VERSION 5.8 ;
BUSBITCHARS "[]" ;
DIVIDERCHAR "/" ;
UNITS
    DATABASE MICRONS 1000 ;
END UNITS

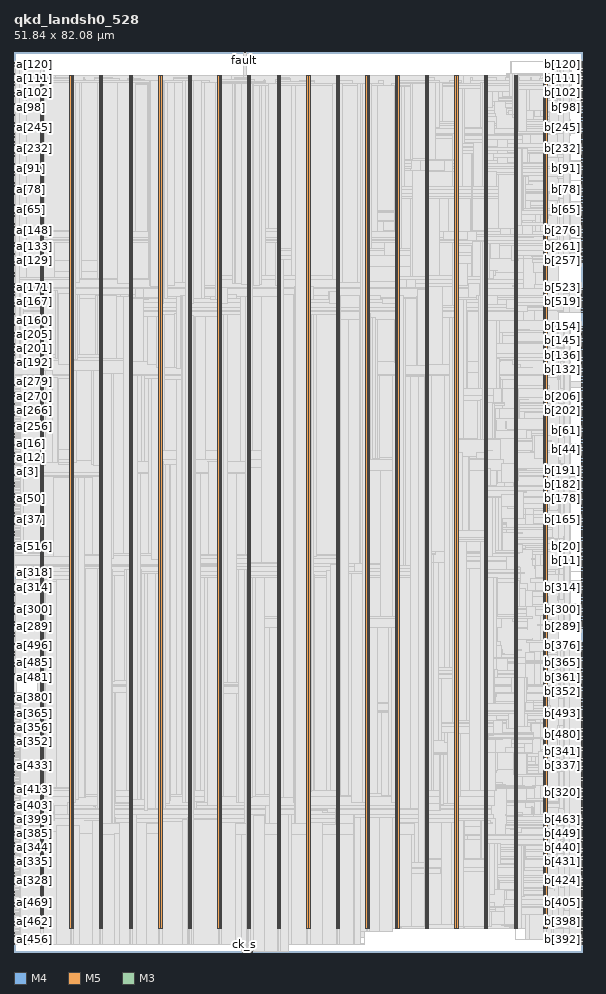
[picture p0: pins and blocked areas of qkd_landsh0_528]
MACRO qkd_landsh0_528
  FOREIGN qkd_landsh0_528 0 0 ;
  CLASS BLOCK ;
  SIZE 51.84 BY 82.08 ;
  PIN a[0]
    DIRECTION INPUT ;
    USE SIGNAL ;
    PORT
      LAYER M4 ;
        RECT  0 43.344 0.084 43.368 ;
    END
  END a[0]
  PIN a[100]
    DIRECTION INPUT ;
    USE SIGNAL ;
    PORT
      LAYER M4 ;
        RECT  0 77.328 0.084 77.352 ;
    END
  END a[100]
  PIN a[101]
    DIRECTION INPUT ;
    USE SIGNAL ;
    PORT
      LAYER M4 ;
        RECT  0 77.472 0.084 77.496 ;
    END
  END a[101]
  PIN a[102]
    DIRECTION INPUT ;
    USE SIGNAL ;
    PORT
      LAYER M4 ;
        RECT  0 77.616 0.084 77.64 ;
    END
  END a[102]
  PIN a[103]
    DIRECTION INPUT ;
    USE SIGNAL ;
    PORT
      LAYER M4 ;
        RECT  0 77.76 0.084 77.784 ;
    END
  END a[103]
  PIN a[104]
    DIRECTION INPUT ;
    USE SIGNAL ;
    PORT
      LAYER M4 ;
        RECT  0 77.904 0.084 77.928 ;
    END
  END a[104]
  PIN a[105]
    DIRECTION INPUT ;
    USE SIGNAL ;
    PORT
      LAYER M4 ;
        RECT  0 78.048 0.084 78.072 ;
    END
  END a[105]
  PIN a[106]
    DIRECTION INPUT ;
    USE SIGNAL ;
    PORT
      LAYER M4 ;
        RECT  0 78.192 0.084 78.216 ;
    END
  END a[106]
  PIN a[107]
    DIRECTION INPUT ;
    USE SIGNAL ;
    PORT
      LAYER M4 ;
        RECT  0 78.336 0.084 78.36 ;
    END
  END a[107]
  PIN a[108]
    DIRECTION INPUT ;
    USE SIGNAL ;
    PORT
      LAYER M4 ;
        RECT  0 78.48 0.084 78.504 ;
    END
  END a[108]
  PIN a[109]
    DIRECTION INPUT ;
    USE SIGNAL ;
    PORT
      LAYER M4 ;
        RECT  0 78.624 0.084 78.648 ;
    END
  END a[109]
  PIN a[10]
    DIRECTION INPUT ;
    USE SIGNAL ;
    PORT
      LAYER M4 ;
        RECT  0 44.784 0.084 44.808 ;
    END
  END a[10]
  PIN a[110]
    DIRECTION INPUT ;
    USE SIGNAL ;
    PORT
      LAYER M4 ;
        RECT  0 78.768 0.084 78.792 ;
    END
  END a[110]
  PIN a[111]
    DIRECTION INPUT ;
    USE SIGNAL ;
    PORT
      LAYER M4 ;
        RECT  0 78.912 0.084 78.936 ;
    END
  END a[111]
  PIN a[112]
    DIRECTION INPUT ;
    USE SIGNAL ;
    PORT
      LAYER M4 ;
        RECT  0 79.056 0.084 79.08 ;
    END
  END a[112]
  PIN a[113]
    DIRECTION INPUT ;
    USE SIGNAL ;
    PORT
      LAYER M4 ;
        RECT  0 79.2 0.084 79.224 ;
    END
  END a[113]
  PIN a[114]
    DIRECTION INPUT ;
    USE SIGNAL ;
    PORT
      LAYER M4 ;
        RECT  0 79.344 0.084 79.368 ;
    END
  END a[114]
  PIN a[115]
    DIRECTION INPUT ;
    USE SIGNAL ;
    PORT
      LAYER M4 ;
        RECT  0 79.488 0.084 79.512 ;
    END
  END a[115]
  PIN a[116]
    DIRECTION INPUT ;
    USE SIGNAL ;
    PORT
      LAYER M4 ;
        RECT  0 79.632 0.084 79.656 ;
    END
  END a[116]
  PIN a[117]
    DIRECTION INPUT ;
    USE SIGNAL ;
    PORT
      LAYER M4 ;
        RECT  0 79.776 0.084 79.8 ;
    END
  END a[117]
  PIN a[118]
    DIRECTION INPUT ;
    USE SIGNAL ;
    PORT
      LAYER M4 ;
        RECT  0 79.92 0.084 79.944 ;
    END
  END a[118]
  PIN a[119]
    DIRECTION INPUT ;
    USE SIGNAL ;
    PORT
      LAYER M4 ;
        RECT  0 80.064 0.084 80.088 ;
    END
  END a[119]
  PIN a[11]
    DIRECTION INPUT ;
    USE SIGNAL ;
    PORT
      LAYER M4 ;
        RECT  0 44.928 0.084 44.952 ;
    END
  END a[11]
  PIN a[120]
    DIRECTION INPUT ;
    USE SIGNAL ;
    PORT
      LAYER M4 ;
        RECT  0 80.208 0.084 80.232 ;
    END
  END a[120]
  PIN a[121]
    DIRECTION INPUT ;
    USE SIGNAL ;
    PORT
      LAYER M4 ;
        RECT  0 80.352 0.084 80.376 ;
    END
  END a[121]
  PIN a[122]
    DIRECTION INPUT ;
    USE SIGNAL ;
    PORT
      LAYER M4 ;
        RECT  0 80.496 0.084 80.52 ;
    END
  END a[122]
  PIN a[123]
    DIRECTION INPUT ;
    USE SIGNAL ;
    PORT
      LAYER M4 ;
        RECT  0 80.64 0.084 80.664 ;
    END
  END a[123]
  PIN a[124]
    DIRECTION INPUT ;
    USE SIGNAL ;
    PORT
      LAYER M4 ;
        RECT  0 80.784 0.084 80.808 ;
    END
  END a[124]
  PIN a[125]
    DIRECTION INPUT ;
    USE SIGNAL ;
    PORT
      LAYER M4 ;
        RECT  0 80.928 0.084 80.952 ;
    END
  END a[125]
  PIN a[126]
    DIRECTION INPUT ;
    USE SIGNAL ;
    PORT
      LAYER M4 ;
        RECT  0 81.072 0.084 81.096 ;
    END
  END a[126]
  PIN a[127]
    DIRECTION INPUT ;
    USE SIGNAL ;
    PORT
      LAYER M4 ;
        RECT  0 81.216 0.084 81.24 ;
    END
  END a[127]
  PIN a[128]
    DIRECTION INPUT ;
    USE SIGNAL ;
    PORT
      LAYER M4 ;
        RECT  0 62.928 0.084 62.952 ;
    END
  END a[128]
  PIN a[129]
    DIRECTION INPUT ;
    USE SIGNAL ;
    PORT
      LAYER M4 ;
        RECT  0 63.072 0.084 63.096 ;
    END
  END a[129]
  PIN a[12]
    DIRECTION INPUT ;
    USE SIGNAL ;
    PORT
      LAYER M4 ;
        RECT  0 45.072 0.084 45.096 ;
    END
  END a[12]
  PIN a[130]
    DIRECTION INPUT ;
    USE SIGNAL ;
    PORT
      LAYER M4 ;
        RECT  0 63.216 0.084 63.24 ;
    END
  END a[130]
  PIN a[131]
    DIRECTION INPUT ;
    USE SIGNAL ;
    PORT
      LAYER M4 ;
        RECT  0 63.36 0.084 63.384 ;
    END
  END a[131]
  PIN a[132]
    DIRECTION INPUT ;
    USE SIGNAL ;
    PORT
      LAYER M4 ;
        RECT  0 63.504 0.084 63.528 ;
    END
  END a[132]
  PIN a[133]
    DIRECTION INPUT ;
    USE SIGNAL ;
    PORT
      LAYER M4 ;
        RECT  0 63.648 0.084 63.672 ;
    END
  END a[133]
  PIN a[134]
    DIRECTION INPUT ;
    USE SIGNAL ;
    PORT
      LAYER M4 ;
        RECT  0 63.792 0.084 63.816 ;
    END
  END a[134]
  PIN a[135]
    DIRECTION INPUT ;
    USE SIGNAL ;
    PORT
      LAYER M4 ;
        RECT  0 63.936 0.084 63.96 ;
    END
  END a[135]
  PIN a[136]
    DIRECTION INPUT ;
    USE SIGNAL ;
    PORT
      LAYER M4 ;
        RECT  0 64.08 0.084 64.104 ;
    END
  END a[136]
  PIN a[137]
    DIRECTION INPUT ;
    USE SIGNAL ;
    PORT
      LAYER M4 ;
        RECT  0 64.224 0.084 64.248 ;
    END
  END a[137]
  PIN a[138]
    DIRECTION INPUT ;
    USE SIGNAL ;
    PORT
      LAYER M4 ;
        RECT  0 64.368 0.084 64.392 ;
    END
  END a[138]
  PIN a[139]
    DIRECTION INPUT ;
    USE SIGNAL ;
    PORT
      LAYER M4 ;
        RECT  0 64.512 0.084 64.536 ;
    END
  END a[139]
  PIN a[13]
    DIRECTION INPUT ;
    USE SIGNAL ;
    PORT
      LAYER M4 ;
        RECT  0 45.216 0.084 45.24 ;
    END
  END a[13]
  PIN a[140]
    DIRECTION INPUT ;
    USE SIGNAL ;
    PORT
      LAYER M4 ;
        RECT  0 64.656 0.084 64.68 ;
    END
  END a[140]
  PIN a[141]
    DIRECTION INPUT ;
    USE SIGNAL ;
    PORT
      LAYER M4 ;
        RECT  0 64.8 0.084 64.824 ;
    END
  END a[141]
  PIN a[142]
    DIRECTION INPUT ;
    USE SIGNAL ;
    PORT
      LAYER M4 ;
        RECT  0 64.944 0.084 64.968 ;
    END
  END a[142]
  PIN a[143]
    DIRECTION INPUT ;
    USE SIGNAL ;
    PORT
      LAYER M4 ;
        RECT  0 65.088 0.084 65.112 ;
    END
  END a[143]
  PIN a[144]
    DIRECTION INPUT ;
    USE SIGNAL ;
    PORT
      LAYER M4 ;
        RECT  0 65.232 0.084 65.256 ;
    END
  END a[144]
  PIN a[145]
    DIRECTION INPUT ;
    USE SIGNAL ;
    PORT
      LAYER M4 ;
        RECT  0 65.376 0.084 65.4 ;
    END
  END a[145]
  PIN a[146]
    DIRECTION INPUT ;
    USE SIGNAL ;
    PORT
      LAYER M4 ;
        RECT  0 65.52 0.084 65.544 ;
    END
  END a[146]
  PIN a[147]
    DIRECTION INPUT ;
    USE SIGNAL ;
    PORT
      LAYER M4 ;
        RECT  0 65.664 0.084 65.688 ;
    END
  END a[147]
  PIN a[148]
    DIRECTION INPUT ;
    USE SIGNAL ;
    PORT
      LAYER M4 ;
        RECT  0 65.808 0.084 65.832 ;
    END
  END a[148]
  PIN a[149]
    DIRECTION INPUT ;
    USE SIGNAL ;
    PORT
      LAYER M4 ;
        RECT  0 65.952 0.084 65.976 ;
    END
  END a[149]
  PIN a[14]
    DIRECTION INPUT ;
    USE SIGNAL ;
    PORT
      LAYER M4 ;
        RECT  0 45.36 0.084 45.384 ;
    END
  END a[14]
  PIN a[150]
    DIRECTION INPUT ;
    USE SIGNAL ;
    PORT
      LAYER M4 ;
        RECT  0 66.096 0.084 66.12 ;
    END
  END a[150]
  PIN a[151]
    DIRECTION INPUT ;
    USE SIGNAL ;
    PORT
      LAYER M4 ;
        RECT  0 66.24 0.084 66.264 ;
    END
  END a[151]
  PIN a[152]
    DIRECTION INPUT ;
    USE SIGNAL ;
    PORT
      LAYER M4 ;
        RECT  0 66.384 0.084 66.408 ;
    END
  END a[152]
  PIN a[153]
    DIRECTION INPUT ;
    USE SIGNAL ;
    PORT
      LAYER M4 ;
        RECT  0 66.528 0.084 66.552 ;
    END
  END a[153]
  PIN a[154]
    DIRECTION INPUT ;
    USE SIGNAL ;
    PORT
      LAYER M4 ;
        RECT  0 66.672 0.084 66.696 ;
    END
  END a[154]
  PIN a[155]
    DIRECTION INPUT ;
    USE SIGNAL ;
    PORT
      LAYER M4 ;
        RECT  0 66.816 0.084 66.84 ;
    END
  END a[155]
  PIN a[156]
    DIRECTION INPUT ;
    USE SIGNAL ;
    PORT
      LAYER M4 ;
        RECT  0 66.96 0.084 66.984 ;
    END
  END a[156]
  PIN a[157]
    DIRECTION INPUT ;
    USE SIGNAL ;
    PORT
      LAYER M4 ;
        RECT  0 67.104 0.084 67.128 ;
    END
  END a[157]
  PIN a[158]
    DIRECTION INPUT ;
    USE SIGNAL ;
    PORT
      LAYER M4 ;
        RECT  0 67.248 0.084 67.272 ;
    END
  END a[158]
  PIN a[159]
    DIRECTION INPUT ;
    USE SIGNAL ;
    PORT
      LAYER M4 ;
        RECT  0 67.392 0.084 67.416 ;
    END
  END a[159]
  PIN a[15]
    DIRECTION INPUT ;
    USE SIGNAL ;
    PORT
      LAYER M4 ;
        RECT  0 45.504 0.084 45.528 ;
    END
  END a[15]
  PIN a[160]
    DIRECTION INPUT ;
    USE SIGNAL ;
    PORT
      LAYER M4 ;
        RECT  0 58.32 0.084 58.344 ;
    END
  END a[160]
  PIN a[161]
    DIRECTION INPUT ;
    USE SIGNAL ;
    PORT
      LAYER M4 ;
        RECT  0 58.464 0.084 58.488 ;
    END
  END a[161]
  PIN a[162]
    DIRECTION INPUT ;
    USE SIGNAL ;
    PORT
      LAYER M4 ;
        RECT  0 58.608 0.084 58.632 ;
    END
  END a[162]
  PIN a[163]
    DIRECTION INPUT ;
    USE SIGNAL ;
    PORT
      LAYER M4 ;
        RECT  0 58.752 0.084 58.776 ;
    END
  END a[163]
  PIN a[164]
    DIRECTION INPUT ;
    USE SIGNAL ;
    PORT
      LAYER M4 ;
        RECT  0 58.896 0.084 58.92 ;
    END
  END a[164]
  PIN a[165]
    DIRECTION INPUT ;
    USE SIGNAL ;
    PORT
      LAYER M4 ;
        RECT  0 59.04 0.084 59.064 ;
    END
  END a[165]
  PIN a[166]
    DIRECTION INPUT ;
    USE SIGNAL ;
    PORT
      LAYER M4 ;
        RECT  0 59.184 0.084 59.208 ;
    END
  END a[166]
  PIN a[167]
    DIRECTION INPUT ;
    USE SIGNAL ;
    PORT
      LAYER M4 ;
        RECT  0 59.328 0.084 59.352 ;
    END
  END a[167]
  PIN a[168]
    DIRECTION INPUT ;
    USE SIGNAL ;
    PORT
      LAYER M4 ;
        RECT  0 59.472 0.084 59.496 ;
    END
  END a[168]
  PIN a[169]
    DIRECTION INPUT ;
    USE SIGNAL ;
    PORT
      LAYER M4 ;
        RECT  0 59.616 0.084 59.64 ;
    END
  END a[169]
  PIN a[16]
    DIRECTION INPUT ;
    USE SIGNAL ;
    PORT
      LAYER M4 ;
        RECT  0 45.648 0.084 45.672 ;
    END
  END a[16]
  PIN a[170]
    DIRECTION INPUT ;
    USE SIGNAL ;
    PORT
      LAYER M4 ;
        RECT  0 59.76 0.084 59.784 ;
    END
  END a[170]
  PIN a[171]
    DIRECTION INPUT ;
    USE SIGNAL ;
    PORT
      LAYER M4 ;
        RECT  0 59.904 0.084 59.928 ;
    END
  END a[171]
  PIN a[172]
    DIRECTION INPUT ;
    USE SIGNAL ;
    PORT
      LAYER M4 ;
        RECT  0 60.048 0.084 60.072 ;
    END
  END a[172]
  PIN a[173]
    DIRECTION INPUT ;
    USE SIGNAL ;
    PORT
      LAYER M4 ;
        RECT  0 60.192 0.084 60.216 ;
    END
  END a[173]
  PIN a[174]
    DIRECTION INPUT ;
    USE SIGNAL ;
    PORT
      LAYER M4 ;
        RECT  0 60.336 0.084 60.36 ;
    END
  END a[174]
  PIN a[175]
    DIRECTION INPUT ;
    USE SIGNAL ;
    PORT
      LAYER M4 ;
        RECT  0 60.48 0.084 60.504 ;
    END
  END a[175]
  PIN a[176]
    DIRECTION INPUT ;
    USE SIGNAL ;
    PORT
      LAYER M4 ;
        RECT  0 60.624 0.084 60.648 ;
    END
  END a[176]
  PIN a[177]
    DIRECTION INPUT ;
    USE SIGNAL ;
    PORT
      LAYER M4 ;
        RECT  0 60.768 0.084 60.792 ;
    END
  END a[177]
  PIN a[178]
    DIRECTION INPUT ;
    USE SIGNAL ;
    PORT
      LAYER M4 ;
        RECT  0 60.912 0.084 60.936 ;
    END
  END a[178]
  PIN a[179]
    DIRECTION INPUT ;
    USE SIGNAL ;
    PORT
      LAYER M4 ;
        RECT  0 61.056 0.084 61.08 ;
    END
  END a[179]
  PIN a[17]
    DIRECTION INPUT ;
    USE SIGNAL ;
    PORT
      LAYER M4 ;
        RECT  0 45.792 0.084 45.816 ;
    END
  END a[17]
  PIN a[180]
    DIRECTION INPUT ;
    USE SIGNAL ;
    PORT
      LAYER M4 ;
        RECT  0 61.2 0.084 61.224 ;
    END
  END a[180]
  PIN a[181]
    DIRECTION INPUT ;
    USE SIGNAL ;
    PORT
      LAYER M4 ;
        RECT  0 61.344 0.084 61.368 ;
    END
  END a[181]
  PIN a[182]
    DIRECTION INPUT ;
    USE SIGNAL ;
    PORT
      LAYER M4 ;
        RECT  0 61.488 0.084 61.512 ;
    END
  END a[182]
  PIN a[183]
    DIRECTION INPUT ;
    USE SIGNAL ;
    PORT
      LAYER M4 ;
        RECT  0 61.632 0.084 61.656 ;
    END
  END a[183]
  PIN a[184]
    DIRECTION INPUT ;
    USE SIGNAL ;
    PORT
      LAYER M4 ;
        RECT  0 61.776 0.084 61.8 ;
    END
  END a[184]
  PIN a[185]
    DIRECTION INPUT ;
    USE SIGNAL ;
    PORT
      LAYER M4 ;
        RECT  0 61.92 0.084 61.944 ;
    END
  END a[185]
  PIN a[186]
    DIRECTION INPUT ;
    USE SIGNAL ;
    PORT
      LAYER M4 ;
        RECT  0 62.064 0.084 62.088 ;
    END
  END a[186]
  PIN a[187]
    DIRECTION INPUT ;
    USE SIGNAL ;
    PORT
      LAYER M4 ;
        RECT  0 62.208 0.084 62.232 ;
    END
  END a[187]
  PIN a[188]
    DIRECTION INPUT ;
    USE SIGNAL ;
    PORT
      LAYER M4 ;
        RECT  0 62.352 0.084 62.376 ;
    END
  END a[188]
  PIN a[189]
    DIRECTION INPUT ;
    USE SIGNAL ;
    PORT
      LAYER M4 ;
        RECT  0 62.496 0.084 62.52 ;
    END
  END a[189]
  PIN a[18]
    DIRECTION INPUT ;
    USE SIGNAL ;
    PORT
      LAYER M4 ;
        RECT  0 45.936 0.084 45.96 ;
    END
  END a[18]
  PIN a[190]
    DIRECTION INPUT ;
    USE SIGNAL ;
    PORT
      LAYER M4 ;
        RECT  0 62.64 0.084 62.664 ;
    END
  END a[190]
  PIN a[191]
    DIRECTION INPUT ;
    USE SIGNAL ;
    PORT
      LAYER M4 ;
        RECT  0 62.784 0.084 62.808 ;
    END
  END a[191]
  PIN a[192]
    DIRECTION INPUT ;
    USE SIGNAL ;
    PORT
      LAYER M4 ;
        RECT  0 53.712 0.084 53.736 ;
    END
  END a[192]
  PIN a[193]
    DIRECTION INPUT ;
    USE SIGNAL ;
    PORT
      LAYER M4 ;
        RECT  0 53.856 0.084 53.88 ;
    END
  END a[193]
  PIN a[194]
    DIRECTION INPUT ;
    USE SIGNAL ;
    PORT
      LAYER M4 ;
        RECT  0 54 0.084 54.024 ;
    END
  END a[194]
  PIN a[195]
    DIRECTION INPUT ;
    USE SIGNAL ;
    PORT
      LAYER M4 ;
        RECT  0 54.144 0.084 54.168 ;
    END
  END a[195]
  PIN a[196]
    DIRECTION INPUT ;
    USE SIGNAL ;
    PORT
      LAYER M4 ;
        RECT  0 54.288 0.084 54.312 ;
    END
  END a[196]
  PIN a[197]
    DIRECTION INPUT ;
    USE SIGNAL ;
    PORT
      LAYER M4 ;
        RECT  0 54.432 0.084 54.456 ;
    END
  END a[197]
  PIN a[198]
    DIRECTION INPUT ;
    USE SIGNAL ;
    PORT
      LAYER M4 ;
        RECT  0 54.576 0.084 54.6 ;
    END
  END a[198]
  PIN a[199]
    DIRECTION INPUT ;
    USE SIGNAL ;
    PORT
      LAYER M4 ;
        RECT  0 54.72 0.084 54.744 ;
    END
  END a[199]
  PIN a[19]
    DIRECTION INPUT ;
    USE SIGNAL ;
    PORT
      LAYER M4 ;
        RECT  0 46.08 0.084 46.104 ;
    END
  END a[19]
  PIN a[1]
    DIRECTION INPUT ;
    USE SIGNAL ;
    PORT
      LAYER M4 ;
        RECT  0 43.488 0.084 43.512 ;
    END
  END a[1]
  PIN a[200]
    DIRECTION INPUT ;
    USE SIGNAL ;
    PORT
      LAYER M4 ;
        RECT  0 54.864 0.084 54.888 ;
    END
  END a[200]
  PIN a[201]
    DIRECTION INPUT ;
    USE SIGNAL ;
    PORT
      LAYER M4 ;
        RECT  0 55.008 0.084 55.032 ;
    END
  END a[201]
  PIN a[202]
    DIRECTION INPUT ;
    USE SIGNAL ;
    PORT
      LAYER M4 ;
        RECT  0 55.152 0.084 55.176 ;
    END
  END a[202]
  PIN a[203]
    DIRECTION INPUT ;
    USE SIGNAL ;
    PORT
      LAYER M4 ;
        RECT  0 55.296 0.084 55.32 ;
    END
  END a[203]
  PIN a[204]
    DIRECTION INPUT ;
    USE SIGNAL ;
    PORT
      LAYER M4 ;
        RECT  0 55.44 0.084 55.464 ;
    END
  END a[204]
  PIN a[205]
    DIRECTION INPUT ;
    USE SIGNAL ;
    PORT
      LAYER M4 ;
        RECT  0 55.584 0.084 55.608 ;
    END
  END a[205]
  PIN a[206]
    DIRECTION INPUT ;
    USE SIGNAL ;
    PORT
      LAYER M4 ;
        RECT  0 55.728 0.084 55.752 ;
    END
  END a[206]
  PIN a[207]
    DIRECTION INPUT ;
    USE SIGNAL ;
    PORT
      LAYER M4 ;
        RECT  0 55.872 0.084 55.896 ;
    END
  END a[207]
  PIN a[208]
    DIRECTION INPUT ;
    USE SIGNAL ;
    PORT
      LAYER M4 ;
        RECT  0 56.016 0.084 56.04 ;
    END
  END a[208]
  PIN a[209]
    DIRECTION INPUT ;
    USE SIGNAL ;
    PORT
      LAYER M4 ;
        RECT  0 56.16 0.084 56.184 ;
    END
  END a[209]
  PIN a[20]
    DIRECTION INPUT ;
    USE SIGNAL ;
    PORT
      LAYER M4 ;
        RECT  0 46.224 0.084 46.248 ;
    END
  END a[20]
  PIN a[210]
    DIRECTION INPUT ;
    USE SIGNAL ;
    PORT
      LAYER M4 ;
        RECT  0 56.304 0.084 56.328 ;
    END
  END a[210]
  PIN a[211]
    DIRECTION INPUT ;
    USE SIGNAL ;
    PORT
      LAYER M4 ;
        RECT  0 56.448 0.084 56.472 ;
    END
  END a[211]
  PIN a[212]
    DIRECTION INPUT ;
    USE SIGNAL ;
    PORT
      LAYER M4 ;
        RECT  0 56.592 0.084 56.616 ;
    END
  END a[212]
  PIN a[213]
    DIRECTION INPUT ;
    USE SIGNAL ;
    PORT
      LAYER M4 ;
        RECT  0 56.736 0.084 56.76 ;
    END
  END a[213]
  PIN a[214]
    DIRECTION INPUT ;
    USE SIGNAL ;
    PORT
      LAYER M4 ;
        RECT  0 56.88 0.084 56.904 ;
    END
  END a[214]
  PIN a[215]
    DIRECTION INPUT ;
    USE SIGNAL ;
    PORT
      LAYER M4 ;
        RECT  0 57.024 0.084 57.048 ;
    END
  END a[215]
  PIN a[216]
    DIRECTION INPUT ;
    USE SIGNAL ;
    PORT
      LAYER M4 ;
        RECT  0 57.168 0.084 57.192 ;
    END
  END a[216]
  PIN a[217]
    DIRECTION INPUT ;
    USE SIGNAL ;
    PORT
      LAYER M4 ;
        RECT  0 57.312 0.084 57.336 ;
    END
  END a[217]
  PIN a[218]
    DIRECTION INPUT ;
    USE SIGNAL ;
    PORT
      LAYER M4 ;
        RECT  0 57.456 0.084 57.48 ;
    END
  END a[218]
  PIN a[219]
    DIRECTION INPUT ;
    USE SIGNAL ;
    PORT
      LAYER M4 ;
        RECT  0 57.6 0.084 57.624 ;
    END
  END a[219]
  PIN a[21]
    DIRECTION INPUT ;
    USE SIGNAL ;
    PORT
      LAYER M4 ;
        RECT  0 46.368 0.084 46.392 ;
    END
  END a[21]
  PIN a[220]
    DIRECTION INPUT ;
    USE SIGNAL ;
    PORT
      LAYER M4 ;
        RECT  0 57.744 0.084 57.768 ;
    END
  END a[220]
  PIN a[221]
    DIRECTION INPUT ;
    USE SIGNAL ;
    PORT
      LAYER M4 ;
        RECT  0 57.888 0.084 57.912 ;
    END
  END a[221]
  PIN a[222]
    DIRECTION INPUT ;
    USE SIGNAL ;
    PORT
      LAYER M4 ;
        RECT  0 58.032 0.084 58.056 ;
    END
  END a[222]
  PIN a[223]
    DIRECTION INPUT ;
    USE SIGNAL ;
    PORT
      LAYER M4 ;
        RECT  0 58.176 0.084 58.2 ;
    END
  END a[223]
  PIN a[224]
    DIRECTION INPUT ;
    USE SIGNAL ;
    PORT
      LAYER M4 ;
        RECT  0 72.144 0.084 72.168 ;
    END
  END a[224]
  PIN a[225]
    DIRECTION INPUT ;
    USE SIGNAL ;
    PORT
      LAYER M4 ;
        RECT  0 72.288 0.084 72.312 ;
    END
  END a[225]
  PIN a[226]
    DIRECTION INPUT ;
    USE SIGNAL ;
    PORT
      LAYER M4 ;
        RECT  0 72.432 0.084 72.456 ;
    END
  END a[226]
  PIN a[227]
    DIRECTION INPUT ;
    USE SIGNAL ;
    PORT
      LAYER M4 ;
        RECT  0 72.576 0.084 72.6 ;
    END
  END a[227]
  PIN a[228]
    DIRECTION INPUT ;
    USE SIGNAL ;
    PORT
      LAYER M4 ;
        RECT  0 72.72 0.084 72.744 ;
    END
  END a[228]
  PIN a[229]
    DIRECTION INPUT ;
    USE SIGNAL ;
    PORT
      LAYER M4 ;
        RECT  0 72.864 0.084 72.888 ;
    END
  END a[229]
  PIN a[22]
    DIRECTION INPUT ;
    USE SIGNAL ;
    PORT
      LAYER M4 ;
        RECT  0 46.512 0.084 46.536 ;
    END
  END a[22]
  PIN a[230]
    DIRECTION INPUT ;
    USE SIGNAL ;
    PORT
      LAYER M4 ;
        RECT  0 73.008 0.084 73.032 ;
    END
  END a[230]
  PIN a[231]
    DIRECTION INPUT ;
    USE SIGNAL ;
    PORT
      LAYER M4 ;
        RECT  0 73.152 0.084 73.176 ;
    END
  END a[231]
  PIN a[232]
    DIRECTION INPUT ;
    USE SIGNAL ;
    PORT
      LAYER M4 ;
        RECT  0 73.296 0.084 73.32 ;
    END
  END a[232]
  PIN a[233]
    DIRECTION INPUT ;
    USE SIGNAL ;
    PORT
      LAYER M4 ;
        RECT  0 73.44 0.084 73.464 ;
    END
  END a[233]
  PIN a[234]
    DIRECTION INPUT ;
    USE SIGNAL ;
    PORT
      LAYER M4 ;
        RECT  0 73.584 0.084 73.608 ;
    END
  END a[234]
  PIN a[235]
    DIRECTION INPUT ;
    USE SIGNAL ;
    PORT
      LAYER M4 ;
        RECT  0 73.728 0.084 73.752 ;
    END
  END a[235]
  PIN a[236]
    DIRECTION INPUT ;
    USE SIGNAL ;
    PORT
      LAYER M4 ;
        RECT  0 73.872 0.084 73.896 ;
    END
  END a[236]
  PIN a[237]
    DIRECTION INPUT ;
    USE SIGNAL ;
    PORT
      LAYER M4 ;
        RECT  0 74.016 0.084 74.04 ;
    END
  END a[237]
  PIN a[238]
    DIRECTION INPUT ;
    USE SIGNAL ;
    PORT
      LAYER M4 ;
        RECT  0 74.16 0.084 74.184 ;
    END
  END a[238]
  PIN a[239]
    DIRECTION INPUT ;
    USE SIGNAL ;
    PORT
      LAYER M4 ;
        RECT  0 74.304 0.084 74.328 ;
    END
  END a[239]
  PIN a[23]
    DIRECTION INPUT ;
    USE SIGNAL ;
    PORT
      LAYER M4 ;
        RECT  0 46.656 0.084 46.68 ;
    END
  END a[23]
  PIN a[240]
    DIRECTION INPUT ;
    USE SIGNAL ;
    PORT
      LAYER M4 ;
        RECT  0 74.448 0.084 74.472 ;
    END
  END a[240]
  PIN a[241]
    DIRECTION INPUT ;
    USE SIGNAL ;
    PORT
      LAYER M4 ;
        RECT  0 74.592 0.084 74.616 ;
    END
  END a[241]
  PIN a[242]
    DIRECTION INPUT ;
    USE SIGNAL ;
    PORT
      LAYER M4 ;
        RECT  0 74.736 0.084 74.76 ;
    END
  END a[242]
  PIN a[243]
    DIRECTION INPUT ;
    USE SIGNAL ;
    PORT
      LAYER M4 ;
        RECT  0 74.88 0.084 74.904 ;
    END
  END a[243]
  PIN a[244]
    DIRECTION INPUT ;
    USE SIGNAL ;
    PORT
      LAYER M4 ;
        RECT  0 75.024 0.084 75.048 ;
    END
  END a[244]
  PIN a[245]
    DIRECTION INPUT ;
    USE SIGNAL ;
    PORT
      LAYER M4 ;
        RECT  0 75.168 0.084 75.192 ;
    END
  END a[245]
  PIN a[246]
    DIRECTION INPUT ;
    USE SIGNAL ;
    PORT
      LAYER M4 ;
        RECT  0 75.312 0.084 75.336 ;
    END
  END a[246]
  PIN a[247]
    DIRECTION INPUT ;
    USE SIGNAL ;
    PORT
      LAYER M4 ;
        RECT  0 75.456 0.084 75.48 ;
    END
  END a[247]
  PIN a[248]
    DIRECTION INPUT ;
    USE SIGNAL ;
    PORT
      LAYER M4 ;
        RECT  0 75.6 0.084 75.624 ;
    END
  END a[248]
  PIN a[249]
    DIRECTION INPUT ;
    USE SIGNAL ;
    PORT
      LAYER M4 ;
        RECT  0 75.744 0.084 75.768 ;
    END
  END a[249]
  PIN a[24]
    DIRECTION INPUT ;
    USE SIGNAL ;
    PORT
      LAYER M4 ;
        RECT  0 46.8 0.084 46.824 ;
    END
  END a[24]
  PIN a[250]
    DIRECTION INPUT ;
    USE SIGNAL ;
    PORT
      LAYER M4 ;
        RECT  0 75.888 0.084 75.912 ;
    END
  END a[250]
  PIN a[251]
    DIRECTION INPUT ;
    USE SIGNAL ;
    PORT
      LAYER M4 ;
        RECT  0 76.032 0.084 76.056 ;
    END
  END a[251]
  PIN a[252]
    DIRECTION INPUT ;
    USE SIGNAL ;
    PORT
      LAYER M4 ;
        RECT  0 76.176 0.084 76.2 ;
    END
  END a[252]
  PIN a[253]
    DIRECTION INPUT ;
    USE SIGNAL ;
    PORT
      LAYER M4 ;
        RECT  0 76.32 0.084 76.344 ;
    END
  END a[253]
  PIN a[254]
    DIRECTION INPUT ;
    USE SIGNAL ;
    PORT
      LAYER M4 ;
        RECT  0 76.464 0.084 76.488 ;
    END
  END a[254]
  PIN a[255]
    DIRECTION INPUT ;
    USE SIGNAL ;
    PORT
      LAYER M4 ;
        RECT  0 76.608 0.084 76.632 ;
    END
  END a[255]
  PIN a[256]
    DIRECTION INPUT ;
    USE SIGNAL ;
    PORT
      LAYER M4 ;
        RECT  0 47.952 0.084 47.976 ;
    END
  END a[256]
  PIN a[257]
    DIRECTION INPUT ;
    USE SIGNAL ;
    PORT
      LAYER M4 ;
        RECT  0 48.096 0.084 48.12 ;
    END
  END a[257]
  PIN a[258]
    DIRECTION INPUT ;
    USE SIGNAL ;
    PORT
      LAYER M4 ;
        RECT  0 48.24 0.084 48.264 ;
    END
  END a[258]
  PIN a[259]
    DIRECTION INPUT ;
    USE SIGNAL ;
    PORT
      LAYER M4 ;
        RECT  0 48.384 0.084 48.408 ;
    END
  END a[259]
  PIN a[25]
    DIRECTION INPUT ;
    USE SIGNAL ;
    PORT
      LAYER M4 ;
        RECT  0 46.944 0.084 46.968 ;
    END
  END a[25]
  PIN a[260]
    DIRECTION INPUT ;
    USE SIGNAL ;
    PORT
      LAYER M4 ;
        RECT  0 48.528 0.084 48.552 ;
    END
  END a[260]
  PIN a[261]
    DIRECTION INPUT ;
    USE SIGNAL ;
    PORT
      LAYER M4 ;
        RECT  0 48.672 0.084 48.696 ;
    END
  END a[261]
  PIN a[262]
    DIRECTION INPUT ;
    USE SIGNAL ;
    PORT
      LAYER M4 ;
        RECT  0 48.816 0.084 48.84 ;
    END
  END a[262]
  PIN a[263]
    DIRECTION INPUT ;
    USE SIGNAL ;
    PORT
      LAYER M4 ;
        RECT  0 48.96 0.084 48.984 ;
    END
  END a[263]
  PIN a[264]
    DIRECTION INPUT ;
    USE SIGNAL ;
    PORT
      LAYER M4 ;
        RECT  0 49.104 0.084 49.128 ;
    END
  END a[264]
  PIN a[265]
    DIRECTION INPUT ;
    USE SIGNAL ;
    PORT
      LAYER M4 ;
        RECT  0 49.248 0.084 49.272 ;
    END
  END a[265]
  PIN a[266]
    DIRECTION INPUT ;
    USE SIGNAL ;
    PORT
      LAYER M4 ;
        RECT  0 49.392 0.084 49.416 ;
    END
  END a[266]
  PIN a[267]
    DIRECTION INPUT ;
    USE SIGNAL ;
    PORT
      LAYER M4 ;
        RECT  0 49.536 0.084 49.56 ;
    END
  END a[267]
  PIN a[268]
    DIRECTION INPUT ;
    USE SIGNAL ;
    PORT
      LAYER M4 ;
        RECT  0 49.68 0.084 49.704 ;
    END
  END a[268]
  PIN a[269]
    DIRECTION INPUT ;
    USE SIGNAL ;
    PORT
      LAYER M4 ;
        RECT  0 49.824 0.084 49.848 ;
    END
  END a[269]
  PIN a[26]
    DIRECTION INPUT ;
    USE SIGNAL ;
    PORT
      LAYER M4 ;
        RECT  0 47.088 0.084 47.112 ;
    END
  END a[26]
  PIN a[270]
    DIRECTION INPUT ;
    USE SIGNAL ;
    PORT
      LAYER M4 ;
        RECT  0 49.968 0.084 49.992 ;
    END
  END a[270]
  PIN a[271]
    DIRECTION INPUT ;
    USE SIGNAL ;
    PORT
      LAYER M4 ;
        RECT  0 50.112 0.084 50.136 ;
    END
  END a[271]
  PIN a[272]
    DIRECTION INPUT ;
    USE SIGNAL ;
    PORT
      LAYER M4 ;
        RECT  0 50.256 0.084 50.28 ;
    END
  END a[272]
  PIN a[273]
    DIRECTION INPUT ;
    USE SIGNAL ;
    PORT
      LAYER M4 ;
        RECT  0 50.4 0.084 50.424 ;
    END
  END a[273]
  PIN a[274]
    DIRECTION INPUT ;
    USE SIGNAL ;
    PORT
      LAYER M4 ;
        RECT  0 50.544 0.084 50.568 ;
    END
  END a[274]
  PIN a[275]
    DIRECTION INPUT ;
    USE SIGNAL ;
    PORT
      LAYER M4 ;
        RECT  0 50.688 0.084 50.712 ;
    END
  END a[275]
  PIN a[276]
    DIRECTION INPUT ;
    USE SIGNAL ;
    PORT
      LAYER M4 ;
        RECT  0 50.832 0.084 50.856 ;
    END
  END a[276]
  PIN a[277]
    DIRECTION INPUT ;
    USE SIGNAL ;
    PORT
      LAYER M4 ;
        RECT  0 50.976 0.084 51 ;
    END
  END a[277]
  PIN a[278]
    DIRECTION INPUT ;
    USE SIGNAL ;
    PORT
      LAYER M4 ;
        RECT  0 51.12 0.084 51.144 ;
    END
  END a[278]
  PIN a[279]
    DIRECTION INPUT ;
    USE SIGNAL ;
    PORT
      LAYER M4 ;
        RECT  0 51.264 0.084 51.288 ;
    END
  END a[279]
  PIN a[27]
    DIRECTION INPUT ;
    USE SIGNAL ;
    PORT
      LAYER M4 ;
        RECT  0 47.232 0.084 47.256 ;
    END
  END a[27]
  PIN a[280]
    DIRECTION INPUT ;
    USE SIGNAL ;
    PORT
      LAYER M4 ;
        RECT  0 51.408 0.084 51.432 ;
    END
  END a[280]
  PIN a[281]
    DIRECTION INPUT ;
    USE SIGNAL ;
    PORT
      LAYER M4 ;
        RECT  0 51.552 0.084 51.576 ;
    END
  END a[281]
  PIN a[282]
    DIRECTION INPUT ;
    USE SIGNAL ;
    PORT
      LAYER M4 ;
        RECT  0 51.696 0.084 51.72 ;
    END
  END a[282]
  PIN a[283]
    DIRECTION INPUT ;
    USE SIGNAL ;
    PORT
      LAYER M4 ;
        RECT  0 51.84 0.084 51.864 ;
    END
  END a[283]
  PIN a[284]
    DIRECTION INPUT ;
    USE SIGNAL ;
    PORT
      LAYER M4 ;
        RECT  0 51.984 0.084 52.008 ;
    END
  END a[284]
  PIN a[285]
    DIRECTION INPUT ;
    USE SIGNAL ;
    PORT
      LAYER M4 ;
        RECT  0 52.128 0.084 52.152 ;
    END
  END a[285]
  PIN a[286]
    DIRECTION INPUT ;
    USE SIGNAL ;
    PORT
      LAYER M4 ;
        RECT  0 52.272 0.084 52.296 ;
    END
  END a[286]
  PIN a[287]
    DIRECTION INPUT ;
    USE SIGNAL ;
    PORT
      LAYER M4 ;
        RECT  0 52.416 0.084 52.44 ;
    END
  END a[287]
  PIN a[288]
    DIRECTION INPUT ;
    USE SIGNAL ;
    PORT
      LAYER M4 ;
        RECT  0 29.52 0.084 29.544 ;
    END
  END a[288]
  PIN a[289]
    DIRECTION INPUT ;
    USE SIGNAL ;
    PORT
      LAYER M4 ;
        RECT  0 29.664 0.084 29.688 ;
    END
  END a[289]
  PIN a[28]
    DIRECTION INPUT ;
    USE SIGNAL ;
    PORT
      LAYER M4 ;
        RECT  0 47.376 0.084 47.4 ;
    END
  END a[28]
  PIN a[290]
    DIRECTION INPUT ;
    USE SIGNAL ;
    PORT
      LAYER M4 ;
        RECT  0 29.808 0.084 29.832 ;
    END
  END a[290]
  PIN a[291]
    DIRECTION INPUT ;
    USE SIGNAL ;
    PORT
      LAYER M4 ;
        RECT  0 29.952 0.084 29.976 ;
    END
  END a[291]
  PIN a[292]
    DIRECTION INPUT ;
    USE SIGNAL ;
    PORT
      LAYER M4 ;
        RECT  0 30.096 0.084 30.12 ;
    END
  END a[292]
  PIN a[293]
    DIRECTION INPUT ;
    USE SIGNAL ;
    PORT
      LAYER M4 ;
        RECT  0 30.24 0.084 30.264 ;
    END
  END a[293]
  PIN a[294]
    DIRECTION INPUT ;
    USE SIGNAL ;
    PORT
      LAYER M4 ;
        RECT  0 30.384 0.084 30.408 ;
    END
  END a[294]
  PIN a[295]
    DIRECTION INPUT ;
    USE SIGNAL ;
    PORT
      LAYER M4 ;
        RECT  0 30.528 0.084 30.552 ;
    END
  END a[295]
  PIN a[296]
    DIRECTION INPUT ;
    USE SIGNAL ;
    PORT
      LAYER M4 ;
        RECT  0 30.672 0.084 30.696 ;
    END
  END a[296]
  PIN a[297]
    DIRECTION INPUT ;
    USE SIGNAL ;
    PORT
      LAYER M4 ;
        RECT  0 30.816 0.084 30.84 ;
    END
  END a[297]
  PIN a[298]
    DIRECTION INPUT ;
    USE SIGNAL ;
    PORT
      LAYER M4 ;
        RECT  0 30.96 0.084 30.984 ;
    END
  END a[298]
  PIN a[299]
    DIRECTION INPUT ;
    USE SIGNAL ;
    PORT
      LAYER M4 ;
        RECT  0 31.104 0.084 31.128 ;
    END
  END a[299]
  PIN a[29]
    DIRECTION INPUT ;
    USE SIGNAL ;
    PORT
      LAYER M4 ;
        RECT  0 47.52 0.084 47.544 ;
    END
  END a[29]
  PIN a[2]
    DIRECTION INPUT ;
    USE SIGNAL ;
    PORT
      LAYER M4 ;
        RECT  0 43.632 0.084 43.656 ;
    END
  END a[2]
  PIN a[300]
    DIRECTION INPUT ;
    USE SIGNAL ;
    PORT
      LAYER M4 ;
        RECT  0 31.248 0.084 31.272 ;
    END
  END a[300]
  PIN a[301]
    DIRECTION INPUT ;
    USE SIGNAL ;
    PORT
      LAYER M4 ;
        RECT  0 31.392 0.084 31.416 ;
    END
  END a[301]
  PIN a[302]
    DIRECTION INPUT ;
    USE SIGNAL ;
    PORT
      LAYER M4 ;
        RECT  0 31.536 0.084 31.56 ;
    END
  END a[302]
  PIN a[303]
    DIRECTION INPUT ;
    USE SIGNAL ;
    PORT
      LAYER M4 ;
        RECT  0 31.68 0.084 31.704 ;
    END
  END a[303]
  PIN a[304]
    DIRECTION INPUT ;
    USE SIGNAL ;
    PORT
      LAYER M4 ;
        RECT  0 31.824 0.084 31.848 ;
    END
  END a[304]
  PIN a[305]
    DIRECTION INPUT ;
    USE SIGNAL ;
    PORT
      LAYER M4 ;
        RECT  0 31.968 0.084 31.992 ;
    END
  END a[305]
  PIN a[306]
    DIRECTION INPUT ;
    USE SIGNAL ;
    PORT
      LAYER M4 ;
        RECT  0 32.112 0.084 32.136 ;
    END
  END a[306]
  PIN a[307]
    DIRECTION INPUT ;
    USE SIGNAL ;
    PORT
      LAYER M4 ;
        RECT  0 32.256 0.084 32.28 ;
    END
  END a[307]
  PIN a[308]
    DIRECTION INPUT ;
    USE SIGNAL ;
    PORT
      LAYER M4 ;
        RECT  0 32.4 0.084 32.424 ;
    END
  END a[308]
  PIN a[309]
    DIRECTION INPUT ;
    USE SIGNAL ;
    PORT
      LAYER M4 ;
        RECT  0 32.544 0.084 32.568 ;
    END
  END a[309]
  PIN a[30]
    DIRECTION INPUT ;
    USE SIGNAL ;
    PORT
      LAYER M4 ;
        RECT  0 47.664 0.084 47.688 ;
    END
  END a[30]
  PIN a[310]
    DIRECTION INPUT ;
    USE SIGNAL ;
    PORT
      LAYER M4 ;
        RECT  0 32.688 0.084 32.712 ;
    END
  END a[310]
  PIN a[311]
    DIRECTION INPUT ;
    USE SIGNAL ;
    PORT
      LAYER M4 ;
        RECT  0 32.832 0.084 32.856 ;
    END
  END a[311]
  PIN a[312]
    DIRECTION INPUT ;
    USE SIGNAL ;
    PORT
      LAYER M4 ;
        RECT  0 32.976 0.084 33 ;
    END
  END a[312]
  PIN a[313]
    DIRECTION INPUT ;
    USE SIGNAL ;
    PORT
      LAYER M4 ;
        RECT  0 33.12 0.084 33.144 ;
    END
  END a[313]
  PIN a[314]
    DIRECTION INPUT ;
    USE SIGNAL ;
    PORT
      LAYER M4 ;
        RECT  0 33.264 0.084 33.288 ;
    END
  END a[314]
  PIN a[315]
    DIRECTION INPUT ;
    USE SIGNAL ;
    PORT
      LAYER M4 ;
        RECT  0 33.408 0.084 33.432 ;
    END
  END a[315]
  PIN a[316]
    DIRECTION INPUT ;
    USE SIGNAL ;
    PORT
      LAYER M4 ;
        RECT  0 33.552 0.084 33.576 ;
    END
  END a[316]
  PIN a[317]
    DIRECTION INPUT ;
    USE SIGNAL ;
    PORT
      LAYER M4 ;
        RECT  0 33.696 0.084 33.72 ;
    END
  END a[317]
  PIN a[318]
    DIRECTION INPUT ;
    USE SIGNAL ;
    PORT
      LAYER M4 ;
        RECT  0 33.84 0.084 33.864 ;
    END
  END a[318]
  PIN a[319]
    DIRECTION INPUT ;
    USE SIGNAL ;
    PORT
      LAYER M4 ;
        RECT  0 33.984 0.084 34.008 ;
    END
  END a[319]
  PIN a[31]
    DIRECTION INPUT ;
    USE SIGNAL ;
    PORT
      LAYER M4 ;
        RECT  0 47.808 0.084 47.832 ;
    END
  END a[31]
  PIN a[320]
    DIRECTION INPUT ;
    USE SIGNAL ;
    PORT
      LAYER M4 ;
        RECT  0 5.328 0.084 5.352 ;
    END
  END a[320]
  PIN a[321]
    DIRECTION INPUT ;
    USE SIGNAL ;
    PORT
      LAYER M4 ;
        RECT  0 5.472 0.084 5.496 ;
    END
  END a[321]
  PIN a[322]
    DIRECTION INPUT ;
    USE SIGNAL ;
    PORT
      LAYER M4 ;
        RECT  0 5.616 0.084 5.64 ;
    END
  END a[322]
  PIN a[323]
    DIRECTION INPUT ;
    USE SIGNAL ;
    PORT
      LAYER M4 ;
        RECT  0 5.76 0.084 5.784 ;
    END
  END a[323]
  PIN a[324]
    DIRECTION INPUT ;
    USE SIGNAL ;
    PORT
      LAYER M4 ;
        RECT  0 5.904 0.084 5.928 ;
    END
  END a[324]
  PIN a[325]
    DIRECTION INPUT ;
    USE SIGNAL ;
    PORT
      LAYER M4 ;
        RECT  0 6.048 0.084 6.072 ;
    END
  END a[325]
  PIN a[326]
    DIRECTION INPUT ;
    USE SIGNAL ;
    PORT
      LAYER M4 ;
        RECT  0 6.192 0.084 6.216 ;
    END
  END a[326]
  PIN a[327]
    DIRECTION INPUT ;
    USE SIGNAL ;
    PORT
      LAYER M4 ;
        RECT  0 6.336 0.084 6.36 ;
    END
  END a[327]
  PIN a[328]
    DIRECTION INPUT ;
    USE SIGNAL ;
    PORT
      LAYER M4 ;
        RECT  0 6.48 0.084 6.504 ;
    END
  END a[328]
  PIN a[329]
    DIRECTION INPUT ;
    USE SIGNAL ;
    PORT
      LAYER M4 ;
        RECT  0 6.624 0.084 6.648 ;
    END
  END a[329]
  PIN a[32]
    DIRECTION INPUT ;
    USE SIGNAL ;
    PORT
      LAYER M4 ;
        RECT  0 38.736 0.084 38.76 ;
    END
  END a[32]
  PIN a[330]
    DIRECTION INPUT ;
    USE SIGNAL ;
    PORT
      LAYER M4 ;
        RECT  0 6.768 0.084 6.792 ;
    END
  END a[330]
  PIN a[331]
    DIRECTION INPUT ;
    USE SIGNAL ;
    PORT
      LAYER M4 ;
        RECT  0 6.912 0.084 6.936 ;
    END
  END a[331]
  PIN a[332]
    DIRECTION INPUT ;
    USE SIGNAL ;
    PORT
      LAYER M4 ;
        RECT  0 7.056 0.084 7.08 ;
    END
  END a[332]
  PIN a[333]
    DIRECTION INPUT ;
    USE SIGNAL ;
    PORT
      LAYER M4 ;
        RECT  0 7.2 0.084 7.224 ;
    END
  END a[333]
  PIN a[334]
    DIRECTION INPUT ;
    USE SIGNAL ;
    PORT
      LAYER M4 ;
        RECT  0 7.344 0.084 7.368 ;
    END
  END a[334]
  PIN a[335]
    DIRECTION INPUT ;
    USE SIGNAL ;
    PORT
      LAYER M4 ;
        RECT  0 7.488 0.084 7.512 ;
    END
  END a[335]
  PIN a[336]
    DIRECTION INPUT ;
    USE SIGNAL ;
    PORT
      LAYER M4 ;
        RECT  0 7.632 0.084 7.656 ;
    END
  END a[336]
  PIN a[337]
    DIRECTION INPUT ;
    USE SIGNAL ;
    PORT
      LAYER M4 ;
        RECT  0 7.776 0.084 7.8 ;
    END
  END a[337]
  PIN a[338]
    DIRECTION INPUT ;
    USE SIGNAL ;
    PORT
      LAYER M4 ;
        RECT  0 7.92 0.084 7.944 ;
    END
  END a[338]
  PIN a[339]
    DIRECTION INPUT ;
    USE SIGNAL ;
    PORT
      LAYER M4 ;
        RECT  0 8.064 0.084 8.088 ;
    END
  END a[339]
  PIN a[33]
    DIRECTION INPUT ;
    USE SIGNAL ;
    PORT
      LAYER M4 ;
        RECT  0 38.88 0.084 38.904 ;
    END
  END a[33]
  PIN a[340]
    DIRECTION INPUT ;
    USE SIGNAL ;
    PORT
      LAYER M4 ;
        RECT  0 8.208 0.084 8.232 ;
    END
  END a[340]
  PIN a[341]
    DIRECTION INPUT ;
    USE SIGNAL ;
    PORT
      LAYER M4 ;
        RECT  0 8.352 0.084 8.376 ;
    END
  END a[341]
  PIN a[342]
    DIRECTION INPUT ;
    USE SIGNAL ;
    PORT
      LAYER M4 ;
        RECT  0 8.496 0.084 8.52 ;
    END
  END a[342]
  PIN a[343]
    DIRECTION INPUT ;
    USE SIGNAL ;
    PORT
      LAYER M4 ;
        RECT  0 8.64 0.084 8.664 ;
    END
  END a[343]
  PIN a[344]
    DIRECTION INPUT ;
    USE SIGNAL ;
    PORT
      LAYER M4 ;
        RECT  0 8.784 0.084 8.808 ;
    END
  END a[344]
  PIN a[345]
    DIRECTION INPUT ;
    USE SIGNAL ;
    PORT
      LAYER M4 ;
        RECT  0 8.928 0.084 8.952 ;
    END
  END a[345]
  PIN a[346]
    DIRECTION INPUT ;
    USE SIGNAL ;
    PORT
      LAYER M4 ;
        RECT  0 9.072 0.084 9.096 ;
    END
  END a[346]
  PIN a[347]
    DIRECTION INPUT ;
    USE SIGNAL ;
    PORT
      LAYER M4 ;
        RECT  0 9.216 0.084 9.24 ;
    END
  END a[347]
  PIN a[348]
    DIRECTION INPUT ;
    USE SIGNAL ;
    PORT
      LAYER M4 ;
        RECT  0 9.36 0.084 9.384 ;
    END
  END a[348]
  PIN a[349]
    DIRECTION INPUT ;
    USE SIGNAL ;
    PORT
      LAYER M4 ;
        RECT  0 9.504 0.084 9.528 ;
    END
  END a[349]
  PIN a[34]
    DIRECTION INPUT ;
    USE SIGNAL ;
    PORT
      LAYER M4 ;
        RECT  0 39.024 0.084 39.048 ;
    END
  END a[34]
  PIN a[350]
    DIRECTION INPUT ;
    USE SIGNAL ;
    PORT
      LAYER M4 ;
        RECT  0 9.648 0.084 9.672 ;
    END
  END a[350]
  PIN a[351]
    DIRECTION INPUT ;
    USE SIGNAL ;
    PORT
      LAYER M4 ;
        RECT  0 9.792 0.084 9.816 ;
    END
  END a[351]
  PIN a[352]
    DIRECTION INPUT ;
    USE SIGNAL ;
    PORT
      LAYER M4 ;
        RECT  0 19.152 0.084 19.176 ;
    END
  END a[352]
  PIN a[353]
    DIRECTION INPUT ;
    USE SIGNAL ;
    PORT
      LAYER M4 ;
        RECT  0 19.296 0.084 19.32 ;
    END
  END a[353]
  PIN a[354]
    DIRECTION INPUT ;
    USE SIGNAL ;
    PORT
      LAYER M4 ;
        RECT  0 19.44 0.084 19.464 ;
    END
  END a[354]
  PIN a[355]
    DIRECTION INPUT ;
    USE SIGNAL ;
    PORT
      LAYER M4 ;
        RECT  0 19.584 0.084 19.608 ;
    END
  END a[355]
  PIN a[356]
    DIRECTION INPUT ;
    USE SIGNAL ;
    PORT
      LAYER M4 ;
        RECT  0 19.728 0.084 19.752 ;
    END
  END a[356]
  PIN a[357]
    DIRECTION INPUT ;
    USE SIGNAL ;
    PORT
      LAYER M4 ;
        RECT  0 19.872 0.084 19.896 ;
    END
  END a[357]
  PIN a[358]
    DIRECTION INPUT ;
    USE SIGNAL ;
    PORT
      LAYER M4 ;
        RECT  0 20.016 0.084 20.04 ;
    END
  END a[358]
  PIN a[359]
    DIRECTION INPUT ;
    USE SIGNAL ;
    PORT
      LAYER M4 ;
        RECT  0 20.16 0.084 20.184 ;
    END
  END a[359]
  PIN a[35]
    DIRECTION INPUT ;
    USE SIGNAL ;
    PORT
      LAYER M4 ;
        RECT  0 39.168 0.084 39.192 ;
    END
  END a[35]
  PIN a[360]
    DIRECTION INPUT ;
    USE SIGNAL ;
    PORT
      LAYER M4 ;
        RECT  0 20.304 0.084 20.328 ;
    END
  END a[360]
  PIN a[361]
    DIRECTION INPUT ;
    USE SIGNAL ;
    PORT
      LAYER M4 ;
        RECT  0 20.448 0.084 20.472 ;
    END
  END a[361]
  PIN a[362]
    DIRECTION INPUT ;
    USE SIGNAL ;
    PORT
      LAYER M4 ;
        RECT  0 20.592 0.084 20.616 ;
    END
  END a[362]
  PIN a[363]
    DIRECTION INPUT ;
    USE SIGNAL ;
    PORT
      LAYER M4 ;
        RECT  0 20.736 0.084 20.76 ;
    END
  END a[363]
  PIN a[364]
    DIRECTION INPUT ;
    USE SIGNAL ;
    PORT
      LAYER M4 ;
        RECT  0 20.88 0.084 20.904 ;
    END
  END a[364]
  PIN a[365]
    DIRECTION INPUT ;
    USE SIGNAL ;
    PORT
      LAYER M4 ;
        RECT  0 21.024 0.084 21.048 ;
    END
  END a[365]
  PIN a[366]
    DIRECTION INPUT ;
    USE SIGNAL ;
    PORT
      LAYER M4 ;
        RECT  0 21.168 0.084 21.192 ;
    END
  END a[366]
  PIN a[367]
    DIRECTION INPUT ;
    USE SIGNAL ;
    PORT
      LAYER M4 ;
        RECT  0 21.312 0.084 21.336 ;
    END
  END a[367]
  PIN a[368]
    DIRECTION INPUT ;
    USE SIGNAL ;
    PORT
      LAYER M4 ;
        RECT  0 21.456 0.084 21.48 ;
    END
  END a[368]
  PIN a[369]
    DIRECTION INPUT ;
    USE SIGNAL ;
    PORT
      LAYER M4 ;
        RECT  0 21.6 0.084 21.624 ;
    END
  END a[369]
  PIN a[36]
    DIRECTION INPUT ;
    USE SIGNAL ;
    PORT
      LAYER M4 ;
        RECT  0 39.312 0.084 39.336 ;
    END
  END a[36]
  PIN a[370]
    DIRECTION INPUT ;
    USE SIGNAL ;
    PORT
      LAYER M4 ;
        RECT  0 21.744 0.084 21.768 ;
    END
  END a[370]
  PIN a[371]
    DIRECTION INPUT ;
    USE SIGNAL ;
    PORT
      LAYER M4 ;
        RECT  0 21.888 0.084 21.912 ;
    END
  END a[371]
  PIN a[372]
    DIRECTION INPUT ;
    USE SIGNAL ;
    PORT
      LAYER M4 ;
        RECT  0 22.032 0.084 22.056 ;
    END
  END a[372]
  PIN a[373]
    DIRECTION INPUT ;
    USE SIGNAL ;
    PORT
      LAYER M4 ;
        RECT  0 22.176 0.084 22.2 ;
    END
  END a[373]
  PIN a[374]
    DIRECTION INPUT ;
    USE SIGNAL ;
    PORT
      LAYER M4 ;
        RECT  0 22.32 0.084 22.344 ;
    END
  END a[374]
  PIN a[375]
    DIRECTION INPUT ;
    USE SIGNAL ;
    PORT
      LAYER M4 ;
        RECT  0 22.464 0.084 22.488 ;
    END
  END a[375]
  PIN a[376]
    DIRECTION INPUT ;
    USE SIGNAL ;
    PORT
      LAYER M4 ;
        RECT  0 22.608 0.084 22.632 ;
    END
  END a[376]
  PIN a[377]
    DIRECTION INPUT ;
    USE SIGNAL ;
    PORT
      LAYER M4 ;
        RECT  0 22.752 0.084 22.776 ;
    END
  END a[377]
  PIN a[378]
    DIRECTION INPUT ;
    USE SIGNAL ;
    PORT
      LAYER M4 ;
        RECT  0 22.896 0.084 22.92 ;
    END
  END a[378]
  PIN a[379]
    DIRECTION INPUT ;
    USE SIGNAL ;
    PORT
      LAYER M4 ;
        RECT  0 23.04 0.084 23.064 ;
    END
  END a[379]
  PIN a[37]
    DIRECTION INPUT ;
    USE SIGNAL ;
    PORT
      LAYER M4 ;
        RECT  0 39.456 0.084 39.48 ;
    END
  END a[37]
  PIN a[380]
    DIRECTION INPUT ;
    USE SIGNAL ;
    PORT
      LAYER M4 ;
        RECT  0 23.184 0.084 23.208 ;
    END
  END a[380]
  PIN a[381]
    DIRECTION INPUT ;
    USE SIGNAL ;
    PORT
      LAYER M4 ;
        RECT  0 23.328 0.084 23.352 ;
    END
  END a[381]
  PIN a[382]
    DIRECTION INPUT ;
    USE SIGNAL ;
    PORT
      LAYER M4 ;
        RECT  0 23.472 0.084 23.496 ;
    END
  END a[382]
  PIN a[383]
    DIRECTION INPUT ;
    USE SIGNAL ;
    PORT
      LAYER M4 ;
        RECT  0 23.616 0.084 23.64 ;
    END
  END a[383]
  PIN a[384]
    DIRECTION INPUT ;
    USE SIGNAL ;
    PORT
      LAYER M4 ;
        RECT  0 9.936 0.084 9.96 ;
    END
  END a[384]
  PIN a[385]
    DIRECTION INPUT ;
    USE SIGNAL ;
    PORT
      LAYER M4 ;
        RECT  0 10.08 0.084 10.104 ;
    END
  END a[385]
  PIN a[386]
    DIRECTION INPUT ;
    USE SIGNAL ;
    PORT
      LAYER M4 ;
        RECT  0 10.224 0.084 10.248 ;
    END
  END a[386]
  PIN a[387]
    DIRECTION INPUT ;
    USE SIGNAL ;
    PORT
      LAYER M4 ;
        RECT  0 10.368 0.084 10.392 ;
    END
  END a[387]
  PIN a[388]
    DIRECTION INPUT ;
    USE SIGNAL ;
    PORT
      LAYER M4 ;
        RECT  0 10.512 0.084 10.536 ;
    END
  END a[388]
  PIN a[389]
    DIRECTION INPUT ;
    USE SIGNAL ;
    PORT
      LAYER M4 ;
        RECT  0 10.656 0.084 10.68 ;
    END
  END a[389]
  PIN a[38]
    DIRECTION INPUT ;
    USE SIGNAL ;
    PORT
      LAYER M4 ;
        RECT  0 39.6 0.084 39.624 ;
    END
  END a[38]
  PIN a[390]
    DIRECTION INPUT ;
    USE SIGNAL ;
    PORT
      LAYER M4 ;
        RECT  0 10.8 0.084 10.824 ;
    END
  END a[390]
  PIN a[391]
    DIRECTION INPUT ;
    USE SIGNAL ;
    PORT
      LAYER M4 ;
        RECT  0 10.944 0.084 10.968 ;
    END
  END a[391]
  PIN a[392]
    DIRECTION INPUT ;
    USE SIGNAL ;
    PORT
      LAYER M4 ;
        RECT  0 11.088 0.084 11.112 ;
    END
  END a[392]
  PIN a[393]
    DIRECTION INPUT ;
    USE SIGNAL ;
    PORT
      LAYER M4 ;
        RECT  0 11.232 0.084 11.256 ;
    END
  END a[393]
  PIN a[394]
    DIRECTION INPUT ;
    USE SIGNAL ;
    PORT
      LAYER M4 ;
        RECT  0 11.376 0.084 11.4 ;
    END
  END a[394]
  PIN a[395]
    DIRECTION INPUT ;
    USE SIGNAL ;
    PORT
      LAYER M4 ;
        RECT  0 11.52 0.084 11.544 ;
    END
  END a[395]
  PIN a[396]
    DIRECTION INPUT ;
    USE SIGNAL ;
    PORT
      LAYER M4 ;
        RECT  0 11.664 0.084 11.688 ;
    END
  END a[396]
  PIN a[397]
    DIRECTION INPUT ;
    USE SIGNAL ;
    PORT
      LAYER M4 ;
        RECT  0 11.808 0.084 11.832 ;
    END
  END a[397]
  PIN a[398]
    DIRECTION INPUT ;
    USE SIGNAL ;
    PORT
      LAYER M4 ;
        RECT  0 11.952 0.084 11.976 ;
    END
  END a[398]
  PIN a[399]
    DIRECTION INPUT ;
    USE SIGNAL ;
    PORT
      LAYER M4 ;
        RECT  0 12.096 0.084 12.12 ;
    END
  END a[399]
  PIN a[39]
    DIRECTION INPUT ;
    USE SIGNAL ;
    PORT
      LAYER M4 ;
        RECT  0 39.744 0.084 39.768 ;
    END
  END a[39]
  PIN a[3]
    DIRECTION INPUT ;
    USE SIGNAL ;
    PORT
      LAYER M4 ;
        RECT  0 43.776 0.084 43.8 ;
    END
  END a[3]
  PIN a[400]
    DIRECTION INPUT ;
    USE SIGNAL ;
    PORT
      LAYER M4 ;
        RECT  0 12.24 0.084 12.264 ;
    END
  END a[400]
  PIN a[401]
    DIRECTION INPUT ;
    USE SIGNAL ;
    PORT
      LAYER M4 ;
        RECT  0 12.384 0.084 12.408 ;
    END
  END a[401]
  PIN a[402]
    DIRECTION INPUT ;
    USE SIGNAL ;
    PORT
      LAYER M4 ;
        RECT  0 12.528 0.084 12.552 ;
    END
  END a[402]
  PIN a[403]
    DIRECTION INPUT ;
    USE SIGNAL ;
    PORT
      LAYER M4 ;
        RECT  0 12.672 0.084 12.696 ;
    END
  END a[403]
  PIN a[404]
    DIRECTION INPUT ;
    USE SIGNAL ;
    PORT
      LAYER M4 ;
        RECT  0 12.816 0.084 12.84 ;
    END
  END a[404]
  PIN a[405]
    DIRECTION INPUT ;
    USE SIGNAL ;
    PORT
      LAYER M4 ;
        RECT  0 12.96 0.084 12.984 ;
    END
  END a[405]
  PIN a[406]
    DIRECTION INPUT ;
    USE SIGNAL ;
    PORT
      LAYER M4 ;
        RECT  0 13.104 0.084 13.128 ;
    END
  END a[406]
  PIN a[407]
    DIRECTION INPUT ;
    USE SIGNAL ;
    PORT
      LAYER M4 ;
        RECT  0 13.248 0.084 13.272 ;
    END
  END a[407]
  PIN a[408]
    DIRECTION INPUT ;
    USE SIGNAL ;
    PORT
      LAYER M4 ;
        RECT  0 13.392 0.084 13.416 ;
    END
  END a[408]
  PIN a[409]
    DIRECTION INPUT ;
    USE SIGNAL ;
    PORT
      LAYER M4 ;
        RECT  0 13.536 0.084 13.56 ;
    END
  END a[409]
  PIN a[40]
    DIRECTION INPUT ;
    USE SIGNAL ;
    PORT
      LAYER M4 ;
        RECT  0 39.888 0.084 39.912 ;
    END
  END a[40]
  PIN a[410]
    DIRECTION INPUT ;
    USE SIGNAL ;
    PORT
      LAYER M4 ;
        RECT  0 13.68 0.084 13.704 ;
    END
  END a[410]
  PIN a[411]
    DIRECTION INPUT ;
    USE SIGNAL ;
    PORT
      LAYER M4 ;
        RECT  0 13.824 0.084 13.848 ;
    END
  END a[411]
  PIN a[412]
    DIRECTION INPUT ;
    USE SIGNAL ;
    PORT
      LAYER M4 ;
        RECT  0 13.968 0.084 13.992 ;
    END
  END a[412]
  PIN a[413]
    DIRECTION INPUT ;
    USE SIGNAL ;
    PORT
      LAYER M4 ;
        RECT  0 14.112 0.084 14.136 ;
    END
  END a[413]
  PIN a[414]
    DIRECTION INPUT ;
    USE SIGNAL ;
    PORT
      LAYER M4 ;
        RECT  0 14.256 0.084 14.28 ;
    END
  END a[414]
  PIN a[415]
    DIRECTION INPUT ;
    USE SIGNAL ;
    PORT
      LAYER M4 ;
        RECT  0 14.4 0.084 14.424 ;
    END
  END a[415]
  PIN a[416]
    DIRECTION INPUT ;
    USE SIGNAL ;
    PORT
      LAYER M4 ;
        RECT  0 14.544 0.084 14.568 ;
    END
  END a[416]
  PIN a[417]
    DIRECTION INPUT ;
    USE SIGNAL ;
    PORT
      LAYER M4 ;
        RECT  0 14.688 0.084 14.712 ;
    END
  END a[417]
  PIN a[418]
    DIRECTION INPUT ;
    USE SIGNAL ;
    PORT
      LAYER M4 ;
        RECT  0 14.832 0.084 14.856 ;
    END
  END a[418]
  PIN a[419]
    DIRECTION INPUT ;
    USE SIGNAL ;
    PORT
      LAYER M4 ;
        RECT  0 14.976 0.084 15 ;
    END
  END a[419]
  PIN a[41]
    DIRECTION INPUT ;
    USE SIGNAL ;
    PORT
      LAYER M4 ;
        RECT  0 40.032 0.084 40.056 ;
    END
  END a[41]
  PIN a[420]
    DIRECTION INPUT ;
    USE SIGNAL ;
    PORT
      LAYER M4 ;
        RECT  0 15.12 0.084 15.144 ;
    END
  END a[420]
  PIN a[421]
    DIRECTION INPUT ;
    USE SIGNAL ;
    PORT
      LAYER M4 ;
        RECT  0 15.264 0.084 15.288 ;
    END
  END a[421]
  PIN a[422]
    DIRECTION INPUT ;
    USE SIGNAL ;
    PORT
      LAYER M4 ;
        RECT  0 15.408 0.084 15.432 ;
    END
  END a[422]
  PIN a[423]
    DIRECTION INPUT ;
    USE SIGNAL ;
    PORT
      LAYER M4 ;
        RECT  0 15.552 0.084 15.576 ;
    END
  END a[423]
  PIN a[424]
    DIRECTION INPUT ;
    USE SIGNAL ;
    PORT
      LAYER M4 ;
        RECT  0 15.696 0.084 15.72 ;
    END
  END a[424]
  PIN a[425]
    DIRECTION INPUT ;
    USE SIGNAL ;
    PORT
      LAYER M4 ;
        RECT  0 15.84 0.084 15.864 ;
    END
  END a[425]
  PIN a[426]
    DIRECTION INPUT ;
    USE SIGNAL ;
    PORT
      LAYER M4 ;
        RECT  0 15.984 0.084 16.008 ;
    END
  END a[426]
  PIN a[427]
    DIRECTION INPUT ;
    USE SIGNAL ;
    PORT
      LAYER M4 ;
        RECT  0 16.128 0.084 16.152 ;
    END
  END a[427]
  PIN a[428]
    DIRECTION INPUT ;
    USE SIGNAL ;
    PORT
      LAYER M4 ;
        RECT  0 16.272 0.084 16.296 ;
    END
  END a[428]
  PIN a[429]
    DIRECTION INPUT ;
    USE SIGNAL ;
    PORT
      LAYER M4 ;
        RECT  0 16.416 0.084 16.44 ;
    END
  END a[429]
  PIN a[42]
    DIRECTION INPUT ;
    USE SIGNAL ;
    PORT
      LAYER M4 ;
        RECT  0 40.176 0.084 40.2 ;
    END
  END a[42]
  PIN a[430]
    DIRECTION INPUT ;
    USE SIGNAL ;
    PORT
      LAYER M4 ;
        RECT  0 16.56 0.084 16.584 ;
    END
  END a[430]
  PIN a[431]
    DIRECTION INPUT ;
    USE SIGNAL ;
    PORT
      LAYER M4 ;
        RECT  0 16.704 0.084 16.728 ;
    END
  END a[431]
  PIN a[432]
    DIRECTION INPUT ;
    USE SIGNAL ;
    PORT
      LAYER M4 ;
        RECT  0 16.848 0.084 16.872 ;
    END
  END a[432]
  PIN a[433]
    DIRECTION INPUT ;
    USE SIGNAL ;
    PORT
      LAYER M4 ;
        RECT  0 16.992 0.084 17.016 ;
    END
  END a[433]
  PIN a[434]
    DIRECTION INPUT ;
    USE SIGNAL ;
    PORT
      LAYER M4 ;
        RECT  0 17.136 0.084 17.16 ;
    END
  END a[434]
  PIN a[435]
    DIRECTION INPUT ;
    USE SIGNAL ;
    PORT
      LAYER M4 ;
        RECT  0 17.28 0.084 17.304 ;
    END
  END a[435]
  PIN a[436]
    DIRECTION INPUT ;
    USE SIGNAL ;
    PORT
      LAYER M4 ;
        RECT  0 17.424 0.084 17.448 ;
    END
  END a[436]
  PIN a[437]
    DIRECTION INPUT ;
    USE SIGNAL ;
    PORT
      LAYER M4 ;
        RECT  0 17.568 0.084 17.592 ;
    END
  END a[437]
  PIN a[438]
    DIRECTION INPUT ;
    USE SIGNAL ;
    PORT
      LAYER M4 ;
        RECT  0 17.712 0.084 17.736 ;
    END
  END a[438]
  PIN a[439]
    DIRECTION INPUT ;
    USE SIGNAL ;
    PORT
      LAYER M4 ;
        RECT  0 17.856 0.084 17.88 ;
    END
  END a[439]
  PIN a[43]
    DIRECTION INPUT ;
    USE SIGNAL ;
    PORT
      LAYER M4 ;
        RECT  0 40.32 0.084 40.344 ;
    END
  END a[43]
  PIN a[440]
    DIRECTION INPUT ;
    USE SIGNAL ;
    PORT
      LAYER M4 ;
        RECT  0 18 0.084 18.024 ;
    END
  END a[440]
  PIN a[441]
    DIRECTION INPUT ;
    USE SIGNAL ;
    PORT
      LAYER M4 ;
        RECT  0 18.144 0.084 18.168 ;
    END
  END a[441]
  PIN a[442]
    DIRECTION INPUT ;
    USE SIGNAL ;
    PORT
      LAYER M4 ;
        RECT  0 18.288 0.084 18.312 ;
    END
  END a[442]
  PIN a[443]
    DIRECTION INPUT ;
    USE SIGNAL ;
    PORT
      LAYER M4 ;
        RECT  0 18.432 0.084 18.456 ;
    END
  END a[443]
  PIN a[444]
    DIRECTION INPUT ;
    USE SIGNAL ;
    PORT
      LAYER M4 ;
        RECT  0 18.576 0.084 18.6 ;
    END
  END a[444]
  PIN a[445]
    DIRECTION INPUT ;
    USE SIGNAL ;
    PORT
      LAYER M4 ;
        RECT  0 18.72 0.084 18.744 ;
    END
  END a[445]
  PIN a[446]
    DIRECTION INPUT ;
    USE SIGNAL ;
    PORT
      LAYER M4 ;
        RECT  0 18.864 0.084 18.888 ;
    END
  END a[446]
  PIN a[447]
    DIRECTION INPUT ;
    USE SIGNAL ;
    PORT
      LAYER M4 ;
        RECT  0 19.008 0.084 19.032 ;
    END
  END a[447]
  PIN a[448]
    DIRECTION INPUT ;
    USE SIGNAL ;
    PORT
      LAYER M4 ;
        RECT  0 0.72 0.084 0.744 ;
    END
  END a[448]
  PIN a[449]
    DIRECTION INPUT ;
    USE SIGNAL ;
    PORT
      LAYER M4 ;
        RECT  0 0.864 0.084 0.888 ;
    END
  END a[449]
  PIN a[44]
    DIRECTION INPUT ;
    USE SIGNAL ;
    PORT
      LAYER M4 ;
        RECT  0 40.464 0.084 40.488 ;
    END
  END a[44]
  PIN a[450]
    DIRECTION INPUT ;
    USE SIGNAL ;
    PORT
      LAYER M4 ;
        RECT  0 1.008 0.084 1.032 ;
    END
  END a[450]
  PIN a[451]
    DIRECTION INPUT ;
    USE SIGNAL ;
    PORT
      LAYER M4 ;
        RECT  0 1.152 0.084 1.176 ;
    END
  END a[451]
  PIN a[452]
    DIRECTION INPUT ;
    USE SIGNAL ;
    PORT
      LAYER M4 ;
        RECT  0 1.296 0.084 1.32 ;
    END
  END a[452]
  PIN a[453]
    DIRECTION INPUT ;
    USE SIGNAL ;
    PORT
      LAYER M4 ;
        RECT  0 1.44 0.084 1.464 ;
    END
  END a[453]
  PIN a[454]
    DIRECTION INPUT ;
    USE SIGNAL ;
    PORT
      LAYER M4 ;
        RECT  0 1.584 0.084 1.608 ;
    END
  END a[454]
  PIN a[455]
    DIRECTION INPUT ;
    USE SIGNAL ;
    PORT
      LAYER M4 ;
        RECT  0 1.728 0.084 1.752 ;
    END
  END a[455]
  PIN a[456]
    DIRECTION INPUT ;
    USE SIGNAL ;
    PORT
      LAYER M4 ;
        RECT  0 1.872 0.084 1.896 ;
    END
  END a[456]
  PIN a[457]
    DIRECTION INPUT ;
    USE SIGNAL ;
    PORT
      LAYER M4 ;
        RECT  0 2.016 0.084 2.04 ;
    END
  END a[457]
  PIN a[458]
    DIRECTION INPUT ;
    USE SIGNAL ;
    PORT
      LAYER M4 ;
        RECT  0 2.16 0.084 2.184 ;
    END
  END a[458]
  PIN a[459]
    DIRECTION INPUT ;
    USE SIGNAL ;
    PORT
      LAYER M4 ;
        RECT  0 2.304 0.084 2.328 ;
    END
  END a[459]
  PIN a[45]
    DIRECTION INPUT ;
    USE SIGNAL ;
    PORT
      LAYER M4 ;
        RECT  0 40.608 0.084 40.632 ;
    END
  END a[45]
  PIN a[460]
    DIRECTION INPUT ;
    USE SIGNAL ;
    PORT
      LAYER M4 ;
        RECT  0 2.448 0.084 2.472 ;
    END
  END a[460]
  PIN a[461]
    DIRECTION INPUT ;
    USE SIGNAL ;
    PORT
      LAYER M4 ;
        RECT  0 2.592 0.084 2.616 ;
    END
  END a[461]
  PIN a[462]
    DIRECTION INPUT ;
    USE SIGNAL ;
    PORT
      LAYER M4 ;
        RECT  0 2.736 0.084 2.76 ;
    END
  END a[462]
  PIN a[463]
    DIRECTION INPUT ;
    USE SIGNAL ;
    PORT
      LAYER M4 ;
        RECT  0 2.88 0.084 2.904 ;
    END
  END a[463]
  PIN a[464]
    DIRECTION INPUT ;
    USE SIGNAL ;
    PORT
      LAYER M4 ;
        RECT  0 3.024 0.084 3.048 ;
    END
  END a[464]
  PIN a[465]
    DIRECTION INPUT ;
    USE SIGNAL ;
    PORT
      LAYER M4 ;
        RECT  0 3.168 0.084 3.192 ;
    END
  END a[465]
  PIN a[466]
    DIRECTION INPUT ;
    USE SIGNAL ;
    PORT
      LAYER M4 ;
        RECT  0 3.312 0.084 3.336 ;
    END
  END a[466]
  PIN a[467]
    DIRECTION INPUT ;
    USE SIGNAL ;
    PORT
      LAYER M4 ;
        RECT  0 3.456 0.084 3.48 ;
    END
  END a[467]
  PIN a[468]
    DIRECTION INPUT ;
    USE SIGNAL ;
    PORT
      LAYER M4 ;
        RECT  0 3.6 0.084 3.624 ;
    END
  END a[468]
  PIN a[469]
    DIRECTION INPUT ;
    USE SIGNAL ;
    PORT
      LAYER M4 ;
        RECT  0 3.744 0.084 3.768 ;
    END
  END a[469]
  PIN a[46]
    DIRECTION INPUT ;
    USE SIGNAL ;
    PORT
      LAYER M4 ;
        RECT  0 40.752 0.084 40.776 ;
    END
  END a[46]
  PIN a[470]
    DIRECTION INPUT ;
    USE SIGNAL ;
    PORT
      LAYER M4 ;
        RECT  0 3.888 0.084 3.912 ;
    END
  END a[470]
  PIN a[471]
    DIRECTION INPUT ;
    USE SIGNAL ;
    PORT
      LAYER M4 ;
        RECT  0 4.032 0.084 4.056 ;
    END
  END a[471]
  PIN a[472]
    DIRECTION INPUT ;
    USE SIGNAL ;
    PORT
      LAYER M4 ;
        RECT  0 4.176 0.084 4.2 ;
    END
  END a[472]
  PIN a[473]
    DIRECTION INPUT ;
    USE SIGNAL ;
    PORT
      LAYER M4 ;
        RECT  0 4.32 0.084 4.344 ;
    END
  END a[473]
  PIN a[474]
    DIRECTION INPUT ;
    USE SIGNAL ;
    PORT
      LAYER M4 ;
        RECT  0 4.464 0.084 4.488 ;
    END
  END a[474]
  PIN a[475]
    DIRECTION INPUT ;
    USE SIGNAL ;
    PORT
      LAYER M4 ;
        RECT  0 4.608 0.084 4.632 ;
    END
  END a[475]
  PIN a[476]
    DIRECTION INPUT ;
    USE SIGNAL ;
    PORT
      LAYER M4 ;
        RECT  0 4.752 0.084 4.776 ;
    END
  END a[476]
  PIN a[477]
    DIRECTION INPUT ;
    USE SIGNAL ;
    PORT
      LAYER M4 ;
        RECT  0 4.896 0.084 4.92 ;
    END
  END a[477]
  PIN a[478]
    DIRECTION INPUT ;
    USE SIGNAL ;
    PORT
      LAYER M4 ;
        RECT  0 5.04 0.084 5.064 ;
    END
  END a[478]
  PIN a[479]
    DIRECTION INPUT ;
    USE SIGNAL ;
    PORT
      LAYER M4 ;
        RECT  0 5.184 0.084 5.208 ;
    END
  END a[479]
  PIN a[47]
    DIRECTION INPUT ;
    USE SIGNAL ;
    PORT
      LAYER M4 ;
        RECT  0 40.896 0.084 40.92 ;
    END
  END a[47]
  PIN a[480]
    DIRECTION INPUT ;
    USE SIGNAL ;
    PORT
      LAYER M4 ;
        RECT  0 24.912 0.084 24.936 ;
    END
  END a[480]
  PIN a[481]
    DIRECTION INPUT ;
    USE SIGNAL ;
    PORT
      LAYER M4 ;
        RECT  0 25.056 0.084 25.08 ;
    END
  END a[481]
  PIN a[482]
    DIRECTION INPUT ;
    USE SIGNAL ;
    PORT
      LAYER M4 ;
        RECT  0 25.2 0.084 25.224 ;
    END
  END a[482]
  PIN a[483]
    DIRECTION INPUT ;
    USE SIGNAL ;
    PORT
      LAYER M4 ;
        RECT  0 25.344 0.084 25.368 ;
    END
  END a[483]
  PIN a[484]
    DIRECTION INPUT ;
    USE SIGNAL ;
    PORT
      LAYER M4 ;
        RECT  0 25.488 0.084 25.512 ;
    END
  END a[484]
  PIN a[485]
    DIRECTION INPUT ;
    USE SIGNAL ;
    PORT
      LAYER M4 ;
        RECT  0 25.632 0.084 25.656 ;
    END
  END a[485]
  PIN a[486]
    DIRECTION INPUT ;
    USE SIGNAL ;
    PORT
      LAYER M4 ;
        RECT  0 25.776 0.084 25.8 ;
    END
  END a[486]
  PIN a[487]
    DIRECTION INPUT ;
    USE SIGNAL ;
    PORT
      LAYER M4 ;
        RECT  0 25.92 0.084 25.944 ;
    END
  END a[487]
  PIN a[488]
    DIRECTION INPUT ;
    USE SIGNAL ;
    PORT
      LAYER M4 ;
        RECT  0 26.064 0.084 26.088 ;
    END
  END a[488]
  PIN a[489]
    DIRECTION INPUT ;
    USE SIGNAL ;
    PORT
      LAYER M4 ;
        RECT  0 26.208 0.084 26.232 ;
    END
  END a[489]
  PIN a[48]
    DIRECTION INPUT ;
    USE SIGNAL ;
    PORT
      LAYER M4 ;
        RECT  0 41.04 0.084 41.064 ;
    END
  END a[48]
  PIN a[490]
    DIRECTION INPUT ;
    USE SIGNAL ;
    PORT
      LAYER M4 ;
        RECT  0 26.352 0.084 26.376 ;
    END
  END a[490]
  PIN a[491]
    DIRECTION INPUT ;
    USE SIGNAL ;
    PORT
      LAYER M4 ;
        RECT  0 26.496 0.084 26.52 ;
    END
  END a[491]
  PIN a[492]
    DIRECTION INPUT ;
    USE SIGNAL ;
    PORT
      LAYER M4 ;
        RECT  0 26.64 0.084 26.664 ;
    END
  END a[492]
  PIN a[493]
    DIRECTION INPUT ;
    USE SIGNAL ;
    PORT
      LAYER M4 ;
        RECT  0 26.784 0.084 26.808 ;
    END
  END a[493]
  PIN a[494]
    DIRECTION INPUT ;
    USE SIGNAL ;
    PORT
      LAYER M4 ;
        RECT  0 26.928 0.084 26.952 ;
    END
  END a[494]
  PIN a[495]
    DIRECTION INPUT ;
    USE SIGNAL ;
    PORT
      LAYER M4 ;
        RECT  0 27.072 0.084 27.096 ;
    END
  END a[495]
  PIN a[496]
    DIRECTION INPUT ;
    USE SIGNAL ;
    PORT
      LAYER M4 ;
        RECT  0 27.216 0.084 27.24 ;
    END
  END a[496]
  PIN a[497]
    DIRECTION INPUT ;
    USE SIGNAL ;
    PORT
      LAYER M4 ;
        RECT  0 27.36 0.084 27.384 ;
    END
  END a[497]
  PIN a[498]
    DIRECTION INPUT ;
    USE SIGNAL ;
    PORT
      LAYER M4 ;
        RECT  0 27.504 0.084 27.528 ;
    END
  END a[498]
  PIN a[499]
    DIRECTION INPUT ;
    USE SIGNAL ;
    PORT
      LAYER M4 ;
        RECT  0 27.648 0.084 27.672 ;
    END
  END a[499]
  PIN a[49]
    DIRECTION INPUT ;
    USE SIGNAL ;
    PORT
      LAYER M4 ;
        RECT  0 41.184 0.084 41.208 ;
    END
  END a[49]
  PIN a[4]
    DIRECTION INPUT ;
    USE SIGNAL ;
    PORT
      LAYER M4 ;
        RECT  0 43.92 0.084 43.944 ;
    END
  END a[4]
  PIN a[500]
    DIRECTION INPUT ;
    USE SIGNAL ;
    PORT
      LAYER M4 ;
        RECT  0 27.792 0.084 27.816 ;
    END
  END a[500]
  PIN a[501]
    DIRECTION INPUT ;
    USE SIGNAL ;
    PORT
      LAYER M4 ;
        RECT  0 27.936 0.084 27.96 ;
    END
  END a[501]
  PIN a[502]
    DIRECTION INPUT ;
    USE SIGNAL ;
    PORT
      LAYER M4 ;
        RECT  0 28.08 0.084 28.104 ;
    END
  END a[502]
  PIN a[503]
    DIRECTION INPUT ;
    USE SIGNAL ;
    PORT
      LAYER M4 ;
        RECT  0 28.224 0.084 28.248 ;
    END
  END a[503]
  PIN a[504]
    DIRECTION INPUT ;
    USE SIGNAL ;
    PORT
      LAYER M4 ;
        RECT  0 28.368 0.084 28.392 ;
    END
  END a[504]
  PIN a[505]
    DIRECTION INPUT ;
    USE SIGNAL ;
    PORT
      LAYER M4 ;
        RECT  0 28.512 0.084 28.536 ;
    END
  END a[505]
  PIN a[506]
    DIRECTION INPUT ;
    USE SIGNAL ;
    PORT
      LAYER M4 ;
        RECT  0 28.656 0.084 28.68 ;
    END
  END a[506]
  PIN a[507]
    DIRECTION INPUT ;
    USE SIGNAL ;
    PORT
      LAYER M4 ;
        RECT  0 28.8 0.084 28.824 ;
    END
  END a[507]
  PIN a[508]
    DIRECTION INPUT ;
    USE SIGNAL ;
    PORT
      LAYER M4 ;
        RECT  0 28.944 0.084 28.968 ;
    END
  END a[508]
  PIN a[509]
    DIRECTION INPUT ;
    USE SIGNAL ;
    PORT
      LAYER M4 ;
        RECT  0 29.088 0.084 29.112 ;
    END
  END a[509]
  PIN a[50]
    DIRECTION INPUT ;
    USE SIGNAL ;
    PORT
      LAYER M4 ;
        RECT  0 41.328 0.084 41.352 ;
    END
  END a[50]
  PIN a[510]
    DIRECTION INPUT ;
    USE SIGNAL ;
    PORT
      LAYER M4 ;
        RECT  0 29.232 0.084 29.256 ;
    END
  END a[510]
  PIN a[511]
    DIRECTION INPUT ;
    USE SIGNAL ;
    PORT
      LAYER M4 ;
        RECT  0 29.376 0.084 29.4 ;
    END
  END a[511]
  PIN a[512]
    DIRECTION INPUT ;
    USE SIGNAL ;
    PORT
      LAYER M4 ;
        RECT  0 36.432 0.084 36.456 ;
    END
  END a[512]
  PIN a[513]
    DIRECTION INPUT ;
    USE SIGNAL ;
    PORT
      LAYER M4 ;
        RECT  0 36.576 0.084 36.6 ;
    END
  END a[513]
  PIN a[514]
    DIRECTION INPUT ;
    USE SIGNAL ;
    PORT
      LAYER M4 ;
        RECT  0 36.72 0.084 36.744 ;
    END
  END a[514]
  PIN a[515]
    DIRECTION INPUT ;
    USE SIGNAL ;
    PORT
      LAYER M4 ;
        RECT  0 36.864 0.084 36.888 ;
    END
  END a[515]
  PIN a[516]
    DIRECTION INPUT ;
    USE SIGNAL ;
    PORT
      LAYER M4 ;
        RECT  0 37.008 0.084 37.032 ;
    END
  END a[516]
  PIN a[517]
    DIRECTION INPUT ;
    USE SIGNAL ;
    PORT
      LAYER M4 ;
        RECT  0 37.152 0.084 37.176 ;
    END
  END a[517]
  PIN a[518]
    DIRECTION INPUT ;
    USE SIGNAL ;
    PORT
      LAYER M4 ;
        RECT  0 37.296 0.084 37.32 ;
    END
  END a[518]
  PIN a[519]
    DIRECTION INPUT ;
    USE SIGNAL ;
    PORT
      LAYER M4 ;
        RECT  0 37.44 0.084 37.464 ;
    END
  END a[519]
  PIN a[51]
    DIRECTION INPUT ;
    USE SIGNAL ;
    PORT
      LAYER M4 ;
        RECT  0 41.472 0.084 41.496 ;
    END
  END a[51]
  PIN a[520]
    DIRECTION INPUT ;
    USE SIGNAL ;
    PORT
      LAYER M4 ;
        RECT  0 37.584 0.084 37.608 ;
    END
  END a[520]
  PIN a[521]
    DIRECTION INPUT ;
    USE SIGNAL ;
    PORT
      LAYER M4 ;
        RECT  0 37.728 0.084 37.752 ;
    END
  END a[521]
  PIN a[522]
    DIRECTION INPUT ;
    USE SIGNAL ;
    PORT
      LAYER M4 ;
        RECT  0 37.872 0.084 37.896 ;
    END
  END a[522]
  PIN a[523]
    DIRECTION INPUT ;
    USE SIGNAL ;
    PORT
      LAYER M4 ;
        RECT  0 38.016 0.084 38.04 ;
    END
  END a[523]
  PIN a[524]
    DIRECTION INPUT ;
    USE SIGNAL ;
    PORT
      LAYER M4 ;
        RECT  0 38.16 0.084 38.184 ;
    END
  END a[524]
  PIN a[525]
    DIRECTION INPUT ;
    USE SIGNAL ;
    PORT
      LAYER M4 ;
        RECT  0 38.304 0.084 38.328 ;
    END
  END a[525]
  PIN a[526]
    DIRECTION INPUT ;
    USE SIGNAL ;
    PORT
      LAYER M4 ;
        RECT  0 38.448 0.084 38.472 ;
    END
  END a[526]
  PIN a[527]
    DIRECTION INPUT ;
    USE SIGNAL ;
    PORT
      LAYER M4 ;
        RECT  0 38.592 0.084 38.616 ;
    END
  END a[527]
  PIN a[52]
    DIRECTION INPUT ;
    USE SIGNAL ;
    PORT
      LAYER M4 ;
        RECT  0 41.616 0.084 41.64 ;
    END
  END a[52]
  PIN a[53]
    DIRECTION INPUT ;
    USE SIGNAL ;
    PORT
      LAYER M4 ;
        RECT  0 41.76 0.084 41.784 ;
    END
  END a[53]
  PIN a[54]
    DIRECTION INPUT ;
    USE SIGNAL ;
    PORT
      LAYER M4 ;
        RECT  0 41.904 0.084 41.928 ;
    END
  END a[54]
  PIN a[55]
    DIRECTION INPUT ;
    USE SIGNAL ;
    PORT
      LAYER M4 ;
        RECT  0 42.048 0.084 42.072 ;
    END
  END a[55]
  PIN a[56]
    DIRECTION INPUT ;
    USE SIGNAL ;
    PORT
      LAYER M4 ;
        RECT  0 42.192 0.084 42.216 ;
    END
  END a[56]
  PIN a[57]
    DIRECTION INPUT ;
    USE SIGNAL ;
    PORT
      LAYER M4 ;
        RECT  0 42.336 0.084 42.36 ;
    END
  END a[57]
  PIN a[58]
    DIRECTION INPUT ;
    USE SIGNAL ;
    PORT
      LAYER M4 ;
        RECT  0 42.48 0.084 42.504 ;
    END
  END a[58]
  PIN a[59]
    DIRECTION INPUT ;
    USE SIGNAL ;
    PORT
      LAYER M4 ;
        RECT  0 42.624 0.084 42.648 ;
    END
  END a[59]
  PIN a[5]
    DIRECTION INPUT ;
    USE SIGNAL ;
    PORT
      LAYER M4 ;
        RECT  0 44.064 0.084 44.088 ;
    END
  END a[5]
  PIN a[60]
    DIRECTION INPUT ;
    USE SIGNAL ;
    PORT
      LAYER M4 ;
        RECT  0 42.768 0.084 42.792 ;
    END
  END a[60]
  PIN a[61]
    DIRECTION INPUT ;
    USE SIGNAL ;
    PORT
      LAYER M4 ;
        RECT  0 42.912 0.084 42.936 ;
    END
  END a[61]
  PIN a[62]
    DIRECTION INPUT ;
    USE SIGNAL ;
    PORT
      LAYER M4 ;
        RECT  0 43.056 0.084 43.08 ;
    END
  END a[62]
  PIN a[63]
    DIRECTION INPUT ;
    USE SIGNAL ;
    PORT
      LAYER M4 ;
        RECT  0 43.2 0.084 43.224 ;
    END
  END a[63]
  PIN a[64]
    DIRECTION INPUT ;
    USE SIGNAL ;
    PORT
      LAYER M4 ;
        RECT  0 67.536 0.084 67.56 ;
    END
  END a[64]
  PIN a[65]
    DIRECTION INPUT ;
    USE SIGNAL ;
    PORT
      LAYER M4 ;
        RECT  0 67.68 0.084 67.704 ;
    END
  END a[65]
  PIN a[66]
    DIRECTION INPUT ;
    USE SIGNAL ;
    PORT
      LAYER M4 ;
        RECT  0 67.824 0.084 67.848 ;
    END
  END a[66]
  PIN a[67]
    DIRECTION INPUT ;
    USE SIGNAL ;
    PORT
      LAYER M4 ;
        RECT  0 67.968 0.084 67.992 ;
    END
  END a[67]
  PIN a[68]
    DIRECTION INPUT ;
    USE SIGNAL ;
    PORT
      LAYER M4 ;
        RECT  0 68.112 0.084 68.136 ;
    END
  END a[68]
  PIN a[69]
    DIRECTION INPUT ;
    USE SIGNAL ;
    PORT
      LAYER M4 ;
        RECT  0 68.256 0.084 68.28 ;
    END
  END a[69]
  PIN a[6]
    DIRECTION INPUT ;
    USE SIGNAL ;
    PORT
      LAYER M4 ;
        RECT  0 44.208 0.084 44.232 ;
    END
  END a[6]
  PIN a[70]
    DIRECTION INPUT ;
    USE SIGNAL ;
    PORT
      LAYER M4 ;
        RECT  0 68.4 0.084 68.424 ;
    END
  END a[70]
  PIN a[71]
    DIRECTION INPUT ;
    USE SIGNAL ;
    PORT
      LAYER M4 ;
        RECT  0 68.544 0.084 68.568 ;
    END
  END a[71]
  PIN a[72]
    DIRECTION INPUT ;
    USE SIGNAL ;
    PORT
      LAYER M4 ;
        RECT  0 68.688 0.084 68.712 ;
    END
  END a[72]
  PIN a[73]
    DIRECTION INPUT ;
    USE SIGNAL ;
    PORT
      LAYER M4 ;
        RECT  0 68.832 0.084 68.856 ;
    END
  END a[73]
  PIN a[74]
    DIRECTION INPUT ;
    USE SIGNAL ;
    PORT
      LAYER M4 ;
        RECT  0 68.976 0.084 69 ;
    END
  END a[74]
  PIN a[75]
    DIRECTION INPUT ;
    USE SIGNAL ;
    PORT
      LAYER M4 ;
        RECT  0 69.12 0.084 69.144 ;
    END
  END a[75]
  PIN a[76]
    DIRECTION INPUT ;
    USE SIGNAL ;
    PORT
      LAYER M4 ;
        RECT  0 69.264 0.084 69.288 ;
    END
  END a[76]
  PIN a[77]
    DIRECTION INPUT ;
    USE SIGNAL ;
    PORT
      LAYER M4 ;
        RECT  0 69.408 0.084 69.432 ;
    END
  END a[77]
  PIN a[78]
    DIRECTION INPUT ;
    USE SIGNAL ;
    PORT
      LAYER M4 ;
        RECT  0 69.552 0.084 69.576 ;
    END
  END a[78]
  PIN a[79]
    DIRECTION INPUT ;
    USE SIGNAL ;
    PORT
      LAYER M4 ;
        RECT  0 69.696 0.084 69.72 ;
    END
  END a[79]
  PIN a[7]
    DIRECTION INPUT ;
    USE SIGNAL ;
    PORT
      LAYER M4 ;
        RECT  0 44.352 0.084 44.376 ;
    END
  END a[7]
  PIN a[80]
    DIRECTION INPUT ;
    USE SIGNAL ;
    PORT
      LAYER M4 ;
        RECT  0 69.84 0.084 69.864 ;
    END
  END a[80]
  PIN a[81]
    DIRECTION INPUT ;
    USE SIGNAL ;
    PORT
      LAYER M4 ;
        RECT  0 69.984 0.084 70.008 ;
    END
  END a[81]
  PIN a[82]
    DIRECTION INPUT ;
    USE SIGNAL ;
    PORT
      LAYER M4 ;
        RECT  0 70.128 0.084 70.152 ;
    END
  END a[82]
  PIN a[83]
    DIRECTION INPUT ;
    USE SIGNAL ;
    PORT
      LAYER M4 ;
        RECT  0 70.272 0.084 70.296 ;
    END
  END a[83]
  PIN a[84]
    DIRECTION INPUT ;
    USE SIGNAL ;
    PORT
      LAYER M4 ;
        RECT  0 70.416 0.084 70.44 ;
    END
  END a[84]
  PIN a[85]
    DIRECTION INPUT ;
    USE SIGNAL ;
    PORT
      LAYER M4 ;
        RECT  0 70.56 0.084 70.584 ;
    END
  END a[85]
  PIN a[86]
    DIRECTION INPUT ;
    USE SIGNAL ;
    PORT
      LAYER M4 ;
        RECT  0 70.704 0.084 70.728 ;
    END
  END a[86]
  PIN a[87]
    DIRECTION INPUT ;
    USE SIGNAL ;
    PORT
      LAYER M4 ;
        RECT  0 70.848 0.084 70.872 ;
    END
  END a[87]
  PIN a[88]
    DIRECTION INPUT ;
    USE SIGNAL ;
    PORT
      LAYER M4 ;
        RECT  0 70.992 0.084 71.016 ;
    END
  END a[88]
  PIN a[89]
    DIRECTION INPUT ;
    USE SIGNAL ;
    PORT
      LAYER M4 ;
        RECT  0 71.136 0.084 71.16 ;
    END
  END a[89]
  PIN a[8]
    DIRECTION INPUT ;
    USE SIGNAL ;
    PORT
      LAYER M4 ;
        RECT  0 44.496 0.084 44.52 ;
    END
  END a[8]
  PIN a[90]
    DIRECTION INPUT ;
    USE SIGNAL ;
    PORT
      LAYER M4 ;
        RECT  0 71.28 0.084 71.304 ;
    END
  END a[90]
  PIN a[91]
    DIRECTION INPUT ;
    USE SIGNAL ;
    PORT
      LAYER M4 ;
        RECT  0 71.424 0.084 71.448 ;
    END
  END a[91]
  PIN a[92]
    DIRECTION INPUT ;
    USE SIGNAL ;
    PORT
      LAYER M4 ;
        RECT  0 71.568 0.084 71.592 ;
    END
  END a[92]
  PIN a[93]
    DIRECTION INPUT ;
    USE SIGNAL ;
    PORT
      LAYER M4 ;
        RECT  0 71.712 0.084 71.736 ;
    END
  END a[93]
  PIN a[94]
    DIRECTION INPUT ;
    USE SIGNAL ;
    PORT
      LAYER M4 ;
        RECT  0 71.856 0.084 71.88 ;
    END
  END a[94]
  PIN a[95]
    DIRECTION INPUT ;
    USE SIGNAL ;
    PORT
      LAYER M4 ;
        RECT  0 72 0.084 72.024 ;
    END
  END a[95]
  PIN a[96]
    DIRECTION INPUT ;
    USE SIGNAL ;
    PORT
      LAYER M4 ;
        RECT  0 76.752 0.084 76.776 ;
    END
  END a[96]
  PIN a[97]
    DIRECTION INPUT ;
    USE SIGNAL ;
    PORT
      LAYER M4 ;
        RECT  0 76.896 0.084 76.92 ;
    END
  END a[97]
  PIN a[98]
    DIRECTION INPUT ;
    USE SIGNAL ;
    PORT
      LAYER M4 ;
        RECT  0 77.04 0.084 77.064 ;
    END
  END a[98]
  PIN a[99]
    DIRECTION INPUT ;
    USE SIGNAL ;
    PORT
      LAYER M4 ;
        RECT  0 77.184 0.084 77.208 ;
    END
  END a[99]
  PIN a[9]
    DIRECTION INPUT ;
    USE SIGNAL ;
    PORT
      LAYER M4 ;
        RECT  0 44.64 0.084 44.664 ;
    END
  END a[9]
  PIN b[0]
    DIRECTION OUTPUT ;
    USE SIGNAL ;
    PORT
      LAYER M4 ;
        RECT  51.756 34.128 51.84 34.152 ;
    END
  END b[0]
  PIN b[100]
    DIRECTION OUTPUT ;
    USE SIGNAL ;
    PORT
      LAYER M4 ;
        RECT  51.756 77.328 51.84 77.352 ;
    END
  END b[100]
  PIN b[101]
    DIRECTION OUTPUT ;
    USE SIGNAL ;
    PORT
      LAYER M4 ;
        RECT  51.756 77.472 51.84 77.496 ;
    END
  END b[101]
  PIN b[102]
    DIRECTION OUTPUT ;
    USE SIGNAL ;
    PORT
      LAYER M4 ;
        RECT  51.756 77.616 51.84 77.64 ;
    END
  END b[102]
  PIN b[103]
    DIRECTION OUTPUT ;
    USE SIGNAL ;
    PORT
      LAYER M4 ;
        RECT  51.756 77.76 51.84 77.784 ;
    END
  END b[103]
  PIN b[104]
    DIRECTION OUTPUT ;
    USE SIGNAL ;
    PORT
      LAYER M4 ;
        RECT  51.756 77.904 51.84 77.928 ;
    END
  END b[104]
  PIN b[105]
    DIRECTION OUTPUT ;
    USE SIGNAL ;
    PORT
      LAYER M4 ;
        RECT  51.756 78.048 51.84 78.072 ;
    END
  END b[105]
  PIN b[106]
    DIRECTION OUTPUT ;
    USE SIGNAL ;
    PORT
      LAYER M4 ;
        RECT  51.756 78.192 51.84 78.216 ;
    END
  END b[106]
  PIN b[107]
    DIRECTION OUTPUT ;
    USE SIGNAL ;
    PORT
      LAYER M4 ;
        RECT  51.756 78.336 51.84 78.36 ;
    END
  END b[107]
  PIN b[108]
    DIRECTION OUTPUT ;
    USE SIGNAL ;
    PORT
      LAYER M4 ;
        RECT  51.756 78.48 51.84 78.504 ;
    END
  END b[108]
  PIN b[109]
    DIRECTION OUTPUT ;
    USE SIGNAL ;
    PORT
      LAYER M4 ;
        RECT  51.756 78.624 51.84 78.648 ;
    END
  END b[109]
  PIN b[10]
    DIRECTION OUTPUT ;
    USE SIGNAL ;
    PORT
      LAYER M4 ;
        RECT  51.756 35.568 51.84 35.592 ;
    END
  END b[10]
  PIN b[110]
    DIRECTION OUTPUT ;
    USE SIGNAL ;
    PORT
      LAYER M4 ;
        RECT  51.756 78.768 51.84 78.792 ;
    END
  END b[110]
  PIN b[111]
    DIRECTION OUTPUT ;
    USE SIGNAL ;
    PORT
      LAYER M4 ;
        RECT  51.756 78.912 51.84 78.936 ;
    END
  END b[111]
  PIN b[112]
    DIRECTION OUTPUT ;
    USE SIGNAL ;
    PORT
      LAYER M4 ;
        RECT  51.756 79.056 51.84 79.08 ;
    END
  END b[112]
  PIN b[113]
    DIRECTION OUTPUT ;
    USE SIGNAL ;
    PORT
      LAYER M4 ;
        RECT  51.756 79.2 51.84 79.224 ;
    END
  END b[113]
  PIN b[114]
    DIRECTION OUTPUT ;
    USE SIGNAL ;
    PORT
      LAYER M4 ;
        RECT  51.756 79.344 51.84 79.368 ;
    END
  END b[114]
  PIN b[115]
    DIRECTION OUTPUT ;
    USE SIGNAL ;
    PORT
      LAYER M4 ;
        RECT  51.756 79.488 51.84 79.512 ;
    END
  END b[115]
  PIN b[116]
    DIRECTION OUTPUT ;
    USE SIGNAL ;
    PORT
      LAYER M4 ;
        RECT  51.756 79.632 51.84 79.656 ;
    END
  END b[116]
  PIN b[117]
    DIRECTION OUTPUT ;
    USE SIGNAL ;
    PORT
      LAYER M4 ;
        RECT  51.756 79.776 51.84 79.8 ;
    END
  END b[117]
  PIN b[118]
    DIRECTION OUTPUT ;
    USE SIGNAL ;
    PORT
      LAYER M4 ;
        RECT  51.756 79.92 51.84 79.944 ;
    END
  END b[118]
  PIN b[119]
    DIRECTION OUTPUT ;
    USE SIGNAL ;
    PORT
      LAYER M4 ;
        RECT  51.756 80.064 51.84 80.088 ;
    END
  END b[119]
  PIN b[11]
    DIRECTION OUTPUT ;
    USE SIGNAL ;
    PORT
      LAYER M4 ;
        RECT  51.756 35.712 51.84 35.736 ;
    END
  END b[11]
  PIN b[120]
    DIRECTION OUTPUT ;
    USE SIGNAL ;
    PORT
      LAYER M4 ;
        RECT  51.756 80.208 51.84 80.232 ;
    END
  END b[120]
  PIN b[121]
    DIRECTION OUTPUT ;
    USE SIGNAL ;
    PORT
      LAYER M4 ;
        RECT  51.756 80.352 51.84 80.376 ;
    END
  END b[121]
  PIN b[122]
    DIRECTION OUTPUT ;
    USE SIGNAL ;
    PORT
      LAYER M4 ;
        RECT  51.756 80.496 51.84 80.52 ;
    END
  END b[122]
  PIN b[123]
    DIRECTION OUTPUT ;
    USE SIGNAL ;
    PORT
      LAYER M4 ;
        RECT  51.756 80.64 51.84 80.664 ;
    END
  END b[123]
  PIN b[124]
    DIRECTION OUTPUT ;
    USE SIGNAL ;
    PORT
      LAYER M4 ;
        RECT  51.756 80.784 51.84 80.808 ;
    END
  END b[124]
  PIN b[125]
    DIRECTION OUTPUT ;
    USE SIGNAL ;
    PORT
      LAYER M4 ;
        RECT  51.756 80.928 51.84 80.952 ;
    END
  END b[125]
  PIN b[126]
    DIRECTION OUTPUT ;
    USE SIGNAL ;
    PORT
      LAYER M4 ;
        RECT  51.756 81.072 51.84 81.096 ;
    END
  END b[126]
  PIN b[127]
    DIRECTION OUTPUT ;
    USE SIGNAL ;
    PORT
      LAYER M4 ;
        RECT  51.756 81.216 51.84 81.24 ;
    END
  END b[127]
  PIN b[128]
    DIRECTION OUTPUT ;
    USE SIGNAL ;
    PORT
      LAYER M4 ;
        RECT  51.756 52.56 51.84 52.584 ;
    END
  END b[128]
  PIN b[129]
    DIRECTION OUTPUT ;
    USE SIGNAL ;
    PORT
      LAYER M4 ;
        RECT  51.756 52.704 51.84 52.728 ;
    END
  END b[129]
  PIN b[12]
    DIRECTION OUTPUT ;
    USE SIGNAL ;
    PORT
      LAYER M4 ;
        RECT  51.756 35.856 51.84 35.88 ;
    END
  END b[12]
  PIN b[130]
    DIRECTION OUTPUT ;
    USE SIGNAL ;
    PORT
      LAYER M4 ;
        RECT  51.756 52.848 51.84 52.872 ;
    END
  END b[130]
  PIN b[131]
    DIRECTION OUTPUT ;
    USE SIGNAL ;
    PORT
      LAYER M4 ;
        RECT  51.756 52.992 51.84 53.016 ;
    END
  END b[131]
  PIN b[132]
    DIRECTION OUTPUT ;
    USE SIGNAL ;
    PORT
      LAYER M4 ;
        RECT  51.756 53.136 51.84 53.16 ;
    END
  END b[132]
  PIN b[133]
    DIRECTION OUTPUT ;
    USE SIGNAL ;
    PORT
      LAYER M4 ;
        RECT  51.756 53.28 51.84 53.304 ;
    END
  END b[133]
  PIN b[134]
    DIRECTION OUTPUT ;
    USE SIGNAL ;
    PORT
      LAYER M4 ;
        RECT  51.756 53.424 51.84 53.448 ;
    END
  END b[134]
  PIN b[135]
    DIRECTION OUTPUT ;
    USE SIGNAL ;
    PORT
      LAYER M4 ;
        RECT  51.756 53.568 51.84 53.592 ;
    END
  END b[135]
  PIN b[136]
    DIRECTION OUTPUT ;
    USE SIGNAL ;
    PORT
      LAYER M4 ;
        RECT  51.756 53.712 51.84 53.736 ;
    END
  END b[136]
  PIN b[137]
    DIRECTION OUTPUT ;
    USE SIGNAL ;
    PORT
      LAYER M4 ;
        RECT  51.756 53.856 51.84 53.88 ;
    END
  END b[137]
  PIN b[138]
    DIRECTION OUTPUT ;
    USE SIGNAL ;
    PORT
      LAYER M4 ;
        RECT  51.756 54 51.84 54.024 ;
    END
  END b[138]
  PIN b[139]
    DIRECTION OUTPUT ;
    USE SIGNAL ;
    PORT
      LAYER M4 ;
        RECT  51.756 54.144 51.84 54.168 ;
    END
  END b[139]
  PIN b[13]
    DIRECTION OUTPUT ;
    USE SIGNAL ;
    PORT
      LAYER M4 ;
        RECT  51.756 36 51.84 36.024 ;
    END
  END b[13]
  PIN b[140]
    DIRECTION OUTPUT ;
    USE SIGNAL ;
    PORT
      LAYER M4 ;
        RECT  51.756 54.288 51.84 54.312 ;
    END
  END b[140]
  PIN b[141]
    DIRECTION OUTPUT ;
    USE SIGNAL ;
    PORT
      LAYER M4 ;
        RECT  51.756 54.432 51.84 54.456 ;
    END
  END b[141]
  PIN b[142]
    DIRECTION OUTPUT ;
    USE SIGNAL ;
    PORT
      LAYER M4 ;
        RECT  51.756 54.576 51.84 54.6 ;
    END
  END b[142]
  PIN b[143]
    DIRECTION OUTPUT ;
    USE SIGNAL ;
    PORT
      LAYER M4 ;
        RECT  51.756 54.72 51.84 54.744 ;
    END
  END b[143]
  PIN b[144]
    DIRECTION OUTPUT ;
    USE SIGNAL ;
    PORT
      LAYER M4 ;
        RECT  51.756 54.864 51.84 54.888 ;
    END
  END b[144]
  PIN b[145]
    DIRECTION OUTPUT ;
    USE SIGNAL ;
    PORT
      LAYER M4 ;
        RECT  51.756 55.008 51.84 55.032 ;
    END
  END b[145]
  PIN b[146]
    DIRECTION OUTPUT ;
    USE SIGNAL ;
    PORT
      LAYER M4 ;
        RECT  51.756 55.152 51.84 55.176 ;
    END
  END b[146]
  PIN b[147]
    DIRECTION OUTPUT ;
    USE SIGNAL ;
    PORT
      LAYER M4 ;
        RECT  51.756 55.296 51.84 55.32 ;
    END
  END b[147]
  PIN b[148]
    DIRECTION OUTPUT ;
    USE SIGNAL ;
    PORT
      LAYER M4 ;
        RECT  51.756 55.44 51.84 55.464 ;
    END
  END b[148]
  PIN b[149]
    DIRECTION OUTPUT ;
    USE SIGNAL ;
    PORT
      LAYER M4 ;
        RECT  51.756 55.584 51.84 55.608 ;
    END
  END b[149]
  PIN b[14]
    DIRECTION OUTPUT ;
    USE SIGNAL ;
    PORT
      LAYER M4 ;
        RECT  51.756 36.144 51.84 36.168 ;
    END
  END b[14]
  PIN b[150]
    DIRECTION OUTPUT ;
    USE SIGNAL ;
    PORT
      LAYER M4 ;
        RECT  51.756 55.728 51.84 55.752 ;
    END
  END b[150]
  PIN b[151]
    DIRECTION OUTPUT ;
    USE SIGNAL ;
    PORT
      LAYER M4 ;
        RECT  51.756 55.872 51.84 55.896 ;
    END
  END b[151]
  PIN b[152]
    DIRECTION OUTPUT ;
    USE SIGNAL ;
    PORT
      LAYER M4 ;
        RECT  51.756 56.016 51.84 56.04 ;
    END
  END b[152]
  PIN b[153]
    DIRECTION OUTPUT ;
    USE SIGNAL ;
    PORT
      LAYER M4 ;
        RECT  51.756 56.16 51.84 56.184 ;
    END
  END b[153]
  PIN b[154]
    DIRECTION OUTPUT ;
    USE SIGNAL ;
    PORT
      LAYER M4 ;
        RECT  51.756 56.304 51.84 56.328 ;
    END
  END b[154]
  PIN b[155]
    DIRECTION OUTPUT ;
    USE SIGNAL ;
    PORT
      LAYER M4 ;
        RECT  51.756 56.448 51.84 56.472 ;
    END
  END b[155]
  PIN b[156]
    DIRECTION OUTPUT ;
    USE SIGNAL ;
    PORT
      LAYER M4 ;
        RECT  51.756 56.592 51.84 56.616 ;
    END
  END b[156]
  PIN b[157]
    DIRECTION OUTPUT ;
    USE SIGNAL ;
    PORT
      LAYER M4 ;
        RECT  51.756 56.736 51.84 56.76 ;
    END
  END b[157]
  PIN b[158]
    DIRECTION OUTPUT ;
    USE SIGNAL ;
    PORT
      LAYER M4 ;
        RECT  51.756 56.88 51.84 56.904 ;
    END
  END b[158]
  PIN b[159]
    DIRECTION OUTPUT ;
    USE SIGNAL ;
    PORT
      LAYER M4 ;
        RECT  51.756 57.024 51.84 57.048 ;
    END
  END b[159]
  PIN b[15]
    DIRECTION OUTPUT ;
    USE SIGNAL ;
    PORT
      LAYER M4 ;
        RECT  51.756 36.288 51.84 36.312 ;
    END
  END b[15]
  PIN b[160]
    DIRECTION OUTPUT ;
    USE SIGNAL ;
    PORT
      LAYER M4 ;
        RECT  51.756 38.736 51.84 38.76 ;
    END
  END b[160]
  PIN b[161]
    DIRECTION OUTPUT ;
    USE SIGNAL ;
    PORT
      LAYER M4 ;
        RECT  51.756 38.88 51.84 38.904 ;
    END
  END b[161]
  PIN b[162]
    DIRECTION OUTPUT ;
    USE SIGNAL ;
    PORT
      LAYER M4 ;
        RECT  51.756 39.024 51.84 39.048 ;
    END
  END b[162]
  PIN b[163]
    DIRECTION OUTPUT ;
    USE SIGNAL ;
    PORT
      LAYER M4 ;
        RECT  51.756 39.168 51.84 39.192 ;
    END
  END b[163]
  PIN b[164]
    DIRECTION OUTPUT ;
    USE SIGNAL ;
    PORT
      LAYER M4 ;
        RECT  51.756 39.312 51.84 39.336 ;
    END
  END b[164]
  PIN b[165]
    DIRECTION OUTPUT ;
    USE SIGNAL ;
    PORT
      LAYER M4 ;
        RECT  51.756 39.456 51.84 39.48 ;
    END
  END b[165]
  PIN b[166]
    DIRECTION OUTPUT ;
    USE SIGNAL ;
    PORT
      LAYER M4 ;
        RECT  51.756 39.6 51.84 39.624 ;
    END
  END b[166]
  PIN b[167]
    DIRECTION OUTPUT ;
    USE SIGNAL ;
    PORT
      LAYER M4 ;
        RECT  51.756 39.744 51.84 39.768 ;
    END
  END b[167]
  PIN b[168]
    DIRECTION OUTPUT ;
    USE SIGNAL ;
    PORT
      LAYER M4 ;
        RECT  51.756 39.888 51.84 39.912 ;
    END
  END b[168]
  PIN b[169]
    DIRECTION OUTPUT ;
    USE SIGNAL ;
    PORT
      LAYER M4 ;
        RECT  51.756 40.032 51.84 40.056 ;
    END
  END b[169]
  PIN b[16]
    DIRECTION OUTPUT ;
    USE SIGNAL ;
    PORT
      LAYER M4 ;
        RECT  51.756 36.432 51.84 36.456 ;
    END
  END b[16]
  PIN b[170]
    DIRECTION OUTPUT ;
    USE SIGNAL ;
    PORT
      LAYER M4 ;
        RECT  51.756 40.176 51.84 40.2 ;
    END
  END b[170]
  PIN b[171]
    DIRECTION OUTPUT ;
    USE SIGNAL ;
    PORT
      LAYER M4 ;
        RECT  51.756 40.32 51.84 40.344 ;
    END
  END b[171]
  PIN b[172]
    DIRECTION OUTPUT ;
    USE SIGNAL ;
    PORT
      LAYER M4 ;
        RECT  51.756 40.464 51.84 40.488 ;
    END
  END b[172]
  PIN b[173]
    DIRECTION OUTPUT ;
    USE SIGNAL ;
    PORT
      LAYER M4 ;
        RECT  51.756 40.608 51.84 40.632 ;
    END
  END b[173]
  PIN b[174]
    DIRECTION OUTPUT ;
    USE SIGNAL ;
    PORT
      LAYER M4 ;
        RECT  51.756 40.752 51.84 40.776 ;
    END
  END b[174]
  PIN b[175]
    DIRECTION OUTPUT ;
    USE SIGNAL ;
    PORT
      LAYER M4 ;
        RECT  51.756 40.896 51.84 40.92 ;
    END
  END b[175]
  PIN b[176]
    DIRECTION OUTPUT ;
    USE SIGNAL ;
    PORT
      LAYER M4 ;
        RECT  51.756 41.04 51.84 41.064 ;
    END
  END b[176]
  PIN b[177]
    DIRECTION OUTPUT ;
    USE SIGNAL ;
    PORT
      LAYER M4 ;
        RECT  51.756 41.184 51.84 41.208 ;
    END
  END b[177]
  PIN b[178]
    DIRECTION OUTPUT ;
    USE SIGNAL ;
    PORT
      LAYER M4 ;
        RECT  51.756 41.328 51.84 41.352 ;
    END
  END b[178]
  PIN b[179]
    DIRECTION OUTPUT ;
    USE SIGNAL ;
    PORT
      LAYER M4 ;
        RECT  51.756 41.472 51.84 41.496 ;
    END
  END b[179]
  PIN b[17]
    DIRECTION OUTPUT ;
    USE SIGNAL ;
    PORT
      LAYER M4 ;
        RECT  51.756 36.576 51.84 36.6 ;
    END
  END b[17]
  PIN b[180]
    DIRECTION OUTPUT ;
    USE SIGNAL ;
    PORT
      LAYER M4 ;
        RECT  51.756 41.616 51.84 41.64 ;
    END
  END b[180]
  PIN b[181]
    DIRECTION OUTPUT ;
    USE SIGNAL ;
    PORT
      LAYER M4 ;
        RECT  51.756 41.76 51.84 41.784 ;
    END
  END b[181]
  PIN b[182]
    DIRECTION OUTPUT ;
    USE SIGNAL ;
    PORT
      LAYER M4 ;
        RECT  51.756 41.904 51.84 41.928 ;
    END
  END b[182]
  PIN b[183]
    DIRECTION OUTPUT ;
    USE SIGNAL ;
    PORT
      LAYER M4 ;
        RECT  51.756 42.048 51.84 42.072 ;
    END
  END b[183]
  PIN b[184]
    DIRECTION OUTPUT ;
    USE SIGNAL ;
    PORT
      LAYER M4 ;
        RECT  51.756 42.192 51.84 42.216 ;
    END
  END b[184]
  PIN b[185]
    DIRECTION OUTPUT ;
    USE SIGNAL ;
    PORT
      LAYER M4 ;
        RECT  51.756 42.336 51.84 42.36 ;
    END
  END b[185]
  PIN b[186]
    DIRECTION OUTPUT ;
    USE SIGNAL ;
    PORT
      LAYER M4 ;
        RECT  51.756 42.48 51.84 42.504 ;
    END
  END b[186]
  PIN b[187]
    DIRECTION OUTPUT ;
    USE SIGNAL ;
    PORT
      LAYER M4 ;
        RECT  51.756 42.624 51.84 42.648 ;
    END
  END b[187]
  PIN b[188]
    DIRECTION OUTPUT ;
    USE SIGNAL ;
    PORT
      LAYER M4 ;
        RECT  51.756 42.768 51.84 42.792 ;
    END
  END b[188]
  PIN b[189]
    DIRECTION OUTPUT ;
    USE SIGNAL ;
    PORT
      LAYER M4 ;
        RECT  51.756 42.912 51.84 42.936 ;
    END
  END b[189]
  PIN b[18]
    DIRECTION OUTPUT ;
    USE SIGNAL ;
    PORT
      LAYER M4 ;
        RECT  51.756 36.72 51.84 36.744 ;
    END
  END b[18]
  PIN b[190]
    DIRECTION OUTPUT ;
    USE SIGNAL ;
    PORT
      LAYER M4 ;
        RECT  51.756 43.056 51.84 43.08 ;
    END
  END b[190]
  PIN b[191]
    DIRECTION OUTPUT ;
    USE SIGNAL ;
    PORT
      LAYER M4 ;
        RECT  51.756 43.2 51.84 43.224 ;
    END
  END b[191]
  PIN b[192]
    DIRECTION OUTPUT ;
    USE SIGNAL ;
    PORT
      LAYER M4 ;
        RECT  51.756 47.952 51.84 47.976 ;
    END
  END b[192]
  PIN b[193]
    DIRECTION OUTPUT ;
    USE SIGNAL ;
    PORT
      LAYER M4 ;
        RECT  51.756 48.096 51.84 48.12 ;
    END
  END b[193]
  PIN b[194]
    DIRECTION OUTPUT ;
    USE SIGNAL ;
    PORT
      LAYER M4 ;
        RECT  51.756 48.24 51.84 48.264 ;
    END
  END b[194]
  PIN b[195]
    DIRECTION OUTPUT ;
    USE SIGNAL ;
    PORT
      LAYER M4 ;
        RECT  51.756 48.384 51.84 48.408 ;
    END
  END b[195]
  PIN b[196]
    DIRECTION OUTPUT ;
    USE SIGNAL ;
    PORT
      LAYER M4 ;
        RECT  51.756 48.528 51.84 48.552 ;
    END
  END b[196]
  PIN b[197]
    DIRECTION OUTPUT ;
    USE SIGNAL ;
    PORT
      LAYER M4 ;
        RECT  51.756 48.672 51.84 48.696 ;
    END
  END b[197]
  PIN b[198]
    DIRECTION OUTPUT ;
    USE SIGNAL ;
    PORT
      LAYER M4 ;
        RECT  51.756 48.816 51.84 48.84 ;
    END
  END b[198]
  PIN b[199]
    DIRECTION OUTPUT ;
    USE SIGNAL ;
    PORT
      LAYER M4 ;
        RECT  51.756 48.96 51.84 48.984 ;
    END
  END b[199]
  PIN b[19]
    DIRECTION OUTPUT ;
    USE SIGNAL ;
    PORT
      LAYER M4 ;
        RECT  51.756 36.864 51.84 36.888 ;
    END
  END b[19]
  PIN b[1]
    DIRECTION OUTPUT ;
    USE SIGNAL ;
    PORT
      LAYER M4 ;
        RECT  51.756 34.272 51.84 34.296 ;
    END
  END b[1]
  PIN b[200]
    DIRECTION OUTPUT ;
    USE SIGNAL ;
    PORT
      LAYER M4 ;
        RECT  51.756 49.104 51.84 49.128 ;
    END
  END b[200]
  PIN b[201]
    DIRECTION OUTPUT ;
    USE SIGNAL ;
    PORT
      LAYER M4 ;
        RECT  51.756 49.248 51.84 49.272 ;
    END
  END b[201]
  PIN b[202]
    DIRECTION OUTPUT ;
    USE SIGNAL ;
    PORT
      LAYER M4 ;
        RECT  51.756 49.392 51.84 49.416 ;
    END
  END b[202]
  PIN b[203]
    DIRECTION OUTPUT ;
    USE SIGNAL ;
    PORT
      LAYER M4 ;
        RECT  51.756 49.536 51.84 49.56 ;
    END
  END b[203]
  PIN b[204]
    DIRECTION OUTPUT ;
    USE SIGNAL ;
    PORT
      LAYER M4 ;
        RECT  51.756 49.68 51.84 49.704 ;
    END
  END b[204]
  PIN b[205]
    DIRECTION OUTPUT ;
    USE SIGNAL ;
    PORT
      LAYER M4 ;
        RECT  51.756 49.824 51.84 49.848 ;
    END
  END b[205]
  PIN b[206]
    DIRECTION OUTPUT ;
    USE SIGNAL ;
    PORT
      LAYER M4 ;
        RECT  51.756 49.968 51.84 49.992 ;
    END
  END b[206]
  PIN b[207]
    DIRECTION OUTPUT ;
    USE SIGNAL ;
    PORT
      LAYER M4 ;
        RECT  51.756 50.112 51.84 50.136 ;
    END
  END b[207]
  PIN b[208]
    DIRECTION OUTPUT ;
    USE SIGNAL ;
    PORT
      LAYER M4 ;
        RECT  51.756 50.256 51.84 50.28 ;
    END
  END b[208]
  PIN b[209]
    DIRECTION OUTPUT ;
    USE SIGNAL ;
    PORT
      LAYER M4 ;
        RECT  51.756 50.4 51.84 50.424 ;
    END
  END b[209]
  PIN b[20]
    DIRECTION OUTPUT ;
    USE SIGNAL ;
    PORT
      LAYER M4 ;
        RECT  51.756 37.008 51.84 37.032 ;
    END
  END b[20]
  PIN b[210]
    DIRECTION OUTPUT ;
    USE SIGNAL ;
    PORT
      LAYER M4 ;
        RECT  51.756 50.544 51.84 50.568 ;
    END
  END b[210]
  PIN b[211]
    DIRECTION OUTPUT ;
    USE SIGNAL ;
    PORT
      LAYER M4 ;
        RECT  51.756 50.688 51.84 50.712 ;
    END
  END b[211]
  PIN b[212]
    DIRECTION OUTPUT ;
    USE SIGNAL ;
    PORT
      LAYER M4 ;
        RECT  51.756 50.832 51.84 50.856 ;
    END
  END b[212]
  PIN b[213]
    DIRECTION OUTPUT ;
    USE SIGNAL ;
    PORT
      LAYER M4 ;
        RECT  51.756 50.976 51.84 51 ;
    END
  END b[213]
  PIN b[214]
    DIRECTION OUTPUT ;
    USE SIGNAL ;
    PORT
      LAYER M4 ;
        RECT  51.756 51.12 51.84 51.144 ;
    END
  END b[214]
  PIN b[215]
    DIRECTION OUTPUT ;
    USE SIGNAL ;
    PORT
      LAYER M4 ;
        RECT  51.756 51.264 51.84 51.288 ;
    END
  END b[215]
  PIN b[216]
    DIRECTION OUTPUT ;
    USE SIGNAL ;
    PORT
      LAYER M4 ;
        RECT  51.756 51.408 51.84 51.432 ;
    END
  END b[216]
  PIN b[217]
    DIRECTION OUTPUT ;
    USE SIGNAL ;
    PORT
      LAYER M4 ;
        RECT  51.756 51.552 51.84 51.576 ;
    END
  END b[217]
  PIN b[218]
    DIRECTION OUTPUT ;
    USE SIGNAL ;
    PORT
      LAYER M4 ;
        RECT  51.756 51.696 51.84 51.72 ;
    END
  END b[218]
  PIN b[219]
    DIRECTION OUTPUT ;
    USE SIGNAL ;
    PORT
      LAYER M4 ;
        RECT  51.756 51.84 51.84 51.864 ;
    END
  END b[219]
  PIN b[21]
    DIRECTION OUTPUT ;
    USE SIGNAL ;
    PORT
      LAYER M4 ;
        RECT  51.756 37.152 51.84 37.176 ;
    END
  END b[21]
  PIN b[220]
    DIRECTION OUTPUT ;
    USE SIGNAL ;
    PORT
      LAYER M4 ;
        RECT  51.756 51.984 51.84 52.008 ;
    END
  END b[220]
  PIN b[221]
    DIRECTION OUTPUT ;
    USE SIGNAL ;
    PORT
      LAYER M4 ;
        RECT  51.756 52.128 51.84 52.152 ;
    END
  END b[221]
  PIN b[222]
    DIRECTION OUTPUT ;
    USE SIGNAL ;
    PORT
      LAYER M4 ;
        RECT  51.756 52.272 51.84 52.296 ;
    END
  END b[222]
  PIN b[223]
    DIRECTION OUTPUT ;
    USE SIGNAL ;
    PORT
      LAYER M4 ;
        RECT  51.756 52.416 51.84 52.44 ;
    END
  END b[223]
  PIN b[224]
    DIRECTION OUTPUT ;
    USE SIGNAL ;
    PORT
      LAYER M4 ;
        RECT  51.756 72.144 51.84 72.168 ;
    END
  END b[224]
  PIN b[225]
    DIRECTION OUTPUT ;
    USE SIGNAL ;
    PORT
      LAYER M4 ;
        RECT  51.756 72.288 51.84 72.312 ;
    END
  END b[225]
  PIN b[226]
    DIRECTION OUTPUT ;
    USE SIGNAL ;
    PORT
      LAYER M4 ;
        RECT  51.756 72.432 51.84 72.456 ;
    END
  END b[226]
  PIN b[227]
    DIRECTION OUTPUT ;
    USE SIGNAL ;
    PORT
      LAYER M4 ;
        RECT  51.756 72.576 51.84 72.6 ;
    END
  END b[227]
  PIN b[228]
    DIRECTION OUTPUT ;
    USE SIGNAL ;
    PORT
      LAYER M4 ;
        RECT  51.756 72.72 51.84 72.744 ;
    END
  END b[228]
  PIN b[229]
    DIRECTION OUTPUT ;
    USE SIGNAL ;
    PORT
      LAYER M4 ;
        RECT  51.756 72.864 51.84 72.888 ;
    END
  END b[229]
  PIN b[22]
    DIRECTION OUTPUT ;
    USE SIGNAL ;
    PORT
      LAYER M4 ;
        RECT  51.756 37.296 51.84 37.32 ;
    END
  END b[22]
  PIN b[230]
    DIRECTION OUTPUT ;
    USE SIGNAL ;
    PORT
      LAYER M4 ;
        RECT  51.756 73.008 51.84 73.032 ;
    END
  END b[230]
  PIN b[231]
    DIRECTION OUTPUT ;
    USE SIGNAL ;
    PORT
      LAYER M4 ;
        RECT  51.756 73.152 51.84 73.176 ;
    END
  END b[231]
  PIN b[232]
    DIRECTION OUTPUT ;
    USE SIGNAL ;
    PORT
      LAYER M4 ;
        RECT  51.756 73.296 51.84 73.32 ;
    END
  END b[232]
  PIN b[233]
    DIRECTION OUTPUT ;
    USE SIGNAL ;
    PORT
      LAYER M4 ;
        RECT  51.756 73.44 51.84 73.464 ;
    END
  END b[233]
  PIN b[234]
    DIRECTION OUTPUT ;
    USE SIGNAL ;
    PORT
      LAYER M4 ;
        RECT  51.756 73.584 51.84 73.608 ;
    END
  END b[234]
  PIN b[235]
    DIRECTION OUTPUT ;
    USE SIGNAL ;
    PORT
      LAYER M4 ;
        RECT  51.756 73.728 51.84 73.752 ;
    END
  END b[235]
  PIN b[236]
    DIRECTION OUTPUT ;
    USE SIGNAL ;
    PORT
      LAYER M4 ;
        RECT  51.756 73.872 51.84 73.896 ;
    END
  END b[236]
  PIN b[237]
    DIRECTION OUTPUT ;
    USE SIGNAL ;
    PORT
      LAYER M4 ;
        RECT  51.756 74.016 51.84 74.04 ;
    END
  END b[237]
  PIN b[238]
    DIRECTION OUTPUT ;
    USE SIGNAL ;
    PORT
      LAYER M4 ;
        RECT  51.756 74.16 51.84 74.184 ;
    END
  END b[238]
  PIN b[239]
    DIRECTION OUTPUT ;
    USE SIGNAL ;
    PORT
      LAYER M4 ;
        RECT  51.756 74.304 51.84 74.328 ;
    END
  END b[239]
  PIN b[23]
    DIRECTION OUTPUT ;
    USE SIGNAL ;
    PORT
      LAYER M4 ;
        RECT  51.756 37.44 51.84 37.464 ;
    END
  END b[23]
  PIN b[240]
    DIRECTION OUTPUT ;
    USE SIGNAL ;
    PORT
      LAYER M4 ;
        RECT  51.756 74.448 51.84 74.472 ;
    END
  END b[240]
  PIN b[241]
    DIRECTION OUTPUT ;
    USE SIGNAL ;
    PORT
      LAYER M4 ;
        RECT  51.756 74.592 51.84 74.616 ;
    END
  END b[241]
  PIN b[242]
    DIRECTION OUTPUT ;
    USE SIGNAL ;
    PORT
      LAYER M4 ;
        RECT  51.756 74.736 51.84 74.76 ;
    END
  END b[242]
  PIN b[243]
    DIRECTION OUTPUT ;
    USE SIGNAL ;
    PORT
      LAYER M4 ;
        RECT  51.756 74.88 51.84 74.904 ;
    END
  END b[243]
  PIN b[244]
    DIRECTION OUTPUT ;
    USE SIGNAL ;
    PORT
      LAYER M4 ;
        RECT  51.756 75.024 51.84 75.048 ;
    END
  END b[244]
  PIN b[245]
    DIRECTION OUTPUT ;
    USE SIGNAL ;
    PORT
      LAYER M4 ;
        RECT  51.756 75.168 51.84 75.192 ;
    END
  END b[245]
  PIN b[246]
    DIRECTION OUTPUT ;
    USE SIGNAL ;
    PORT
      LAYER M4 ;
        RECT  51.756 75.312 51.84 75.336 ;
    END
  END b[246]
  PIN b[247]
    DIRECTION OUTPUT ;
    USE SIGNAL ;
    PORT
      LAYER M4 ;
        RECT  51.756 75.456 51.84 75.48 ;
    END
  END b[247]
  PIN b[248]
    DIRECTION OUTPUT ;
    USE SIGNAL ;
    PORT
      LAYER M4 ;
        RECT  51.756 75.6 51.84 75.624 ;
    END
  END b[248]
  PIN b[249]
    DIRECTION OUTPUT ;
    USE SIGNAL ;
    PORT
      LAYER M4 ;
        RECT  51.756 75.744 51.84 75.768 ;
    END
  END b[249]
  PIN b[24]
    DIRECTION OUTPUT ;
    USE SIGNAL ;
    PORT
      LAYER M4 ;
        RECT  51.756 37.584 51.84 37.608 ;
    END
  END b[24]
  PIN b[250]
    DIRECTION OUTPUT ;
    USE SIGNAL ;
    PORT
      LAYER M4 ;
        RECT  51.756 75.888 51.84 75.912 ;
    END
  END b[250]
  PIN b[251]
    DIRECTION OUTPUT ;
    USE SIGNAL ;
    PORT
      LAYER M4 ;
        RECT  51.756 76.032 51.84 76.056 ;
    END
  END b[251]
  PIN b[252]
    DIRECTION OUTPUT ;
    USE SIGNAL ;
    PORT
      LAYER M4 ;
        RECT  51.756 76.176 51.84 76.2 ;
    END
  END b[252]
  PIN b[253]
    DIRECTION OUTPUT ;
    USE SIGNAL ;
    PORT
      LAYER M4 ;
        RECT  51.756 76.32 51.84 76.344 ;
    END
  END b[253]
  PIN b[254]
    DIRECTION OUTPUT ;
    USE SIGNAL ;
    PORT
      LAYER M4 ;
        RECT  51.756 76.464 51.84 76.488 ;
    END
  END b[254]
  PIN b[255]
    DIRECTION OUTPUT ;
    USE SIGNAL ;
    PORT
      LAYER M4 ;
        RECT  51.756 76.608 51.84 76.632 ;
    END
  END b[255]
  PIN b[256]
    DIRECTION OUTPUT ;
    USE SIGNAL ;
    PORT
      LAYER M4 ;
        RECT  51.756 62.928 51.84 62.952 ;
    END
  END b[256]
  PIN b[257]
    DIRECTION OUTPUT ;
    USE SIGNAL ;
    PORT
      LAYER M4 ;
        RECT  51.756 63.072 51.84 63.096 ;
    END
  END b[257]
  PIN b[258]
    DIRECTION OUTPUT ;
    USE SIGNAL ;
    PORT
      LAYER M4 ;
        RECT  51.756 63.216 51.84 63.24 ;
    END
  END b[258]
  PIN b[259]
    DIRECTION OUTPUT ;
    USE SIGNAL ;
    PORT
      LAYER M4 ;
        RECT  51.756 63.36 51.84 63.384 ;
    END
  END b[259]
  PIN b[25]
    DIRECTION OUTPUT ;
    USE SIGNAL ;
    PORT
      LAYER M4 ;
        RECT  51.756 37.728 51.84 37.752 ;
    END
  END b[25]
  PIN b[260]
    DIRECTION OUTPUT ;
    USE SIGNAL ;
    PORT
      LAYER M4 ;
        RECT  51.756 63.504 51.84 63.528 ;
    END
  END b[260]
  PIN b[261]
    DIRECTION OUTPUT ;
    USE SIGNAL ;
    PORT
      LAYER M4 ;
        RECT  51.756 63.648 51.84 63.672 ;
    END
  END b[261]
  PIN b[262]
    DIRECTION OUTPUT ;
    USE SIGNAL ;
    PORT
      LAYER M4 ;
        RECT  51.756 63.792 51.84 63.816 ;
    END
  END b[262]
  PIN b[263]
    DIRECTION OUTPUT ;
    USE SIGNAL ;
    PORT
      LAYER M4 ;
        RECT  51.756 63.936 51.84 63.96 ;
    END
  END b[263]
  PIN b[264]
    DIRECTION OUTPUT ;
    USE SIGNAL ;
    PORT
      LAYER M4 ;
        RECT  51.756 64.08 51.84 64.104 ;
    END
  END b[264]
  PIN b[265]
    DIRECTION OUTPUT ;
    USE SIGNAL ;
    PORT
      LAYER M4 ;
        RECT  51.756 64.224 51.84 64.248 ;
    END
  END b[265]
  PIN b[266]
    DIRECTION OUTPUT ;
    USE SIGNAL ;
    PORT
      LAYER M4 ;
        RECT  51.756 64.368 51.84 64.392 ;
    END
  END b[266]
  PIN b[267]
    DIRECTION OUTPUT ;
    USE SIGNAL ;
    PORT
      LAYER M4 ;
        RECT  51.756 64.512 51.84 64.536 ;
    END
  END b[267]
  PIN b[268]
    DIRECTION OUTPUT ;
    USE SIGNAL ;
    PORT
      LAYER M4 ;
        RECT  51.756 64.656 51.84 64.68 ;
    END
  END b[268]
  PIN b[269]
    DIRECTION OUTPUT ;
    USE SIGNAL ;
    PORT
      LAYER M4 ;
        RECT  51.756 64.8 51.84 64.824 ;
    END
  END b[269]
  PIN b[26]
    DIRECTION OUTPUT ;
    USE SIGNAL ;
    PORT
      LAYER M4 ;
        RECT  51.756 37.872 51.84 37.896 ;
    END
  END b[26]
  PIN b[270]
    DIRECTION OUTPUT ;
    USE SIGNAL ;
    PORT
      LAYER M4 ;
        RECT  51.756 64.944 51.84 64.968 ;
    END
  END b[270]
  PIN b[271]
    DIRECTION OUTPUT ;
    USE SIGNAL ;
    PORT
      LAYER M4 ;
        RECT  51.756 65.088 51.84 65.112 ;
    END
  END b[271]
  PIN b[272]
    DIRECTION OUTPUT ;
    USE SIGNAL ;
    PORT
      LAYER M4 ;
        RECT  51.756 65.232 51.84 65.256 ;
    END
  END b[272]
  PIN b[273]
    DIRECTION OUTPUT ;
    USE SIGNAL ;
    PORT
      LAYER M4 ;
        RECT  51.756 65.376 51.84 65.4 ;
    END
  END b[273]
  PIN b[274]
    DIRECTION OUTPUT ;
    USE SIGNAL ;
    PORT
      LAYER M4 ;
        RECT  51.756 65.52 51.84 65.544 ;
    END
  END b[274]
  PIN b[275]
    DIRECTION OUTPUT ;
    USE SIGNAL ;
    PORT
      LAYER M4 ;
        RECT  51.756 65.664 51.84 65.688 ;
    END
  END b[275]
  PIN b[276]
    DIRECTION OUTPUT ;
    USE SIGNAL ;
    PORT
      LAYER M4 ;
        RECT  51.756 65.808 51.84 65.832 ;
    END
  END b[276]
  PIN b[277]
    DIRECTION OUTPUT ;
    USE SIGNAL ;
    PORT
      LAYER M4 ;
        RECT  51.756 65.952 51.84 65.976 ;
    END
  END b[277]
  PIN b[278]
    DIRECTION OUTPUT ;
    USE SIGNAL ;
    PORT
      LAYER M4 ;
        RECT  51.756 66.096 51.84 66.12 ;
    END
  END b[278]
  PIN b[279]
    DIRECTION OUTPUT ;
    USE SIGNAL ;
    PORT
      LAYER M4 ;
        RECT  51.756 66.24 51.84 66.264 ;
    END
  END b[279]
  PIN b[27]
    DIRECTION OUTPUT ;
    USE SIGNAL ;
    PORT
      LAYER M4 ;
        RECT  51.756 38.016 51.84 38.04 ;
    END
  END b[27]
  PIN b[280]
    DIRECTION OUTPUT ;
    USE SIGNAL ;
    PORT
      LAYER M4 ;
        RECT  51.756 66.384 51.84 66.408 ;
    END
  END b[280]
  PIN b[281]
    DIRECTION OUTPUT ;
    USE SIGNAL ;
    PORT
      LAYER M4 ;
        RECT  51.756 66.528 51.84 66.552 ;
    END
  END b[281]
  PIN b[282]
    DIRECTION OUTPUT ;
    USE SIGNAL ;
    PORT
      LAYER M4 ;
        RECT  51.756 66.672 51.84 66.696 ;
    END
  END b[282]
  PIN b[283]
    DIRECTION OUTPUT ;
    USE SIGNAL ;
    PORT
      LAYER M4 ;
        RECT  51.756 66.816 51.84 66.84 ;
    END
  END b[283]
  PIN b[284]
    DIRECTION OUTPUT ;
    USE SIGNAL ;
    PORT
      LAYER M4 ;
        RECT  51.756 66.96 51.84 66.984 ;
    END
  END b[284]
  PIN b[285]
    DIRECTION OUTPUT ;
    USE SIGNAL ;
    PORT
      LAYER M4 ;
        RECT  51.756 67.104 51.84 67.128 ;
    END
  END b[285]
  PIN b[286]
    DIRECTION OUTPUT ;
    USE SIGNAL ;
    PORT
      LAYER M4 ;
        RECT  51.756 67.248 51.84 67.272 ;
    END
  END b[286]
  PIN b[287]
    DIRECTION OUTPUT ;
    USE SIGNAL ;
    PORT
      LAYER M4 ;
        RECT  51.756 67.392 51.84 67.416 ;
    END
  END b[287]
  PIN b[288]
    DIRECTION OUTPUT ;
    USE SIGNAL ;
    PORT
      LAYER M4 ;
        RECT  51.756 29.52 51.84 29.544 ;
    END
  END b[288]
  PIN b[289]
    DIRECTION OUTPUT ;
    USE SIGNAL ;
    PORT
      LAYER M4 ;
        RECT  51.756 29.664 51.84 29.688 ;
    END
  END b[289]
  PIN b[28]
    DIRECTION OUTPUT ;
    USE SIGNAL ;
    PORT
      LAYER M4 ;
        RECT  51.756 38.16 51.84 38.184 ;
    END
  END b[28]
  PIN b[290]
    DIRECTION OUTPUT ;
    USE SIGNAL ;
    PORT
      LAYER M4 ;
        RECT  51.756 29.808 51.84 29.832 ;
    END
  END b[290]
  PIN b[291]
    DIRECTION OUTPUT ;
    USE SIGNAL ;
    PORT
      LAYER M4 ;
        RECT  51.756 29.952 51.84 29.976 ;
    END
  END b[291]
  PIN b[292]
    DIRECTION OUTPUT ;
    USE SIGNAL ;
    PORT
      LAYER M4 ;
        RECT  51.756 30.096 51.84 30.12 ;
    END
  END b[292]
  PIN b[293]
    DIRECTION OUTPUT ;
    USE SIGNAL ;
    PORT
      LAYER M4 ;
        RECT  51.756 30.24 51.84 30.264 ;
    END
  END b[293]
  PIN b[294]
    DIRECTION OUTPUT ;
    USE SIGNAL ;
    PORT
      LAYER M4 ;
        RECT  51.756 30.384 51.84 30.408 ;
    END
  END b[294]
  PIN b[295]
    DIRECTION OUTPUT ;
    USE SIGNAL ;
    PORT
      LAYER M4 ;
        RECT  51.756 30.528 51.84 30.552 ;
    END
  END b[295]
  PIN b[296]
    DIRECTION OUTPUT ;
    USE SIGNAL ;
    PORT
      LAYER M4 ;
        RECT  51.756 30.672 51.84 30.696 ;
    END
  END b[296]
  PIN b[297]
    DIRECTION OUTPUT ;
    USE SIGNAL ;
    PORT
      LAYER M4 ;
        RECT  51.756 30.816 51.84 30.84 ;
    END
  END b[297]
  PIN b[298]
    DIRECTION OUTPUT ;
    USE SIGNAL ;
    PORT
      LAYER M4 ;
        RECT  51.756 30.96 51.84 30.984 ;
    END
  END b[298]
  PIN b[299]
    DIRECTION OUTPUT ;
    USE SIGNAL ;
    PORT
      LAYER M4 ;
        RECT  51.756 31.104 51.84 31.128 ;
    END
  END b[299]
  PIN b[29]
    DIRECTION OUTPUT ;
    USE SIGNAL ;
    PORT
      LAYER M4 ;
        RECT  51.756 38.304 51.84 38.328 ;
    END
  END b[29]
  PIN b[2]
    DIRECTION OUTPUT ;
    USE SIGNAL ;
    PORT
      LAYER M4 ;
        RECT  51.756 34.416 51.84 34.44 ;
    END
  END b[2]
  PIN b[300]
    DIRECTION OUTPUT ;
    USE SIGNAL ;
    PORT
      LAYER M4 ;
        RECT  51.756 31.248 51.84 31.272 ;
    END
  END b[300]
  PIN b[301]
    DIRECTION OUTPUT ;
    USE SIGNAL ;
    PORT
      LAYER M4 ;
        RECT  51.756 31.392 51.84 31.416 ;
    END
  END b[301]
  PIN b[302]
    DIRECTION OUTPUT ;
    USE SIGNAL ;
    PORT
      LAYER M4 ;
        RECT  51.756 31.536 51.84 31.56 ;
    END
  END b[302]
  PIN b[303]
    DIRECTION OUTPUT ;
    USE SIGNAL ;
    PORT
      LAYER M4 ;
        RECT  51.756 31.68 51.84 31.704 ;
    END
  END b[303]
  PIN b[304]
    DIRECTION OUTPUT ;
    USE SIGNAL ;
    PORT
      LAYER M4 ;
        RECT  51.756 31.824 51.84 31.848 ;
    END
  END b[304]
  PIN b[305]
    DIRECTION OUTPUT ;
    USE SIGNAL ;
    PORT
      LAYER M4 ;
        RECT  51.756 31.968 51.84 31.992 ;
    END
  END b[305]
  PIN b[306]
    DIRECTION OUTPUT ;
    USE SIGNAL ;
    PORT
      LAYER M4 ;
        RECT  51.756 32.112 51.84 32.136 ;
    END
  END b[306]
  PIN b[307]
    DIRECTION OUTPUT ;
    USE SIGNAL ;
    PORT
      LAYER M4 ;
        RECT  51.756 32.256 51.84 32.28 ;
    END
  END b[307]
  PIN b[308]
    DIRECTION OUTPUT ;
    USE SIGNAL ;
    PORT
      LAYER M4 ;
        RECT  51.756 32.4 51.84 32.424 ;
    END
  END b[308]
  PIN b[309]
    DIRECTION OUTPUT ;
    USE SIGNAL ;
    PORT
      LAYER M4 ;
        RECT  51.756 32.544 51.84 32.568 ;
    END
  END b[309]
  PIN b[30]
    DIRECTION OUTPUT ;
    USE SIGNAL ;
    PORT
      LAYER M4 ;
        RECT  51.756 38.448 51.84 38.472 ;
    END
  END b[30]
  PIN b[310]
    DIRECTION OUTPUT ;
    USE SIGNAL ;
    PORT
      LAYER M4 ;
        RECT  51.756 32.688 51.84 32.712 ;
    END
  END b[310]
  PIN b[311]
    DIRECTION OUTPUT ;
    USE SIGNAL ;
    PORT
      LAYER M4 ;
        RECT  51.756 32.832 51.84 32.856 ;
    END
  END b[311]
  PIN b[312]
    DIRECTION OUTPUT ;
    USE SIGNAL ;
    PORT
      LAYER M4 ;
        RECT  51.756 32.976 51.84 33 ;
    END
  END b[312]
  PIN b[313]
    DIRECTION OUTPUT ;
    USE SIGNAL ;
    PORT
      LAYER M4 ;
        RECT  51.756 33.12 51.84 33.144 ;
    END
  END b[313]
  PIN b[314]
    DIRECTION OUTPUT ;
    USE SIGNAL ;
    PORT
      LAYER M4 ;
        RECT  51.756 33.264 51.84 33.288 ;
    END
  END b[314]
  PIN b[315]
    DIRECTION OUTPUT ;
    USE SIGNAL ;
    PORT
      LAYER M4 ;
        RECT  51.756 33.408 51.84 33.432 ;
    END
  END b[315]
  PIN b[316]
    DIRECTION OUTPUT ;
    USE SIGNAL ;
    PORT
      LAYER M4 ;
        RECT  51.756 33.552 51.84 33.576 ;
    END
  END b[316]
  PIN b[317]
    DIRECTION OUTPUT ;
    USE SIGNAL ;
    PORT
      LAYER M4 ;
        RECT  51.756 33.696 51.84 33.72 ;
    END
  END b[317]
  PIN b[318]
    DIRECTION OUTPUT ;
    USE SIGNAL ;
    PORT
      LAYER M4 ;
        RECT  51.756 33.84 51.84 33.864 ;
    END
  END b[318]
  PIN b[319]
    DIRECTION OUTPUT ;
    USE SIGNAL ;
    PORT
      LAYER M4 ;
        RECT  51.756 33.984 51.84 34.008 ;
    END
  END b[319]
  PIN b[31]
    DIRECTION OUTPUT ;
    USE SIGNAL ;
    PORT
      LAYER M4 ;
        RECT  51.756 38.592 51.84 38.616 ;
    END
  END b[31]
  PIN b[320]
    DIRECTION OUTPUT ;
    USE SIGNAL ;
    PORT
      LAYER M4 ;
        RECT  51.756 14.544 51.84 14.568 ;
    END
  END b[320]
  PIN b[321]
    DIRECTION OUTPUT ;
    USE SIGNAL ;
    PORT
      LAYER M4 ;
        RECT  51.756 14.688 51.84 14.712 ;
    END
  END b[321]
  PIN b[322]
    DIRECTION OUTPUT ;
    USE SIGNAL ;
    PORT
      LAYER M4 ;
        RECT  51.756 14.832 51.84 14.856 ;
    END
  END b[322]
  PIN b[323]
    DIRECTION OUTPUT ;
    USE SIGNAL ;
    PORT
      LAYER M4 ;
        RECT  51.756 14.976 51.84 15 ;
    END
  END b[323]
  PIN b[324]
    DIRECTION OUTPUT ;
    USE SIGNAL ;
    PORT
      LAYER M4 ;
        RECT  51.756 15.12 51.84 15.144 ;
    END
  END b[324]
  PIN b[325]
    DIRECTION OUTPUT ;
    USE SIGNAL ;
    PORT
      LAYER M4 ;
        RECT  51.756 15.264 51.84 15.288 ;
    END
  END b[325]
  PIN b[326]
    DIRECTION OUTPUT ;
    USE SIGNAL ;
    PORT
      LAYER M4 ;
        RECT  51.756 15.408 51.84 15.432 ;
    END
  END b[326]
  PIN b[327]
    DIRECTION OUTPUT ;
    USE SIGNAL ;
    PORT
      LAYER M4 ;
        RECT  51.756 15.552 51.84 15.576 ;
    END
  END b[327]
  PIN b[328]
    DIRECTION OUTPUT ;
    USE SIGNAL ;
    PORT
      LAYER M4 ;
        RECT  51.756 15.696 51.84 15.72 ;
    END
  END b[328]
  PIN b[329]
    DIRECTION OUTPUT ;
    USE SIGNAL ;
    PORT
      LAYER M4 ;
        RECT  51.756 15.84 51.84 15.864 ;
    END
  END b[329]
  PIN b[32]
    DIRECTION OUTPUT ;
    USE SIGNAL ;
    PORT
      LAYER M4 ;
        RECT  51.756 43.344 51.84 43.368 ;
    END
  END b[32]
  PIN b[330]
    DIRECTION OUTPUT ;
    USE SIGNAL ;
    PORT
      LAYER M4 ;
        RECT  51.756 15.984 51.84 16.008 ;
    END
  END b[330]
  PIN b[331]
    DIRECTION OUTPUT ;
    USE SIGNAL ;
    PORT
      LAYER M4 ;
        RECT  51.756 16.128 51.84 16.152 ;
    END
  END b[331]
  PIN b[332]
    DIRECTION OUTPUT ;
    USE SIGNAL ;
    PORT
      LAYER M4 ;
        RECT  51.756 16.272 51.84 16.296 ;
    END
  END b[332]
  PIN b[333]
    DIRECTION OUTPUT ;
    USE SIGNAL ;
    PORT
      LAYER M4 ;
        RECT  51.756 16.416 51.84 16.44 ;
    END
  END b[333]
  PIN b[334]
    DIRECTION OUTPUT ;
    USE SIGNAL ;
    PORT
      LAYER M4 ;
        RECT  51.756 16.56 51.84 16.584 ;
    END
  END b[334]
  PIN b[335]
    DIRECTION OUTPUT ;
    USE SIGNAL ;
    PORT
      LAYER M4 ;
        RECT  51.756 16.704 51.84 16.728 ;
    END
  END b[335]
  PIN b[336]
    DIRECTION OUTPUT ;
    USE SIGNAL ;
    PORT
      LAYER M4 ;
        RECT  51.756 16.848 51.84 16.872 ;
    END
  END b[336]
  PIN b[337]
    DIRECTION OUTPUT ;
    USE SIGNAL ;
    PORT
      LAYER M4 ;
        RECT  51.756 16.992 51.84 17.016 ;
    END
  END b[337]
  PIN b[338]
    DIRECTION OUTPUT ;
    USE SIGNAL ;
    PORT
      LAYER M4 ;
        RECT  51.756 17.136 51.84 17.16 ;
    END
  END b[338]
  PIN b[339]
    DIRECTION OUTPUT ;
    USE SIGNAL ;
    PORT
      LAYER M4 ;
        RECT  51.756 17.28 51.84 17.304 ;
    END
  END b[339]
  PIN b[33]
    DIRECTION OUTPUT ;
    USE SIGNAL ;
    PORT
      LAYER M4 ;
        RECT  51.756 43.488 51.84 43.512 ;
    END
  END b[33]
  PIN b[340]
    DIRECTION OUTPUT ;
    USE SIGNAL ;
    PORT
      LAYER M4 ;
        RECT  51.756 17.424 51.84 17.448 ;
    END
  END b[340]
  PIN b[341]
    DIRECTION OUTPUT ;
    USE SIGNAL ;
    PORT
      LAYER M4 ;
        RECT  51.756 17.568 51.84 17.592 ;
    END
  END b[341]
  PIN b[342]
    DIRECTION OUTPUT ;
    USE SIGNAL ;
    PORT
      LAYER M4 ;
        RECT  51.756 17.712 51.84 17.736 ;
    END
  END b[342]
  PIN b[343]
    DIRECTION OUTPUT ;
    USE SIGNAL ;
    PORT
      LAYER M4 ;
        RECT  51.756 17.856 51.84 17.88 ;
    END
  END b[343]
  PIN b[344]
    DIRECTION OUTPUT ;
    USE SIGNAL ;
    PORT
      LAYER M4 ;
        RECT  51.756 18 51.84 18.024 ;
    END
  END b[344]
  PIN b[345]
    DIRECTION OUTPUT ;
    USE SIGNAL ;
    PORT
      LAYER M4 ;
        RECT  51.756 18.144 51.84 18.168 ;
    END
  END b[345]
  PIN b[346]
    DIRECTION OUTPUT ;
    USE SIGNAL ;
    PORT
      LAYER M4 ;
        RECT  51.756 18.288 51.84 18.312 ;
    END
  END b[346]
  PIN b[347]
    DIRECTION OUTPUT ;
    USE SIGNAL ;
    PORT
      LAYER M4 ;
        RECT  51.756 18.432 51.84 18.456 ;
    END
  END b[347]
  PIN b[348]
    DIRECTION OUTPUT ;
    USE SIGNAL ;
    PORT
      LAYER M4 ;
        RECT  51.756 18.576 51.84 18.6 ;
    END
  END b[348]
  PIN b[349]
    DIRECTION OUTPUT ;
    USE SIGNAL ;
    PORT
      LAYER M4 ;
        RECT  51.756 18.72 51.84 18.744 ;
    END
  END b[349]
  PIN b[34]
    DIRECTION OUTPUT ;
    USE SIGNAL ;
    PORT
      LAYER M4 ;
        RECT  51.756 43.632 51.84 43.656 ;
    END
  END b[34]
  PIN b[350]
    DIRECTION OUTPUT ;
    USE SIGNAL ;
    PORT
      LAYER M4 ;
        RECT  51.756 18.864 51.84 18.888 ;
    END
  END b[350]
  PIN b[351]
    DIRECTION OUTPUT ;
    USE SIGNAL ;
    PORT
      LAYER M4 ;
        RECT  51.756 19.008 51.84 19.032 ;
    END
  END b[351]
  PIN b[352]
    DIRECTION OUTPUT ;
    USE SIGNAL ;
    PORT
      LAYER M4 ;
        RECT  51.756 23.76 51.84 23.784 ;
    END
  END b[352]
  PIN b[353]
    DIRECTION OUTPUT ;
    USE SIGNAL ;
    PORT
      LAYER M4 ;
        RECT  51.756 23.904 51.84 23.928 ;
    END
  END b[353]
  PIN b[354]
    DIRECTION OUTPUT ;
    USE SIGNAL ;
    PORT
      LAYER M4 ;
        RECT  51.756 24.048 51.84 24.072 ;
    END
  END b[354]
  PIN b[355]
    DIRECTION OUTPUT ;
    USE SIGNAL ;
    PORT
      LAYER M4 ;
        RECT  51.756 24.192 51.84 24.216 ;
    END
  END b[355]
  PIN b[356]
    DIRECTION OUTPUT ;
    USE SIGNAL ;
    PORT
      LAYER M4 ;
        RECT  51.756 24.336 51.84 24.36 ;
    END
  END b[356]
  PIN b[357]
    DIRECTION OUTPUT ;
    USE SIGNAL ;
    PORT
      LAYER M4 ;
        RECT  51.756 24.48 51.84 24.504 ;
    END
  END b[357]
  PIN b[358]
    DIRECTION OUTPUT ;
    USE SIGNAL ;
    PORT
      LAYER M4 ;
        RECT  51.756 24.624 51.84 24.648 ;
    END
  END b[358]
  PIN b[359]
    DIRECTION OUTPUT ;
    USE SIGNAL ;
    PORT
      LAYER M4 ;
        RECT  51.756 24.768 51.84 24.792 ;
    END
  END b[359]
  PIN b[35]
    DIRECTION OUTPUT ;
    USE SIGNAL ;
    PORT
      LAYER M4 ;
        RECT  51.756 43.776 51.84 43.8 ;
    END
  END b[35]
  PIN b[360]
    DIRECTION OUTPUT ;
    USE SIGNAL ;
    PORT
      LAYER M4 ;
        RECT  51.756 24.912 51.84 24.936 ;
    END
  END b[360]
  PIN b[361]
    DIRECTION OUTPUT ;
    USE SIGNAL ;
    PORT
      LAYER M4 ;
        RECT  51.756 25.056 51.84 25.08 ;
    END
  END b[361]
  PIN b[362]
    DIRECTION OUTPUT ;
    USE SIGNAL ;
    PORT
      LAYER M4 ;
        RECT  51.756 25.2 51.84 25.224 ;
    END
  END b[362]
  PIN b[363]
    DIRECTION OUTPUT ;
    USE SIGNAL ;
    PORT
      LAYER M4 ;
        RECT  51.756 25.344 51.84 25.368 ;
    END
  END b[363]
  PIN b[364]
    DIRECTION OUTPUT ;
    USE SIGNAL ;
    PORT
      LAYER M4 ;
        RECT  51.756 25.488 51.84 25.512 ;
    END
  END b[364]
  PIN b[365]
    DIRECTION OUTPUT ;
    USE SIGNAL ;
    PORT
      LAYER M4 ;
        RECT  51.756 25.632 51.84 25.656 ;
    END
  END b[365]
  PIN b[366]
    DIRECTION OUTPUT ;
    USE SIGNAL ;
    PORT
      LAYER M4 ;
        RECT  51.756 25.776 51.84 25.8 ;
    END
  END b[366]
  PIN b[367]
    DIRECTION OUTPUT ;
    USE SIGNAL ;
    PORT
      LAYER M4 ;
        RECT  51.756 25.92 51.84 25.944 ;
    END
  END b[367]
  PIN b[368]
    DIRECTION OUTPUT ;
    USE SIGNAL ;
    PORT
      LAYER M4 ;
        RECT  51.756 26.064 51.84 26.088 ;
    END
  END b[368]
  PIN b[369]
    DIRECTION OUTPUT ;
    USE SIGNAL ;
    PORT
      LAYER M4 ;
        RECT  51.756 26.208 51.84 26.232 ;
    END
  END b[369]
  PIN b[36]
    DIRECTION OUTPUT ;
    USE SIGNAL ;
    PORT
      LAYER M4 ;
        RECT  51.756 43.92 51.84 43.944 ;
    END
  END b[36]
  PIN b[370]
    DIRECTION OUTPUT ;
    USE SIGNAL ;
    PORT
      LAYER M4 ;
        RECT  51.756 26.352 51.84 26.376 ;
    END
  END b[370]
  PIN b[371]
    DIRECTION OUTPUT ;
    USE SIGNAL ;
    PORT
      LAYER M4 ;
        RECT  51.756 26.496 51.84 26.52 ;
    END
  END b[371]
  PIN b[372]
    DIRECTION OUTPUT ;
    USE SIGNAL ;
    PORT
      LAYER M4 ;
        RECT  51.756 26.64 51.84 26.664 ;
    END
  END b[372]
  PIN b[373]
    DIRECTION OUTPUT ;
    USE SIGNAL ;
    PORT
      LAYER M4 ;
        RECT  51.756 26.784 51.84 26.808 ;
    END
  END b[373]
  PIN b[374]
    DIRECTION OUTPUT ;
    USE SIGNAL ;
    PORT
      LAYER M4 ;
        RECT  51.756 26.928 51.84 26.952 ;
    END
  END b[374]
  PIN b[375]
    DIRECTION OUTPUT ;
    USE SIGNAL ;
    PORT
      LAYER M4 ;
        RECT  51.756 27.072 51.84 27.096 ;
    END
  END b[375]
  PIN b[376]
    DIRECTION OUTPUT ;
    USE SIGNAL ;
    PORT
      LAYER M4 ;
        RECT  51.756 27.216 51.84 27.24 ;
    END
  END b[376]
  PIN b[377]
    DIRECTION OUTPUT ;
    USE SIGNAL ;
    PORT
      LAYER M4 ;
        RECT  51.756 27.36 51.84 27.384 ;
    END
  END b[377]
  PIN b[378]
    DIRECTION OUTPUT ;
    USE SIGNAL ;
    PORT
      LAYER M4 ;
        RECT  51.756 27.504 51.84 27.528 ;
    END
  END b[378]
  PIN b[379]
    DIRECTION OUTPUT ;
    USE SIGNAL ;
    PORT
      LAYER M4 ;
        RECT  51.756 27.648 51.84 27.672 ;
    END
  END b[379]
  PIN b[37]
    DIRECTION OUTPUT ;
    USE SIGNAL ;
    PORT
      LAYER M4 ;
        RECT  51.756 44.064 51.84 44.088 ;
    END
  END b[37]
  PIN b[380]
    DIRECTION OUTPUT ;
    USE SIGNAL ;
    PORT
      LAYER M4 ;
        RECT  51.756 27.792 51.84 27.816 ;
    END
  END b[380]
  PIN b[381]
    DIRECTION OUTPUT ;
    USE SIGNAL ;
    PORT
      LAYER M4 ;
        RECT  51.756 27.936 51.84 27.96 ;
    END
  END b[381]
  PIN b[382]
    DIRECTION OUTPUT ;
    USE SIGNAL ;
    PORT
      LAYER M4 ;
        RECT  51.756 28.08 51.84 28.104 ;
    END
  END b[382]
  PIN b[383]
    DIRECTION OUTPUT ;
    USE SIGNAL ;
    PORT
      LAYER M4 ;
        RECT  51.756 28.224 51.84 28.248 ;
    END
  END b[383]
  PIN b[384]
    DIRECTION OUTPUT ;
    USE SIGNAL ;
    PORT
      LAYER M4 ;
        RECT  51.756 0.72 51.84 0.744 ;
    END
  END b[384]
  PIN b[385]
    DIRECTION OUTPUT ;
    USE SIGNAL ;
    PORT
      LAYER M4 ;
        RECT  51.756 0.864 51.84 0.888 ;
    END
  END b[385]
  PIN b[386]
    DIRECTION OUTPUT ;
    USE SIGNAL ;
    PORT
      LAYER M4 ;
        RECT  51.756 1.008 51.84 1.032 ;
    END
  END b[386]
  PIN b[387]
    DIRECTION OUTPUT ;
    USE SIGNAL ;
    PORT
      LAYER M4 ;
        RECT  51.756 1.152 51.84 1.176 ;
    END
  END b[387]
  PIN b[388]
    DIRECTION OUTPUT ;
    USE SIGNAL ;
    PORT
      LAYER M4 ;
        RECT  51.756 1.296 51.84 1.32 ;
    END
  END b[388]
  PIN b[389]
    DIRECTION OUTPUT ;
    USE SIGNAL ;
    PORT
      LAYER M4 ;
        RECT  51.756 1.44 51.84 1.464 ;
    END
  END b[389]
  PIN b[38]
    DIRECTION OUTPUT ;
    USE SIGNAL ;
    PORT
      LAYER M4 ;
        RECT  51.756 44.208 51.84 44.232 ;
    END
  END b[38]
  PIN b[390]
    DIRECTION OUTPUT ;
    USE SIGNAL ;
    PORT
      LAYER M4 ;
        RECT  51.756 1.584 51.84 1.608 ;
    END
  END b[390]
  PIN b[391]
    DIRECTION OUTPUT ;
    USE SIGNAL ;
    PORT
      LAYER M4 ;
        RECT  51.756 1.728 51.84 1.752 ;
    END
  END b[391]
  PIN b[392]
    DIRECTION OUTPUT ;
    USE SIGNAL ;
    PORT
      LAYER M4 ;
        RECT  51.756 1.872 51.84 1.896 ;
    END
  END b[392]
  PIN b[393]
    DIRECTION OUTPUT ;
    USE SIGNAL ;
    PORT
      LAYER M4 ;
        RECT  51.756 2.016 51.84 2.04 ;
    END
  END b[393]
  PIN b[394]
    DIRECTION OUTPUT ;
    USE SIGNAL ;
    PORT
      LAYER M4 ;
        RECT  51.756 2.16 51.84 2.184 ;
    END
  END b[394]
  PIN b[395]
    DIRECTION OUTPUT ;
    USE SIGNAL ;
    PORT
      LAYER M4 ;
        RECT  51.756 2.304 51.84 2.328 ;
    END
  END b[395]
  PIN b[396]
    DIRECTION OUTPUT ;
    USE SIGNAL ;
    PORT
      LAYER M4 ;
        RECT  51.756 2.448 51.84 2.472 ;
    END
  END b[396]
  PIN b[397]
    DIRECTION OUTPUT ;
    USE SIGNAL ;
    PORT
      LAYER M4 ;
        RECT  51.756 2.592 51.84 2.616 ;
    END
  END b[397]
  PIN b[398]
    DIRECTION OUTPUT ;
    USE SIGNAL ;
    PORT
      LAYER M4 ;
        RECT  51.756 2.736 51.84 2.76 ;
    END
  END b[398]
  PIN b[399]
    DIRECTION OUTPUT ;
    USE SIGNAL ;
    PORT
      LAYER M4 ;
        RECT  51.756 2.88 51.84 2.904 ;
    END
  END b[399]
  PIN b[39]
    DIRECTION OUTPUT ;
    USE SIGNAL ;
    PORT
      LAYER M4 ;
        RECT  51.756 44.352 51.84 44.376 ;
    END
  END b[39]
  PIN b[3]
    DIRECTION OUTPUT ;
    USE SIGNAL ;
    PORT
      LAYER M4 ;
        RECT  51.756 34.56 51.84 34.584 ;
    END
  END b[3]
  PIN b[400]
    DIRECTION OUTPUT ;
    USE SIGNAL ;
    PORT
      LAYER M4 ;
        RECT  51.756 3.024 51.84 3.048 ;
    END
  END b[400]
  PIN b[401]
    DIRECTION OUTPUT ;
    USE SIGNAL ;
    PORT
      LAYER M4 ;
        RECT  51.756 3.168 51.84 3.192 ;
    END
  END b[401]
  PIN b[402]
    DIRECTION OUTPUT ;
    USE SIGNAL ;
    PORT
      LAYER M4 ;
        RECT  51.756 3.312 51.84 3.336 ;
    END
  END b[402]
  PIN b[403]
    DIRECTION OUTPUT ;
    USE SIGNAL ;
    PORT
      LAYER M4 ;
        RECT  51.756 3.456 51.84 3.48 ;
    END
  END b[403]
  PIN b[404]
    DIRECTION OUTPUT ;
    USE SIGNAL ;
    PORT
      LAYER M4 ;
        RECT  51.756 3.6 51.84 3.624 ;
    END
  END b[404]
  PIN b[405]
    DIRECTION OUTPUT ;
    USE SIGNAL ;
    PORT
      LAYER M4 ;
        RECT  51.756 3.744 51.84 3.768 ;
    END
  END b[405]
  PIN b[406]
    DIRECTION OUTPUT ;
    USE SIGNAL ;
    PORT
      LAYER M4 ;
        RECT  51.756 3.888 51.84 3.912 ;
    END
  END b[406]
  PIN b[407]
    DIRECTION OUTPUT ;
    USE SIGNAL ;
    PORT
      LAYER M4 ;
        RECT  51.756 4.032 51.84 4.056 ;
    END
  END b[407]
  PIN b[408]
    DIRECTION OUTPUT ;
    USE SIGNAL ;
    PORT
      LAYER M4 ;
        RECT  51.756 4.176 51.84 4.2 ;
    END
  END b[408]
  PIN b[409]
    DIRECTION OUTPUT ;
    USE SIGNAL ;
    PORT
      LAYER M4 ;
        RECT  51.756 4.32 51.84 4.344 ;
    END
  END b[409]
  PIN b[40]
    DIRECTION OUTPUT ;
    USE SIGNAL ;
    PORT
      LAYER M4 ;
        RECT  51.756 44.496 51.84 44.52 ;
    END
  END b[40]
  PIN b[410]
    DIRECTION OUTPUT ;
    USE SIGNAL ;
    PORT
      LAYER M4 ;
        RECT  51.756 4.464 51.84 4.488 ;
    END
  END b[410]
  PIN b[411]
    DIRECTION OUTPUT ;
    USE SIGNAL ;
    PORT
      LAYER M4 ;
        RECT  51.756 4.608 51.84 4.632 ;
    END
  END b[411]
  PIN b[412]
    DIRECTION OUTPUT ;
    USE SIGNAL ;
    PORT
      LAYER M4 ;
        RECT  51.756 4.752 51.84 4.776 ;
    END
  END b[412]
  PIN b[413]
    DIRECTION OUTPUT ;
    USE SIGNAL ;
    PORT
      LAYER M4 ;
        RECT  51.756 4.896 51.84 4.92 ;
    END
  END b[413]
  PIN b[414]
    DIRECTION OUTPUT ;
    USE SIGNAL ;
    PORT
      LAYER M4 ;
        RECT  51.756 5.04 51.84 5.064 ;
    END
  END b[414]
  PIN b[415]
    DIRECTION OUTPUT ;
    USE SIGNAL ;
    PORT
      LAYER M4 ;
        RECT  51.756 5.184 51.84 5.208 ;
    END
  END b[415]
  PIN b[416]
    DIRECTION OUTPUT ;
    USE SIGNAL ;
    PORT
      LAYER M4 ;
        RECT  51.756 5.328 51.84 5.352 ;
    END
  END b[416]
  PIN b[417]
    DIRECTION OUTPUT ;
    USE SIGNAL ;
    PORT
      LAYER M4 ;
        RECT  51.756 5.472 51.84 5.496 ;
    END
  END b[417]
  PIN b[418]
    DIRECTION OUTPUT ;
    USE SIGNAL ;
    PORT
      LAYER M4 ;
        RECT  51.756 5.616 51.84 5.64 ;
    END
  END b[418]
  PIN b[419]
    DIRECTION OUTPUT ;
    USE SIGNAL ;
    PORT
      LAYER M4 ;
        RECT  51.756 5.76 51.84 5.784 ;
    END
  END b[419]
  PIN b[41]
    DIRECTION OUTPUT ;
    USE SIGNAL ;
    PORT
      LAYER M4 ;
        RECT  51.756 44.64 51.84 44.664 ;
    END
  END b[41]
  PIN b[420]
    DIRECTION OUTPUT ;
    USE SIGNAL ;
    PORT
      LAYER M4 ;
        RECT  51.756 5.904 51.84 5.928 ;
    END
  END b[420]
  PIN b[421]
    DIRECTION OUTPUT ;
    USE SIGNAL ;
    PORT
      LAYER M4 ;
        RECT  51.756 6.048 51.84 6.072 ;
    END
  END b[421]
  PIN b[422]
    DIRECTION OUTPUT ;
    USE SIGNAL ;
    PORT
      LAYER M4 ;
        RECT  51.756 6.192 51.84 6.216 ;
    END
  END b[422]
  PIN b[423]
    DIRECTION OUTPUT ;
    USE SIGNAL ;
    PORT
      LAYER M4 ;
        RECT  51.756 6.336 51.84 6.36 ;
    END
  END b[423]
  PIN b[424]
    DIRECTION OUTPUT ;
    USE SIGNAL ;
    PORT
      LAYER M4 ;
        RECT  51.756 6.48 51.84 6.504 ;
    END
  END b[424]
  PIN b[425]
    DIRECTION OUTPUT ;
    USE SIGNAL ;
    PORT
      LAYER M4 ;
        RECT  51.756 6.624 51.84 6.648 ;
    END
  END b[425]
  PIN b[426]
    DIRECTION OUTPUT ;
    USE SIGNAL ;
    PORT
      LAYER M4 ;
        RECT  51.756 6.768 51.84 6.792 ;
    END
  END b[426]
  PIN b[427]
    DIRECTION OUTPUT ;
    USE SIGNAL ;
    PORT
      LAYER M4 ;
        RECT  51.756 6.912 51.84 6.936 ;
    END
  END b[427]
  PIN b[428]
    DIRECTION OUTPUT ;
    USE SIGNAL ;
    PORT
      LAYER M4 ;
        RECT  51.756 7.056 51.84 7.08 ;
    END
  END b[428]
  PIN b[429]
    DIRECTION OUTPUT ;
    USE SIGNAL ;
    PORT
      LAYER M4 ;
        RECT  51.756 7.2 51.84 7.224 ;
    END
  END b[429]
  PIN b[42]
    DIRECTION OUTPUT ;
    USE SIGNAL ;
    PORT
      LAYER M4 ;
        RECT  51.756 44.784 51.84 44.808 ;
    END
  END b[42]
  PIN b[430]
    DIRECTION OUTPUT ;
    USE SIGNAL ;
    PORT
      LAYER M4 ;
        RECT  51.756 7.344 51.84 7.368 ;
    END
  END b[430]
  PIN b[431]
    DIRECTION OUTPUT ;
    USE SIGNAL ;
    PORT
      LAYER M4 ;
        RECT  51.756 7.488 51.84 7.512 ;
    END
  END b[431]
  PIN b[432]
    DIRECTION OUTPUT ;
    USE SIGNAL ;
    PORT
      LAYER M4 ;
        RECT  51.756 7.632 51.84 7.656 ;
    END
  END b[432]
  PIN b[433]
    DIRECTION OUTPUT ;
    USE SIGNAL ;
    PORT
      LAYER M4 ;
        RECT  51.756 7.776 51.84 7.8 ;
    END
  END b[433]
  PIN b[434]
    DIRECTION OUTPUT ;
    USE SIGNAL ;
    PORT
      LAYER M4 ;
        RECT  51.756 7.92 51.84 7.944 ;
    END
  END b[434]
  PIN b[435]
    DIRECTION OUTPUT ;
    USE SIGNAL ;
    PORT
      LAYER M4 ;
        RECT  51.756 8.064 51.84 8.088 ;
    END
  END b[435]
  PIN b[436]
    DIRECTION OUTPUT ;
    USE SIGNAL ;
    PORT
      LAYER M4 ;
        RECT  51.756 8.208 51.84 8.232 ;
    END
  END b[436]
  PIN b[437]
    DIRECTION OUTPUT ;
    USE SIGNAL ;
    PORT
      LAYER M4 ;
        RECT  51.756 8.352 51.84 8.376 ;
    END
  END b[437]
  PIN b[438]
    DIRECTION OUTPUT ;
    USE SIGNAL ;
    PORT
      LAYER M4 ;
        RECT  51.756 8.496 51.84 8.52 ;
    END
  END b[438]
  PIN b[439]
    DIRECTION OUTPUT ;
    USE SIGNAL ;
    PORT
      LAYER M4 ;
        RECT  51.756 8.64 51.84 8.664 ;
    END
  END b[439]
  PIN b[43]
    DIRECTION OUTPUT ;
    USE SIGNAL ;
    PORT
      LAYER M4 ;
        RECT  51.756 44.928 51.84 44.952 ;
    END
  END b[43]
  PIN b[440]
    DIRECTION OUTPUT ;
    USE SIGNAL ;
    PORT
      LAYER M4 ;
        RECT  51.756 8.784 51.84 8.808 ;
    END
  END b[440]
  PIN b[441]
    DIRECTION OUTPUT ;
    USE SIGNAL ;
    PORT
      LAYER M4 ;
        RECT  51.756 8.928 51.84 8.952 ;
    END
  END b[441]
  PIN b[442]
    DIRECTION OUTPUT ;
    USE SIGNAL ;
    PORT
      LAYER M4 ;
        RECT  51.756 9.072 51.84 9.096 ;
    END
  END b[442]
  PIN b[443]
    DIRECTION OUTPUT ;
    USE SIGNAL ;
    PORT
      LAYER M4 ;
        RECT  51.756 9.216 51.84 9.24 ;
    END
  END b[443]
  PIN b[444]
    DIRECTION OUTPUT ;
    USE SIGNAL ;
    PORT
      LAYER M4 ;
        RECT  51.756 9.36 51.84 9.384 ;
    END
  END b[444]
  PIN b[445]
    DIRECTION OUTPUT ;
    USE SIGNAL ;
    PORT
      LAYER M4 ;
        RECT  51.756 9.504 51.84 9.528 ;
    END
  END b[445]
  PIN b[446]
    DIRECTION OUTPUT ;
    USE SIGNAL ;
    PORT
      LAYER M4 ;
        RECT  51.756 9.648 51.84 9.672 ;
    END
  END b[446]
  PIN b[447]
    DIRECTION OUTPUT ;
    USE SIGNAL ;
    PORT
      LAYER M4 ;
        RECT  51.756 9.792 51.84 9.816 ;
    END
  END b[447]
  PIN b[448]
    DIRECTION OUTPUT ;
    USE SIGNAL ;
    PORT
      LAYER M4 ;
        RECT  51.756 9.936 51.84 9.96 ;
    END
  END b[448]
  PIN b[449]
    DIRECTION OUTPUT ;
    USE SIGNAL ;
    PORT
      LAYER M4 ;
        RECT  51.756 10.08 51.84 10.104 ;
    END
  END b[449]
  PIN b[44]
    DIRECTION OUTPUT ;
    USE SIGNAL ;
    PORT
      LAYER M4 ;
        RECT  51.756 45.072 51.84 45.096 ;
    END
  END b[44]
  PIN b[450]
    DIRECTION OUTPUT ;
    USE SIGNAL ;
    PORT
      LAYER M4 ;
        RECT  51.756 10.224 51.84 10.248 ;
    END
  END b[450]
  PIN b[451]
    DIRECTION OUTPUT ;
    USE SIGNAL ;
    PORT
      LAYER M4 ;
        RECT  51.756 10.368 51.84 10.392 ;
    END
  END b[451]
  PIN b[452]
    DIRECTION OUTPUT ;
    USE SIGNAL ;
    PORT
      LAYER M4 ;
        RECT  51.756 10.512 51.84 10.536 ;
    END
  END b[452]
  PIN b[453]
    DIRECTION OUTPUT ;
    USE SIGNAL ;
    PORT
      LAYER M4 ;
        RECT  51.756 10.656 51.84 10.68 ;
    END
  END b[453]
  PIN b[454]
    DIRECTION OUTPUT ;
    USE SIGNAL ;
    PORT
      LAYER M4 ;
        RECT  51.756 10.8 51.84 10.824 ;
    END
  END b[454]
  PIN b[455]
    DIRECTION OUTPUT ;
    USE SIGNAL ;
    PORT
      LAYER M4 ;
        RECT  51.756 10.944 51.84 10.968 ;
    END
  END b[455]
  PIN b[456]
    DIRECTION OUTPUT ;
    USE SIGNAL ;
    PORT
      LAYER M4 ;
        RECT  51.756 11.088 51.84 11.112 ;
    END
  END b[456]
  PIN b[457]
    DIRECTION OUTPUT ;
    USE SIGNAL ;
    PORT
      LAYER M4 ;
        RECT  51.756 11.232 51.84 11.256 ;
    END
  END b[457]
  PIN b[458]
    DIRECTION OUTPUT ;
    USE SIGNAL ;
    PORT
      LAYER M4 ;
        RECT  51.756 11.376 51.84 11.4 ;
    END
  END b[458]
  PIN b[459]
    DIRECTION OUTPUT ;
    USE SIGNAL ;
    PORT
      LAYER M4 ;
        RECT  51.756 11.52 51.84 11.544 ;
    END
  END b[459]
  PIN b[45]
    DIRECTION OUTPUT ;
    USE SIGNAL ;
    PORT
      LAYER M4 ;
        RECT  51.756 45.216 51.84 45.24 ;
    END
  END b[45]
  PIN b[460]
    DIRECTION OUTPUT ;
    USE SIGNAL ;
    PORT
      LAYER M4 ;
        RECT  51.756 11.664 51.84 11.688 ;
    END
  END b[460]
  PIN b[461]
    DIRECTION OUTPUT ;
    USE SIGNAL ;
    PORT
      LAYER M4 ;
        RECT  51.756 11.808 51.84 11.832 ;
    END
  END b[461]
  PIN b[462]
    DIRECTION OUTPUT ;
    USE SIGNAL ;
    PORT
      LAYER M4 ;
        RECT  51.756 11.952 51.84 11.976 ;
    END
  END b[462]
  PIN b[463]
    DIRECTION OUTPUT ;
    USE SIGNAL ;
    PORT
      LAYER M4 ;
        RECT  51.756 12.096 51.84 12.12 ;
    END
  END b[463]
  PIN b[464]
    DIRECTION OUTPUT ;
    USE SIGNAL ;
    PORT
      LAYER M4 ;
        RECT  51.756 12.24 51.84 12.264 ;
    END
  END b[464]
  PIN b[465]
    DIRECTION OUTPUT ;
    USE SIGNAL ;
    PORT
      LAYER M4 ;
        RECT  51.756 12.384 51.84 12.408 ;
    END
  END b[465]
  PIN b[466]
    DIRECTION OUTPUT ;
    USE SIGNAL ;
    PORT
      LAYER M4 ;
        RECT  51.756 12.528 51.84 12.552 ;
    END
  END b[466]
  PIN b[467]
    DIRECTION OUTPUT ;
    USE SIGNAL ;
    PORT
      LAYER M4 ;
        RECT  51.756 12.672 51.84 12.696 ;
    END
  END b[467]
  PIN b[468]
    DIRECTION OUTPUT ;
    USE SIGNAL ;
    PORT
      LAYER M4 ;
        RECT  51.756 12.816 51.84 12.84 ;
    END
  END b[468]
  PIN b[469]
    DIRECTION OUTPUT ;
    USE SIGNAL ;
    PORT
      LAYER M4 ;
        RECT  51.756 12.96 51.84 12.984 ;
    END
  END b[469]
  PIN b[46]
    DIRECTION OUTPUT ;
    USE SIGNAL ;
    PORT
      LAYER M4 ;
        RECT  51.756 45.36 51.84 45.384 ;
    END
  END b[46]
  PIN b[470]
    DIRECTION OUTPUT ;
    USE SIGNAL ;
    PORT
      LAYER M4 ;
        RECT  51.756 13.104 51.84 13.128 ;
    END
  END b[470]
  PIN b[471]
    DIRECTION OUTPUT ;
    USE SIGNAL ;
    PORT
      LAYER M4 ;
        RECT  51.756 13.248 51.84 13.272 ;
    END
  END b[471]
  PIN b[472]
    DIRECTION OUTPUT ;
    USE SIGNAL ;
    PORT
      LAYER M4 ;
        RECT  51.756 13.392 51.84 13.416 ;
    END
  END b[472]
  PIN b[473]
    DIRECTION OUTPUT ;
    USE SIGNAL ;
    PORT
      LAYER M4 ;
        RECT  51.756 13.536 51.84 13.56 ;
    END
  END b[473]
  PIN b[474]
    DIRECTION OUTPUT ;
    USE SIGNAL ;
    PORT
      LAYER M4 ;
        RECT  51.756 13.68 51.84 13.704 ;
    END
  END b[474]
  PIN b[475]
    DIRECTION OUTPUT ;
    USE SIGNAL ;
    PORT
      LAYER M4 ;
        RECT  51.756 13.824 51.84 13.848 ;
    END
  END b[475]
  PIN b[476]
    DIRECTION OUTPUT ;
    USE SIGNAL ;
    PORT
      LAYER M4 ;
        RECT  51.756 13.968 51.84 13.992 ;
    END
  END b[476]
  PIN b[477]
    DIRECTION OUTPUT ;
    USE SIGNAL ;
    PORT
      LAYER M4 ;
        RECT  51.756 14.112 51.84 14.136 ;
    END
  END b[477]
  PIN b[478]
    DIRECTION OUTPUT ;
    USE SIGNAL ;
    PORT
      LAYER M4 ;
        RECT  51.756 14.256 51.84 14.28 ;
    END
  END b[478]
  PIN b[479]
    DIRECTION OUTPUT ;
    USE SIGNAL ;
    PORT
      LAYER M4 ;
        RECT  51.756 14.4 51.84 14.424 ;
    END
  END b[479]
  PIN b[47]
    DIRECTION OUTPUT ;
    USE SIGNAL ;
    PORT
      LAYER M4 ;
        RECT  51.756 45.504 51.84 45.528 ;
    END
  END b[47]
  PIN b[480]
    DIRECTION OUTPUT ;
    USE SIGNAL ;
    PORT
      LAYER M4 ;
        RECT  51.756 19.152 51.84 19.176 ;
    END
  END b[480]
  PIN b[481]
    DIRECTION OUTPUT ;
    USE SIGNAL ;
    PORT
      LAYER M4 ;
        RECT  51.756 19.296 51.84 19.32 ;
    END
  END b[481]
  PIN b[482]
    DIRECTION OUTPUT ;
    USE SIGNAL ;
    PORT
      LAYER M4 ;
        RECT  51.756 19.44 51.84 19.464 ;
    END
  END b[482]
  PIN b[483]
    DIRECTION OUTPUT ;
    USE SIGNAL ;
    PORT
      LAYER M4 ;
        RECT  51.756 19.584 51.84 19.608 ;
    END
  END b[483]
  PIN b[484]
    DIRECTION OUTPUT ;
    USE SIGNAL ;
    PORT
      LAYER M4 ;
        RECT  51.756 19.728 51.84 19.752 ;
    END
  END b[484]
  PIN b[485]
    DIRECTION OUTPUT ;
    USE SIGNAL ;
    PORT
      LAYER M4 ;
        RECT  51.756 19.872 51.84 19.896 ;
    END
  END b[485]
  PIN b[486]
    DIRECTION OUTPUT ;
    USE SIGNAL ;
    PORT
      LAYER M4 ;
        RECT  51.756 20.016 51.84 20.04 ;
    END
  END b[486]
  PIN b[487]
    DIRECTION OUTPUT ;
    USE SIGNAL ;
    PORT
      LAYER M4 ;
        RECT  51.756 20.16 51.84 20.184 ;
    END
  END b[487]
  PIN b[488]
    DIRECTION OUTPUT ;
    USE SIGNAL ;
    PORT
      LAYER M4 ;
        RECT  51.756 20.304 51.84 20.328 ;
    END
  END b[488]
  PIN b[489]
    DIRECTION OUTPUT ;
    USE SIGNAL ;
    PORT
      LAYER M4 ;
        RECT  51.756 20.448 51.84 20.472 ;
    END
  END b[489]
  PIN b[48]
    DIRECTION OUTPUT ;
    USE SIGNAL ;
    PORT
      LAYER M4 ;
        RECT  51.756 45.648 51.84 45.672 ;
    END
  END b[48]
  PIN b[490]
    DIRECTION OUTPUT ;
    USE SIGNAL ;
    PORT
      LAYER M4 ;
        RECT  51.756 20.592 51.84 20.616 ;
    END
  END b[490]
  PIN b[491]
    DIRECTION OUTPUT ;
    USE SIGNAL ;
    PORT
      LAYER M4 ;
        RECT  51.756 20.736 51.84 20.76 ;
    END
  END b[491]
  PIN b[492]
    DIRECTION OUTPUT ;
    USE SIGNAL ;
    PORT
      LAYER M4 ;
        RECT  51.756 20.88 51.84 20.904 ;
    END
  END b[492]
  PIN b[493]
    DIRECTION OUTPUT ;
    USE SIGNAL ;
    PORT
      LAYER M4 ;
        RECT  51.756 21.024 51.84 21.048 ;
    END
  END b[493]
  PIN b[494]
    DIRECTION OUTPUT ;
    USE SIGNAL ;
    PORT
      LAYER M4 ;
        RECT  51.756 21.168 51.84 21.192 ;
    END
  END b[494]
  PIN b[495]
    DIRECTION OUTPUT ;
    USE SIGNAL ;
    PORT
      LAYER M4 ;
        RECT  51.756 21.312 51.84 21.336 ;
    END
  END b[495]
  PIN b[496]
    DIRECTION OUTPUT ;
    USE SIGNAL ;
    PORT
      LAYER M4 ;
        RECT  51.756 21.456 51.84 21.48 ;
    END
  END b[496]
  PIN b[497]
    DIRECTION OUTPUT ;
    USE SIGNAL ;
    PORT
      LAYER M4 ;
        RECT  51.756 21.6 51.84 21.624 ;
    END
  END b[497]
  PIN b[498]
    DIRECTION OUTPUT ;
    USE SIGNAL ;
    PORT
      LAYER M4 ;
        RECT  51.756 21.744 51.84 21.768 ;
    END
  END b[498]
  PIN b[499]
    DIRECTION OUTPUT ;
    USE SIGNAL ;
    PORT
      LAYER M4 ;
        RECT  51.756 21.888 51.84 21.912 ;
    END
  END b[499]
  PIN b[49]
    DIRECTION OUTPUT ;
    USE SIGNAL ;
    PORT
      LAYER M4 ;
        RECT  51.756 45.792 51.84 45.816 ;
    END
  END b[49]
  PIN b[4]
    DIRECTION OUTPUT ;
    USE SIGNAL ;
    PORT
      LAYER M4 ;
        RECT  51.756 34.704 51.84 34.728 ;
    END
  END b[4]
  PIN b[500]
    DIRECTION OUTPUT ;
    USE SIGNAL ;
    PORT
      LAYER M4 ;
        RECT  51.756 22.032 51.84 22.056 ;
    END
  END b[500]
  PIN b[501]
    DIRECTION OUTPUT ;
    USE SIGNAL ;
    PORT
      LAYER M4 ;
        RECT  51.756 22.176 51.84 22.2 ;
    END
  END b[501]
  PIN b[502]
    DIRECTION OUTPUT ;
    USE SIGNAL ;
    PORT
      LAYER M4 ;
        RECT  51.756 22.32 51.84 22.344 ;
    END
  END b[502]
  PIN b[503]
    DIRECTION OUTPUT ;
    USE SIGNAL ;
    PORT
      LAYER M4 ;
        RECT  51.756 22.464 51.84 22.488 ;
    END
  END b[503]
  PIN b[504]
    DIRECTION OUTPUT ;
    USE SIGNAL ;
    PORT
      LAYER M4 ;
        RECT  51.756 22.608 51.84 22.632 ;
    END
  END b[504]
  PIN b[505]
    DIRECTION OUTPUT ;
    USE SIGNAL ;
    PORT
      LAYER M4 ;
        RECT  51.756 22.752 51.84 22.776 ;
    END
  END b[505]
  PIN b[506]
    DIRECTION OUTPUT ;
    USE SIGNAL ;
    PORT
      LAYER M4 ;
        RECT  51.756 22.896 51.84 22.92 ;
    END
  END b[506]
  PIN b[507]
    DIRECTION OUTPUT ;
    USE SIGNAL ;
    PORT
      LAYER M4 ;
        RECT  51.756 23.04 51.84 23.064 ;
    END
  END b[507]
  PIN b[508]
    DIRECTION OUTPUT ;
    USE SIGNAL ;
    PORT
      LAYER M4 ;
        RECT  51.756 23.184 51.84 23.208 ;
    END
  END b[508]
  PIN b[509]
    DIRECTION OUTPUT ;
    USE SIGNAL ;
    PORT
      LAYER M4 ;
        RECT  51.756 23.328 51.84 23.352 ;
    END
  END b[509]
  PIN b[50]
    DIRECTION OUTPUT ;
    USE SIGNAL ;
    PORT
      LAYER M4 ;
        RECT  51.756 45.936 51.84 45.96 ;
    END
  END b[50]
  PIN b[510]
    DIRECTION OUTPUT ;
    USE SIGNAL ;
    PORT
      LAYER M4 ;
        RECT  51.756 23.472 51.84 23.496 ;
    END
  END b[510]
  PIN b[511]
    DIRECTION OUTPUT ;
    USE SIGNAL ;
    PORT
      LAYER M4 ;
        RECT  51.756 23.616 51.84 23.64 ;
    END
  END b[511]
  PIN b[512]
    DIRECTION OUTPUT ;
    USE SIGNAL ;
    PORT
      LAYER M4 ;
        RECT  51.756 58.32 51.84 58.344 ;
    END
  END b[512]
  PIN b[513]
    DIRECTION OUTPUT ;
    USE SIGNAL ;
    PORT
      LAYER M4 ;
        RECT  51.756 58.464 51.84 58.488 ;
    END
  END b[513]
  PIN b[514]
    DIRECTION OUTPUT ;
    USE SIGNAL ;
    PORT
      LAYER M4 ;
        RECT  51.756 58.608 51.84 58.632 ;
    END
  END b[514]
  PIN b[515]
    DIRECTION OUTPUT ;
    USE SIGNAL ;
    PORT
      LAYER M4 ;
        RECT  51.756 58.752 51.84 58.776 ;
    END
  END b[515]
  PIN b[516]
    DIRECTION OUTPUT ;
    USE SIGNAL ;
    PORT
      LAYER M4 ;
        RECT  51.756 58.896 51.84 58.92 ;
    END
  END b[516]
  PIN b[517]
    DIRECTION OUTPUT ;
    USE SIGNAL ;
    PORT
      LAYER M4 ;
        RECT  51.756 59.04 51.84 59.064 ;
    END
  END b[517]
  PIN b[518]
    DIRECTION OUTPUT ;
    USE SIGNAL ;
    PORT
      LAYER M4 ;
        RECT  51.756 59.184 51.84 59.208 ;
    END
  END b[518]
  PIN b[519]
    DIRECTION OUTPUT ;
    USE SIGNAL ;
    PORT
      LAYER M4 ;
        RECT  51.756 59.328 51.84 59.352 ;
    END
  END b[519]
  PIN b[51]
    DIRECTION OUTPUT ;
    USE SIGNAL ;
    PORT
      LAYER M4 ;
        RECT  51.756 46.08 51.84 46.104 ;
    END
  END b[51]
  PIN b[520]
    DIRECTION OUTPUT ;
    USE SIGNAL ;
    PORT
      LAYER M4 ;
        RECT  51.756 59.472 51.84 59.496 ;
    END
  END b[520]
  PIN b[521]
    DIRECTION OUTPUT ;
    USE SIGNAL ;
    PORT
      LAYER M4 ;
        RECT  51.756 59.616 51.84 59.64 ;
    END
  END b[521]
  PIN b[522]
    DIRECTION OUTPUT ;
    USE SIGNAL ;
    PORT
      LAYER M4 ;
        RECT  51.756 59.76 51.84 59.784 ;
    END
  END b[522]
  PIN b[523]
    DIRECTION OUTPUT ;
    USE SIGNAL ;
    PORT
      LAYER M4 ;
        RECT  51.756 59.904 51.84 59.928 ;
    END
  END b[523]
  PIN b[524]
    DIRECTION OUTPUT ;
    USE SIGNAL ;
    PORT
      LAYER M4 ;
        RECT  51.756 60.048 51.84 60.072 ;
    END
  END b[524]
  PIN b[525]
    DIRECTION OUTPUT ;
    USE SIGNAL ;
    PORT
      LAYER M4 ;
        RECT  51.756 60.192 51.84 60.216 ;
    END
  END b[525]
  PIN b[526]
    DIRECTION OUTPUT ;
    USE SIGNAL ;
    PORT
      LAYER M4 ;
        RECT  51.756 60.336 51.84 60.36 ;
    END
  END b[526]
  PIN b[527]
    DIRECTION OUTPUT ;
    USE SIGNAL ;
    PORT
      LAYER M4 ;
        RECT  51.756 60.48 51.84 60.504 ;
    END
  END b[527]
  PIN b[52]
    DIRECTION OUTPUT ;
    USE SIGNAL ;
    PORT
      LAYER M4 ;
        RECT  51.756 46.224 51.84 46.248 ;
    END
  END b[52]
  PIN b[53]
    DIRECTION OUTPUT ;
    USE SIGNAL ;
    PORT
      LAYER M4 ;
        RECT  51.756 46.368 51.84 46.392 ;
    END
  END b[53]
  PIN b[54]
    DIRECTION OUTPUT ;
    USE SIGNAL ;
    PORT
      LAYER M4 ;
        RECT  51.756 46.512 51.84 46.536 ;
    END
  END b[54]
  PIN b[55]
    DIRECTION OUTPUT ;
    USE SIGNAL ;
    PORT
      LAYER M4 ;
        RECT  51.756 46.656 51.84 46.68 ;
    END
  END b[55]
  PIN b[56]
    DIRECTION OUTPUT ;
    USE SIGNAL ;
    PORT
      LAYER M4 ;
        RECT  51.756 46.8 51.84 46.824 ;
    END
  END b[56]
  PIN b[57]
    DIRECTION OUTPUT ;
    USE SIGNAL ;
    PORT
      LAYER M4 ;
        RECT  51.756 46.944 51.84 46.968 ;
    END
  END b[57]
  PIN b[58]
    DIRECTION OUTPUT ;
    USE SIGNAL ;
    PORT
      LAYER M4 ;
        RECT  51.756 47.088 51.84 47.112 ;
    END
  END b[58]
  PIN b[59]
    DIRECTION OUTPUT ;
    USE SIGNAL ;
    PORT
      LAYER M4 ;
        RECT  51.756 47.232 51.84 47.256 ;
    END
  END b[59]
  PIN b[5]
    DIRECTION OUTPUT ;
    USE SIGNAL ;
    PORT
      LAYER M4 ;
        RECT  51.756 34.848 51.84 34.872 ;
    END
  END b[5]
  PIN b[60]
    DIRECTION OUTPUT ;
    USE SIGNAL ;
    PORT
      LAYER M4 ;
        RECT  51.756 47.376 51.84 47.4 ;
    END
  END b[60]
  PIN b[61]
    DIRECTION OUTPUT ;
    USE SIGNAL ;
    PORT
      LAYER M4 ;
        RECT  51.756 47.52 51.84 47.544 ;
    END
  END b[61]
  PIN b[62]
    DIRECTION OUTPUT ;
    USE SIGNAL ;
    PORT
      LAYER M4 ;
        RECT  51.756 47.664 51.84 47.688 ;
    END
  END b[62]
  PIN b[63]
    DIRECTION OUTPUT ;
    USE SIGNAL ;
    PORT
      LAYER M4 ;
        RECT  51.756 47.808 51.84 47.832 ;
    END
  END b[63]
  PIN b[64]
    DIRECTION OUTPUT ;
    USE SIGNAL ;
    PORT
      LAYER M4 ;
        RECT  51.756 67.536 51.84 67.56 ;
    END
  END b[64]
  PIN b[65]
    DIRECTION OUTPUT ;
    USE SIGNAL ;
    PORT
      LAYER M4 ;
        RECT  51.756 67.68 51.84 67.704 ;
    END
  END b[65]
  PIN b[66]
    DIRECTION OUTPUT ;
    USE SIGNAL ;
    PORT
      LAYER M4 ;
        RECT  51.756 67.824 51.84 67.848 ;
    END
  END b[66]
  PIN b[67]
    DIRECTION OUTPUT ;
    USE SIGNAL ;
    PORT
      LAYER M4 ;
        RECT  51.756 67.968 51.84 67.992 ;
    END
  END b[67]
  PIN b[68]
    DIRECTION OUTPUT ;
    USE SIGNAL ;
    PORT
      LAYER M4 ;
        RECT  51.756 68.112 51.84 68.136 ;
    END
  END b[68]
  PIN b[69]
    DIRECTION OUTPUT ;
    USE SIGNAL ;
    PORT
      LAYER M4 ;
        RECT  51.756 68.256 51.84 68.28 ;
    END
  END b[69]
  PIN b[6]
    DIRECTION OUTPUT ;
    USE SIGNAL ;
    PORT
      LAYER M4 ;
        RECT  51.756 34.992 51.84 35.016 ;
    END
  END b[6]
  PIN b[70]
    DIRECTION OUTPUT ;
    USE SIGNAL ;
    PORT
      LAYER M4 ;
        RECT  51.756 68.4 51.84 68.424 ;
    END
  END b[70]
  PIN b[71]
    DIRECTION OUTPUT ;
    USE SIGNAL ;
    PORT
      LAYER M4 ;
        RECT  51.756 68.544 51.84 68.568 ;
    END
  END b[71]
  PIN b[72]
    DIRECTION OUTPUT ;
    USE SIGNAL ;
    PORT
      LAYER M4 ;
        RECT  51.756 68.688 51.84 68.712 ;
    END
  END b[72]
  PIN b[73]
    DIRECTION OUTPUT ;
    USE SIGNAL ;
    PORT
      LAYER M4 ;
        RECT  51.756 68.832 51.84 68.856 ;
    END
  END b[73]
  PIN b[74]
    DIRECTION OUTPUT ;
    USE SIGNAL ;
    PORT
      LAYER M4 ;
        RECT  51.756 68.976 51.84 69 ;
    END
  END b[74]
  PIN b[75]
    DIRECTION OUTPUT ;
    USE SIGNAL ;
    PORT
      LAYER M4 ;
        RECT  51.756 69.12 51.84 69.144 ;
    END
  END b[75]
  PIN b[76]
    DIRECTION OUTPUT ;
    USE SIGNAL ;
    PORT
      LAYER M4 ;
        RECT  51.756 69.264 51.84 69.288 ;
    END
  END b[76]
  PIN b[77]
    DIRECTION OUTPUT ;
    USE SIGNAL ;
    PORT
      LAYER M4 ;
        RECT  51.756 69.408 51.84 69.432 ;
    END
  END b[77]
  PIN b[78]
    DIRECTION OUTPUT ;
    USE SIGNAL ;
    PORT
      LAYER M4 ;
        RECT  51.756 69.552 51.84 69.576 ;
    END
  END b[78]
  PIN b[79]
    DIRECTION OUTPUT ;
    USE SIGNAL ;
    PORT
      LAYER M4 ;
        RECT  51.756 69.696 51.84 69.72 ;
    END
  END b[79]
  PIN b[7]
    DIRECTION OUTPUT ;
    USE SIGNAL ;
    PORT
      LAYER M4 ;
        RECT  51.756 35.136 51.84 35.16 ;
    END
  END b[7]
  PIN b[80]
    DIRECTION OUTPUT ;
    USE SIGNAL ;
    PORT
      LAYER M4 ;
        RECT  51.756 69.84 51.84 69.864 ;
    END
  END b[80]
  PIN b[81]
    DIRECTION OUTPUT ;
    USE SIGNAL ;
    PORT
      LAYER M4 ;
        RECT  51.756 69.984 51.84 70.008 ;
    END
  END b[81]
  PIN b[82]
    DIRECTION OUTPUT ;
    USE SIGNAL ;
    PORT
      LAYER M4 ;
        RECT  51.756 70.128 51.84 70.152 ;
    END
  END b[82]
  PIN b[83]
    DIRECTION OUTPUT ;
    USE SIGNAL ;
    PORT
      LAYER M4 ;
        RECT  51.756 70.272 51.84 70.296 ;
    END
  END b[83]
  PIN b[84]
    DIRECTION OUTPUT ;
    USE SIGNAL ;
    PORT
      LAYER M4 ;
        RECT  51.756 70.416 51.84 70.44 ;
    END
  END b[84]
  PIN b[85]
    DIRECTION OUTPUT ;
    USE SIGNAL ;
    PORT
      LAYER M4 ;
        RECT  51.756 70.56 51.84 70.584 ;
    END
  END b[85]
  PIN b[86]
    DIRECTION OUTPUT ;
    USE SIGNAL ;
    PORT
      LAYER M4 ;
        RECT  51.756 70.704 51.84 70.728 ;
    END
  END b[86]
  PIN b[87]
    DIRECTION OUTPUT ;
    USE SIGNAL ;
    PORT
      LAYER M4 ;
        RECT  51.756 70.848 51.84 70.872 ;
    END
  END b[87]
  PIN b[88]
    DIRECTION OUTPUT ;
    USE SIGNAL ;
    PORT
      LAYER M4 ;
        RECT  51.756 70.992 51.84 71.016 ;
    END
  END b[88]
  PIN b[89]
    DIRECTION OUTPUT ;
    USE SIGNAL ;
    PORT
      LAYER M4 ;
        RECT  51.756 71.136 51.84 71.16 ;
    END
  END b[89]
  PIN b[8]
    DIRECTION OUTPUT ;
    USE SIGNAL ;
    PORT
      LAYER M4 ;
        RECT  51.756 35.28 51.84 35.304 ;
    END
  END b[8]
  PIN b[90]
    DIRECTION OUTPUT ;
    USE SIGNAL ;
    PORT
      LAYER M4 ;
        RECT  51.756 71.28 51.84 71.304 ;
    END
  END b[90]
  PIN b[91]
    DIRECTION OUTPUT ;
    USE SIGNAL ;
    PORT
      LAYER M4 ;
        RECT  51.756 71.424 51.84 71.448 ;
    END
  END b[91]
  PIN b[92]
    DIRECTION OUTPUT ;
    USE SIGNAL ;
    PORT
      LAYER M4 ;
        RECT  51.756 71.568 51.84 71.592 ;
    END
  END b[92]
  PIN b[93]
    DIRECTION OUTPUT ;
    USE SIGNAL ;
    PORT
      LAYER M4 ;
        RECT  51.756 71.712 51.84 71.736 ;
    END
  END b[93]
  PIN b[94]
    DIRECTION OUTPUT ;
    USE SIGNAL ;
    PORT
      LAYER M4 ;
        RECT  51.756 71.856 51.84 71.88 ;
    END
  END b[94]
  PIN b[95]
    DIRECTION OUTPUT ;
    USE SIGNAL ;
    PORT
      LAYER M4 ;
        RECT  51.756 72 51.84 72.024 ;
    END
  END b[95]
  PIN b[96]
    DIRECTION OUTPUT ;
    USE SIGNAL ;
    PORT
      LAYER M4 ;
        RECT  51.756 76.752 51.84 76.776 ;
    END
  END b[96]
  PIN b[97]
    DIRECTION OUTPUT ;
    USE SIGNAL ;
    PORT
      LAYER M4 ;
        RECT  51.756 76.896 51.84 76.92 ;
    END
  END b[97]
  PIN b[98]
    DIRECTION OUTPUT ;
    USE SIGNAL ;
    PORT
      LAYER M4 ;
        RECT  51.756 77.04 51.84 77.064 ;
    END
  END b[98]
  PIN b[99]
    DIRECTION OUTPUT ;
    USE SIGNAL ;
    PORT
      LAYER M4 ;
        RECT  51.756 77.184 51.84 77.208 ;
    END
  END b[99]
  PIN b[9]
    DIRECTION OUTPUT ;
    USE SIGNAL ;
    PORT
      LAYER M4 ;
        RECT  51.756 35.424 51.84 35.448 ;
    END
  END b[9]
  PIN ck
    DIRECTION INPUT ;
    USE SIGNAL ;
    PORT
      LAYER M5 ;
        RECT  20.88 0 20.904 0.084 ;
    END
  END ck
  PIN ck_s
    DIRECTION INPUT ;
    USE SIGNAL ;
    PORT
      LAYER M5 ;
        RECT  21.024 0 21.048 0.084 ;
    END
  END ck_s
  PIN en
    DIRECTION INPUT ;
    USE SIGNAL ;
    PORT
      LAYER M5 ;
        RECT  21.168 0 21.192 0.084 ;
    END
  END en
  PIN fault
    DIRECTION OUTPUT ;
    USE SIGNAL ;
    PORT
      LAYER M3 ;
        RECT  20.952 82.043 20.97 82.08 ;
    END
  END fault
  PIN k0
    DIRECTION INPUT ;
    USE SIGNAL ;
    PORT
      LAYER M5 ;
        RECT  21.312 0 21.336 0.084 ;
    END
  END k0
  PIN k1
    DIRECTION INPUT ;
    USE SIGNAL ;
    PORT
      LAYER M5 ;
        RECT  21.456 0 21.48 0.084 ;
    END
  END k1
  PIN k2
    DIRECTION INPUT ;
    USE SIGNAL ;
    PORT
      LAYER M5 ;
        RECT  21.6 0 21.624 0.084 ;
    END
  END k2
  PIN rs
    DIRECTION INPUT ;
    USE SIGNAL ;
    PORT
      LAYER M5 ;
        RECT  21.744 0 21.768 0.084 ;
    END
  END rs
  PIN tie_hi
    DIRECTION OUTPUT ;
    USE SIGNAL ;
    PORT
      LAYER M3 ;
        RECT  21.06 82.043 21.078 82.08 ;
    END
  END tie_hi
  PIN tie_lo
    DIRECTION OUTPUT ;
    USE SIGNAL ;
    PORT
      LAYER M3 ;
        RECT  21.168 82.043 21.186 82.08 ;
    END
  END tie_lo
  PIN VDD
    DIRECTION INOUT ;
    USE POWER ;
    PORT
      LAYER M5 ;
        RECT  48.492 2.151 48.612 79.929 ;
        RECT  45.792 2.151 45.912 79.929 ;
        RECT  43.092 2.151 43.212 79.929 ;
        RECT  40.392 2.151 40.512 79.929 ;
        RECT  37.692 2.151 37.812 79.929 ;
        RECT  34.992 2.151 35.112 79.929 ;
        RECT  32.292 2.151 32.412 79.929 ;
        RECT  29.592 2.151 29.712 79.929 ;
        RECT  26.892 2.151 27.012 79.929 ;
        RECT  24.192 2.151 24.312 79.929 ;
        RECT  21.492 2.151 21.612 79.929 ;
        RECT  18.792 2.151 18.912 79.929 ;
        RECT  16.092 2.151 16.212 79.929 ;
        RECT  13.392 2.151 13.512 79.929 ;
        RECT  10.692 2.151 10.812 79.929 ;
        RECT  7.992 2.151 8.112 79.929 ;
        RECT  5.292 2.151 5.412 79.929 ;
        RECT  2.592 2.151 2.712 79.929 ;
    END
  END VDD
  PIN VSS
    DIRECTION INOUT ;
    USE GROUND ;
    PORT
      LAYER M5 ;
        RECT  48.3 2.137 48.42 79.943 ;
        RECT  45.6 2.137 45.72 79.943 ;
        RECT  42.9 2.137 43.02 79.943 ;
        RECT  40.2 2.137 40.32 79.943 ;
        RECT  37.5 2.137 37.62 79.943 ;
        RECT  34.8 2.137 34.92 79.943 ;
        RECT  32.1 2.137 32.22 79.943 ;
        RECT  29.4 2.137 29.52 79.943 ;
        RECT  26.7 2.137 26.82 79.943 ;
        RECT  24 2.137 24.12 79.943 ;
        RECT  21.3 2.137 21.42 79.943 ;
        RECT  18.6 2.137 18.72 79.943 ;
        RECT  15.9 2.137 16.02 79.943 ;
        RECT  13.2 2.137 13.32 79.943 ;
        RECT  10.5 2.137 10.62 79.943 ;
        RECT  7.8 2.137 7.92 79.943 ;
        RECT  5.1 2.137 5.22 79.943 ;
        RECT  2.4 2.137 2.52 79.943 ;
    END
  END VSS
  # OT_OBS_CLOSED layer=M5 d_um=1.536 added=410
  OBS
    LAYER LVTN ;
     RECT  18.954 12.285 19.494 12.42 ;
     RECT  19.656 12.285 19.98 12.42 ;
     RECT  18.036 13.5 18.36 13.635 ;
     RECT  23.004 21.465 23.328 21.6 ;
     RECT  23.166 27.54 23.706 27.675 ;
     RECT  9.288 30.645 9.612 30.78 ;
     RECT  13.068 50.22 13.392 50.355 ;
     RECT  11.88 51.705 12.204 51.84 ;
     RECT  16.308 61.965 16.632 62.1 ;
     RECT  13.716 73.44 14.04 73.575 ;
     RECT  11.124 74.385 11.448 74.52 ;
     RECT  11.772 74.385 12.096 74.52 ;
     RECT  12.366 75.465 13.014 75.6 ;
     RECT  18.036 75.6 18.684 75.735 ;
     RECT  14.04 77.22 14.364 77.355 ;
     RECT  14.742 77.22 15.066 77.355 ;
     RECT  11.07 77.625 11.718 77.76 ;
     RECT  16.524 78.165 17.172 78.3 ;
     RECT  18.09 78.3 18.414 78.435 ;
     RECT  18.036 78.705 18.36 78.84 ;
    LAYER LVTP ;
     RECT  18.954 12.15 19.494 12.285 ;
     RECT  19.656 12.15 19.98 12.285 ;
     RECT  18.036 13.635 18.36 13.77 ;
     RECT  23.004 21.33 23.328 21.465 ;
     RECT  23.166 27.675 23.706 27.81 ;
     RECT  9.288 30.51 9.612 30.645 ;
     RECT  13.068 50.355 13.392 50.49 ;
     RECT  11.88 51.57 12.204 51.705 ;
     RECT  16.308 61.83 16.632 61.965 ;
     RECT  13.716 73.575 14.04 73.71 ;
     RECT  11.124 74.25 11.448 74.385 ;
     RECT  11.772 74.25 12.096 74.385 ;
     RECT  12.366 75.33 13.014 75.465 ;
     RECT  18.036 75.735 18.684 75.87 ;
     RECT  14.04 77.355 14.364 77.49 ;
     RECT  14.742 77.355 15.066 77.49 ;
     RECT  11.07 77.49 11.718 77.625 ;
     RECT  16.524 78.03 17.172 78.165 ;
     RECT  18.09 78.435 18.414 78.57 ;
     RECT  18.036 78.57 18.36 78.705 ;
    LAYER RVTN ;
     RECT  2.16 2.16 49.68 2.295 ;
     RECT  2.16 2.565 49.68 2.835 ;
     RECT  2.16 3.105 49.68 3.375 ;
     RECT  2.16 3.645 49.68 3.915 ;
     RECT  2.16 4.185 49.68 4.455 ;
     RECT  2.16 4.725 49.68 4.995 ;
     RECT  2.16 5.265 49.68 5.535 ;
     RECT  2.16 5.805 49.68 6.075 ;
     RECT  2.16 6.345 49.68 6.615 ;
     RECT  2.16 6.885 49.68 7.155 ;
     RECT  2.16 7.425 49.68 7.695 ;
     RECT  2.16 7.965 49.68 8.235 ;
     RECT  2.16 8.505 49.68 8.775 ;
     RECT  2.16 9.045 49.68 9.315 ;
     RECT  2.16 9.585 49.68 9.855 ;
     RECT  2.16 10.125 49.68 10.395 ;
     RECT  2.16 10.665 49.68 10.935 ;
     RECT  2.16 11.205 49.68 11.475 ;
     RECT  2.16 11.745 49.68 12.015 ;
     RECT  2.16 12.285 18.954 12.42 ;
     RECT  19.494 12.285 19.656 12.42 ;
     RECT  19.98 12.285 49.68 12.42 ;
     RECT  2.16 12.42 49.68 12.555 ;
     RECT  2.16 12.825 49.68 13.095 ;
     RECT  2.16 13.365 49.68 13.5 ;
     RECT  2.16 13.5 18.036 13.635 ;
     RECT  18.36 13.5 49.68 13.635 ;
     RECT  2.16 13.905 49.68 14.175 ;
     RECT  2.16 14.445 49.68 14.715 ;
     RECT  2.16 14.985 49.68 15.255 ;
     RECT  2.16 15.525 49.68 15.795 ;
     RECT  2.16 16.065 49.68 16.335 ;
     RECT  2.16 16.605 49.68 16.875 ;
     RECT  2.16 17.145 49.68 17.415 ;
     RECT  2.16 17.685 49.68 17.955 ;
     RECT  2.16 18.225 49.68 18.495 ;
     RECT  2.16 18.765 49.68 19.035 ;
     RECT  2.16 19.305 49.68 19.575 ;
     RECT  2.16 19.845 49.68 20.115 ;
     RECT  2.16 20.385 49.68 20.655 ;
     RECT  2.16 20.925 49.68 21.195 ;
     RECT  2.16 21.465 23.004 21.6 ;
     RECT  23.328 21.465 49.68 21.6 ;
     RECT  2.16 21.6 49.68 21.735 ;
     RECT  2.16 22.005 49.68 22.275 ;
     RECT  2.16 22.545 49.68 22.815 ;
     RECT  2.16 23.085 49.68 23.355 ;
     RECT  2.16 23.625 49.68 23.895 ;
     RECT  2.16 24.165 49.68 24.435 ;
     RECT  2.16 24.705 49.68 24.975 ;
     RECT  2.16 25.245 49.68 25.515 ;
     RECT  2.16 25.785 49.68 26.055 ;
     RECT  2.16 26.325 49.68 26.595 ;
     RECT  2.16 26.865 49.68 27.135 ;
     RECT  2.16 27.405 49.68 27.54 ;
     RECT  2.16 27.54 23.166 27.675 ;
     RECT  23.706 27.54 49.68 27.675 ;
     RECT  2.16 27.945 49.68 28.215 ;
     RECT  2.16 28.485 49.68 28.755 ;
     RECT  2.16 29.025 49.68 29.295 ;
     RECT  2.16 29.565 49.68 29.835 ;
     RECT  2.16 30.105 49.68 30.375 ;
     RECT  2.16 30.645 9.288 30.78 ;
     RECT  9.612 30.645 49.68 30.78 ;
     RECT  2.16 30.78 49.68 30.915 ;
     RECT  2.16 31.185 49.68 31.455 ;
     RECT  2.16 31.725 49.68 31.995 ;
     RECT  2.16 32.265 49.68 32.535 ;
     RECT  2.16 32.805 49.68 33.075 ;
     RECT  2.16 33.345 49.68 33.615 ;
     RECT  2.16 33.885 49.68 34.155 ;
     RECT  2.16 34.425 49.68 34.695 ;
     RECT  2.16 34.965 49.68 35.235 ;
     RECT  2.16 35.505 49.68 35.775 ;
     RECT  2.16 36.045 49.68 36.315 ;
     RECT  2.16 36.585 49.68 36.855 ;
     RECT  2.16 37.125 49.68 37.395 ;
     RECT  2.16 37.665 49.68 37.935 ;
     RECT  2.16 38.205 49.68 38.475 ;
     RECT  2.16 38.745 49.68 39.015 ;
     RECT  2.16 39.285 49.68 39.555 ;
     RECT  2.16 39.825 49.68 40.095 ;
     RECT  2.16 40.365 49.68 40.635 ;
     RECT  2.16 40.905 49.68 41.175 ;
     RECT  2.16 41.445 49.68 41.715 ;
     RECT  2.16 41.985 49.68 42.255 ;
     RECT  2.16 42.525 49.68 42.795 ;
     RECT  2.16 43.065 49.68 43.335 ;
     RECT  2.16 43.605 49.68 43.875 ;
     RECT  2.16 44.145 49.68 44.415 ;
     RECT  2.16 44.685 49.68 44.955 ;
     RECT  2.16 45.225 49.68 45.495 ;
     RECT  2.16 45.765 49.68 46.035 ;
     RECT  2.16 46.305 49.68 46.575 ;
     RECT  2.16 46.845 49.68 47.115 ;
     RECT  2.16 47.385 49.68 47.655 ;
     RECT  2.16 47.925 49.68 48.195 ;
     RECT  2.16 48.465 49.68 48.735 ;
     RECT  2.16 49.005 49.68 49.275 ;
     RECT  2.16 49.545 49.68 49.815 ;
     RECT  2.16 50.085 49.68 50.22 ;
     RECT  2.16 50.22 13.068 50.355 ;
     RECT  13.392 50.22 49.68 50.355 ;
     RECT  2.16 50.625 49.68 50.895 ;
     RECT  2.16 51.165 49.68 51.435 ;
     RECT  2.16 51.705 11.88 51.84 ;
     RECT  12.204 51.705 49.68 51.84 ;
     RECT  2.16 51.84 49.68 51.975 ;
     RECT  2.16 52.245 49.68 52.515 ;
     RECT  2.16 52.785 49.68 53.055 ;
     RECT  2.16 53.325 49.68 53.595 ;
     RECT  2.16 53.865 49.68 54.135 ;
     RECT  2.16 54.405 49.68 54.675 ;
     RECT  2.16 54.945 49.68 55.215 ;
     RECT  2.16 55.485 49.68 55.755 ;
     RECT  2.16 56.025 49.68 56.295 ;
     RECT  2.16 56.565 49.68 56.835 ;
     RECT  2.16 57.105 49.68 57.375 ;
     RECT  2.16 57.645 49.68 57.915 ;
     RECT  2.16 58.185 49.68 58.455 ;
     RECT  2.16 58.725 49.68 58.995 ;
     RECT  2.16 59.265 49.68 59.535 ;
     RECT  2.16 59.805 49.68 60.075 ;
     RECT  2.16 60.345 49.68 60.615 ;
     RECT  2.16 60.885 49.68 61.155 ;
     RECT  2.16 61.425 49.68 61.695 ;
     RECT  2.16 61.965 16.308 62.1 ;
     RECT  16.632 61.965 49.68 62.1 ;
     RECT  2.16 62.1 49.68 62.235 ;
     RECT  2.16 62.505 49.68 62.775 ;
     RECT  2.16 63.045 49.68 63.315 ;
     RECT  2.16 63.585 49.68 63.855 ;
     RECT  2.16 64.125 49.68 64.395 ;
     RECT  2.16 64.665 49.68 64.935 ;
     RECT  2.16 65.205 49.68 65.475 ;
     RECT  2.16 65.745 49.68 66.015 ;
     RECT  2.16 66.285 49.68 66.555 ;
     RECT  2.16 66.825 49.68 67.095 ;
     RECT  2.16 67.365 49.68 67.635 ;
     RECT  2.16 67.905 49.68 68.175 ;
     RECT  2.16 68.445 49.68 68.715 ;
     RECT  2.16 68.985 49.68 69.255 ;
     RECT  2.16 69.525 49.68 69.795 ;
     RECT  2.16 70.065 49.68 70.335 ;
     RECT  2.16 70.605 49.68 70.875 ;
     RECT  2.16 71.145 49.68 71.415 ;
     RECT  2.16 71.685 49.68 71.955 ;
     RECT  2.16 72.225 49.68 72.495 ;
     RECT  2.16 72.765 49.68 73.035 ;
     RECT  2.16 73.305 49.68 73.44 ;
     RECT  2.16 73.44 13.716 73.575 ;
     RECT  14.04 73.44 49.68 73.575 ;
     RECT  2.16 73.845 49.68 74.115 ;
     RECT  2.16 74.385 11.124 74.52 ;
     RECT  11.448 74.385 11.772 74.52 ;
     RECT  12.096 74.385 49.68 74.52 ;
     RECT  2.16 74.52 49.68 74.655 ;
     RECT  2.16 74.925 49.68 75.195 ;
     RECT  2.16 75.465 12.366 75.6 ;
     RECT  13.014 75.465 49.68 75.6 ;
     RECT  2.16 75.6 18.036 75.735 ;
     RECT  18.684 75.6 49.68 75.735 ;
     RECT  2.16 76.005 49.68 76.275 ;
     RECT  2.16 76.545 49.68 76.815 ;
     RECT  2.16 77.085 49.68 77.22 ;
     RECT  2.16 77.22 14.04 77.355 ;
     RECT  14.364 77.22 14.742 77.355 ;
     RECT  15.066 77.22 49.68 77.355 ;
     RECT  2.16 77.625 11.07 77.76 ;
     RECT  11.718 77.625 49.68 77.76 ;
     RECT  2.16 77.76 49.68 77.895 ;
     RECT  2.16 78.165 16.524 78.3 ;
     RECT  17.172 78.165 49.68 78.3 ;
     RECT  2.16 78.3 18.09 78.435 ;
     RECT  18.414 78.3 49.68 78.435 ;
     RECT  2.16 78.705 18.036 78.84 ;
     RECT  18.36 78.705 49.68 78.84 ;
     RECT  2.16 78.84 49.68 78.975 ;
     RECT  2.16 79.245 49.68 79.515 ;
     RECT  2.16 79.785 49.68 79.92 ;
    LAYER RVTP ;
     RECT  2.16 2.295 49.68 2.565 ;
     RECT  2.16 2.835 49.68 3.105 ;
     RECT  2.16 3.375 49.68 3.645 ;
     RECT  2.16 3.915 49.68 4.185 ;
     RECT  2.16 4.455 49.68 4.725 ;
     RECT  2.16 4.995 49.68 5.265 ;
     RECT  2.16 5.535 49.68 5.805 ;
     RECT  2.16 6.075 49.68 6.345 ;
     RECT  2.16 6.615 49.68 6.885 ;
     RECT  2.16 7.155 49.68 7.425 ;
     RECT  2.16 7.695 49.68 7.965 ;
     RECT  2.16 8.235 49.68 8.505 ;
     RECT  2.16 8.775 49.68 9.045 ;
     RECT  2.16 9.315 49.68 9.585 ;
     RECT  2.16 9.855 49.68 10.125 ;
     RECT  2.16 10.395 49.68 10.665 ;
     RECT  2.16 10.935 49.68 11.205 ;
     RECT  2.16 11.475 49.68 11.745 ;
     RECT  2.16 12.015 49.68 12.15 ;
     RECT  2.16 12.15 18.954 12.285 ;
     RECT  19.494 12.15 19.656 12.285 ;
     RECT  19.98 12.15 49.68 12.285 ;
     RECT  2.16 12.555 49.68 12.825 ;
     RECT  2.16 13.095 49.68 13.365 ;
     RECT  2.16 13.635 18.036 13.77 ;
     RECT  18.36 13.635 49.68 13.77 ;
     RECT  2.16 13.77 49.68 13.905 ;
     RECT  2.16 14.175 49.68 14.445 ;
     RECT  2.16 14.715 49.68 14.985 ;
     RECT  2.16 15.255 49.68 15.525 ;
     RECT  2.16 15.795 49.68 16.065 ;
     RECT  2.16 16.335 49.68 16.605 ;
     RECT  2.16 16.875 49.68 17.145 ;
     RECT  2.16 17.415 49.68 17.685 ;
     RECT  2.16 17.955 49.68 18.225 ;
     RECT  2.16 18.495 49.68 18.765 ;
     RECT  2.16 19.035 49.68 19.305 ;
     RECT  2.16 19.575 49.68 19.845 ;
     RECT  2.16 20.115 49.68 20.385 ;
     RECT  2.16 20.655 49.68 20.925 ;
     RECT  2.16 21.195 49.68 21.33 ;
     RECT  2.16 21.33 23.004 21.465 ;
     RECT  23.328 21.33 49.68 21.465 ;
     RECT  2.16 21.735 49.68 22.005 ;
     RECT  2.16 22.275 49.68 22.545 ;
     RECT  2.16 22.815 49.68 23.085 ;
     RECT  2.16 23.355 49.68 23.625 ;
     RECT  2.16 23.895 49.68 24.165 ;
     RECT  2.16 24.435 49.68 24.705 ;
     RECT  2.16 24.975 49.68 25.245 ;
     RECT  2.16 25.515 49.68 25.785 ;
     RECT  2.16 26.055 49.68 26.325 ;
     RECT  2.16 26.595 49.68 26.865 ;
     RECT  2.16 27.135 49.68 27.405 ;
     RECT  2.16 27.675 23.166 27.81 ;
     RECT  23.706 27.675 49.68 27.81 ;
     RECT  2.16 27.81 49.68 27.945 ;
     RECT  2.16 28.215 49.68 28.485 ;
     RECT  2.16 28.755 49.68 29.025 ;
     RECT  2.16 29.295 49.68 29.565 ;
     RECT  2.16 29.835 49.68 30.105 ;
     RECT  2.16 30.375 49.68 30.51 ;
     RECT  2.16 30.51 9.288 30.645 ;
     RECT  9.612 30.51 49.68 30.645 ;
     RECT  2.16 30.915 49.68 31.185 ;
     RECT  2.16 31.455 49.68 31.725 ;
     RECT  2.16 31.995 49.68 32.265 ;
     RECT  2.16 32.535 49.68 32.805 ;
     RECT  2.16 33.075 49.68 33.345 ;
     RECT  2.16 33.615 49.68 33.885 ;
     RECT  2.16 34.155 49.68 34.425 ;
     RECT  2.16 34.695 49.68 34.965 ;
     RECT  2.16 35.235 49.68 35.505 ;
     RECT  2.16 35.775 49.68 36.045 ;
     RECT  2.16 36.315 49.68 36.585 ;
     RECT  2.16 36.855 49.68 37.125 ;
     RECT  2.16 37.395 49.68 37.665 ;
     RECT  2.16 37.935 49.68 38.205 ;
     RECT  2.16 38.475 49.68 38.745 ;
     RECT  2.16 39.015 49.68 39.285 ;
     RECT  2.16 39.555 49.68 39.825 ;
     RECT  2.16 40.095 49.68 40.365 ;
     RECT  2.16 40.635 49.68 40.905 ;
     RECT  2.16 41.175 49.68 41.445 ;
     RECT  2.16 41.715 49.68 41.985 ;
     RECT  2.16 42.255 49.68 42.525 ;
     RECT  2.16 42.795 49.68 43.065 ;
     RECT  2.16 43.335 49.68 43.605 ;
     RECT  2.16 43.875 49.68 44.145 ;
     RECT  2.16 44.415 49.68 44.685 ;
     RECT  2.16 44.955 49.68 45.225 ;
     RECT  2.16 45.495 49.68 45.765 ;
     RECT  2.16 46.035 49.68 46.305 ;
     RECT  2.16 46.575 49.68 46.845 ;
     RECT  2.16 47.115 49.68 47.385 ;
     RECT  2.16 47.655 49.68 47.925 ;
     RECT  2.16 48.195 49.68 48.465 ;
     RECT  2.16 48.735 49.68 49.005 ;
     RECT  2.16 49.275 49.68 49.545 ;
     RECT  2.16 49.815 49.68 50.085 ;
     RECT  2.16 50.355 13.068 50.49 ;
     RECT  13.392 50.355 49.68 50.49 ;
     RECT  2.16 50.49 49.68 50.625 ;
     RECT  2.16 50.895 49.68 51.165 ;
     RECT  2.16 51.435 49.68 51.57 ;
     RECT  2.16 51.57 11.88 51.705 ;
     RECT  12.204 51.57 49.68 51.705 ;
     RECT  2.16 51.975 49.68 52.245 ;
     RECT  2.16 52.515 49.68 52.785 ;
     RECT  2.16 53.055 49.68 53.325 ;
     RECT  2.16 53.595 49.68 53.865 ;
     RECT  2.16 54.135 49.68 54.405 ;
     RECT  2.16 54.675 49.68 54.945 ;
     RECT  2.16 55.215 49.68 55.485 ;
     RECT  2.16 55.755 49.68 56.025 ;
     RECT  2.16 56.295 49.68 56.565 ;
     RECT  2.16 56.835 49.68 57.105 ;
     RECT  2.16 57.375 49.68 57.645 ;
     RECT  2.16 57.915 49.68 58.185 ;
     RECT  2.16 58.455 49.68 58.725 ;
     RECT  2.16 58.995 49.68 59.265 ;
     RECT  2.16 59.535 49.68 59.805 ;
     RECT  2.16 60.075 49.68 60.345 ;
     RECT  2.16 60.615 49.68 60.885 ;
     RECT  2.16 61.155 49.68 61.425 ;
     RECT  2.16 61.695 49.68 61.83 ;
     RECT  2.16 61.83 16.308 61.965 ;
     RECT  16.632 61.83 49.68 61.965 ;
     RECT  2.16 62.235 49.68 62.505 ;
     RECT  2.16 62.775 49.68 63.045 ;
     RECT  2.16 63.315 49.68 63.585 ;
     RECT  2.16 63.855 49.68 64.125 ;
     RECT  2.16 64.395 49.68 64.665 ;
     RECT  2.16 64.935 49.68 65.205 ;
     RECT  2.16 65.475 49.68 65.745 ;
     RECT  2.16 66.015 49.68 66.285 ;
     RECT  2.16 66.555 49.68 66.825 ;
     RECT  2.16 67.095 49.68 67.365 ;
     RECT  2.16 67.635 49.68 67.905 ;
     RECT  2.16 68.175 49.68 68.445 ;
     RECT  2.16 68.715 49.68 68.985 ;
     RECT  2.16 69.255 49.68 69.525 ;
     RECT  2.16 69.795 49.68 70.065 ;
     RECT  2.16 70.335 49.68 70.605 ;
     RECT  2.16 70.875 49.68 71.145 ;
     RECT  2.16 71.415 49.68 71.685 ;
     RECT  2.16 71.955 49.68 72.225 ;
     RECT  2.16 72.495 49.68 72.765 ;
     RECT  2.16 73.035 49.68 73.305 ;
     RECT  2.16 73.575 13.716 73.71 ;
     RECT  14.04 73.575 49.68 73.71 ;
     RECT  2.16 73.71 49.68 73.845 ;
     RECT  2.16 74.115 49.68 74.25 ;
     RECT  2.16 74.25 11.124 74.385 ;
     RECT  11.448 74.25 11.772 74.385 ;
     RECT  12.096 74.25 49.68 74.385 ;
     RECT  2.16 74.655 49.68 74.925 ;
     RECT  2.16 75.195 49.68 75.33 ;
     RECT  2.16 75.33 12.366 75.465 ;
     RECT  13.014 75.33 49.68 75.465 ;
     RECT  2.16 75.735 18.036 75.87 ;
     RECT  18.684 75.735 49.68 75.87 ;
     RECT  2.16 75.87 49.68 76.005 ;
     RECT  2.16 76.275 49.68 76.545 ;
     RECT  2.16 76.815 49.68 77.085 ;
     RECT  2.16 77.355 14.04 77.49 ;
     RECT  14.364 77.355 14.742 77.49 ;
     RECT  15.066 77.355 49.68 77.49 ;
     RECT  2.16 77.49 11.07 77.625 ;
     RECT  11.718 77.49 49.68 77.625 ;
     RECT  2.16 77.895 49.68 78.03 ;
     RECT  2.16 78.03 16.524 78.165 ;
     RECT  17.172 78.03 49.68 78.165 ;
     RECT  2.16 78.435 18.09 78.57 ;
     RECT  18.414 78.435 49.68 78.57 ;
     RECT  2.16 78.57 18.036 78.705 ;
     RECT  18.36 78.57 49.68 78.705 ;
     RECT  2.16 78.975 49.68 79.245 ;
     RECT  2.16 79.515 49.68 79.785 ;
    LAYER M1 ;
     RECT  2.16 2.151 49.68 79.929 ;
    LAYER M2 ;
     RECT  0.031 6.012 0.067 6.03 ;
     RECT  0.031 9.171 0.067 9.189 ;
     RECT  0.031 10.251 0.067 10.269 ;
     RECT  0.031 12.996 0.067 13.014 ;
     RECT  0.031 22.554 0.103 22.572 ;
     RECT  0.067 23.526 0.103 23.544 ;
     RECT  0.067 26.91 0.103 26.928 ;
     RECT  0.067 70.38 0.103 70.398 ;
     RECT  0.031 25.101 0.131 25.119 ;
     RECT  0.103 76.86 0.139 76.878 ;
     RECT  0.139 37.332 0.175 37.35 ;
     RECT  0.031 58.734 0.175 58.752 ;
     RECT  0.103 60.588 0.175 60.606 ;
     RECT  0.031 4.662 0.211 5.184 ;
     RECT  0.067 6.012 0.211 6.444 ;
     RECT  0.067 9.09 0.211 9.189 ;
     RECT  0.067 10.206 0.211 10.269 ;
     RECT  0.103 34.74 0.211 34.758 ;
     RECT  0.103 49.176 0.211 49.194 ;
     RECT  0.103 57.348 0.211 57.438 ;
     RECT  0.103 29.376 0.239 30.096 ;
     RECT  0.103 70.002 0.239 70.398 ;
     RECT  0.103 22.554 0.247 23.544 ;
     RECT  0.031 41.49 0.247 41.508 ;
     RECT  0.067 61.902 0.247 61.92 ;
     RECT  0.139 76.86 0.247 77.076 ;
     RECT  0.103 79.326 0.247 79.344 ;
     RECT  0.211 9.09 0.283 10.269 ;
     RECT  0.247 40.95 0.283 41.508 ;
     RECT  0.139 42.57 0.283 42.588 ;
     RECT  0.175 58.5 0.283 58.752 ;
     RECT  0.139 66.366 0.283 66.384 ;
     RECT  0.211 20.628 0.311 20.646 ;
     RECT  0.211 24.948 0.311 25.074 ;
     RECT  0.103 80.91 0.311 80.928 ;
     RECT  0.283 9.09 0.319 10.422 ;
     RECT  0.247 11.376 0.319 11.394 ;
     RECT  0.283 58.5 0.319 59.364 ;
     RECT  0.247 76.788 0.347 77.076 ;
     RECT  0.067 3.726 0.355 3.744 ;
     RECT  0.211 4.662 0.355 6.444 ;
     RECT  0.247 53.136 0.355 53.154 ;
     RECT  0.247 54.801 0.355 55.008 ;
     RECT  0.067 12.996 0.383 13.086 ;
     RECT  0.319 9.09 0.391 11.394 ;
     RECT  0.247 61.902 0.391 62.604 ;
     RECT  0.383 13.068 0.419 13.086 ;
     RECT  0.103 26.91 0.419 27.504 ;
     RECT  0.211 56.88 0.427 57.438 ;
     RECT  0.319 58.5 0.427 59.562 ;
     RECT  0.391 61.902 0.427 62.874 ;
     RECT  0.247 71.964 0.427 71.982 ;
     RECT  0.247 78.48 0.427 79.344 ;
     RECT  0.391 9.09 0.463 11.664 ;
     RECT  0.283 40.95 0.463 42.588 ;
     RECT  0.427 44.226 0.463 44.244 ;
     RECT  0.067 45.504 0.463 45.522 ;
     RECT  0.355 53.136 0.463 53.514 ;
     RECT  0.427 56.538 0.463 59.562 ;
     RECT  0.175 60.588 0.463 60.678 ;
     RECT  0.239 70.074 0.463 70.398 ;
     RECT  0.427 71.964 0.463 72.054 ;
     RECT  0.067 73.116 0.463 73.134 ;
     RECT  0.427 74.088 0.463 74.106 ;
     RECT  0.175 37.332 0.499 37.926 ;
     RECT  0.247 50.868 0.499 50.886 ;
     RECT  0.463 53.136 0.499 53.928 ;
     RECT  0.355 54.801 0.499 55.44 ;
     RECT  0.463 56.538 0.499 60.678 ;
     RECT  0.463 64.296 0.499 64.314 ;
     RECT  0.283 65.682 0.499 66.384 ;
     RECT  0.463 67.302 0.499 67.32 ;
     RECT  0.463 70.074 0.499 70.524 ;
     RECT  0.463 71.766 0.499 72.054 ;
     RECT  0.355 3.726 0.527 6.444 ;
     RECT  0.499 56.538 0.527 60.984 ;
     RECT  0.499 26.406 0.535 26.424 ;
     RECT  0.419 27.486 0.535 27.504 ;
     RECT  0.499 37.332 0.535 37.998 ;
     RECT  0.499 39.06 0.535 39.078 ;
     RECT  0.463 40.95 0.535 42.822 ;
     RECT  0.499 46.314 0.535 46.332 ;
     RECT  0.067 52.326 0.535 52.344 ;
     RECT  0.499 53.136 0.535 55.44 ;
     RECT  0.499 65.682 0.535 67.32 ;
     RECT  0.499 68.148 0.535 68.166 ;
     RECT  0.103 68.958 0.535 68.976 ;
     RECT  0.499 70.074 0.535 72.324 ;
     RECT  0.463 73.116 0.535 74.754 ;
     RECT  0.211 75.978 0.535 75.996 ;
     RECT  0.427 78.408 0.535 79.344 ;
     RECT  0.527 5.886 0.563 6.444 ;
     RECT  0.463 44.226 0.571 45.522 ;
     RECT  0.463 9.09 0.643 12.114 ;
     RECT  0.527 56.61 0.671 60.984 ;
     RECT  0.211 34.47 0.823 34.758 ;
     RECT  0.571 43.812 0.823 45.522 ;
     RECT  0.535 14.49 0.859 14.508 ;
     RECT  0.535 15.3 0.859 15.318 ;
     RECT  0.535 37.332 0.895 38.16 ;
     RECT  0.643 9.054 1.147 12.114 ;
     RECT  0.311 25.056 1.147 25.074 ;
     RECT  0.535 40.95 1.147 42.894 ;
     RECT  0.823 43.812 1.147 45.558 ;
     RECT  1.147 24.948 1.175 25.074 ;
     RECT  0.535 21.006 1.399 21.024 ;
     RECT  0.103 33.426 1.399 33.444 ;
     RECT  0.535 16.686 1.435 16.704 ;
     RECT  0.211 49.176 1.435 49.572 ;
     RECT  1.147 8.82 1.471 12.114 ;
     RECT  0.563 6.426 1.507 6.444 ;
     RECT  0.535 52.326 1.543 55.44 ;
     RECT  1.435 49.176 1.579 49.77 ;
     RECT  0.671 56.61 1.579 57.744 ;
     RECT  0.671 58.5 1.579 60.984 ;
     RECT  0.247 22.086 1.975 23.544 ;
     RECT  0.535 46.314 1.975 46.602 ;
     RECT  1.399 47.43 1.975 47.448 ;
     RECT  0.103 2.106 2.16 2.124 ;
     RECT  0.527 3.726 2.16 5.022 ;
     RECT  1.507 6.12 2.16 6.444 ;
     RECT  2.011 7.2 2.16 7.218 ;
     RECT  1.471 8.82 2.16 12.51 ;
     RECT  0.499 13.41 2.16 13.734 ;
     RECT  0.859 14.49 2.16 15.318 ;
     RECT  1.435 16.686 2.16 17.1 ;
     RECT  0.535 18.54 2.16 18.558 ;
     RECT  1.399 20.862 2.16 21.024 ;
     RECT  1.975 21.942 2.16 23.544 ;
     RECT  1.175 24.948 2.16 24.966 ;
     RECT  0.535 25.992 2.16 26.424 ;
     RECT  0.535 27.486 2.16 27.666 ;
     RECT  0.239 30.006 2.16 30.024 ;
     RECT  0.067 31.23 2.16 31.248 ;
     RECT  1.975 32.04 2.16 32.058 ;
     RECT  1.399 33.012 2.16 33.444 ;
     RECT  0.823 34.47 2.16 35.298 ;
     RECT  1.471 36.09 2.16 36.108 ;
     RECT  0.895 36.9 2.16 38.16 ;
     RECT  0.535 39.06 2.16 39.618 ;
     RECT  1.147 40.95 2.16 45.558 ;
     RECT  1.975 46.314 2.16 47.448 ;
     RECT  1.579 48.978 2.16 49.77 ;
     RECT  0.499 50.868 2.16 51.228 ;
     RECT  1.543 52.02 2.16 55.44 ;
     RECT  1.579 56.61 2.16 60.984 ;
     RECT  0.427 61.902 2.16 63.414 ;
     RECT  0.499 64.296 2.16 64.692 ;
     RECT  0.535 65.52 2.16 68.976 ;
     RECT  0.535 70.074 2.16 74.754 ;
     RECT  0.535 75.978 2.16 76.068 ;
     RECT  0.347 76.86 2.16 77.076 ;
     RECT  0.535 78.408 2.16 79.614 ;
     RECT  2.16 2.106 19.823 79.929 ;
     RECT  20.983 82.026 21.083 82.044 ;
     RECT  19.823 2.151 41.035 79.929 ;
     RECT  41.035 2.106 48.011 79.929 ;
     RECT  48.011 2.151 49.68 79.929 ;
     RECT  49.68 2.196 50.171 28.314 ;
     RECT  49.68 58.356 50.171 60.57 ;
     RECT  49.68 62.856 50.171 79.776 ;
     RECT  50.171 5.166 50.207 28.314 ;
     RECT  50.171 62.856 50.207 73.404 ;
     RECT  50.171 74.394 50.207 79.776 ;
     RECT  50.207 5.166 50.243 28.278 ;
     RECT  50.207 74.466 50.243 76.104 ;
     RECT  50.243 25.146 50.675 28.278 ;
     RECT  50.171 58.464 50.675 60.57 ;
     RECT  50.171 2.196 50.711 4.284 ;
     RECT  50.243 5.166 50.711 24.156 ;
     RECT  50.675 25.146 50.711 25.164 ;
     RECT  50.675 25.992 50.711 28.278 ;
     RECT  49.68 29.502 50.711 57.132 ;
     RECT  50.675 58.464 50.711 59.49 ;
     RECT  50.675 60.246 50.711 60.57 ;
     RECT  50.207 62.946 50.711 73.404 ;
     RECT  50.243 74.466 50.711 75.654 ;
     RECT  50.207 76.896 50.711 79.776 ;
     RECT  50.711 5.31 50.747 9.954 ;
     RECT  50.711 10.944 50.747 10.962 ;
     RECT  50.711 11.826 50.747 12.384 ;
     RECT  50.711 13.176 50.747 13.194 ;
     RECT  50.711 14.346 50.747 14.364 ;
     RECT  50.711 15.876 50.747 18.324 ;
     RECT  50.711 20.736 50.747 21.294 ;
     RECT  50.711 25.992 50.747 27.432 ;
     RECT  50.711 29.502 50.747 33.912 ;
     RECT  50.711 37.944 50.747 37.962 ;
     RECT  50.711 39.564 50.747 39.816 ;
     RECT  50.711 40.716 50.747 40.734 ;
     RECT  50.711 41.994 50.747 44.172 ;
     RECT  50.711 44.928 50.747 44.946 ;
     RECT  50.711 45.774 50.747 46.944 ;
     RECT  50.711 48.006 50.747 48.024 ;
     RECT  50.711 51.174 50.747 54.774 ;
     RECT  50.711 58.464 50.747 58.482 ;
     RECT  50.711 59.238 50.747 59.256 ;
     RECT  50.711 63.594 50.747 64.35 ;
     RECT  50.711 68.184 50.747 69.21 ;
     RECT  50.711 70.344 50.747 70.704 ;
     RECT  50.711 72.126 50.747 73.062 ;
     RECT  50.711 74.628 50.747 75.654 ;
     RECT  50.711 77.022 50.747 79.776 ;
     RECT  50.747 12.096 50.783 12.114 ;
     RECT  50.747 27.414 50.783 27.432 ;
     RECT  50.747 29.736 50.783 30.024 ;
     RECT  50.747 30.996 50.783 31.752 ;
     RECT  50.711 36.864 50.783 36.882 ;
     RECT  50.747 39.798 50.783 39.816 ;
     RECT  50.747 45.774 50.783 46.674 ;
     RECT  50.747 72.936 50.783 72.954 ;
     RECT  50.747 77.292 50.783 78.696 ;
     RECT  50.783 29.736 50.819 29.754 ;
     RECT  50.747 79.686 50.819 79.704 ;
     RECT  50.783 77.526 50.855 78.192 ;
     RECT  50.711 2.646 51.719 4.284 ;
     RECT  50.747 8.316 51.719 9.954 ;
     RECT  50.747 16.074 51.719 16.362 ;
     RECT  50.711 56.844 51.719 57.06 ;
     RECT  50.711 60.516 51.719 60.57 ;
     RECT  50.747 63.594 51.719 63.774 ;
     RECT  50.855 77.526 51.719 78.084 ;
     RECT  51.691 80.568 51.727 80.586 ;
     RECT  51.719 2.646 51.755 2.934 ;
     RECT  51.719 3.69 51.755 4.284 ;
     RECT  50.747 5.31 51.755 7.524 ;
     RECT  51.719 8.316 51.755 9.882 ;
     RECT  51.719 16.074 51.755 16.092 ;
     RECT  50.711 19.08 51.755 19.098 ;
     RECT  50.711 23.13 51.755 23.616 ;
     RECT  50.747 25.992 51.755 26.424 ;
     RECT  50.711 28.26 51.755 28.278 ;
     RECT  50.783 31.734 51.755 31.752 ;
     RECT  50.747 33.894 51.755 33.912 ;
     RECT  50.711 34.704 51.755 34.722 ;
     RECT  50.747 41.994 51.755 43.326 ;
     RECT  50.783 45.774 51.755 46.332 ;
     RECT  50.711 50.364 51.755 50.382 ;
     RECT  50.747 51.48 51.755 52.074 ;
     RECT  50.747 52.956 51.755 53.514 ;
     RECT  50.747 54.486 51.755 54.774 ;
     RECT  51.719 56.844 51.755 56.862 ;
     RECT  51.719 60.516 51.755 60.534 ;
     RECT  51.719 63.594 51.755 63.612 ;
     RECT  50.711 65.106 51.755 65.124 ;
     RECT  50.711 66.294 51.755 67.32 ;
     RECT  50.747 68.184 51.755 68.4 ;
     RECT  50.747 70.344 51.755 70.362 ;
     RECT  50.747 72.126 51.755 72.144 ;
     RECT  50.747 74.628 51.755 75.492 ;
     RECT  51.719 77.526 51.791 77.616 ;
     RECT  51.727 80.568 51.791 81.09 ;
     RECT  51.791 77.526 51.827 77.544 ;
     RECT  51.791 81.072 51.827 81.09 ;
    LAYER M3 ;
     RECT  21.132 0.523 21.15 1.051 ;
     RECT  20.808 1.051 21.15 1.147 ;
     RECT  31.932 0.715 31.95 1.291 ;
     RECT  49.212 0.859 49.23 1.291 ;
     RECT  50.148 0.715 50.166 1.435 ;
     RECT  3.132 1.003 3.15 1.579 ;
     RECT  2.304 1.147 2.322 1.723 ;
     RECT  3.132 1.579 3.87 1.723 ;
     RECT  47.232 1.579 47.25 1.723 ;
     RECT  50.148 1.435 50.202 1.867 ;
     RECT  20.808 1.147 21.186 2.011 ;
     RECT  50.112 1.867 50.202 2.011 ;
     RECT  0.108 0.859 0.126 2.129 ;
     RECT  20.808 2.011 21.258 2.143 ;
     RECT  31.608 1.291 31.95 2.143 ;
     RECT  34.488 1.867 34.506 2.143 ;
     RECT  45.756 1.147 45.774 2.143 ;
     RECT  47.988 2.101 48.006 2.143 ;
     RECT  49.104 1.291 49.23 2.143 ;
     RECT  20.808 2.143 21.405 2.191 ;
     RECT  34.488 2.143 34.905 2.227 ;
     RECT  45.615 2.143 45.774 2.227 ;
     RECT  28.26 2.191 28.278 2.299 ;
     RECT  29.415 2.143 29.505 2.299 ;
     RECT  45.144 2.227 45.774 2.299 ;
     RECT  51.732 1.003 51.75 2.299 ;
     RECT  19.8 2.101 19.818 2.335 ;
     RECT  37.515 2.143 37.605 2.347 ;
     RECT  40.215 2.143 40.305 2.347 ;
     RECT  41.04 2.101 41.058 2.347 ;
     RECT  42.915 2.143 43.005 2.347 ;
     RECT  9.288 2.191 9.306 2.371 ;
     RECT  46.62 1.723 47.25 2.371 ;
     RECT  47.988 2.143 49.23 2.371 ;
     RECT  5.115 2.143 5.205 2.413 ;
     RECT  7.815 2.143 7.905 2.413 ;
     RECT  10.515 2.143 10.605 2.413 ;
     RECT  13.215 2.143 13.305 2.413 ;
     RECT  15.915 2.143 16.005 2.413 ;
     RECT  18.615 2.143 18.705 2.413 ;
     RECT  24.015 2.143 24.105 2.413 ;
     RECT  26.715 2.143 26.805 2.413 ;
     RECT  28.26 2.299 29.505 2.413 ;
     RECT  31.608 2.143 32.205 2.413 ;
     RECT  36.864 2.347 37.605 2.413 ;
     RECT  44.712 2.299 45.774 2.413 ;
     RECT  31.608 2.413 32.397 2.461 ;
     RECT  42.915 2.347 43.542 2.461 ;
     RECT  44.712 2.413 45.897 2.461 ;
     RECT  46.62 2.371 49.23 2.461 ;
     RECT  19.62 2.335 19.818 2.488 ;
     RECT  0.144 2.155 0.162 2.491 ;
     RECT  40.215 2.347 41.058 2.491 ;
     RECT  24.015 2.413 24.297 2.497 ;
     RECT  39.924 2.491 41.058 2.497 ;
     RECT  42.696 2.461 43.542 2.497 ;
     RECT  39.924 2.497 41.166 2.533 ;
     RECT  42.516 2.497 43.542 2.533 ;
     RECT  31.248 2.461 32.397 2.569 ;
     RECT  24.015 2.497 24.354 2.605 ;
     RECT  34.488 2.227 35.334 2.605 ;
     RECT  44.424 2.461 49.23 2.605 ;
     RECT  0.144 2.491 0.234 2.621 ;
     RECT  7.815 2.413 8.097 2.641 ;
     RECT  9.288 2.371 9.486 2.641 ;
     RECT  14.436 2.605 14.454 2.641 ;
     RECT  18.615 2.413 18.897 2.641 ;
     RECT  19.62 2.488 20.07 2.641 ;
     RECT  30.708 2.569 32.397 2.641 ;
     RECT  39.924 2.533 43.542 2.683 ;
     RECT  44.424 2.605 49.266 2.683 ;
     RECT  7.596 2.641 8.097 2.731 ;
     RECT  13.215 2.413 13.497 2.731 ;
     RECT  26.715 2.413 26.997 2.731 ;
     RECT  39.924 2.683 49.266 2.731 ;
     RECT  39.24 2.731 49.266 2.759 ;
     RECT  6.912 2.731 8.097 2.767 ;
     RECT  28.26 2.413 29.697 2.767 ;
     RECT  30.708 2.641 32.85 2.767 ;
     RECT  36.864 2.413 37.797 2.767 ;
     RECT  20.808 2.191 21.798 2.779 ;
     RECT  9.144 2.641 9.486 2.803 ;
     RECT  12.528 2.731 13.497 2.803 ;
     RECT  22.896 2.539 22.914 2.803 ;
     RECT  23.832 2.605 24.354 2.803 ;
     RECT  26.28 2.731 26.997 2.803 ;
     RECT  28.08 2.767 29.697 2.803 ;
     RECT  30.708 2.767 33.21 2.803 ;
     RECT  39.24 2.759 49.23 2.803 ;
     RECT  39.06 2.803 49.23 2.831 ;
     RECT  5.115 2.413 5.397 2.839 ;
     RECT  15.915 2.413 16.197 2.839 ;
     RECT  18.288 2.641 20.07 2.839 ;
     RECT  26.1 2.803 29.697 2.839 ;
     RECT  30.708 2.803 33.426 2.839 ;
     RECT  34.236 2.605 35.334 2.839 ;
     RECT  9.144 2.803 9.63 2.858 ;
     RECT  18.108 2.839 20.07 2.869 ;
     RECT  50.112 2.011 50.706 2.869 ;
     RECT  6.768 2.767 8.154 2.875 ;
     RECT  9.144 2.858 9.666 2.875 ;
     RECT  11.592 2.461 11.61 2.875 ;
     RECT  12.42 2.803 13.497 2.875 ;
     RECT  14.364 2.641 14.454 2.875 ;
     RECT  20.808 2.779 21.834 2.875 ;
     RECT  25.092 2.347 25.11 2.875 ;
     RECT  26.1 2.839 33.426 2.875 ;
     RECT  34.164 2.839 35.334 2.875 ;
     RECT  36.648 2.767 37.797 2.875 ;
     RECT  39.06 2.831 43.938 2.875 ;
     RECT  50.112 2.869 50.742 2.909 ;
     RECT  5.115 2.839 5.778 2.911 ;
     RECT  6.768 2.875 9.666 2.911 ;
     RECT  18.072 2.869 20.07 2.911 ;
     RECT  20.808 2.875 21.942 2.911 ;
     RECT  25.092 2.875 33.426 2.911 ;
     RECT  34.164 2.875 37.797 2.911 ;
     RECT  38.7 2.875 43.938 2.911 ;
     RECT  6.588 2.911 9.666 2.971 ;
     RECT  15.804 2.839 16.197 2.971 ;
     RECT  4.752 2.911 5.778 3.001 ;
     RECT  6.516 2.971 9.666 3.001 ;
     RECT  15.66 2.971 16.197 3.001 ;
     RECT  17.1 2.347 17.118 3.001 ;
     RECT  18.072 2.911 21.942 3.001 ;
     RECT  22.896 2.803 24.354 3.001 ;
     RECT  25.092 2.911 43.938 3.001 ;
     RECT  44.748 2.831 49.23 3.029 ;
     RECT  22.896 3.001 43.938 3.067 ;
     RECT  2.304 1.723 3.87 3.145 ;
     RECT  4.752 3.001 9.738 3.145 ;
     RECT  11.592 2.875 14.67 3.181 ;
     RECT  15.66 3.001 21.942 3.181 ;
     RECT  44.856 3.029 49.194 3.209 ;
     RECT  44.856 3.209 49.158 3.299 ;
     RECT  11.592 3.181 14.778 3.304 ;
     RECT  15.66 3.181 22.05 3.304 ;
     RECT  11.592 3.304 22.05 3.307 ;
     RECT  22.824 3.067 43.938 3.307 ;
     RECT  10.515 2.413 10.797 3.343 ;
     RECT  2.304 3.145 9.738 3.355 ;
     RECT  10.476 3.343 10.797 3.355 ;
     RECT  2.304 3.355 10.797 3.451 ;
     RECT  11.592 3.307 43.938 3.451 ;
     RECT  51.696 2.299 51.75 3.677 ;
     RECT  0.144 2.621 0.162 3.721 ;
     RECT  0.072 3.721 0.162 3.739 ;
     RECT  2.304 3.451 43.938 3.875 ;
     RECT  2.415 3.875 43.938 4.081 ;
     RECT  44.856 3.299 49.122 4.081 ;
     RECT  2.415 4.081 49.122 4.109 ;
     RECT  44.64 4.109 48.597 4.289 ;
     RECT  49.32 4.225 49.338 4.379 ;
     RECT  0.072 3.739 0.234 4.423 ;
     RECT  0.072 4.423 0.378 4.459 ;
     RECT  2.415 4.109 43.794 4.493 ;
     RECT  18.468 4.493 43.794 4.523 ;
     RECT  50.112 2.909 50.706 4.559 ;
     RECT  2.415 4.493 17.658 4.603 ;
     RECT  0.072 4.459 0.486 4.657 ;
     RECT  18.468 4.523 43.326 4.721 ;
     RECT  44.712 4.289 48.597 4.793 ;
     RECT  0.036 4.657 0.486 4.795 ;
     RECT  50.148 4.559 50.706 4.928 ;
     RECT  18.54 4.721 43.326 4.991 ;
     RECT  51.732 3.677 51.75 5.035 ;
     RECT  51.696 5.035 51.75 5.179 ;
     RECT  0.036 4.795 0.522 5.189 ;
     RECT  41.688 4.991 43.326 5.275 ;
     RECT  2.34 4.603 17.658 5.323 ;
     RECT  2.304 5.323 17.658 5.369 ;
     RECT  2.34 5.369 17.658 5.461 ;
     RECT  18.54 4.991 40.878 5.461 ;
     RECT  50.184 4.928 50.706 5.567 ;
     RECT  44.712 4.793 44.874 5.575 ;
     RECT  45.615 4.793 48.597 5.575 ;
     RECT  50.688 5.567 50.706 5.611 ;
     RECT  49.32 5.575 49.338 5.729 ;
     RECT  0.072 5.189 0.522 5.755 ;
     RECT  1.476 2.299 1.494 5.755 ;
     RECT  44.712 5.575 48.597 5.773 ;
     RECT  50.688 5.611 50.742 5.789 ;
     RECT  51.66 5.179 51.75 5.837 ;
     RECT  41.688 5.275 43.794 5.851 ;
     RECT  44.712 5.773 49.122 5.851 ;
     RECT  2.34 5.461 40.878 5.881 ;
     RECT  41.688 5.851 49.122 5.881 ;
     RECT  0.072 5.755 1.494 6.007 ;
     RECT  49.86 5.899 49.878 6.107 ;
     RECT  0.036 6.007 1.494 6.115 ;
     RECT  2.34 5.881 49.122 6.305 ;
     RECT  2.34 6.305 48.942 6.539 ;
     RECT  2.34 6.539 38.862 6.763 ;
     RECT  49.752 6.691 49.77 6.797 ;
     RECT  2.304 6.763 38.862 6.809 ;
     RECT  39.6 6.539 48.942 6.809 ;
     RECT  2.304 6.809 28.134 6.881 ;
     RECT  0.036 6.115 1.53 6.907 ;
     RECT  2.304 6.881 28.098 6.907 ;
     RECT  39.636 6.809 48.942 6.989 ;
     RECT  50.688 5.789 50.706 7.195 ;
     RECT  50.184 7.195 50.706 7.373 ;
     RECT  0.036 6.907 28.098 7.627 ;
     RECT  28.98 6.809 38.862 7.627 ;
     RECT  0.036 7.627 38.862 7.735 ;
     RECT  39.636 6.989 48.597 7.735 ;
     RECT  50.688 7.373 50.706 7.771 ;
     RECT  50.688 7.771 50.742 7.949 ;
     RECT  50.688 7.949 50.706 8.203 ;
     RECT  50.148 8.203 50.706 8.24 ;
     RECT  0.036 7.735 48.597 8.437 ;
     RECT  0.036 8.437 48.978 8.545 ;
     RECT  0.036 8.545 49.626 8.669 ;
     RECT  50.688 8.24 50.706 9.067 ;
     RECT  0.036 8.669 49.302 9.194 ;
     RECT  0.108 9.194 49.302 9.383 ;
     RECT  0.108 9.383 48.87 9.779 ;
     RECT  51.732 5.837 51.75 9.787 ;
     RECT  51.696 9.787 51.75 9.887 ;
     RECT  51.696 9.887 51.714 9.959 ;
     RECT  50.148 9.067 50.706 10.075 ;
     RECT  0.108 9.779 40.59 10.201 ;
     RECT  41.328 9.779 48.87 10.229 ;
     RECT  49.824 10.075 50.706 10.229 ;
     RECT  0.072 10.201 40.59 10.246 ;
     RECT  0.036 10.246 40.59 10.597 ;
     RECT  41.328 10.229 48.597 10.597 ;
     RECT  0.036 10.597 48.597 10.697 ;
     RECT  50.148 10.229 50.706 10.933 ;
     RECT  50.148 10.933 50.742 10.973 ;
     RECT  50.148 10.973 50.706 11.039 ;
     RECT  44.856 10.697 48.597 11.281 ;
     RECT  49.32 10.975 49.338 11.281 ;
     RECT  44.856 11.281 49.338 11.515 ;
     RECT  44.856 11.515 49.626 11.669 ;
     RECT  44.892 11.669 49.626 11.777 ;
     RECT  50.688 11.039 50.706 11.803 ;
     RECT  50.148 11.803 50.706 11.821 ;
     RECT  50.148 11.821 50.742 11.939 ;
     RECT  44.892 11.777 48.834 11.975 ;
     RECT  50.184 11.939 50.742 11.981 ;
     RECT  50.688 11.981 50.742 12.091 ;
     RECT  0.036 10.697 43.902 12.209 ;
     RECT  44.892 11.975 48.597 12.317 ;
     RECT  44.892 12.317 46.386 12.451 ;
     RECT  44.82 12.451 46.386 12.509 ;
     RECT  0.036 12.209 43.758 12.551 ;
     RECT  47.34 12.317 48.597 12.557 ;
     RECT  50.688 12.091 50.778 12.701 ;
     RECT  44.892 12.509 46.386 12.749 ;
     RECT  50.688 12.701 50.742 12.811 ;
     RECT  50.184 12.811 50.742 12.955 ;
     RECT  0.036 12.551 43.578 13.019 ;
     RECT  50.148 12.955 50.742 13.019 ;
     RECT  0.072 13.019 43.578 13.091 ;
     RECT  0.18 13.091 43.578 13.102 ;
     RECT  47.34 12.557 47.466 13.135 ;
     RECT  48.315 12.557 48.597 13.135 ;
     RECT  49.788 13.099 49.806 13.135 ;
     RECT  50.688 13.019 50.742 13.277 ;
     RECT  0.216 13.102 43.578 13.369 ;
     RECT  48.315 13.135 49.806 13.559 ;
     RECT  44.892 12.749 45.897 13.675 ;
     RECT  46.656 13.135 47.466 13.675 ;
     RECT  44.892 13.675 47.466 13.711 ;
     RECT  48.315 13.559 48.597 13.711 ;
     RECT  49.572 13.559 49.806 13.739 ;
     RECT  44.892 13.711 48.597 13.829 ;
     RECT  49.644 13.739 49.806 13.853 ;
     RECT  46.764 13.829 48.597 14.009 ;
     RECT  49.68 13.853 49.806 14.107 ;
     RECT  50.688 13.277 50.706 14.107 ;
     RECT  0.216 13.369 43.866 14.141 ;
     RECT  49.68 14.107 50.706 14.341 ;
     RECT  49.68 14.341 50.742 14.429 ;
     RECT  48.315 14.009 48.597 14.521 ;
     RECT  48.315 14.521 48.762 14.647 ;
     RECT  0.252 14.141 43.866 14.731 ;
     RECT  49.68 14.429 50.706 14.747 ;
     RECT  48.315 14.647 48.87 14.791 ;
     RECT  48.276 14.791 48.87 14.819 ;
     RECT  0.252 14.731 44.01 14.881 ;
     RECT  44.892 13.829 45.897 14.881 ;
     RECT  46.764 14.009 47.502 14.881 ;
     RECT  0.252 14.881 47.502 14.989 ;
     RECT  0.252 14.989 47.538 15.019 ;
     RECT  0.144 15.019 47.538 15.053 ;
     RECT  49.752 14.747 50.706 15.053 ;
     RECT  0.144 15.053 46.53 15.179 ;
     RECT  47.304 15.053 47.538 15.187 ;
     RECT  48.276 14.819 48.597 15.187 ;
     RECT  0.144 15.179 46.458 15.215 ;
     RECT  47.304 15.187 48.597 15.215 ;
     RECT  0.144 15.215 44.838 15.251 ;
     RECT  0.144 15.251 44.514 15.449 ;
     RECT  49.752 15.053 49.806 15.557 ;
     RECT  49.788 15.557 49.806 15.827 ;
     RECT  50.688 15.053 50.706 15.871 ;
     RECT  45.615 15.215 46.386 15.961 ;
     RECT  47.52 15.215 48.597 15.961 ;
     RECT  50.688 15.871 50.742 16.013 ;
     RECT  51.732 15.547 51.75 16.097 ;
     RECT  0.144 15.449 43.938 16.109 ;
     RECT  45.615 15.961 48.597 16.231 ;
     RECT  0.144 16.109 39.294 16.301 ;
     RECT  40.068 16.109 43.938 16.339 ;
     RECT  51.696 16.123 51.714 16.367 ;
     RECT  45.576 16.231 48.597 16.375 ;
     RECT  0.144 16.301 27.522 16.403 ;
     RECT  49.608 16.405 49.626 16.445 ;
     RECT  0.144 16.403 27.234 16.529 ;
     RECT  45.576 16.375 48.69 16.529 ;
     RECT  40.068 16.339 44.01 16.555 ;
     RECT  50.688 16.013 50.706 16.699 ;
     RECT  45.576 16.529 48.597 16.843 ;
     RECT  45.288 16.843 48.597 17.041 ;
     RECT  50.148 16.699 50.706 17.041 ;
     RECT  28.296 16.301 39.294 17.077 ;
     RECT  40.068 16.555 44.118 17.077 ;
     RECT  28.296 17.077 44.118 17.113 ;
     RECT  44.928 17.041 48.597 17.117 ;
     RECT  28.08 17.113 44.118 17.221 ;
     RECT  44.928 17.117 47.538 17.339 ;
     RECT  48.315 17.117 48.597 17.383 ;
     RECT  50.148 17.041 50.742 17.383 ;
     RECT  0.144 16.529 27.162 17.419 ;
     RECT  27.936 17.221 44.118 17.419 ;
     RECT  49.752 17.383 50.742 17.447 ;
     RECT  0.144 17.419 44.118 17.491 ;
     RECT  44.928 17.339 46.422 17.491 ;
     RECT  48.315 17.383 48.798 17.491 ;
     RECT  49.752 17.447 49.806 17.491 ;
     RECT  48.315 17.491 49.806 17.753 ;
     RECT  47.16 17.339 47.538 17.879 ;
     RECT  48.315 17.753 48.597 17.887 ;
     RECT  0.144 17.491 46.422 17.981 ;
     RECT  0.54 17.981 46.422 18.121 ;
     RECT  47.16 17.879 47.322 18.121 ;
     RECT  0.54 18.121 47.322 18.221 ;
     RECT  48.132 17.887 48.597 18.455 ;
     RECT  50.688 17.447 50.742 18.461 ;
     RECT  48.315 18.455 48.597 18.571 ;
     RECT  49.428 17.753 49.806 18.571 ;
     RECT  44.784 18.221 46.53 18.689 ;
     RECT  48.315 18.571 49.806 18.859 ;
     RECT  50.688 18.461 50.706 18.859 ;
     RECT  48.315 18.859 50.706 18.959 ;
     RECT  45.396 18.689 46.53 19.003 ;
     RECT  47.304 18.221 47.322 19.003 ;
     RECT  51.732 19.003 51.75 19.103 ;
     RECT  48.315 18.959 49.626 19.337 ;
     RECT  45.396 19.003 47.322 19.345 ;
     RECT  0.54 18.221 43.902 19.381 ;
     RECT  48.315 19.337 48.597 19.381 ;
     RECT  0.54 19.381 44.586 19.435 ;
     RECT  45.396 19.345 47.358 19.471 ;
     RECT  48.096 19.381 48.597 19.471 ;
     RECT  49.572 19.337 49.626 19.499 ;
     RECT  0.144 19.435 44.586 19.507 ;
     RECT  45.396 19.471 48.597 19.507 ;
     RECT  0.144 19.507 48.597 19.571 ;
     RECT  0.144 19.571 47.358 19.853 ;
     RECT  49.608 19.499 49.626 19.867 ;
     RECT  0.144 19.853 19.026 19.913 ;
     RECT  19.8 19.853 47.358 19.913 ;
     RECT  49.608 19.867 49.662 20.011 ;
     RECT  50.688 18.959 50.706 20.011 ;
     RECT  44.568 19.913 47.358 20.039 ;
     RECT  17.712 19.913 19.026 20.587 ;
     RECT  19.8 19.913 43.758 20.587 ;
     RECT  48.315 19.571 48.597 20.587 ;
     RECT  49.608 20.011 50.706 20.687 ;
     RECT  50.112 20.687 50.706 20.725 ;
     RECT  48.315 20.587 48.69 20.759 ;
     RECT  0.144 19.913 16.974 20.827 ;
     RECT  17.712 20.587 43.758 20.827 ;
     RECT  44.568 20.039 47.178 20.857 ;
     RECT  0.144 20.827 43.758 20.885 ;
     RECT  44.568 20.857 47.466 20.965 ;
     RECT  1.98 20.885 43.758 21.091 ;
     RECT  44.568 20.965 47.574 21.091 ;
     RECT  1.98 21.091 47.574 21.235 ;
     RECT  48.315 20.759 48.597 21.235 ;
     RECT  50.112 20.725 50.742 21.341 ;
     RECT  1.98 21.235 48.597 21.541 ;
     RECT  1.98 21.541 49.05 21.739 ;
     RECT  50.112 21.341 50.706 21.739 ;
     RECT  1.98 21.739 50.706 21.929 ;
     RECT  1.98 21.929 49.266 21.965 ;
     RECT  2.304 21.965 49.266 22.001 ;
     RECT  47.412 22.001 49.266 22.199 ;
     RECT  47.412 22.199 48.906 22.469 ;
     RECT  0.144 20.885 0.846 22.549 ;
     RECT  2.304 22.001 46.674 22.649 ;
     RECT  2.415 22.649 46.674 22.685 ;
     RECT  0.036 22.549 0.846 22.775 ;
     RECT  4.752 22.685 46.674 22.811 ;
     RECT  46.62 22.811 46.674 22.981 ;
     RECT  47.412 22.469 48.87 22.981 ;
     RECT  50.148 21.929 50.706 23.161 ;
     RECT  0.036 22.775 0.306 23.189 ;
     RECT  46.62 22.981 48.87 23.557 ;
     RECT  2.415 22.685 3.978 23.593 ;
     RECT  4.752 22.811 45.897 23.593 ;
     RECT  51.732 23.035 51.75 23.621 ;
     RECT  46.62 23.557 48.978 23.701 ;
     RECT  49.716 23.161 50.706 23.701 ;
     RECT  2.415 23.593 45.897 24.241 ;
     RECT  46.62 23.701 50.706 24.241 ;
     RECT  2.415 24.241 50.706 24.269 ;
     RECT  2.415 24.269 48.597 24.359 ;
     RECT  46.62 24.359 48.597 24.431 ;
     RECT  0.036 23.189 0.27 24.94 ;
     RECT  0.036 24.94 0.306 25.051 ;
     RECT  1.152 24.943 1.17 25.051 ;
     RECT  0.036 25.051 1.17 25.079 ;
     RECT  0.036 25.079 0.558 25.124 ;
     RECT  48.315 24.431 48.597 25.141 ;
     RECT  49.788 24.269 50.706 25.169 ;
     RECT  0.072 25.124 0.558 25.229 ;
     RECT  2.415 24.359 45.897 25.285 ;
     RECT  48.315 25.141 48.942 25.285 ;
     RECT  49.788 25.169 50.67 25.285 ;
     RECT  48.315 25.285 50.67 25.349 ;
     RECT  2.304 25.285 45.897 25.373 ;
     RECT  2.415 25.373 45.897 25.709 ;
     RECT  49.32 25.349 50.67 25.745 ;
     RECT  49.608 25.745 50.67 25.979 ;
     RECT  0.072 25.229 0.27 25.987 ;
     RECT  48.315 25.349 48.597 26.257 ;
     RECT  45.036 25.709 45.897 26.329 ;
     RECT  46.62 24.431 47.466 26.329 ;
     RECT  45.036 26.329 47.466 26.347 ;
     RECT  48.315 26.257 48.87 26.347 ;
     RECT  45.036 26.347 48.87 26.357 ;
     RECT  51.732 25.915 51.75 26.429 ;
     RECT  45.036 26.357 48.762 26.519 ;
     RECT  0.072 25.987 0.558 26.525 ;
     RECT  46.62 26.519 48.762 26.555 ;
     RECT  2.415 25.709 44.046 26.789 ;
     RECT  3.744 26.789 44.046 26.797 ;
     RECT  45.036 26.519 45.897 26.797 ;
     RECT  0.072 26.525 0.522 26.813 ;
     RECT  3.744 26.797 45.897 26.825 ;
     RECT  0.072 26.813 0.486 26.933 ;
     RECT  2.415 26.789 2.862 26.957 ;
     RECT  49.608 25.979 49.878 27.067 ;
     RECT  50.688 26.059 50.706 27.067 ;
     RECT  11.628 26.825 45.897 27.131 ;
     RECT  48.315 26.555 48.762 27.139 ;
     RECT  49.608 27.067 50.706 27.139 ;
     RECT  12.78 27.131 44.874 27.149 ;
     RECT  3.744 26.825 8.802 27.167 ;
     RECT  11.628 27.131 11.934 27.239 ;
     RECT  12.78 27.149 44.73 27.239 ;
     RECT  6.192 27.167 8.802 27.329 ;
     RECT  46.62 26.555 47.466 27.329 ;
     RECT  48.315 27.139 50.742 27.329 ;
     RECT  47.016 27.329 47.466 27.409 ;
     RECT  48.315 27.329 48.597 27.409 ;
     RECT  49.572 27.329 50.742 27.409 ;
     RECT  45.615 27.131 45.897 27.481 ;
     RECT  0.108 26.933 0.486 27.533 ;
     RECT  6.948 27.329 8.802 27.571 ;
     RECT  9.828 26.825 10.854 27.571 ;
     RECT  11.628 27.239 11.898 27.571 ;
     RECT  12.78 27.239 44.586 27.599 ;
     RECT  45.615 27.481 46.242 27.599 ;
     RECT  49.572 27.409 50.778 27.599 ;
     RECT  50.148 27.599 50.778 27.677 ;
     RECT  2.415 26.957 2.697 27.739 ;
     RECT  2.415 27.739 2.79 27.779 ;
     RECT  50.148 27.677 50.706 27.869 ;
     RECT  12.78 27.599 44.442 27.917 ;
     RECT  3.744 27.167 5.397 27.949 ;
     RECT  3.564 27.949 5.397 28.075 ;
     RECT  6.192 27.329 6.21 28.075 ;
     RECT  0.54 27.643 0.558 28.109 ;
     RECT  50.148 27.869 50.202 28.139 ;
     RECT  47.016 27.409 48.597 28.255 ;
     RECT  51.732 28.219 51.75 28.283 ;
     RECT  12.78 27.917 44.334 28.319 ;
     RECT  50.184 28.139 50.202 28.319 ;
     RECT  3.564 28.075 6.21 28.408 ;
     RECT  6.948 27.571 11.898 28.408 ;
     RECT  46.728 28.255 48.597 28.409 ;
     RECT  46.8 28.409 47.286 28.493 ;
     RECT  47.268 28.493 47.286 28.589 ;
     RECT  2.415 27.779 2.697 28.651 ;
     RECT  3.564 28.408 11.898 28.747 ;
     RECT  12.78 28.319 44.118 28.747 ;
     RECT  3.564 28.747 44.118 28.795 ;
     RECT  2.304 28.651 2.697 29.129 ;
     RECT  0.144 28.267 0.162 29.323 ;
     RECT  0.144 29.323 0.234 29.371 ;
     RECT  46.836 29.371 46.854 29.467 ;
     RECT  46.692 29.467 46.854 29.489 ;
     RECT  45.615 27.599 45.897 29.497 ;
     RECT  46.692 29.489 46.818 29.497 ;
     RECT  3.42 28.795 44.118 29.549 ;
     RECT  14.904 29.549 44.118 29.563 ;
     RECT  3.42 29.549 14.13 29.597 ;
     RECT  45.612 29.497 45.897 29.605 ;
     RECT  46.656 29.497 46.818 29.605 ;
     RECT  50.724 29.497 50.742 29.731 ;
     RECT  48.315 28.409 48.597 29.767 ;
     RECT  2.415 29.129 2.697 29.803 ;
     RECT  3.42 29.597 14.058 29.803 ;
     RECT  50.724 29.731 50.814 29.837 ;
     RECT  47.736 29.767 48.597 29.867 ;
     RECT  0.108 29.371 0.234 29.947 ;
     RECT  0.108 29.947 0.342 30.001 ;
     RECT  0.108 30.001 0.558 30.125 ;
     RECT  48.315 29.867 48.597 30.145 ;
     RECT  45.612 29.605 46.818 30.181 ;
     RECT  49.788 29.515 49.806 30.209 ;
     RECT  48.315 30.145 49.014 30.299 ;
     RECT  50.724 29.837 50.778 30.379 ;
     RECT  14.904 29.563 44.442 30.451 ;
     RECT  45.468 30.181 46.818 30.451 ;
     RECT  14.904 30.451 47.286 30.569 ;
     RECT  50.688 30.379 50.778 30.667 ;
     RECT  48.315 30.299 48.597 30.721 ;
     RECT  2.415 29.803 14.058 30.847 ;
     RECT  50.148 30.667 50.778 30.848 ;
     RECT  2.415 30.847 14.166 30.859 ;
     RECT  14.904 30.569 46.782 30.859 ;
     RECT  0.144 30.125 0.558 31.133 ;
     RECT  50.184 30.848 50.778 31.133 ;
     RECT  0.144 31.133 0.234 31.225 ;
     RECT  2.415 30.859 46.782 31.243 ;
     RECT  47.52 30.721 48.597 31.261 ;
     RECT  2.304 31.243 46.782 31.289 ;
     RECT  2.415 31.289 46.782 31.483 ;
     RECT  47.52 31.261 48.69 31.483 ;
     RECT  2.415 31.483 48.69 31.495 ;
     RECT  50.184 31.133 50.706 31.565 ;
     RECT  2.415 31.495 48.726 31.709 ;
     RECT  51.732 31.675 51.75 31.757 ;
     RECT  0.072 31.225 0.234 31.805 ;
     RECT  2.415 31.709 44.874 32.035 ;
     RECT  0.072 31.805 0.198 32.429 ;
     RECT  49.608 32.071 49.698 32.429 ;
     RECT  50.688 31.565 50.706 32.431 ;
     RECT  45.615 31.709 48.726 32.459 ;
     RECT  50.688 32.431 50.742 32.683 ;
     RECT  1.98 32.035 44.874 32.765 ;
     RECT  45.615 32.459 48.597 32.873 ;
     RECT  50.148 32.683 50.742 32.873 ;
     RECT  34.704 32.765 44.874 32.971 ;
     RECT  45.615 32.873 46.854 32.971 ;
     RECT  1.98 32.765 33.93 32.999 ;
     RECT  34.704 32.971 46.854 32.999 ;
     RECT  1.98 32.999 33.786 33.007 ;
     RECT  1.404 33.007 33.786 33.035 ;
     RECT  50.688 32.873 50.742 33.437 ;
     RECT  49.788 33.259 49.806 33.449 ;
     RECT  34.776 32.999 46.854 33.575 ;
     RECT  0.072 32.429 0.162 33.581 ;
     RECT  47.592 32.873 48.597 33.691 ;
     RECT  50.688 33.437 50.706 33.691 ;
     RECT  50.148 33.691 50.706 33.809 ;
     RECT  1.404 33.035 33.57 33.961 ;
     RECT  50.184 33.809 50.706 34.013 ;
     RECT  34.776 33.575 46.17 34.079 ;
     RECT  47.088 33.691 48.597 34.079 ;
     RECT  34.776 34.079 36.234 34.115 ;
     RECT  1.404 33.961 33.858 34.357 ;
     RECT  34.776 34.115 36.198 34.357 ;
     RECT  0.072 33.581 0.09 34.465 ;
     RECT  37.008 34.079 46.17 34.493 ;
     RECT  41.256 34.493 46.17 34.501 ;
     RECT  41.256 34.501 46.53 34.619 ;
     RECT  1.404 34.357 36.198 34.727 ;
     RECT  51.732 33.835 51.75 34.727 ;
     RECT  47.592 34.079 48.597 34.735 ;
     RECT  49.392 34.411 49.41 34.735 ;
     RECT  47.592 34.735 49.41 34.843 ;
     RECT  47.592 34.843 49.878 34.861 ;
     RECT  37.008 34.493 40.497 34.889 ;
     RECT  47.556 34.861 49.878 34.889 ;
     RECT  41.256 34.619 46.17 34.925 ;
     RECT  31.788 34.727 36.198 35.005 ;
     RECT  37.008 34.889 38.538 35.005 ;
     RECT  47.556 34.889 48.69 35.005 ;
     RECT  45.615 34.925 46.17 35.069 ;
     RECT  49.752 34.889 49.878 35.131 ;
     RECT  50.688 34.013 50.706 35.131 ;
     RECT  45.615 35.069 46.098 35.159 ;
     RECT  1.404 34.727 31.05 35.165 ;
     RECT  47.484 35.005 48.69 35.227 ;
     RECT  47.268 35.227 48.69 35.231 ;
     RECT  49.752 35.131 50.706 35.267 ;
     RECT  0.072 34.465 0.234 35.275 ;
     RECT  1.404 35.165 14.202 35.275 ;
     RECT  31.788 35.005 38.538 35.339 ;
     RECT  0.072 35.275 14.202 35.357 ;
     RECT  14.94 35.165 31.05 35.429 ;
     RECT  31.788 35.339 38.322 35.465 ;
     RECT  30.42 35.429 31.05 35.545 ;
     RECT  31.788 35.465 38.286 35.545 ;
     RECT  39.348 34.889 40.497 35.581 ;
     RECT  41.256 34.925 44.874 35.581 ;
     RECT  39.348 35.581 44.874 35.735 ;
     RECT  47.268 35.231 47.538 35.779 ;
     RECT  47.196 35.779 47.538 35.879 ;
     RECT  14.94 35.429 29.697 35.899 ;
     RECT  39.348 35.735 40.497 35.941 ;
     RECT  41.256 35.735 44.874 36.049 ;
     RECT  45.615 35.159 45.897 36.049 ;
     RECT  0.072 35.357 13.986 36.121 ;
     RECT  14.796 35.899 29.697 36.121 ;
     RECT  30.42 35.545 38.286 36.211 ;
     RECT  47.304 35.879 47.538 36.211 ;
     RECT  48.315 35.231 48.69 36.211 ;
     RECT  50.148 35.267 50.706 36.239 ;
     RECT  0.072 36.121 29.697 36.355 ;
     RECT  30.42 36.211 38.466 36.355 ;
     RECT  41.256 36.049 45.897 36.355 ;
     RECT  41.256 36.355 46.062 36.427 ;
     RECT  39.276 35.941 40.497 36.475 ;
     RECT  41.256 36.427 46.35 36.475 ;
     RECT  47.304 36.211 48.69 36.517 ;
     RECT  0.072 36.355 38.466 36.589 ;
     RECT  39.276 36.475 46.35 36.589 ;
     RECT  0.072 36.589 46.35 36.689 ;
     RECT  47.304 36.517 49.158 36.715 ;
     RECT  44.892 36.689 46.35 36.751 ;
     RECT  47.304 36.715 49.806 36.751 ;
     RECT  50.688 36.239 50.706 36.853 ;
     RECT  50.688 36.853 50.778 36.893 ;
     RECT  44.892 36.751 49.806 37.291 ;
     RECT  50.688 36.893 50.706 37.291 ;
     RECT  0.072 36.689 44.082 37.589 ;
     RECT  44.892 37.291 50.706 37.613 ;
     RECT  44.892 37.613 49.23 37.757 ;
     RECT  0.072 37.589 43.866 37.769 ;
     RECT  50.148 37.613 50.706 37.901 ;
     RECT  50.22 37.901 50.706 37.939 ;
     RECT  50.22 37.939 50.742 38.045 ;
     RECT  0.072 37.769 43.578 38.515 ;
     RECT  44.892 37.757 49.086 38.515 ;
     RECT  50.22 38.045 50.706 38.641 ;
     RECT  0.072 38.515 49.086 38.705 ;
     RECT  50.184 38.641 50.706 38.765 ;
     RECT  0.072 38.705 44.874 38.975 ;
     RECT  45.615 38.705 49.086 39.011 ;
     RECT  0.072 38.975 3.438 39.047 ;
     RECT  4.248 38.975 44.874 39.047 ;
     RECT  47.412 39.011 49.086 39.055 ;
     RECT  47.412 39.055 49.302 39.091 ;
     RECT  4.68 39.047 44.874 39.209 ;
     RECT  50.652 38.765 50.706 39.559 ;
     RECT  47.412 39.091 49.626 39.595 ;
     RECT  50.652 39.559 50.742 39.659 ;
     RECT  4.68 39.209 44.334 39.793 ;
     RECT  50.688 39.659 50.742 39.793 ;
     RECT  0.072 39.047 3.042 39.865 ;
     RECT  47.412 39.595 49.77 39.883 ;
     RECT  4.608 39.793 44.334 39.893 ;
     RECT  47.376 39.883 49.77 39.893 ;
     RECT  0.072 39.865 3.51 39.901 ;
     RECT  4.608 39.893 28.674 39.901 ;
     RECT  50.688 39.793 50.778 39.917 ;
     RECT  29.415 39.893 44.334 40.063 ;
     RECT  29.415 40.063 44.478 40.109 ;
     RECT  47.376 39.893 49.626 40.289 ;
     RECT  49.608 40.289 49.626 40.349 ;
     RECT  45.615 39.011 46.638 40.405 ;
     RECT  47.376 40.289 48.87 40.405 ;
     RECT  45.252 40.405 48.87 40.441 ;
     RECT  50.688 39.917 50.706 40.639 ;
     RECT  0.072 39.901 28.674 40.711 ;
     RECT  29.415 40.109 44.226 40.711 ;
     RECT  50.652 40.639 50.706 40.711 ;
     RECT  50.652 40.711 50.742 40.739 ;
     RECT  50.688 40.739 50.742 40.925 ;
     RECT  0.072 40.711 44.226 40.939 ;
     RECT  45 40.441 48.87 40.939 ;
     RECT  49.788 40.747 49.806 41.323 ;
     RECT  0.072 40.939 48.87 41.485 ;
     RECT  49.788 41.323 49.842 41.485 ;
     RECT  0.036 41.485 49.842 41.549 ;
     RECT  50.688 40.925 50.706 41.719 ;
     RECT  0.036 41.549 49.266 42.053 ;
     RECT  50.148 41.719 50.706 42.151 ;
     RECT  50.148 42.151 50.742 42.331 ;
     RECT  0.036 42.053 48.942 42.449 ;
     RECT  45.54 42.449 48.942 42.521 ;
     RECT  49.68 42.331 50.742 42.521 ;
     RECT  50.688 42.521 50.742 42.653 ;
     RECT  49.68 42.521 49.734 43.105 ;
     RECT  49.32 43.105 49.734 43.169 ;
     RECT  51.732 41.467 51.75 43.331 ;
     RECT  0.036 42.449 44.73 43.411 ;
     RECT  45.54 42.521 48.597 43.411 ;
     RECT  49.32 43.169 49.338 43.439 ;
     RECT  0.036 43.411 48.597 43.501 ;
     RECT  50.688 42.653 50.706 43.609 ;
     RECT  50.184 43.609 50.706 43.681 ;
     RECT  0.036 43.501 49.014 43.709 ;
     RECT  45.615 43.709 49.014 44.105 ;
     RECT  50.184 43.681 50.742 44.203 ;
     RECT  50.148 44.203 50.742 44.339 ;
     RECT  49.788 44.491 49.806 44.789 ;
     RECT  0.036 43.709 44.658 44.879 ;
     RECT  50.688 44.339 50.742 44.957 ;
     RECT  50.688 44.957 50.706 45.301 ;
     RECT  50.184 45.301 50.706 45.389 ;
     RECT  45.615 44.105 48.597 45.571 ;
     RECT  45.615 45.571 49.014 45.725 ;
     RECT  49.788 45.787 49.806 46.139 ;
     RECT  51.732 45.499 51.75 46.337 ;
     RECT  50.688 45.389 50.706 46.507 ;
     RECT  45.615 45.725 48.654 46.579 ;
     RECT  50.184 46.507 50.706 46.651 ;
     RECT  45.615 46.579 49.014 46.679 ;
     RECT  0.036 44.879 44.37 46.769 ;
     RECT  50.184 46.651 50.778 46.829 ;
     RECT  45.615 46.679 48.654 46.891 ;
     RECT  50.184 46.829 50.742 46.939 ;
     RECT  50.148 46.939 50.742 46.949 ;
     RECT  50.148 46.949 50.706 47.039 ;
     RECT  0.036 46.769 44.118 47.309 ;
     RECT  45.108 46.891 48.654 47.309 ;
     RECT  49.5 47.083 49.662 47.515 ;
     RECT  45.108 47.309 48.597 47.563 ;
     RECT  3.636 47.309 44.046 47.579 ;
     RECT  44.964 47.563 48.597 47.615 ;
     RECT  49.356 47.515 49.662 47.687 ;
     RECT  49.572 47.687 49.662 47.837 ;
     RECT  50.688 47.039 50.706 48.001 ;
     RECT  50.688 48.001 50.742 48.091 ;
     RECT  0.036 47.309 2.862 48.127 ;
     RECT  3.636 47.579 44.01 48.127 ;
     RECT  44.82 47.731 44.874 48.271 ;
     RECT  44.784 48.271 44.874 48.389 ;
     RECT  50.652 48.091 50.742 48.413 ;
     RECT  0.036 48.127 44.01 48.461 ;
     RECT  45.615 47.615 48.597 48.667 ;
     RECT  49.572 47.837 49.626 48.667 ;
     RECT  50.652 48.413 50.706 48.667 ;
     RECT  44.496 48.715 44.514 49.195 ;
     RECT  0.036 48.461 43.542 49.315 ;
     RECT  44.352 49.195 44.514 49.315 ;
     RECT  45.615 48.667 50.706 49.565 ;
     RECT  45.615 49.565 49.806 49.577 ;
     RECT  45.615 49.577 48.942 49.819 ;
     RECT  0.036 49.315 44.514 49.855 ;
     RECT  0.036 49.855 44.694 49.981 ;
     RECT  49.788 49.577 49.806 49.997 ;
     RECT  45.612 49.819 48.942 50.009 ;
     RECT  0.036 49.981 44.766 50.045 ;
     RECT  36.504 50.045 44.766 50.153 ;
     RECT  45.612 50.009 48.69 50.153 ;
     RECT  51.732 50.107 51.75 50.387 ;
     RECT  50.688 49.565 50.706 50.395 ;
     RECT  45.615 50.153 48.69 50.549 ;
     RECT  50.112 50.395 50.706 50.585 ;
     RECT  50.148 50.585 50.706 50.683 ;
     RECT  0.036 50.045 35.766 50.791 ;
     RECT  36.504 50.153 43.758 50.791 ;
     RECT  50.148 50.683 50.742 50.999 ;
     RECT  50.652 50.999 50.742 51.197 ;
     RECT  44.496 50.153 44.514 51.355 ;
     RECT  45.615 50.549 48.597 51.355 ;
     RECT  50.652 51.197 50.706 51.359 ;
     RECT  0.036 50.791 43.758 51.367 ;
     RECT  44.496 51.355 48.597 51.367 ;
     RECT  0.036 51.367 48.87 51.629 ;
     RECT  49.824 51.403 49.878 52.007 ;
     RECT  51.732 51.259 51.75 52.079 ;
     RECT  49.824 52.007 49.842 52.249 ;
     RECT  49.608 52.249 49.842 52.285 ;
     RECT  50.688 51.359 50.706 52.411 ;
     RECT  49.572 52.285 49.842 52.445 ;
     RECT  0.036 51.629 48.69 52.555 ;
     RECT  50.688 52.411 50.742 52.589 ;
     RECT  0.036 52.555 48.798 52.709 ;
     RECT  49.824 52.445 49.842 52.987 ;
     RECT  50.688 52.589 50.706 52.987 ;
     RECT  49.824 52.987 50.706 53.024 ;
     RECT  50.688 53.024 50.706 53.527 ;
     RECT  0.036 52.709 48.597 53.941 ;
     RECT  49.824 53.024 49.842 53.969 ;
     RECT  50.688 53.527 50.742 53.995 ;
     RECT  50.184 53.995 50.742 54.131 ;
     RECT  0.036 53.941 48.69 54.175 ;
     RECT  50.688 54.131 50.742 54.317 ;
     RECT  0.036 54.175 49.158 54.599 ;
     RECT  51.732 52.843 51.75 54.779 ;
     RECT  50.688 54.317 50.706 54.859 ;
     RECT  50.148 54.859 50.706 55.021 ;
     RECT  0.036 54.599 48.597 55.453 ;
     RECT  49.572 55.021 50.706 55.453 ;
     RECT  0.036 55.453 50.706 55.553 ;
     RECT  0.036 55.553 48.798 55.679 ;
     RECT  49.644 55.553 50.706 56.371 ;
     RECT  0.036 55.679 48.69 56.489 ;
     RECT  51.732 56.299 51.75 56.866 ;
     RECT  51.696 56.866 51.75 56.867 ;
     RECT  49.608 56.371 50.706 56.903 ;
     RECT  51.696 56.867 51.714 57.065 ;
     RECT  50.688 56.903 50.706 57.137 ;
     RECT  49.572 57.019 49.59 57.299 ;
     RECT  0.036 56.489 48.597 57.569 ;
     RECT  49.644 58.261 49.662 58.315 ;
     RECT  0.036 57.569 46.458 58.387 ;
     RECT  49.644 58.315 50.166 58.459 ;
     RECT  0.036 58.387 46.674 58.495 ;
     RECT  47.484 57.569 48.597 58.495 ;
     RECT  0.036 58.495 48.597 58.757 ;
     RECT  49.572 58.459 50.742 58.781 ;
     RECT  0.072 58.757 48.597 59.225 ;
     RECT  50.688 58.781 50.742 59.357 ;
     RECT  50.688 59.357 50.706 59.504 ;
     RECT  49.572 58.781 49.626 59.611 ;
     RECT  10.44 59.225 48.597 59.729 ;
     RECT  49.572 59.611 50.67 59.729 ;
     RECT  42.156 59.729 48.597 59.885 ;
     RECT  0.072 59.225 9.702 59.971 ;
     RECT  10.44 59.729 11.07 59.971 ;
     RECT  50.148 59.729 50.67 60.08 ;
     RECT  50.688 60.241 50.706 60.365 ;
     RECT  51.732 60.187 51.75 60.475 ;
     RECT  0.072 59.971 11.07 60.511 ;
     RECT  11.808 59.729 41.418 60.511 ;
     RECT  42.48 59.885 48.597 60.539 ;
     RECT  51.696 60.475 51.75 60.539 ;
     RECT  0.072 60.511 41.418 60.575 ;
     RECT  51.696 60.539 51.714 60.575 ;
     RECT  47.448 60.539 48.597 60.881 ;
     RECT  36.576 60.575 41.418 60.961 ;
     RECT  42.48 60.539 46.458 60.961 ;
     RECT  0.072 60.575 35.838 61.357 ;
     RECT  36.576 60.961 46.458 61.357 ;
     RECT  0.072 61.357 46.458 61.925 ;
     RECT  47.556 60.881 48.597 62.005 ;
     RECT  47.412 62.005 48.597 62.851 ;
     RECT  50.184 62.851 50.202 62.923 ;
     RECT  50.184 62.923 50.706 63.049 ;
     RECT  47.304 62.851 48.597 63.121 ;
     RECT  47.304 63.121 48.87 63.239 ;
     RECT  47.304 63.239 48.597 63.391 ;
     RECT  0.108 61.925 46.458 63.481 ;
     RECT  47.232 63.391 48.597 63.481 ;
     RECT  51.732 63.355 51.75 63.617 ;
     RECT  51.696 63.643 51.714 63.779 ;
     RECT  50.148 63.049 50.706 63.823 ;
     RECT  0.108 63.481 48.597 63.965 ;
     RECT  50.148 63.823 50.742 64.201 ;
     RECT  49.608 64.201 50.742 64.397 ;
     RECT  1.44 63.965 48.597 64.471 ;
     RECT  50.148 64.397 50.742 64.499 ;
     RECT  50.688 64.499 50.742 64.541 ;
     RECT  1.44 64.471 49.122 64.625 ;
     RECT  2.052 64.625 49.122 64.895 ;
     RECT  2.052 64.895 41.382 64.967 ;
     RECT  2.052 64.967 39.15 65.117 ;
     RECT  51.732 65.083 51.75 65.129 ;
     RECT  42.192 64.895 49.122 65.261 ;
     RECT  42.192 65.261 48.597 65.399 ;
     RECT  45.108 65.399 48.597 65.435 ;
     RECT  2.376 65.117 39.15 65.669 ;
     RECT  47.304 65.435 48.597 65.669 ;
     RECT  40.215 64.967 41.382 65.707 ;
     RECT  42.192 65.399 44.37 65.707 ;
     RECT  2.415 65.669 39.15 65.713 ;
     RECT  40.215 65.707 44.37 65.713 ;
     RECT  50.688 64.541 50.706 65.803 ;
     RECT  0.108 63.965 0.558 65.837 ;
     RECT  49.608 65.509 49.626 65.981 ;
     RECT  48.315 65.669 48.597 66.361 ;
     RECT  50.652 65.803 50.706 66.361 ;
     RECT  0.144 65.837 0.558 66.413 ;
     RECT  2.415 65.713 44.37 66.427 ;
     RECT  2.415 66.427 44.478 66.631 ;
     RECT  45.324 65.435 46.386 66.631 ;
     RECT  0.18 66.413 0.558 66.701 ;
     RECT  2.415 66.631 46.386 66.721 ;
     RECT  47.304 65.669 47.574 66.721 ;
     RECT  50.184 66.361 50.706 66.721 ;
     RECT  2.415 66.721 47.574 66.749 ;
     RECT  2.415 66.749 44.37 66.757 ;
     RECT  49.608 66.721 50.706 66.857 ;
     RECT  48.315 66.361 48.654 66.865 ;
     RECT  0.216 66.701 0.558 66.989 ;
     RECT  49.608 66.857 49.626 66.989 ;
     RECT  48.315 66.865 48.762 67.135 ;
     RECT  50.688 66.857 50.706 67.171 ;
     RECT  45.144 66.749 47.574 67.297 ;
     RECT  48.315 67.135 49.014 67.297 ;
     RECT  2.34 66.757 44.37 67.441 ;
     RECT  2.304 67.441 44.37 67.565 ;
     RECT  50.688 67.171 50.742 67.565 ;
     RECT  25.128 67.565 44.37 67.603 ;
     RECT  45.144 67.297 49.014 67.603 ;
     RECT  25.128 67.603 49.014 67.819 ;
     RECT  25.128 67.819 49.194 67.909 ;
     RECT  25.128 67.909 49.626 68.099 ;
     RECT  0.288 66.989 0.558 68.107 ;
     RECT  45.108 68.099 49.626 68.107 ;
     RECT  50.688 67.565 50.706 68.107 ;
     RECT  2.304 67.565 24.354 68.299 ;
     RECT  25.128 68.099 44.37 68.299 ;
     RECT  45.108 68.107 50.706 68.405 ;
     RECT  51.732 66.091 51.75 68.429 ;
     RECT  2.304 68.299 44.37 68.747 ;
     RECT  13.104 68.747 44.37 68.945 ;
     RECT  0.144 68.107 0.558 68.953 ;
     RECT  0.108 68.953 0.558 69.005 ;
     RECT  49.788 68.405 50.706 69.061 ;
     RECT  45.108 68.405 48.762 69.187 ;
     RECT  49.788 69.061 50.742 69.187 ;
     RECT  14.472 68.945 44.37 69.215 ;
     RECT  45.108 69.187 50.742 69.287 ;
     RECT  45.108 69.287 48.87 69.359 ;
     RECT  49.788 69.287 50.742 69.359 ;
     RECT  2.304 68.747 12.366 69.547 ;
     RECT  13.104 68.945 13.59 69.547 ;
     RECT  23.256 69.215 44.37 69.547 ;
     RECT  45.108 69.359 48.597 69.547 ;
     RECT  2.304 69.547 13.59 69.691 ;
     RECT  14.472 69.215 22.23 69.691 ;
     RECT  50.148 69.359 50.742 69.725 ;
     RECT  2.304 69.691 22.23 70.061 ;
     RECT  0.108 69.005 0.522 70.069 ;
     RECT  23.256 69.547 48.597 70.267 ;
     RECT  2.304 70.061 17.442 70.301 ;
     RECT  51.732 70.267 51.75 70.367 ;
     RECT  0.108 70.069 0.558 70.375 ;
     RECT  18.216 70.061 22.23 70.375 ;
     RECT  23.076 70.267 48.597 70.375 ;
     RECT  18.216 70.375 48.597 70.403 ;
     RECT  50.148 69.725 50.706 70.501 ;
     RECT  49.608 70.501 50.706 70.681 ;
     RECT  49.608 70.681 50.742 70.699 ;
     RECT  36.972 70.403 48.597 70.799 ;
     RECT  49.572 70.699 50.742 70.877 ;
     RECT  49.572 70.877 50.706 70.907 ;
     RECT  2.415 70.301 17.442 71.041 ;
     RECT  18.216 70.403 36.162 71.041 ;
     RECT  37.044 70.799 48.597 71.069 ;
     RECT  37.044 71.069 39.222 71.249 ;
     RECT  2.415 71.041 36.162 71.455 ;
     RECT  39.96 71.069 48.597 71.455 ;
     RECT  2.304 71.455 36.162 71.491 ;
     RECT  50.112 70.907 50.706 71.519 ;
     RECT  2.304 71.491 36.234 71.609 ;
     RECT  39.96 71.455 48.942 71.609 ;
     RECT  27.756 71.609 36.234 71.879 ;
     RECT  39.96 71.609 48.618 71.915 ;
     RECT  45 71.915 48.618 71.987 ;
     RECT  51.732 71.995 51.75 72.149 ;
     RECT  37.08 71.249 39.222 72.157 ;
     RECT  39.96 71.915 44.082 72.157 ;
     RECT  28.548 71.879 36.234 72.229 ;
     RECT  37.08 72.157 44.082 72.229 ;
     RECT  50.148 71.519 50.706 72.427 ;
     RECT  2.304 71.609 26.997 72.499 ;
     RECT  27.756 71.879 27.774 72.499 ;
     RECT  49.572 72.427 50.706 72.499 ;
     RECT  2.304 72.499 27.774 72.653 ;
     RECT  49.572 72.499 50.742 72.749 ;
     RECT  23.004 72.653 27.774 72.763 ;
     RECT  28.548 72.229 44.082 72.763 ;
     RECT  45 71.987 48.597 72.841 ;
     RECT  50.112 72.749 50.742 72.931 ;
     RECT  45 72.841 49.23 72.959 ;
     RECT  2.304 72.653 22.23 72.995 ;
     RECT  23.004 72.763 44.082 73.075 ;
     RECT  45 72.959 48.798 73.075 ;
     RECT  0.072 70.375 0.558 73.139 ;
     RECT  50.112 72.931 50.778 73.325 ;
     RECT  23.004 73.075 48.798 73.337 ;
     RECT  50.112 73.325 50.706 73.469 ;
     RECT  23.004 73.337 44.082 73.499 ;
     RECT  50.112 73.469 50.202 73.651 ;
     RECT  45 73.337 48.798 73.769 ;
     RECT  0.144 73.139 0.558 73.901 ;
     RECT  2.304 72.995 10.797 73.921 ;
     RECT  11.628 72.995 22.23 73.921 ;
     RECT  2.304 73.921 22.23 74.011 ;
     RECT  23.004 73.499 32.85 74.011 ;
     RECT  2.304 74.011 32.85 74.045 ;
     RECT  33.696 73.499 44.082 74.083 ;
     RECT  45 73.769 46.386 74.083 ;
     RECT  0.252 73.901 0.558 74.155 ;
     RECT  49.608 73.651 50.202 74.417 ;
     RECT  2.34 74.045 32.85 74.461 ;
     RECT  33.696 74.083 46.386 74.461 ;
     RECT  0.252 74.155 0.594 74.477 ;
     RECT  2.34 74.461 46.386 74.551 ;
     RECT  47.124 73.769 48.597 74.551 ;
     RECT  2.34 74.551 48.597 74.615 ;
     RECT  2.34 74.615 36.27 74.621 ;
     RECT  49.464 74.551 49.482 74.621 ;
     RECT  0.252 74.477 0.558 74.683 ;
     RECT  0.144 74.683 0.558 74.909 ;
     RECT  0.144 74.909 0.486 75.053 ;
     RECT  37.008 74.615 48.597 75.119 ;
     RECT  50.688 74.443 50.706 75.163 ;
     RECT  45.615 75.119 48.597 75.271 ;
     RECT  2.34 74.621 36.09 75.355 ;
     RECT  37.008 75.119 44.046 75.355 ;
     RECT  45.615 75.271 49.086 75.425 ;
     RECT  51.732 74.623 51.75 75.497 ;
     RECT  2.34 75.355 44.046 75.533 ;
     RECT  50.148 75.163 50.706 75.628 ;
     RECT  45.615 75.425 48.942 75.767 ;
     RECT  0.216 75.053 0.486 75.883 ;
     RECT  50.148 75.628 50.742 75.917 ;
     RECT  45.615 75.767 48.798 75.929 ;
     RECT  0.144 75.883 0.486 76.013 ;
     RECT  0.216 76.013 0.486 76.045 ;
     RECT  45.615 75.929 46.494 76.081 ;
     RECT  2.34 75.533 25.938 76.171 ;
     RECT  26.715 75.533 44.046 76.199 ;
     RECT  47.34 75.929 48.798 76.199 ;
     RECT  26.715 76.199 43.938 76.235 ;
     RECT  45.504 76.081 46.494 76.351 ;
     RECT  45.36 76.351 46.494 76.363 ;
     RECT  2.304 76.171 25.938 76.441 ;
     RECT  26.715 76.235 36.054 76.441 ;
     RECT  2.304 76.441 36.054 76.459 ;
     RECT  50.148 75.917 50.238 76.459 ;
     RECT  1.98 76.459 36.054 76.469 ;
     RECT  36.792 76.235 43.938 76.469 ;
     RECT  44.928 76.363 46.494 76.585 ;
     RECT  48.315 76.199 48.798 76.585 ;
     RECT  1.98 76.469 24.642 76.589 ;
     RECT  25.488 76.469 36.054 76.739 ;
     RECT  36.792 76.469 43.866 76.739 ;
     RECT  2.415 76.589 24.642 76.781 ;
     RECT  0.216 76.045 0.558 76.855 ;
     RECT  2.415 76.781 24.606 76.883 ;
     RECT  44.892 76.585 46.494 76.891 ;
     RECT  47.34 76.199 47.502 76.891 ;
     RECT  49.86 76.459 50.238 76.891 ;
     RECT  44.892 76.891 47.502 76.981 ;
     RECT  48.315 76.585 49.014 76.981 ;
     RECT  49.86 76.891 50.706 76.981 ;
     RECT  48.315 76.981 50.706 77.017 ;
     RECT  44.82 76.981 47.502 77.035 ;
     RECT  48.315 77.017 50.742 77.035 ;
     RECT  2.415 76.883 11.07 77.045 ;
     RECT  44.82 77.035 50.742 77.045 ;
     RECT  36.792 76.739 43.83 77.161 ;
     RECT  49.572 77.045 50.742 77.287 ;
     RECT  2.415 77.045 6.318 77.351 ;
     RECT  44.82 77.045 48.597 77.395 ;
     RECT  25.488 76.739 35.766 77.431 ;
     RECT  49.572 77.287 50.778 77.501 ;
     RECT  11.844 76.883 24.606 77.521 ;
     RECT  25.452 77.431 35.766 77.521 ;
     RECT  36.504 77.161 43.83 77.521 ;
     RECT  50.688 77.501 50.778 77.557 ;
     RECT  11.844 77.521 43.83 77.563 ;
     RECT  44.784 77.395 48.597 77.563 ;
     RECT  51.804 77.521 51.822 77.563 ;
     RECT  51.66 77.563 51.822 77.621 ;
     RECT  7.272 77.045 11.07 77.629 ;
     RECT  11.844 77.563 48.597 77.629 ;
     RECT  0.108 76.855 0.558 77.645 ;
     RECT  0.108 77.645 0.306 77.789 ;
     RECT  49.572 77.501 49.734 77.827 ;
     RECT  7.272 77.629 48.597 77.863 ;
     RECT  49.356 77.827 49.734 77.863 ;
     RECT  7.272 77.863 49.734 77.947 ;
     RECT  6.804 77.947 49.734 77.999 ;
     RECT  50.688 77.557 50.814 78.169 ;
     RECT  2.415 77.351 5.994 78.241 ;
     RECT  6.804 77.999 49.626 78.241 ;
     RECT  0.144 77.789 0.306 78.403 ;
     RECT  0.144 78.403 0.45 78.475 ;
     RECT  1.368 78.427 1.386 78.475 ;
     RECT  50.688 78.169 50.85 78.475 ;
     RECT  0.144 78.475 1.386 78.653 ;
     RECT  50.652 78.475 50.85 78.673 ;
     RECT  0.144 78.653 1.314 78.797 ;
     RECT  2.415 78.241 49.626 79.007 ;
     RECT  34.452 79.007 49.626 79.051 ;
     RECT  50.616 78.673 50.85 79.051 ;
     RECT  2.415 79.007 33.678 79.169 ;
     RECT  34.452 79.051 50.85 79.169 ;
     RECT  0.144 78.797 1.17 79.195 ;
     RECT  29.016 79.169 31.374 79.205 ;
     RECT  34.524 79.169 40.806 79.205 ;
     RECT  2.415 79.169 27.414 79.229 ;
     RECT  29.415 79.205 31.374 79.229 ;
     RECT  32.115 79.169 33.678 79.229 ;
     RECT  2.415 79.229 22.914 79.277 ;
     RECT  34.815 79.205 40.806 79.277 ;
     RECT  0.108 79.195 1.17 79.349 ;
     RECT  18.615 79.277 22.914 79.349 ;
     RECT  23.832 79.229 27.414 79.349 ;
     RECT  2.415 79.277 17.874 79.439 ;
     RECT  22.752 79.349 22.914 79.439 ;
     RECT  29.415 79.229 30.87 79.439 ;
     RECT  33.228 79.229 33.678 79.439 ;
     RECT  34.815 79.277 38.79 79.439 ;
     RECT  39.708 79.277 40.806 79.439 ;
     RECT  41.616 79.169 50.85 79.439 ;
     RECT  2.415 79.439 12.366 79.475 ;
     RECT  13.212 79.439 16.197 79.475 ;
     RECT  17.1 79.439 17.118 79.475 ;
     RECT  22.752 79.439 22.878 79.475 ;
     RECT  25.992 79.349 27.414 79.475 ;
     RECT  34.815 79.439 35.586 79.475 ;
     RECT  39.708 79.439 40.497 79.475 ;
     RECT  42.915 79.439 46.314 79.475 ;
     RECT  47.088 79.439 50.85 79.475 ;
     RECT  26.715 79.475 27.414 79.511 ;
     RECT  30.852 79.439 30.87 79.511 ;
     RECT  33.66 79.439 33.678 79.511 ;
     RECT  42.915 79.475 46.098 79.511 ;
     RECT  47.952 79.475 50.85 79.517 ;
     RECT  6.3 79.475 6.498 79.547 ;
     RECT  10.332 79.475 11.934 79.547 ;
     RECT  22.86 79.475 22.878 79.547 ;
     RECT  23.832 79.349 25.254 79.547 ;
     RECT  18.615 79.349 21.978 79.583 ;
     RECT  7.308 79.475 9.594 79.619 ;
     RECT  10.332 79.547 11.538 79.619 ;
     RECT  24.015 79.547 25.254 79.619 ;
     RECT  47.952 79.517 50.814 79.619 ;
     RECT  0.18 79.349 1.17 79.661 ;
     RECT  48.24 79.619 50.814 79.661 ;
     RECT  2.415 79.475 5.397 79.667 ;
     RECT  13.212 79.475 13.497 79.667 ;
     RECT  14.508 79.475 16.197 79.667 ;
     RECT  18.615 79.583 18.897 79.667 ;
     RECT  20.124 79.583 21.597 79.667 ;
     RECT  26.715 79.511 26.997 79.667 ;
     RECT  29.415 79.439 29.697 79.667 ;
     RECT  32.115 79.229 32.397 79.667 ;
     RECT  34.815 79.475 35.097 79.667 ;
     RECT  40.215 79.475 40.497 79.667 ;
     RECT  2.415 79.667 5.205 79.709 ;
     RECT  6.3 79.547 6.426 79.709 ;
     RECT  7.308 79.619 8.946 79.709 ;
     RECT  10.515 79.619 10.926 79.709 ;
     RECT  13.212 79.667 13.374 79.709 ;
     RECT  14.508 79.667 16.005 79.709 ;
     RECT  20.124 79.667 21.405 79.709 ;
     RECT  24.015 79.619 25.11 79.709 ;
     RECT  37.515 79.439 38.358 79.709 ;
     RECT  41.652 79.439 41.814 79.709 ;
     RECT  42.915 79.511 44.01 79.709 ;
     RECT  44.784 79.511 46.098 79.709 ;
     RECT  47.088 79.475 47.214 79.709 ;
     RECT  48.24 79.661 49.554 79.709 ;
     RECT  3.6 79.709 5.205 79.745 ;
     RECT  6.3 79.709 6.318 79.745 ;
     RECT  7.815 79.709 8.838 79.745 ;
     RECT  13.212 79.709 13.305 79.745 ;
     RECT  14.508 79.709 14.85 79.745 ;
     RECT  20.124 79.709 20.142 79.745 ;
     RECT  24.015 79.709 24.174 79.745 ;
     RECT  24.984 79.709 25.002 79.745 ;
     RECT  37.515 79.709 38.214 79.745 ;
     RECT  44.892 79.709 45.705 79.745 ;
     RECT  48.315 79.709 49.554 79.745 ;
     RECT  3.672 79.745 3.798 79.781 ;
     RECT  41.796 79.709 41.814 79.781 ;
     RECT  3.78 79.781 3.798 79.889 ;
     RECT  44.928 79.745 45.705 79.889 ;
     RECT  2.415 79.709 2.826 79.937 ;
     RECT  5.115 79.745 5.205 79.937 ;
     RECT  7.815 79.745 7.905 79.937 ;
     RECT  10.515 79.709 10.605 79.937 ;
     RECT  13.215 79.745 13.305 79.937 ;
     RECT  15.915 79.709 16.005 79.937 ;
     RECT  18.615 79.667 18.705 79.937 ;
     RECT  20.952 79.709 21.405 79.937 ;
     RECT  24.015 79.745 24.105 79.937 ;
     RECT  26.715 79.667 26.805 79.937 ;
     RECT  29.415 79.667 29.505 79.937 ;
     RECT  32.115 79.667 32.205 79.937 ;
     RECT  34.815 79.667 34.905 79.937 ;
     RECT  37.515 79.745 37.605 79.937 ;
     RECT  40.215 79.667 40.305 79.937 ;
     RECT  42.915 79.709 43.005 79.937 ;
     RECT  44.964 79.889 45.705 79.937 ;
     RECT  48.315 79.745 48.405 79.937 ;
     RECT  2.736 79.937 2.826 80.093 ;
     RECT  44.964 79.937 45.342 80.093 ;
     RECT  50.724 79.661 50.814 80.237 ;
     RECT  50.796 80.237 50.814 80.381 ;
     RECT  0.216 79.661 1.17 80.525 ;
     RECT  2.808 80.093 2.826 80.669 ;
     RECT  51.696 77.621 51.822 80.669 ;
     RECT  0.216 80.525 0.342 80.813 ;
     RECT  49.248 79.745 49.554 80.813 ;
     RECT  0.216 80.813 0.306 80.905 ;
     RECT  0.108 80.905 0.306 80.933 ;
     RECT  0.108 80.933 0.27 80.957 ;
     RECT  49.248 80.813 49.266 80.957 ;
     RECT  51.732 80.669 51.822 81.095 ;
     RECT  0.108 80.957 0.126 81.101 ;
     RECT  51.732 81.095 51.75 81.104 ;
     RECT  1.152 80.525 1.17 81.245 ;
     RECT  45.324 80.093 45.342 81.245 ;
     RECT  20.952 79.937 21.186 82.043 ;
     RECT  20.97 82.043 21.06 82.061 ;
     RECT  21.078 82.043 21.168 82.061 ;
    LAYER M4 ;
     RECT  0.084 24.912 0.133 24.936 ;
     RECT  0.06 24.936 0.133 25.056 ;
     RECT  0.084 25.056 0.133 25.08 ;
     RECT  0.06 25.08 0.133 25.2 ;
     RECT  0.084 25.2 0.133 25.224 ;
     RECT  0.06 25.224 0.133 25.344 ;
     RECT  0.084 25.344 0.133 25.368 ;
     RECT  0.06 25.368 0.133 25.488 ;
     RECT  0.084 25.488 0.133 25.512 ;
     RECT  0.06 25.512 0.133 25.632 ;
     RECT  0.084 25.632 0.133 25.656 ;
     RECT  0.06 25.656 0.133 25.776 ;
     RECT  0.084 25.776 0.133 25.8 ;
     RECT  0.06 25.8 0.133 25.92 ;
     RECT  0.084 25.92 0.133 25.944 ;
     RECT  0.06 25.944 0.133 26.064 ;
     RECT  0.084 26.064 0.133 26.088 ;
     RECT  0.06 26.088 0.133 26.208 ;
     RECT  0.084 26.208 0.133 26.232 ;
     RECT  0.06 26.232 0.133 26.352 ;
     RECT  0.084 26.352 0.133 26.376 ;
     RECT  0.06 26.376 0.133 26.496 ;
     RECT  0.084 26.496 0.133 26.52 ;
     RECT  0.06 26.52 0.133 26.64 ;
     RECT  0.084 26.64 0.133 26.664 ;
     RECT  0.06 26.664 0.133 26.784 ;
     RECT  0.084 26.784 0.133 26.808 ;
     RECT  0.06 26.808 0.133 26.928 ;
     RECT  0.084 26.928 0.133 26.952 ;
     RECT  0.06 26.952 0.133 27.072 ;
     RECT  0.084 27.072 0.133 27.096 ;
     RECT  0.06 27.096 0.133 27.216 ;
     RECT  0.084 27.216 0.133 27.24 ;
     RECT  0.06 27.24 0.133 27.36 ;
     RECT  0.084 27.36 0.133 27.384 ;
     RECT  0.06 27.384 0.133 27.504 ;
     RECT  0.084 27.504 0.133 27.528 ;
     RECT  0.06 27.528 0.133 27.648 ;
     RECT  0.084 27.648 0.133 27.672 ;
     RECT  0.06 27.672 0.133 27.792 ;
     RECT  0.084 27.792 0.133 27.816 ;
     RECT  0.06 27.816 0.133 27.936 ;
     RECT  0.084 27.936 0.133 27.96 ;
     RECT  0.06 27.96 0.133 28.08 ;
     RECT  0.084 28.08 0.133 28.104 ;
     RECT  0.06 28.104 0.133 28.224 ;
     RECT  0.084 28.224 0.133 28.248 ;
     RECT  0.06 28.248 0.133 28.368 ;
     RECT  0.084 28.368 0.133 28.392 ;
     RECT  0.06 28.392 0.133 28.512 ;
     RECT  0.084 28.512 0.133 28.536 ;
     RECT  0.06 28.536 0.133 28.656 ;
     RECT  0.084 28.656 0.133 28.68 ;
     RECT  0.06 28.68 0.133 28.8 ;
     RECT  0.084 28.8 0.133 28.824 ;
     RECT  0.06 28.824 0.133 28.944 ;
     RECT  0.084 28.944 0.133 28.968 ;
     RECT  0.06 28.968 0.133 29.088 ;
     RECT  0.084 29.088 0.133 29.112 ;
     RECT  0.06 29.112 0.133 29.232 ;
     RECT  0.084 29.232 0.133 29.256 ;
     RECT  0.06 29.256 0.133 29.376 ;
     RECT  0.084 29.376 0.133 29.4 ;
     RECT  0.06 29.4 0.133 29.52 ;
     RECT  0.084 29.52 0.133 29.544 ;
     RECT  0.06 29.544 0.133 29.664 ;
     RECT  0.084 29.664 0.133 29.688 ;
     RECT  0.06 29.688 0.133 29.808 ;
     RECT  0.084 29.808 0.133 29.832 ;
     RECT  0.06 29.832 0.133 29.952 ;
     RECT  0.084 29.952 0.133 29.976 ;
     RECT  0.06 29.976 0.133 30.096 ;
     RECT  0.084 30.096 0.133 30.12 ;
     RECT  0.06 30.12 0.133 30.24 ;
     RECT  0.084 30.24 0.133 30.264 ;
     RECT  0.06 30.264 0.133 30.384 ;
     RECT  0.084 30.384 0.133 30.408 ;
     RECT  0.06 30.408 0.133 30.528 ;
     RECT  0.084 30.528 0.133 30.552 ;
     RECT  0.06 30.552 0.133 30.672 ;
     RECT  0.084 30.672 0.133 30.696 ;
     RECT  0.06 30.696 0.133 30.816 ;
     RECT  0.084 30.816 0.133 30.84 ;
     RECT  0.06 30.84 0.133 30.96 ;
     RECT  0.084 30.96 0.133 30.984 ;
     RECT  0.06 30.984 0.133 31.104 ;
     RECT  0.084 31.104 0.133 31.128 ;
     RECT  0.06 31.128 0.133 31.248 ;
     RECT  0.084 31.248 0.133 31.272 ;
     RECT  0.06 31.272 0.133 31.392 ;
     RECT  0.084 31.392 0.133 31.416 ;
     RECT  0.06 31.416 0.133 31.536 ;
     RECT  0.084 31.536 0.133 31.56 ;
     RECT  0.06 31.56 0.133 31.68 ;
     RECT  0.084 31.68 0.133 31.704 ;
     RECT  0.06 31.704 0.133 31.824 ;
     RECT  0.084 31.824 0.133 31.848 ;
     RECT  0.06 31.848 0.133 31.968 ;
     RECT  0.084 31.968 0.133 31.992 ;
     RECT  0.06 31.992 0.133 32.112 ;
     RECT  0.084 32.112 0.133 32.136 ;
     RECT  0.06 32.136 0.133 32.256 ;
     RECT  0.084 32.256 0.133 32.28 ;
     RECT  0.06 32.28 0.133 32.4 ;
     RECT  0.084 32.4 0.133 32.424 ;
     RECT  0.06 32.424 0.133 32.544 ;
     RECT  0.084 32.544 0.133 32.568 ;
     RECT  0.06 32.568 0.133 32.688 ;
     RECT  0.084 32.688 0.133 32.712 ;
     RECT  0.06 32.712 0.133 32.832 ;
     RECT  0.084 32.832 0.133 32.856 ;
     RECT  0.06 32.856 0.133 32.976 ;
     RECT  0.084 32.976 0.133 33 ;
     RECT  0.06 33 0.133 33.12 ;
     RECT  0.084 33.12 0.133 33.144 ;
     RECT  0.06 33.144 0.133 33.264 ;
     RECT  0.084 33.264 0.133 33.288 ;
     RECT  0.06 33.288 0.133 33.408 ;
     RECT  0.084 33.408 0.133 33.432 ;
     RECT  0.06 33.432 0.133 33.552 ;
     RECT  0.084 33.552 0.133 33.576 ;
     RECT  0.06 33.576 0.133 33.696 ;
     RECT  0.084 33.696 0.133 33.72 ;
     RECT  0.06 33.72 0.133 33.84 ;
     RECT  0.084 33.84 0.133 33.864 ;
     RECT  0.06 33.864 0.133 33.984 ;
     RECT  0.084 33.984 0.133 34.008 ;
     RECT  0.084 53.712 0.173 53.736 ;
     RECT  0.06 53.736 0.173 53.856 ;
     RECT  0.084 53.856 0.173 53.88 ;
     RECT  0.06 53.88 0.173 54 ;
     RECT  0.084 54 0.173 54.024 ;
     RECT  0.06 54.024 0.173 54.144 ;
     RECT  0.084 54.144 0.173 54.168 ;
     RECT  0.06 54.168 0.173 54.288 ;
     RECT  0.084 54.288 0.173 54.312 ;
     RECT  0.06 54.312 0.173 54.432 ;
     RECT  0.084 54.432 0.173 54.456 ;
     RECT  0.06 54.456 0.173 54.576 ;
     RECT  0.084 54.576 0.173 54.6 ;
     RECT  0.06 54.6 0.173 54.72 ;
     RECT  0.084 54.72 0.173 54.744 ;
     RECT  0.06 54.744 0.173 54.864 ;
     RECT  0.084 54.864 0.173 54.888 ;
     RECT  0.06 54.888 0.173 55.008 ;
     RECT  0.084 55.008 0.173 55.032 ;
     RECT  0.06 55.032 0.173 55.152 ;
     RECT  0.084 55.152 0.173 55.176 ;
     RECT  0.06 55.176 0.173 55.296 ;
     RECT  0.084 55.296 0.173 55.32 ;
     RECT  0.06 55.32 0.173 55.44 ;
     RECT  0.084 55.44 0.173 55.464 ;
     RECT  0.06 55.464 0.173 55.584 ;
     RECT  0.084 55.584 0.173 55.608 ;
     RECT  0.06 55.608 0.173 55.728 ;
     RECT  0.084 55.728 0.173 55.752 ;
     RECT  0.06 55.752 0.173 55.872 ;
     RECT  0.084 55.872 0.173 55.896 ;
     RECT  0.06 55.896 0.173 56.016 ;
     RECT  0.084 56.016 0.173 56.04 ;
     RECT  0.06 56.04 0.173 56.16 ;
     RECT  0.084 56.16 0.173 56.184 ;
     RECT  0.06 56.184 0.173 56.304 ;
     RECT  0.084 56.304 0.173 56.328 ;
     RECT  0.06 56.328 0.173 56.448 ;
     RECT  0.084 56.448 0.173 56.472 ;
     RECT  0.06 56.472 0.173 56.592 ;
     RECT  0.084 56.592 0.173 56.616 ;
     RECT  0.06 56.616 0.173 56.736 ;
     RECT  0.084 56.736 0.173 56.76 ;
     RECT  0.06 56.76 0.173 56.88 ;
     RECT  0.084 56.88 0.173 56.904 ;
     RECT  0.06 56.904 0.173 57.024 ;
     RECT  0.084 57.024 0.173 57.048 ;
     RECT  0.06 57.048 0.173 57.168 ;
     RECT  0.084 57.168 0.173 57.192 ;
     RECT  0.06 57.192 0.173 57.312 ;
     RECT  0.084 57.312 0.173 57.336 ;
     RECT  0.06 57.336 0.173 57.456 ;
     RECT  0.084 57.456 0.173 57.48 ;
     RECT  0.06 57.48 0.173 57.6 ;
     RECT  0.084 57.6 0.173 57.624 ;
     RECT  0.06 57.624 0.173 57.744 ;
     RECT  0.084 57.744 0.173 57.768 ;
     RECT  0.06 57.768 0.173 57.888 ;
     RECT  0.084 57.888 0.173 57.912 ;
     RECT  0.06 57.912 0.173 58.032 ;
     RECT  0.084 58.032 0.173 58.056 ;
     RECT  0.06 58.056 0.173 58.176 ;
     RECT  0.084 58.176 0.173 58.2 ;
     RECT  0.06 58.2 0.173 58.32 ;
     RECT  0.084 58.32 0.173 58.344 ;
     RECT  0.06 58.344 0.173 58.464 ;
     RECT  0.084 58.464 0.173 58.488 ;
     RECT  0.06 58.488 0.173 58.608 ;
     RECT  0.084 58.608 0.173 58.632 ;
     RECT  0.06 58.632 0.173 58.752 ;
     RECT  0.084 58.752 0.173 58.776 ;
     RECT  0.06 58.776 0.173 58.896 ;
     RECT  0.084 58.896 0.173 58.92 ;
     RECT  0.06 58.92 0.173 59.04 ;
     RECT  0.084 59.04 0.173 59.064 ;
     RECT  0.06 59.064 0.173 59.184 ;
     RECT  0.084 59.184 0.173 59.208 ;
     RECT  0.06 59.208 0.173 59.328 ;
     RECT  0.084 59.328 0.173 59.352 ;
     RECT  0.06 59.352 0.173 59.472 ;
     RECT  0.084 59.472 0.173 59.496 ;
     RECT  0.06 59.496 0.173 59.616 ;
     RECT  0.084 59.616 0.173 59.64 ;
     RECT  0.06 59.64 0.173 59.76 ;
     RECT  0.084 59.76 0.173 59.784 ;
     RECT  0.06 59.784 0.173 59.904 ;
     RECT  0.084 59.904 0.173 59.928 ;
     RECT  0.06 59.928 0.173 60.048 ;
     RECT  0.084 60.048 0.173 60.072 ;
     RECT  0.06 60.072 0.173 60.192 ;
     RECT  0.084 60.192 0.173 60.216 ;
     RECT  0.06 60.216 0.173 60.336 ;
     RECT  0.084 60.336 0.173 60.36 ;
     RECT  0.06 60.36 0.173 60.48 ;
     RECT  0.084 60.48 0.173 60.504 ;
     RECT  0.06 60.504 0.173 60.624 ;
     RECT  0.084 60.624 0.173 60.648 ;
     RECT  0.06 60.648 0.173 60.768 ;
     RECT  0.084 60.768 0.173 60.792 ;
     RECT  0.06 60.792 0.173 60.912 ;
     RECT  0.084 60.912 0.173 60.936 ;
     RECT  0.06 60.936 0.173 61.056 ;
     RECT  0.084 61.056 0.173 61.08 ;
     RECT  0.06 61.08 0.173 61.2 ;
     RECT  0.084 61.2 0.173 61.224 ;
     RECT  0.06 61.224 0.173 61.344 ;
     RECT  0.084 61.344 0.173 61.368 ;
     RECT  0.06 61.368 0.173 61.488 ;
     RECT  0.084 61.488 0.173 61.512 ;
     RECT  0.06 61.512 0.173 61.632 ;
     RECT  0.084 61.632 0.173 61.656 ;
     RECT  0.06 61.656 0.173 61.776 ;
     RECT  0.084 61.776 0.173 61.8 ;
     RECT  0.06 61.8 0.173 61.92 ;
     RECT  0.084 61.92 0.173 61.944 ;
     RECT  0.06 61.944 0.173 62.064 ;
     RECT  0.084 62.064 0.173 62.088 ;
     RECT  0.06 62.088 0.173 62.208 ;
     RECT  0.084 62.208 0.173 62.232 ;
     RECT  0.06 62.232 0.173 62.352 ;
     RECT  0.084 62.352 0.173 62.376 ;
     RECT  0.06 62.376 0.173 62.496 ;
     RECT  0.084 62.496 0.173 62.52 ;
     RECT  0.06 62.52 0.173 62.64 ;
     RECT  0.084 62.64 0.173 62.664 ;
     RECT  0.06 62.664 0.173 62.784 ;
     RECT  0.084 62.784 0.173 62.808 ;
     RECT  0.06 62.808 0.173 62.928 ;
     RECT  0.084 62.928 0.173 62.952 ;
     RECT  0.06 62.952 0.173 63.072 ;
     RECT  0.084 63.072 0.173 63.096 ;
     RECT  0.06 63.096 0.173 63.216 ;
     RECT  0.084 63.216 0.173 63.24 ;
     RECT  0.06 63.24 0.173 63.36 ;
     RECT  0.084 63.36 0.173 63.384 ;
     RECT  0.06 63.384 0.173 63.504 ;
     RECT  0.084 63.504 0.173 63.528 ;
     RECT  0.06 63.528 0.173 63.648 ;
     RECT  0.084 63.648 0.173 63.672 ;
     RECT  0.06 63.672 0.173 63.792 ;
     RECT  0.084 63.792 0.173 63.816 ;
     RECT  0.06 63.816 0.173 63.936 ;
     RECT  0.084 63.936 0.173 63.96 ;
     RECT  0.06 63.96 0.173 64.08 ;
     RECT  0.084 64.08 0.173 64.104 ;
     RECT  0.06 64.104 0.173 64.224 ;
     RECT  0.084 64.224 0.173 64.248 ;
     RECT  0.06 64.248 0.173 64.368 ;
     RECT  0.084 64.368 0.173 64.392 ;
     RECT  0.06 64.392 0.173 64.512 ;
     RECT  0.084 64.512 0.173 64.536 ;
     RECT  0.06 64.536 0.173 64.656 ;
     RECT  0.084 64.656 0.173 64.68 ;
     RECT  0.06 64.68 0.173 64.8 ;
     RECT  0.084 64.8 0.173 64.824 ;
     RECT  0.06 64.824 0.173 64.944 ;
     RECT  0.084 64.944 0.173 64.968 ;
     RECT  0.06 64.968 0.173 65.088 ;
     RECT  0.084 65.088 0.173 65.112 ;
     RECT  0.06 65.112 0.173 65.232 ;
     RECT  0.084 65.232 0.173 65.256 ;
     RECT  0.06 65.256 0.173 65.376 ;
     RECT  0.084 65.376 0.173 65.4 ;
     RECT  0.06 65.4 0.173 65.52 ;
     RECT  0.084 65.52 0.173 65.544 ;
     RECT  0.06 65.544 0.173 65.664 ;
     RECT  0.084 65.664 0.173 65.688 ;
     RECT  0.06 65.688 0.173 65.808 ;
     RECT  0.084 65.808 0.173 65.832 ;
     RECT  0.06 65.832 0.173 65.952 ;
     RECT  0.084 65.952 0.173 65.976 ;
     RECT  0.06 65.976 0.173 66.096 ;
     RECT  0.084 66.096 0.173 66.12 ;
     RECT  0.06 66.12 0.173 66.24 ;
     RECT  0.084 66.24 0.173 66.264 ;
     RECT  0.06 66.264 0.173 66.384 ;
     RECT  0.084 66.384 0.173 66.408 ;
     RECT  0.06 66.408 0.173 66.528 ;
     RECT  0.084 66.528 0.173 66.552 ;
     RECT  0.06 66.552 0.173 66.672 ;
     RECT  0.084 66.672 0.173 66.696 ;
     RECT  0.06 66.696 0.173 66.816 ;
     RECT  0.084 66.816 0.173 66.84 ;
     RECT  0.06 66.84 0.173 66.96 ;
     RECT  0.084 66.96 0.173 66.984 ;
     RECT  0.06 66.984 0.173 67.104 ;
     RECT  0.084 67.104 0.173 67.128 ;
     RECT  0.06 67.128 0.173 67.248 ;
     RECT  0.084 67.248 0.173 67.272 ;
     RECT  0.06 67.272 0.173 67.392 ;
     RECT  0.084 67.392 0.173 67.416 ;
     RECT  0.06 67.416 0.173 67.536 ;
     RECT  0.084 67.536 0.173 67.56 ;
     RECT  0.06 67.56 0.173 67.68 ;
     RECT  0.084 67.68 0.173 67.704 ;
     RECT  0.06 67.704 0.173 67.824 ;
     RECT  0.084 67.824 0.173 67.848 ;
     RECT  0.06 67.848 0.173 67.968 ;
     RECT  0.084 67.968 0.173 67.992 ;
     RECT  0.06 67.992 0.173 68.112 ;
     RECT  0.084 68.112 0.173 68.136 ;
     RECT  0.06 68.136 0.173 68.256 ;
     RECT  0.084 68.256 0.173 68.28 ;
     RECT  0.06 68.28 0.173 68.4 ;
     RECT  0.084 68.4 0.173 68.424 ;
     RECT  0.06 68.424 0.173 68.544 ;
     RECT  0.084 68.544 0.173 68.568 ;
     RECT  0.06 68.568 0.173 68.688 ;
     RECT  0.084 68.688 0.173 68.712 ;
     RECT  0.06 68.712 0.173 68.832 ;
     RECT  0.084 68.832 0.173 68.856 ;
     RECT  0.06 68.856 0.173 68.976 ;
     RECT  0.084 68.976 0.173 69 ;
     RECT  0.06 69 0.173 69.12 ;
     RECT  0.084 69.12 0.173 69.144 ;
     RECT  0.06 69.144 0.173 69.264 ;
     RECT  0.084 69.264 0.173 69.288 ;
     RECT  0.06 69.288 0.173 69.408 ;
     RECT  0.084 69.408 0.173 69.432 ;
     RECT  0.06 69.432 0.173 69.552 ;
     RECT  0.084 69.552 0.173 69.576 ;
     RECT  0.06 69.576 0.173 69.696 ;
     RECT  0.084 69.696 0.173 69.72 ;
     RECT  0.06 69.72 0.173 69.84 ;
     RECT  0.084 69.84 0.173 69.864 ;
     RECT  0.06 69.864 0.173 69.984 ;
     RECT  0.084 69.984 0.173 70.008 ;
     RECT  0.06 70.008 0.173 70.128 ;
     RECT  0.084 70.128 0.173 70.152 ;
     RECT  0.06 70.152 0.173 70.272 ;
     RECT  0.084 70.272 0.173 70.296 ;
     RECT  0.06 70.296 0.173 70.416 ;
     RECT  0.084 70.416 0.173 70.44 ;
     RECT  0.06 70.44 0.173 70.56 ;
     RECT  0.084 70.56 0.173 70.584 ;
     RECT  0.06 70.584 0.173 70.704 ;
     RECT  0.084 70.704 0.173 70.728 ;
     RECT  0.06 70.728 0.173 70.848 ;
     RECT  0.084 70.848 0.173 70.872 ;
     RECT  0.06 70.872 0.173 70.992 ;
     RECT  0.084 70.992 0.173 71.016 ;
     RECT  0.06 71.016 0.173 71.136 ;
     RECT  0.084 71.136 0.173 71.16 ;
     RECT  0.06 71.16 0.173 71.28 ;
     RECT  0.084 71.28 0.173 71.304 ;
     RECT  0.06 71.304 0.173 71.424 ;
     RECT  0.084 71.424 0.173 71.448 ;
     RECT  0.06 71.448 0.173 71.568 ;
     RECT  0.084 71.568 0.173 71.592 ;
     RECT  0.06 71.592 0.173 71.712 ;
     RECT  0.084 71.712 0.173 71.736 ;
     RECT  0.06 71.736 0.173 71.856 ;
     RECT  0.084 71.856 0.173 71.88 ;
     RECT  0.06 71.88 0.173 72 ;
     RECT  0.084 72 0.173 72.024 ;
     RECT  0.06 72.024 0.173 72.144 ;
     RECT  0.084 72.144 0.173 72.168 ;
     RECT  0.06 72.168 0.173 72.288 ;
     RECT  0.084 72.288 0.173 72.312 ;
     RECT  0.06 72.312 0.173 72.432 ;
     RECT  0.084 72.432 0.173 72.456 ;
     RECT  0.06 72.456 0.173 72.576 ;
     RECT  0.084 72.576 0.173 72.6 ;
     RECT  0.06 72.6 0.173 72.72 ;
     RECT  0.084 72.72 0.173 72.744 ;
     RECT  0.06 72.744 0.173 72.864 ;
     RECT  0.084 72.864 0.173 72.888 ;
     RECT  0.06 72.888 0.173 73.008 ;
     RECT  0.084 73.008 0.173 73.032 ;
     RECT  0.06 73.032 0.173 73.152 ;
     RECT  0.084 73.152 0.173 73.176 ;
     RECT  0.06 73.176 0.173 73.296 ;
     RECT  0.084 73.296 0.173 73.32 ;
     RECT  0.06 73.32 0.173 73.44 ;
     RECT  0.084 73.44 0.173 73.464 ;
     RECT  0.06 73.464 0.173 73.584 ;
     RECT  0.084 73.584 0.173 73.608 ;
     RECT  0.06 73.608 0.173 73.728 ;
     RECT  0.084 73.728 0.173 73.752 ;
     RECT  0.06 73.752 0.173 73.872 ;
     RECT  0.084 73.872 0.173 73.896 ;
     RECT  0.06 73.896 0.173 74.016 ;
     RECT  0.084 74.016 0.173 74.04 ;
     RECT  0.06 74.04 0.173 74.16 ;
     RECT  0.084 74.16 0.173 74.184 ;
     RECT  0.06 74.184 0.173 74.304 ;
     RECT  0.084 74.304 0.173 74.328 ;
     RECT  0.06 74.328 0.173 74.448 ;
     RECT  0.084 74.448 0.173 74.472 ;
     RECT  0.06 74.472 0.173 74.592 ;
     RECT  0.084 74.592 0.173 74.616 ;
     RECT  0.06 74.616 0.173 74.736 ;
     RECT  0.084 74.736 0.173 74.76 ;
     RECT  0.06 74.76 0.173 74.88 ;
     RECT  0.084 74.88 0.173 74.904 ;
     RECT  0.06 74.904 0.173 75.024 ;
     RECT  0.084 75.024 0.173 75.048 ;
     RECT  0.06 75.048 0.173 75.168 ;
     RECT  0.084 75.168 0.173 75.192 ;
     RECT  0.06 75.192 0.173 75.312 ;
     RECT  0.084 75.312 0.173 75.336 ;
     RECT  0.06 75.336 0.173 75.456 ;
     RECT  0.084 75.456 0.173 75.48 ;
     RECT  0.06 75.48 0.173 75.6 ;
     RECT  0.084 75.6 0.173 75.624 ;
     RECT  0.06 75.624 0.173 75.744 ;
     RECT  0.084 75.744 0.173 75.768 ;
     RECT  0.06 75.768 0.173 75.888 ;
     RECT  0.084 75.888 0.173 75.912 ;
     RECT  0.06 75.912 0.173 76.032 ;
     RECT  0.084 76.032 0.173 76.056 ;
     RECT  0.06 76.056 0.173 76.176 ;
     RECT  0.084 76.176 0.173 76.2 ;
     RECT  0.06 76.2 0.173 76.32 ;
     RECT  0.084 76.32 0.173 76.344 ;
     RECT  0.06 76.344 0.173 76.464 ;
     RECT  0.084 76.464 0.173 76.488 ;
     RECT  0.06 76.488 0.173 76.608 ;
     RECT  0.084 76.608 0.173 76.632 ;
     RECT  0.06 76.632 0.173 76.752 ;
     RECT  0.084 76.752 0.173 76.776 ;
     RECT  0.06 76.776 0.173 76.896 ;
     RECT  0.084 76.896 0.173 76.92 ;
     RECT  0.06 76.92 0.173 77.04 ;
     RECT  0.084 77.04 0.173 77.064 ;
     RECT  0.06 77.064 0.173 77.184 ;
     RECT  0.084 77.184 0.173 77.208 ;
     RECT  0.06 77.208 0.173 77.328 ;
     RECT  0.084 77.328 0.173 77.352 ;
     RECT  0.06 77.352 0.173 77.472 ;
     RECT  0.084 77.472 0.173 77.496 ;
     RECT  0.06 77.496 0.173 77.616 ;
     RECT  0.084 77.616 0.173 77.64 ;
     RECT  0.06 77.64 0.173 77.76 ;
     RECT  0.084 77.76 0.173 77.784 ;
     RECT  0.06 77.784 0.173 77.904 ;
     RECT  0.084 77.904 0.173 77.928 ;
     RECT  0.06 77.928 0.173 78.048 ;
     RECT  0.084 78.048 0.173 78.072 ;
     RECT  0.06 78.072 0.173 78.192 ;
     RECT  0.084 78.192 0.173 78.216 ;
     RECT  0.06 78.216 0.173 78.336 ;
     RECT  0.084 78.336 0.173 78.36 ;
     RECT  0.06 78.36 0.173 78.48 ;
     RECT  0.084 78.48 0.173 78.504 ;
     RECT  0.06 78.504 0.173 78.624 ;
     RECT  0.084 78.624 0.173 78.648 ;
     RECT  0.06 78.648 0.173 78.768 ;
     RECT  0.084 78.768 0.173 78.792 ;
     RECT  0.06 78.792 0.173 78.912 ;
     RECT  0.084 78.912 0.173 78.936 ;
     RECT  0.06 78.936 0.173 79.056 ;
     RECT  0.084 79.056 0.173 79.08 ;
     RECT  0.06 79.08 0.173 79.2 ;
     RECT  0.084 79.2 0.173 79.224 ;
     RECT  0.06 79.224 0.173 79.344 ;
     RECT  0.084 79.344 0.173 79.368 ;
     RECT  0.06 79.368 0.173 79.488 ;
     RECT  0.084 79.488 0.173 79.512 ;
     RECT  0.06 79.512 0.173 79.632 ;
     RECT  0.084 79.632 0.173 79.656 ;
     RECT  0.06 79.656 0.173 79.776 ;
     RECT  0.084 79.776 0.173 79.8 ;
     RECT  0.06 79.8 0.173 79.92 ;
     RECT  0.084 79.92 0.173 79.944 ;
     RECT  0.06 79.944 0.173 80.064 ;
     RECT  0.084 80.064 0.173 80.088 ;
     RECT  0.06 80.088 0.173 80.208 ;
     RECT  0.084 80.208 0.173 80.232 ;
     RECT  0.06 80.232 0.173 80.352 ;
     RECT  0.084 80.352 0.173 80.376 ;
     RECT  0.06 80.376 0.173 80.496 ;
     RECT  0.084 80.496 0.173 80.52 ;
     RECT  0.06 80.52 0.173 80.64 ;
     RECT  0.084 80.64 0.173 80.664 ;
     RECT  0.06 80.664 0.173 80.784 ;
     RECT  0.084 80.784 0.173 80.808 ;
     RECT  0.06 80.808 0.173 80.928 ;
     RECT  0.084 80.928 0.173 80.952 ;
     RECT  0.06 80.952 0.173 81.072 ;
     RECT  0.084 81.072 0.173 81.096 ;
     RECT  0.06 81.096 0.173 81.216 ;
     RECT  0.084 81.216 0.173 81.24 ;
     RECT  0.084 0.72 0.533 0.744 ;
     RECT  0.06 0.744 0.533 0.864 ;
     RECT  0.084 0.864 0.533 0.888 ;
     RECT  0.06 0.888 0.533 1.008 ;
     RECT  0.084 1.008 0.533 1.032 ;
     RECT  0.06 1.032 0.533 1.152 ;
     RECT  0.084 1.152 0.533 1.176 ;
     RECT  0.06 1.176 0.533 1.296 ;
     RECT  0.084 1.296 0.533 1.32 ;
     RECT  0.06 1.32 0.533 1.44 ;
     RECT  0.084 1.44 0.533 1.464 ;
     RECT  0.06 1.464 0.533 1.584 ;
     RECT  0.084 1.584 0.533 1.608 ;
     RECT  0.06 1.608 0.533 1.728 ;
     RECT  0.084 1.728 0.533 1.752 ;
     RECT  0.06 1.752 0.533 1.872 ;
     RECT  0.084 1.872 0.533 1.896 ;
     RECT  0.06 1.896 0.533 2.016 ;
     RECT  0.084 2.016 0.533 2.04 ;
     RECT  0.06 2.04 0.533 2.16 ;
     RECT  0.084 2.16 0.533 2.184 ;
     RECT  0.06 2.184 0.533 2.304 ;
     RECT  0.084 2.304 0.533 2.328 ;
     RECT  0.06 2.328 0.533 2.448 ;
     RECT  0.084 2.448 0.533 2.472 ;
     RECT  0.06 2.472 0.533 2.592 ;
     RECT  0.084 2.592 0.533 2.616 ;
     RECT  0.06 2.616 0.533 2.736 ;
     RECT  0.084 2.736 0.533 2.76 ;
     RECT  0.06 2.76 0.533 2.88 ;
     RECT  0.084 2.88 0.533 2.904 ;
     RECT  0.06 2.904 0.533 3.024 ;
     RECT  0.084 3.024 0.533 3.048 ;
     RECT  0.06 3.048 0.533 3.168 ;
     RECT  0.084 3.168 0.533 3.192 ;
     RECT  0.06 3.192 0.533 3.312 ;
     RECT  0.084 3.312 0.533 3.336 ;
     RECT  0.06 3.336 0.533 3.456 ;
     RECT  0.084 3.456 0.533 3.48 ;
     RECT  0.06 3.48 0.533 3.6 ;
     RECT  0.084 3.6 0.533 3.624 ;
     RECT  0.06 3.624 0.533 3.744 ;
     RECT  0.084 3.744 0.533 3.768 ;
     RECT  0.06 3.768 0.533 3.888 ;
     RECT  0.084 3.888 0.533 3.912 ;
     RECT  0.06 3.912 0.533 4.032 ;
     RECT  0.084 4.032 0.533 4.056 ;
     RECT  0.06 4.056 0.533 4.176 ;
     RECT  0.084 4.176 0.533 4.2 ;
     RECT  0.06 4.2 0.533 4.32 ;
     RECT  0.084 4.32 0.533 4.344 ;
     RECT  0.06 4.344 0.533 4.464 ;
     RECT  0.084 4.464 0.533 4.488 ;
     RECT  0.06 4.488 0.533 4.608 ;
     RECT  0.084 4.608 0.533 4.632 ;
     RECT  0.06 4.632 0.533 4.752 ;
     RECT  0.084 4.752 0.533 4.776 ;
     RECT  0.06 4.776 0.533 4.896 ;
     RECT  0.084 4.896 0.533 4.92 ;
     RECT  0.06 4.92 0.533 5.04 ;
     RECT  0.084 5.04 0.533 5.064 ;
     RECT  0.06 5.064 0.533 5.184 ;
     RECT  0.084 5.184 0.533 5.208 ;
     RECT  0.06 5.208 0.533 5.328 ;
     RECT  0.084 5.328 0.533 5.352 ;
     RECT  0.06 5.352 0.533 5.472 ;
     RECT  0.084 5.472 0.533 5.496 ;
     RECT  0.06 5.496 0.533 5.616 ;
     RECT  0.084 5.616 0.533 5.64 ;
     RECT  0.06 5.64 0.533 5.76 ;
     RECT  0.084 5.76 0.533 5.784 ;
     RECT  0.06 5.784 0.533 5.904 ;
     RECT  0.084 5.904 0.533 5.928 ;
     RECT  0.06 5.928 0.533 6.048 ;
     RECT  0.084 6.048 0.533 6.072 ;
     RECT  0.06 6.072 0.533 6.192 ;
     RECT  0.084 6.192 0.533 6.216 ;
     RECT  0.06 6.216 0.533 6.336 ;
     RECT  0.084 6.336 0.533 6.36 ;
     RECT  0.06 6.36 0.533 6.48 ;
     RECT  0.084 6.48 0.533 6.504 ;
     RECT  0.06 6.504 0.533 6.624 ;
     RECT  0.084 6.624 0.533 6.648 ;
     RECT  0.06 6.648 0.533 6.768 ;
     RECT  0.084 6.768 0.533 6.792 ;
     RECT  0.06 6.792 0.533 6.912 ;
     RECT  0.084 6.912 0.533 6.936 ;
     RECT  0.06 6.936 0.533 7.056 ;
     RECT  0.084 7.056 0.533 7.08 ;
     RECT  0.06 7.08 0.533 7.2 ;
     RECT  0.084 7.2 0.533 7.224 ;
     RECT  0.06 7.224 0.533 7.344 ;
     RECT  0.084 7.344 0.533 7.368 ;
     RECT  0.06 7.368 0.533 7.488 ;
     RECT  0.084 7.488 0.533 7.512 ;
     RECT  0.06 7.512 0.533 7.632 ;
     RECT  0.084 7.632 0.533 7.656 ;
     RECT  0.06 7.656 0.533 7.776 ;
     RECT  0.084 7.776 0.533 7.8 ;
     RECT  0.06 7.8 0.533 7.92 ;
     RECT  0.084 7.92 0.533 7.944 ;
     RECT  0.06 7.944 0.533 8.064 ;
     RECT  0.084 8.064 0.533 8.088 ;
     RECT  0.06 8.088 0.533 8.208 ;
     RECT  0.084 8.208 0.533 8.232 ;
     RECT  0.06 8.232 0.533 8.352 ;
     RECT  0.084 8.352 0.533 8.376 ;
     RECT  0.06 8.376 0.533 8.496 ;
     RECT  0.084 8.496 0.533 8.52 ;
     RECT  0.06 8.52 0.533 8.64 ;
     RECT  0.084 8.64 0.533 8.664 ;
     RECT  0.06 8.664 0.533 8.784 ;
     RECT  0.084 8.784 0.533 8.808 ;
     RECT  0.06 8.808 0.533 8.928 ;
     RECT  0.084 8.928 0.533 8.952 ;
     RECT  0.06 8.952 0.533 9.072 ;
     RECT  0.084 9.072 0.533 9.096 ;
     RECT  0.06 9.096 0.533 9.216 ;
     RECT  0.084 9.216 0.533 9.24 ;
     RECT  0.06 9.24 0.533 9.36 ;
     RECT  0.084 9.36 0.533 9.384 ;
     RECT  0.06 9.384 0.533 9.504 ;
     RECT  0.084 9.504 0.533 9.528 ;
     RECT  0.06 9.528 0.533 9.648 ;
     RECT  0.084 9.648 0.533 9.672 ;
     RECT  0.06 9.672 0.533 9.792 ;
     RECT  0.084 9.792 0.533 9.816 ;
     RECT  0.06 9.816 0.533 9.936 ;
     RECT  0.084 9.936 0.533 9.96 ;
     RECT  0.06 9.96 0.533 10.08 ;
     RECT  0.084 10.08 0.533 10.104 ;
     RECT  0.06 10.104 0.533 10.224 ;
     RECT  0.084 10.224 0.533 10.248 ;
     RECT  0.06 10.248 0.533 10.368 ;
     RECT  0.084 10.368 0.533 10.392 ;
     RECT  0.06 10.392 0.533 10.512 ;
     RECT  0.084 10.512 0.533 10.536 ;
     RECT  0.06 10.536 0.533 10.656 ;
     RECT  0.084 10.656 0.533 10.68 ;
     RECT  0.06 10.68 0.533 10.8 ;
     RECT  0.084 10.8 0.533 10.824 ;
     RECT  0.06 10.824 0.533 10.944 ;
     RECT  0.084 10.944 0.533 10.968 ;
     RECT  0.06 10.968 0.533 11.088 ;
     RECT  0.084 11.088 0.533 11.112 ;
     RECT  0.06 11.112 0.533 11.232 ;
     RECT  0.084 11.232 0.533 11.256 ;
     RECT  0.06 11.256 0.533 11.376 ;
     RECT  0.084 11.376 0.533 11.4 ;
     RECT  0.06 11.4 0.533 11.52 ;
     RECT  0.084 11.52 0.533 11.544 ;
     RECT  0.06 11.544 0.533 11.664 ;
     RECT  0.084 11.664 0.533 11.688 ;
     RECT  0.06 11.688 0.533 11.808 ;
     RECT  0.084 11.808 0.533 11.832 ;
     RECT  0.06 11.832 0.533 11.952 ;
     RECT  0.084 11.952 0.533 11.976 ;
     RECT  0.06 11.976 0.533 12.096 ;
     RECT  0.084 12.096 0.533 12.12 ;
     RECT  0.06 12.12 0.533 12.24 ;
     RECT  0.084 12.24 0.533 12.264 ;
     RECT  0.06 12.264 0.533 12.384 ;
     RECT  0.084 12.384 0.533 12.408 ;
     RECT  0.06 12.408 0.533 12.528 ;
     RECT  0.084 12.528 0.533 12.552 ;
     RECT  0.06 12.552 0.533 12.672 ;
     RECT  0.084 12.672 0.533 12.696 ;
     RECT  0.06 12.696 0.533 12.816 ;
     RECT  0.084 12.816 0.533 12.84 ;
     RECT  0.06 12.84 0.533 12.96 ;
     RECT  0.084 12.96 0.533 12.984 ;
     RECT  0.06 12.984 0.533 13.104 ;
     RECT  0.084 13.104 0.533 13.128 ;
     RECT  0.06 13.128 0.533 13.248 ;
     RECT  0.084 13.248 0.533 13.272 ;
     RECT  0.06 13.272 0.533 13.392 ;
     RECT  0.084 13.392 0.533 13.416 ;
     RECT  0.06 13.416 0.533 13.536 ;
     RECT  0.084 13.536 0.533 13.56 ;
     RECT  0.06 13.56 0.533 13.68 ;
     RECT  0.084 13.68 0.533 13.704 ;
     RECT  0.06 13.704 0.533 13.824 ;
     RECT  0.084 13.824 0.533 13.848 ;
     RECT  0.06 13.848 0.533 13.968 ;
     RECT  0.084 13.968 0.533 13.992 ;
     RECT  0.06 13.992 0.533 14.112 ;
     RECT  0.084 14.112 0.533 14.136 ;
     RECT  0.06 14.136 0.533 14.256 ;
     RECT  0.084 14.256 0.533 14.28 ;
     RECT  0.06 14.28 0.533 14.4 ;
     RECT  0.084 14.4 0.533 14.424 ;
     RECT  0.06 14.424 0.533 14.544 ;
     RECT  0.084 14.544 0.533 14.568 ;
     RECT  0.06 14.568 0.533 14.688 ;
     RECT  0.084 14.688 0.533 14.712 ;
     RECT  0.06 14.712 0.533 14.832 ;
     RECT  0.084 14.832 0.533 14.856 ;
     RECT  0.06 14.856 0.533 14.976 ;
     RECT  0.084 14.976 0.533 15 ;
     RECT  0.06 15 0.533 15.12 ;
     RECT  0.084 15.12 0.533 15.144 ;
     RECT  0.06 15.144 0.533 15.264 ;
     RECT  0.084 15.264 0.533 15.288 ;
     RECT  0.06 15.288 0.533 15.408 ;
     RECT  0.084 15.408 0.533 15.432 ;
     RECT  0.06 15.432 0.533 15.552 ;
     RECT  0.084 15.552 0.533 15.576 ;
     RECT  0.06 15.576 0.533 15.696 ;
     RECT  0.084 15.696 0.533 15.72 ;
     RECT  0.06 15.72 0.533 15.84 ;
     RECT  0.084 15.84 0.533 15.864 ;
     RECT  0.06 15.864 0.533 15.984 ;
     RECT  0.084 15.984 0.533 16.008 ;
     RECT  0.06 16.008 0.533 16.128 ;
     RECT  0.084 16.128 0.533 16.152 ;
     RECT  0.06 16.152 0.533 16.272 ;
     RECT  0.084 16.272 0.533 16.296 ;
     RECT  0.06 16.296 0.533 16.416 ;
     RECT  0.084 16.416 0.533 16.44 ;
     RECT  0.06 16.44 0.533 16.56 ;
     RECT  0.084 16.56 0.533 16.584 ;
     RECT  0.06 16.584 0.533 16.704 ;
     RECT  0.084 16.704 0.533 16.728 ;
     RECT  0.06 16.728 0.533 16.848 ;
     RECT  0.084 16.848 0.533 16.872 ;
     RECT  0.06 16.872 0.533 16.992 ;
     RECT  0.084 16.992 0.533 17.016 ;
     RECT  0.06 17.016 0.533 17.136 ;
     RECT  0.084 17.136 0.533 17.16 ;
     RECT  0.06 17.16 0.533 17.28 ;
     RECT  0.084 17.28 0.533 17.304 ;
     RECT  0.06 17.304 0.533 17.424 ;
     RECT  0.084 17.424 0.533 17.448 ;
     RECT  0.06 17.448 0.533 17.568 ;
     RECT  0.084 17.568 0.533 17.592 ;
     RECT  0.06 17.592 0.533 17.712 ;
     RECT  0.084 17.712 0.533 17.736 ;
     RECT  0.06 17.736 0.533 17.856 ;
     RECT  0.084 17.856 0.533 17.88 ;
     RECT  0.06 17.88 0.533 18 ;
     RECT  0.084 18 0.533 18.024 ;
     RECT  0.06 18.024 0.533 18.144 ;
     RECT  0.084 18.144 0.533 18.168 ;
     RECT  0.06 18.168 0.533 18.288 ;
     RECT  0.084 18.288 0.533 18.312 ;
     RECT  0.06 18.312 0.533 18.432 ;
     RECT  0.084 18.432 0.533 18.456 ;
     RECT  0.06 18.456 0.533 18.576 ;
     RECT  0.084 18.576 0.533 18.6 ;
     RECT  0.06 18.6 0.533 18.72 ;
     RECT  0.084 18.72 0.533 18.744 ;
     RECT  0.06 18.744 0.533 18.864 ;
     RECT  0.084 18.864 0.533 18.888 ;
     RECT  0.06 18.888 0.533 19.008 ;
     RECT  0.084 19.008 0.533 19.032 ;
     RECT  0.06 19.032 0.533 19.152 ;
     RECT  0.084 19.152 0.533 19.176 ;
     RECT  0.06 19.176 0.533 19.296 ;
     RECT  0.084 19.296 0.533 19.32 ;
     RECT  0.06 19.32 0.533 19.44 ;
     RECT  0.084 19.44 0.533 19.464 ;
     RECT  0.06 19.464 0.533 19.584 ;
     RECT  0.084 19.584 0.533 19.608 ;
     RECT  0.06 19.608 0.533 19.728 ;
     RECT  0.084 19.728 0.533 19.752 ;
     RECT  0.06 19.752 0.533 19.872 ;
     RECT  0.084 19.872 0.533 19.896 ;
     RECT  0.06 19.896 0.533 20.016 ;
     RECT  0.084 20.016 0.533 20.04 ;
     RECT  0.06 20.04 0.533 20.16 ;
     RECT  0.084 20.16 0.533 20.184 ;
     RECT  0.06 20.184 0.533 20.304 ;
     RECT  0.084 20.304 0.533 20.328 ;
     RECT  0.06 20.328 0.533 20.448 ;
     RECT  0.084 20.448 0.533 20.472 ;
     RECT  0.06 20.472 0.533 20.592 ;
     RECT  0.084 20.592 0.533 20.616 ;
     RECT  0.06 20.616 0.533 20.736 ;
     RECT  0.084 20.736 0.533 20.76 ;
     RECT  0.06 20.76 0.533 20.88 ;
     RECT  0.084 20.88 0.533 20.904 ;
     RECT  0.06 20.904 0.533 21.024 ;
     RECT  0.084 21.024 0.533 21.048 ;
     RECT  0.06 21.048 0.533 21.168 ;
     RECT  0.084 21.168 0.533 21.192 ;
     RECT  0.06 21.192 0.533 21.312 ;
     RECT  0.084 21.312 0.533 21.336 ;
     RECT  0.06 21.336 0.533 21.456 ;
     RECT  0.084 21.456 0.533 21.48 ;
     RECT  0.06 21.48 0.533 21.6 ;
     RECT  0.084 21.6 0.533 21.624 ;
     RECT  0.06 21.624 0.533 21.744 ;
     RECT  0.084 21.744 0.533 21.768 ;
     RECT  0.06 21.768 0.533 21.888 ;
     RECT  0.084 21.888 0.533 21.912 ;
     RECT  0.06 21.912 0.533 22.032 ;
     RECT  0.084 22.032 0.533 22.056 ;
     RECT  0.06 22.056 0.533 22.176 ;
     RECT  0.084 22.176 0.533 22.2 ;
     RECT  0.06 22.2 0.533 22.32 ;
     RECT  0.084 22.32 0.533 22.344 ;
     RECT  0.06 22.344 0.533 22.464 ;
     RECT  0.084 22.464 0.533 22.488 ;
     RECT  0.06 22.488 0.533 22.608 ;
     RECT  0.084 22.608 0.533 22.632 ;
     RECT  0.06 22.632 0.533 22.752 ;
     RECT  0.084 22.752 0.533 22.776 ;
     RECT  0.06 22.776 0.533 22.896 ;
     RECT  0.084 22.896 0.533 22.92 ;
     RECT  0.06 22.92 0.533 23.04 ;
     RECT  0.084 23.04 0.533 23.064 ;
     RECT  0.06 23.064 0.533 23.184 ;
     RECT  0.084 23.184 0.533 23.208 ;
     RECT  0.06 23.208 0.533 23.328 ;
     RECT  0.084 23.328 0.533 23.352 ;
     RECT  0.06 23.352 0.533 23.472 ;
     RECT  0.084 23.472 0.533 23.496 ;
     RECT  0.06 23.496 0.533 23.616 ;
     RECT  0.084 23.616 0.533 23.64 ;
     RECT  0.173 53.856 0.533 81.24 ;
     RECT  0.533 0.72 0.569 11.688 ;
     RECT  0.533 12.672 0.569 23.64 ;
     RECT  0.084 36.432 0.569 36.456 ;
     RECT  0.06 36.456 0.569 36.576 ;
     RECT  0.084 36.576 0.569 36.6 ;
     RECT  0.06 36.6 0.569 36.72 ;
     RECT  0.084 36.72 0.569 36.744 ;
     RECT  0.06 36.744 0.569 36.864 ;
     RECT  0.084 36.864 0.569 36.888 ;
     RECT  0.06 36.888 0.569 37.008 ;
     RECT  0.084 37.008 0.569 37.032 ;
     RECT  0.06 37.032 0.569 37.152 ;
     RECT  0.084 37.152 0.569 37.176 ;
     RECT  0.06 37.176 0.569 37.296 ;
     RECT  0.084 37.296 0.569 37.32 ;
     RECT  0.06 37.32 0.569 37.44 ;
     RECT  0.084 37.44 0.569 37.464 ;
     RECT  0.06 37.464 0.569 37.584 ;
     RECT  0.084 37.584 0.569 37.608 ;
     RECT  0.06 37.608 0.569 37.728 ;
     RECT  0.084 37.728 0.569 37.752 ;
     RECT  0.06 37.752 0.569 37.872 ;
     RECT  0.084 37.872 0.569 37.896 ;
     RECT  0.06 37.896 0.569 38.016 ;
     RECT  0.084 38.016 0.569 38.04 ;
     RECT  0.06 38.04 0.569 38.16 ;
     RECT  0.084 38.16 0.569 38.184 ;
     RECT  0.06 38.184 0.569 38.304 ;
     RECT  0.084 38.304 0.569 38.328 ;
     RECT  0.06 38.328 0.569 38.448 ;
     RECT  0.084 38.448 0.569 38.472 ;
     RECT  0.06 38.472 0.569 38.592 ;
     RECT  0.084 38.592 0.569 38.616 ;
     RECT  0.06 38.616 0.569 38.736 ;
     RECT  0.084 38.736 0.569 38.76 ;
     RECT  0.06 38.76 0.569 38.88 ;
     RECT  0.084 38.88 0.569 38.904 ;
     RECT  0.06 38.904 0.569 39.024 ;
     RECT  0.084 39.024 0.569 39.048 ;
     RECT  0.06 39.048 0.569 39.168 ;
     RECT  0.084 39.168 0.569 39.192 ;
     RECT  0.06 39.192 0.569 39.312 ;
     RECT  0.084 39.312 0.569 39.336 ;
     RECT  0.06 39.336 0.569 39.456 ;
     RECT  0.084 39.456 0.569 39.48 ;
     RECT  0.06 39.48 0.569 39.6 ;
     RECT  0.084 39.6 0.569 39.624 ;
     RECT  0.06 39.624 0.569 39.744 ;
     RECT  0.084 39.744 0.569 39.768 ;
     RECT  0.06 39.768 0.569 39.888 ;
     RECT  0.084 39.888 0.569 39.912 ;
     RECT  0.06 39.912 0.569 40.032 ;
     RECT  0.084 40.032 0.569 40.056 ;
     RECT  0.06 40.056 0.569 40.176 ;
     RECT  0.084 40.176 0.569 40.2 ;
     RECT  0.06 40.2 0.569 40.32 ;
     RECT  0.084 40.32 0.569 40.344 ;
     RECT  0.06 40.344 0.569 40.464 ;
     RECT  0.084 40.464 0.569 40.488 ;
     RECT  0.06 40.488 0.569 40.608 ;
     RECT  0.084 40.608 0.569 40.632 ;
     RECT  0.06 40.632 0.569 40.752 ;
     RECT  0.084 40.752 0.569 40.776 ;
     RECT  0.06 40.776 0.569 40.896 ;
     RECT  0.084 40.896 0.569 40.92 ;
     RECT  0.06 40.92 0.569 41.04 ;
     RECT  0.084 41.04 0.569 41.064 ;
     RECT  0.06 41.064 0.569 41.184 ;
     RECT  0.084 41.184 0.569 41.208 ;
     RECT  0.06 41.208 0.569 41.328 ;
     RECT  0.084 41.328 0.569 41.352 ;
     RECT  0.06 41.352 0.569 41.472 ;
     RECT  0.084 41.472 0.569 41.496 ;
     RECT  0.06 41.496 0.569 41.616 ;
     RECT  0.084 41.616 0.569 41.64 ;
     RECT  0.06 41.64 0.569 41.76 ;
     RECT  0.084 41.76 0.569 41.784 ;
     RECT  0.06 41.784 0.569 41.904 ;
     RECT  0.084 41.904 0.569 41.928 ;
     RECT  0.06 41.928 0.569 42.048 ;
     RECT  0.084 42.048 0.569 42.072 ;
     RECT  0.06 42.072 0.569 42.192 ;
     RECT  0.084 42.192 0.569 42.216 ;
     RECT  0.06 42.216 0.569 42.336 ;
     RECT  0.084 42.336 0.569 42.36 ;
     RECT  0.06 42.36 0.569 42.48 ;
     RECT  0.084 42.48 0.569 42.504 ;
     RECT  0.06 42.504 0.569 42.624 ;
     RECT  0.084 42.624 0.569 42.648 ;
     RECT  0.06 42.648 0.569 42.768 ;
     RECT  0.084 42.768 0.569 42.792 ;
     RECT  0.06 42.792 0.569 42.912 ;
     RECT  0.084 42.912 0.569 42.936 ;
     RECT  0.06 42.936 0.569 43.056 ;
     RECT  0.084 43.056 0.569 43.08 ;
     RECT  0.06 43.08 0.569 43.2 ;
     RECT  0.084 43.2 0.569 43.224 ;
     RECT  0.06 43.224 0.569 43.344 ;
     RECT  0.084 43.344 0.569 43.368 ;
     RECT  0.06 43.368 0.569 43.488 ;
     RECT  0.084 43.488 0.569 43.512 ;
     RECT  0.06 43.512 0.569 43.632 ;
     RECT  0.084 43.632 0.569 43.656 ;
     RECT  0.06 43.656 0.569 43.776 ;
     RECT  0.084 43.776 0.569 43.8 ;
     RECT  0.06 43.8 0.569 43.92 ;
     RECT  0.084 43.92 0.569 43.944 ;
     RECT  0.06 43.944 0.569 44.064 ;
     RECT  0.084 44.064 0.569 44.088 ;
     RECT  0.06 44.088 0.569 44.208 ;
     RECT  0.084 44.208 0.569 44.232 ;
     RECT  0.06 44.232 0.569 44.352 ;
     RECT  0.084 44.352 0.569 44.376 ;
     RECT  0.06 44.376 0.569 44.496 ;
     RECT  0.084 44.496 0.569 44.52 ;
     RECT  0.06 44.52 0.569 44.64 ;
     RECT  0.084 44.64 0.569 44.664 ;
     RECT  0.06 44.664 0.569 44.784 ;
     RECT  0.084 44.784 0.569 44.808 ;
     RECT  0.06 44.808 0.569 44.928 ;
     RECT  0.084 44.928 0.569 44.952 ;
     RECT  0.06 44.952 0.569 45.072 ;
     RECT  0.084 45.072 0.569 45.096 ;
     RECT  0.06 45.096 0.569 45.216 ;
     RECT  0.084 45.216 0.569 45.24 ;
     RECT  0.06 45.24 0.569 45.36 ;
     RECT  0.084 45.36 0.569 45.384 ;
     RECT  0.06 45.384 0.569 45.504 ;
     RECT  0.084 45.504 0.569 45.528 ;
     RECT  0.06 45.528 0.569 45.648 ;
     RECT  0.084 45.648 0.569 45.672 ;
     RECT  0.06 45.672 0.569 45.792 ;
     RECT  0.084 45.792 0.569 45.816 ;
     RECT  0.06 45.816 0.569 45.936 ;
     RECT  0.084 45.936 0.569 45.96 ;
     RECT  0.06 45.96 0.569 46.08 ;
     RECT  0.084 46.08 0.569 46.104 ;
     RECT  0.06 46.104 0.569 46.224 ;
     RECT  0.084 46.224 0.569 46.248 ;
     RECT  0.06 46.248 0.569 46.368 ;
     RECT  0.084 46.368 0.569 46.392 ;
     RECT  0.06 46.392 0.569 46.512 ;
     RECT  0.084 46.512 0.569 46.536 ;
     RECT  0.06 46.536 0.569 46.656 ;
     RECT  0.084 46.656 0.569 46.68 ;
     RECT  0.06 46.68 0.569 46.8 ;
     RECT  0.084 46.8 0.569 46.824 ;
     RECT  0.06 46.824 0.569 46.944 ;
     RECT  0.084 46.944 0.569 46.968 ;
     RECT  0.06 46.968 0.569 47.088 ;
     RECT  0.084 47.088 0.569 47.112 ;
     RECT  0.06 47.112 0.569 47.232 ;
     RECT  0.084 47.232 0.569 47.256 ;
     RECT  0.06 47.256 0.569 47.376 ;
     RECT  0.084 47.376 0.569 47.4 ;
     RECT  0.06 47.4 0.569 47.52 ;
     RECT  0.084 47.52 0.569 47.544 ;
     RECT  0.06 47.544 0.569 47.664 ;
     RECT  0.084 47.664 0.569 47.688 ;
     RECT  0.06 47.688 0.569 47.808 ;
     RECT  0.084 47.808 0.569 47.832 ;
     RECT  0.06 47.832 0.569 47.952 ;
     RECT  0.084 47.952 0.569 47.976 ;
     RECT  0.06 47.976 0.569 48.096 ;
     RECT  0.084 48.096 0.569 48.12 ;
     RECT  0.06 48.12 0.569 48.24 ;
     RECT  0.084 48.24 0.569 48.264 ;
     RECT  0.06 48.264 0.569 48.384 ;
     RECT  0.084 48.384 0.569 48.408 ;
     RECT  0.06 48.408 0.569 48.528 ;
     RECT  0.084 48.528 0.569 48.552 ;
     RECT  0.06 48.552 0.569 48.672 ;
     RECT  0.084 48.672 0.569 48.696 ;
     RECT  0.06 48.696 0.569 48.816 ;
     RECT  0.084 48.816 0.569 48.84 ;
     RECT  0.06 48.84 0.569 48.96 ;
     RECT  0.084 48.96 0.569 48.984 ;
     RECT  0.06 48.984 0.569 49.104 ;
     RECT  0.084 49.104 0.569 49.128 ;
     RECT  0.06 49.128 0.569 49.248 ;
     RECT  0.084 49.248 0.569 49.272 ;
     RECT  0.06 49.272 0.569 49.392 ;
     RECT  0.084 49.392 0.569 49.416 ;
     RECT  0.06 49.416 0.569 49.536 ;
     RECT  0.084 49.536 0.569 49.56 ;
     RECT  0.06 49.56 0.569 49.68 ;
     RECT  0.084 49.68 0.569 49.704 ;
     RECT  0.06 49.704 0.569 49.824 ;
     RECT  0.084 49.824 0.569 49.848 ;
     RECT  0.06 49.848 0.569 49.968 ;
     RECT  0.084 49.968 0.569 49.992 ;
     RECT  0.06 49.992 0.569 50.112 ;
     RECT  0.084 50.112 0.569 50.136 ;
     RECT  0.06 50.136 0.569 50.256 ;
     RECT  0.084 50.256 0.569 50.28 ;
     RECT  0.06 50.28 0.569 50.4 ;
     RECT  0.084 50.4 0.569 50.424 ;
     RECT  0.06 50.424 0.569 50.544 ;
     RECT  0.084 50.544 0.569 50.568 ;
     RECT  0.06 50.568 0.569 50.688 ;
     RECT  0.084 50.688 0.569 50.712 ;
     RECT  0.06 50.712 0.569 50.832 ;
     RECT  0.084 50.832 0.569 50.856 ;
     RECT  0.06 50.856 0.569 50.976 ;
     RECT  0.084 50.976 0.569 51 ;
     RECT  0.06 51 0.569 51.12 ;
     RECT  0.084 51.12 0.569 51.144 ;
     RECT  0.06 51.144 0.569 51.264 ;
     RECT  0.084 51.264 0.569 51.288 ;
     RECT  0.06 51.288 0.569 51.408 ;
     RECT  0.084 51.408 0.569 51.432 ;
     RECT  0.06 51.432 0.569 51.552 ;
     RECT  0.084 51.552 0.569 51.576 ;
     RECT  0.06 51.576 0.569 51.696 ;
     RECT  0.084 51.696 0.569 51.72 ;
     RECT  0.06 51.72 0.569 51.84 ;
     RECT  0.084 51.84 0.569 51.864 ;
     RECT  0.06 51.864 0.569 51.984 ;
     RECT  0.084 51.984 0.569 52.008 ;
     RECT  0.06 52.008 0.569 52.128 ;
     RECT  0.084 52.128 0.569 52.152 ;
     RECT  0.06 52.152 0.569 52.272 ;
     RECT  0.084 52.272 0.569 52.296 ;
     RECT  0.06 52.296 0.569 52.416 ;
     RECT  0.084 52.416 0.569 52.44 ;
     RECT  0.533 53.856 0.569 60.504 ;
     RECT  0.569 36.432 0.857 44.376 ;
     RECT  0.569 54 0.857 60.504 ;
     RECT  0.857 54 0.893 60.36 ;
     RECT  0.533 61.488 1.181 81.24 ;
     RECT  0.569 0.72 2.408 11.544 ;
     RECT  0.569 13.248 2.408 23.64 ;
     RECT  0.133 24.72 2.408 34.008 ;
     RECT  0.857 36.432 2.408 43.8 ;
     RECT  0.569 45.984 2.408 52.44 ;
     RECT  0.893 54 2.408 57.96 ;
     RECT  0.893 59.328 2.408 60.36 ;
     RECT  1.181 61.488 2.408 80.664 ;
     RECT  2.408 0.72 2.704 80.664 ;
     RECT  2.704 65.76 2.729 80.664 ;
     RECT  2.704 14.736 2.762 33.864 ;
     RECT  2.729 65.808 2.765 80.664 ;
     RECT  2.765 80.64 2.837 80.664 ;
     RECT  2.762 14.736 2.867 33.816 ;
     RECT  2.704 44.4 2.915 53.016 ;
     RECT  2.704 11.952 3.449 13.704 ;
     RECT  2.915 44.64 3.521 53.016 ;
     RECT  2.704 36.048 3.629 43.32 ;
     RECT  3.449 11.952 3.635 13.512 ;
     RECT  2.704 61.488 3.676 64.728 ;
     RECT  3.635 11.952 3.737 13.32 ;
     RECT  2.704 54.48 3.829 60.36 ;
     RECT  2.704 0.72 3.877 10.968 ;
     RECT  2.867 15.024 3.913 33.816 ;
     RECT  3.829 54.096 3.953 60.36 ;
     RECT  3.521 44.64 3.971 52.44 ;
     RECT  3.971 44.64 4.021 52.344 ;
     RECT  3.953 54.096 4.021 60.072 ;
     RECT  4.021 44.448 4.097 52.344 ;
     RECT  3.737 12.528 4.885 13.32 ;
     RECT  4.885 12.528 5.029 13.656 ;
     RECT  3.676 61.488 5.065 62.088 ;
     RECT  3.676 63.072 5.065 64.728 ;
     RECT  4.097 44.448 5.101 44.664 ;
     RECT  4.097 45.84 5.101 52.344 ;
     RECT  3.877 0.72 5.108 11.496 ;
     RECT  5.029 12.528 5.108 13.944 ;
     RECT  3.913 15.024 5.108 33.96 ;
     RECT  4.201 34.944 5.108 34.968 ;
     RECT  3.629 36.048 5.108 43.272 ;
     RECT  5.101 44.448 5.108 52.344 ;
     RECT  4.021 53.568 5.108 60.072 ;
     RECT  5.065 61.488 5.108 64.728 ;
     RECT  2.765 65.808 5.108 79.272 ;
     RECT  5.108 0.72 5.212 79.932 ;
     RECT  5.212 0.72 5.404 79.662 ;
     RECT  5.404 44.448 5.465 53.016 ;
     RECT  5.404 13.68 5.645 43.272 ;
     RECT  5.404 54 5.651 79.272 ;
     RECT  5.465 44.64 5.699 53.016 ;
     RECT  5.651 54 5.747 59.928 ;
     RECT  5.645 13.92 5.897 43.272 ;
     RECT  5.404 0.72 5.933 11.496 ;
     RECT  5.747 54.48 6.005 59.928 ;
     RECT  5.651 61.056 6.005 79.272 ;
     RECT  6.005 61.392 6.149 79.272 ;
     RECT  5.897 14.064 6.473 43.272 ;
     RECT  6.473 14.064 6.515 34.968 ;
     RECT  5.699 44.784 7.045 53.016 ;
     RECT  7.045 44.784 7.081 53.064 ;
     RECT  5.933 0.72 7.153 10.824 ;
     RECT  6.469 11.952 7.153 11.976 ;
     RECT  6.473 36.288 7.189 43.272 ;
     RECT  7.081 44.448 7.261 53.064 ;
     RECT  6.005 54.48 7.441 59.592 ;
     RECT  7.225 13.296 7.477 13.32 ;
     RECT  7.477 13.104 7.58 13.32 ;
     RECT  6.515 14.4 7.58 34.968 ;
     RECT  7.441 54.48 7.585 59.832 ;
     RECT  6.149 61.392 7.657 62.04 ;
     RECT  6.149 63.024 7.657 79.272 ;
     RECT  7.153 0.72 7.808 11.976 ;
     RECT  7.58 13.104 7.808 34.968 ;
     RECT  7.189 36.288 7.808 43.368 ;
     RECT  7.261 44.4 7.808 53.064 ;
     RECT  7.585 54.48 7.808 59.88 ;
     RECT  7.657 61.392 7.808 79.272 ;
     RECT  7.808 0.72 7.912 79.932 ;
     RECT  7.912 0.72 8.104 79.662 ;
     RECT  8.104 11.76 8.921 52.728 ;
     RECT  8.921 11.76 8.963 34.872 ;
     RECT  8.921 35.856 9.101 52.728 ;
     RECT  8.963 11.76 9.173 23.64 ;
     RECT  8.104 0.72 9.205 10.728 ;
     RECT  8.963 24.672 9.209 34.344 ;
     RECT  9.173 11.76 9.245 12.312 ;
     RECT  9.173 13.584 9.281 23.64 ;
     RECT  8.104 54.096 9.389 59.88 ;
     RECT  8.104 61.392 9.457 79.272 ;
     RECT  9.205 0.72 9.637 10.776 ;
     RECT  9.245 11.76 9.637 11.784 ;
     RECT  9.101 36.384 9.961 52.728 ;
     RECT  9.389 54.096 9.961 59.784 ;
     RECT  9.209 24.72 10.105 34.344 ;
     RECT  9.281 14.736 10.285 23.64 ;
     RECT  10.105 24.72 10.285 34.92 ;
     RECT  9.637 0.72 10.508 11.784 ;
     RECT  9.281 13.584 10.508 13.608 ;
     RECT  10.285 14.736 10.508 34.92 ;
     RECT  9.961 36.384 10.508 59.784 ;
     RECT  9.457 60.96 10.508 79.272 ;
     RECT  10.508 0.72 10.612 79.932 ;
     RECT  10.612 0.72 10.804 79.662 ;
     RECT  10.804 65.712 11.117 79.272 ;
     RECT  10.804 0.72 11.212 12.552 ;
     RECT  10.804 13.872 11.297 52.584 ;
     RECT  11.297 13.872 11.549 43.656 ;
     RECT  11.297 44.688 11.585 52.584 ;
     RECT  11.549 13.872 11.657 34.92 ;
     RECT  10.804 53.856 11.765 59.64 ;
     RECT  11.765 53.856 11.801 58.248 ;
     RECT  11.657 13.872 11.869 34.488 ;
     RECT  11.585 44.688 11.945 52.536 ;
     RECT  11.765 59.52 11.945 59.64 ;
     RECT  11.212 0.72 12.125 11.784 ;
     RECT  11.117 65.712 12.157 79.08 ;
     RECT  11.801 53.856 12.193 57.96 ;
     RECT  11.869 12.912 12.197 34.488 ;
     RECT  11.945 59.52 12.233 59.592 ;
     RECT  11.549 36.384 12.301 43.656 ;
     RECT  11.945 44.688 12.301 52.296 ;
     RECT  10.804 61.392 12.301 64.728 ;
     RECT  12.157 65.712 12.301 79.272 ;
     RECT  12.301 61.392 12.337 79.272 ;
     RECT  12.337 60.816 12.445 79.464 ;
     RECT  12.301 36.384 12.517 52.296 ;
     RECT  12.197 13.104 12.949 34.488 ;
     RECT  12.193 53.568 13.021 57.96 ;
     RECT  12.125 0.72 13.208 10.776 ;
     RECT  12.125 11.76 13.208 11.784 ;
     RECT  12.949 13.104 13.208 34.536 ;
     RECT  12.517 35.808 13.208 52.296 ;
     RECT  13.021 53.328 13.208 57.96 ;
     RECT  12.233 59.568 13.208 59.592 ;
     RECT  12.445 60.672 13.208 79.464 ;
     RECT  13.208 0.72 13.312 79.932 ;
     RECT  13.312 0.72 13.504 79.662 ;
     RECT  13.504 13.104 13.601 44.712 ;
     RECT  13.504 59.184 13.673 79.464 ;
     RECT  13.504 45.744 13.715 58.152 ;
     RECT  13.673 59.568 13.737 79.464 ;
     RECT  13.601 13.104 13.853 44.472 ;
     RECT  13.737 59.568 13.961 79.272 ;
     RECT  13.853 13.584 14.213 44.472 ;
     RECT  14.213 13.824 14.285 44.472 ;
     RECT  13.715 53.328 14.605 58.152 ;
     RECT  13.961 60.816 14.609 79.272 ;
     RECT  14.605 53.328 14.821 58.248 ;
     RECT  13.961 59.568 14.821 59.784 ;
     RECT  14.285 14.352 14.857 44.472 ;
     RECT  13.715 45.744 14.857 52.248 ;
     RECT  14.821 53.328 14.857 59.784 ;
     RECT  14.857 53.232 15.181 59.784 ;
     RECT  14.857 14.352 15.253 52.248 ;
     RECT  15.181 53.232 15.253 59.88 ;
     RECT  14.609 61.056 15.325 79.272 ;
     RECT  13.504 0.72 15.361 11.928 ;
     RECT  15.253 14.352 15.361 59.88 ;
     RECT  15.361 13.632 15.685 59.88 ;
     RECT  15.325 61.056 15.685 79.464 ;
     RECT  15.361 0.72 15.793 12.072 ;
     RECT  15.793 0.72 15.908 12.264 ;
     RECT  15.685 13.632 15.908 79.464 ;
     RECT  15.908 0.72 16.012 79.932 ;
     RECT  16.012 0.72 16.204 79.662 ;
     RECT  16.204 0.72 16.337 58.056 ;
     RECT  16.204 59.184 16.355 79.464 ;
     RECT  16.337 13.104 16.396 58.056 ;
     RECT  16.396 13.104 16.445 57.96 ;
     RECT  16.445 14.736 16.589 57.96 ;
     RECT  16.445 13.104 16.633 13.752 ;
     RECT  16.589 14.736 16.979 43.656 ;
     RECT  16.355 59.568 17.129 79.464 ;
     RECT  17.129 59.568 17.381 79.272 ;
     RECT  16.633 13.68 17.413 13.752 ;
     RECT  16.979 14.736 17.413 34.2 ;
     RECT  16.589 44.928 17.453 57.96 ;
     RECT  17.413 13.68 17.653 34.2 ;
     RECT  16.979 36.288 17.773 43.656 ;
     RECT  17.665 44.688 17.773 44.76 ;
     RECT  17.381 59.568 17.953 59.784 ;
     RECT  17.953 59.52 18.385 59.784 ;
     RECT  17.381 60.816 18.385 79.272 ;
     RECT  16.337 0.72 18.608 12.072 ;
     RECT  17.653 13.344 18.608 34.2 ;
     RECT  16.979 35.28 18.608 35.304 ;
     RECT  17.773 36.288 18.608 44.76 ;
     RECT  17.453 45.744 18.608 57.96 ;
     RECT  18.385 59.52 18.608 79.272 ;
     RECT  18.608 0.72 18.712 79.932 ;
     RECT  18.712 0.72 18.904 79.662 ;
     RECT  18.904 14.208 19.081 58.152 ;
     RECT  18.904 59.136 19.427 60.6 ;
     RECT  19.081 24.624 19.433 58.152 ;
     RECT  19.427 59.568 19.505 60.6 ;
     RECT  18.904 61.68 19.969 79.224 ;
     RECT  19.969 60.96 20.113 79.224 ;
     RECT  18.904 0.72 20.225 11.784 ;
     RECT  20.113 60.96 20.243 79.272 ;
     RECT  19.505 59.568 20.261 59.928 ;
     RECT  19.433 24.624 20.297 43.656 ;
     RECT  19.081 14.208 20.329 23.592 ;
     RECT  20.329 13.68 20.485 23.592 ;
     RECT  20.297 24.624 20.485 34.872 ;
     RECT  19.433 44.688 20.684 58.152 ;
     RECT  20.261 59.568 20.684 59.784 ;
     RECT  20.243 60.96 20.725 79.224 ;
     RECT  20.225 0.72 20.773 10.68 ;
     RECT  20.485 13.68 20.977 34.872 ;
     RECT  20.225 11.76 21.049 11.784 ;
     RECT  20.977 13.296 21.049 34.872 ;
     RECT  20.297 36.288 21.085 43.656 ;
     RECT  20.684 44.688 21.085 59.784 ;
     RECT  20.773 0.048 21.193 10.68 ;
     RECT  21.049 11.76 21.193 34.872 ;
     RECT  21.193 0.048 21.308 34.872 ;
     RECT  21.085 36.288 21.308 59.784 ;
     RECT  20.725 60.912 21.308 79.224 ;
     RECT  21.308 0.048 21.412 79.932 ;
     RECT  21.412 0.048 21.604 79.662 ;
     RECT  21.604 45.744 21.737 79.224 ;
     RECT  21.604 14.064 21.779 34.2 ;
     RECT  21.604 0.048 21.881 12.552 ;
     RECT  21.737 60.816 21.881 79.224 ;
     RECT  21.779 14.208 21.989 34.2 ;
     RECT  21.881 60.816 22.421 79.032 ;
     RECT  22.421 60.864 22.565 79.032 ;
     RECT  21.604 35.568 22.597 44.232 ;
     RECT  21.737 45.744 22.597 59.784 ;
     RECT  21.881 0.048 22.817 12.408 ;
     RECT  21.989 14.4 22.889 34.2 ;
     RECT  22.817 11.76 22.921 12.408 ;
     RECT  22.565 61.68 22.969 79.032 ;
     RECT  22.969 65.952 23.245 79.032 ;
     RECT  22.921 11.76 23.309 13.32 ;
     RECT  22.889 14.4 23.309 29.592 ;
     RECT  22.969 61.68 23.857 64.728 ;
     RECT  22.817 0.048 24.008 10.68 ;
     RECT  23.309 11.76 24.008 29.592 ;
     RECT  22.889 30.576 24.008 34.2 ;
     RECT  22.597 35.568 24.008 59.784 ;
     RECT  23.857 60.816 24.008 64.728 ;
     RECT  23.245 65.952 24.008 79.224 ;
     RECT  24.008 0.048 24.112 79.932 ;
     RECT  24.112 0.048 24.304 79.662 ;
     RECT  24.304 14.064 24.563 63.192 ;
     RECT  24.304 0.048 25.043 12.552 ;
     RECT  24.563 61.68 25.333 63.192 ;
     RECT  24.304 64.176 25.333 79.032 ;
     RECT  25.043 0.72 25.337 12.552 ;
     RECT  24.563 14.064 25.477 59.976 ;
     RECT  25.337 11.76 25.549 12.552 ;
     RECT  25.477 13.68 25.549 59.976 ;
     RECT  25.549 11.76 25.621 60.408 ;
     RECT  25.621 11.76 25.693 60.696 ;
     RECT  25.333 61.68 25.693 79.032 ;
     RECT  25.337 0.72 26.708 10.728 ;
     RECT  25.693 11.76 26.708 79.032 ;
     RECT  26.708 0.72 26.812 79.932 ;
     RECT  26.812 0.72 27.004 79.662 ;
     RECT  27.004 59.472 27.029 79.032 ;
     RECT  27.004 12.768 27.065 12.888 ;
     RECT  27.004 14.64 27.155 58.152 ;
     RECT  27.029 59.472 27.317 60.696 ;
     RECT  27.155 14.736 27.353 58.152 ;
     RECT  27.353 14.736 27.408 34.392 ;
     RECT  27.353 36.096 27.605 58.152 ;
     RECT  27.065 12.864 28.105 12.888 ;
     RECT  27.004 0.72 28.109 11.784 ;
     RECT  27.408 14.736 28.493 34.2 ;
     RECT  28.105 12.768 28.609 12.888 ;
     RECT  27.317 59.472 28.645 59.88 ;
     RECT  28.645 59.472 28.753 60.264 ;
     RECT  28.493 14.736 28.844 34.824 ;
     RECT  27.029 61.68 29.077 79.032 ;
     RECT  28.109 11.664 29.293 11.784 ;
     RECT  28.609 12.768 29.293 13.128 ;
     RECT  28.109 0.72 29.408 10.68 ;
     RECT  29.293 11.664 29.408 13.128 ;
     RECT  28.844 14.736 29.408 35.304 ;
     RECT  27.605 36.288 29.408 58.152 ;
     RECT  28.753 59.184 29.408 60.264 ;
     RECT  29.077 61.344 29.408 79.224 ;
     RECT  29.408 0.72 29.512 79.932 ;
     RECT  29.512 0.72 29.704 79.662 ;
     RECT  29.704 14.304 29.765 59.88 ;
     RECT  29.704 61.056 29.981 79.224 ;
     RECT  29.765 14.304 30.521 57.72 ;
     RECT  30.521 14.304 30.757 34.488 ;
     RECT  30.757 14.208 30.805 34.488 ;
     RECT  29.704 0.72 30.985 10.68 ;
     RECT  29.704 11.76 30.985 12.552 ;
     RECT  30.985 0.72 31.061 12.552 ;
     RECT  29.981 61.056 31.345 79.032 ;
     RECT  30.521 35.472 31.477 57.72 ;
     RECT  29.765 58.8 31.477 59.88 ;
     RECT  31.477 35.472 31.589 59.88 ;
     RECT  31.345 61.056 31.589 79.224 ;
     RECT  31.061 0.72 31.637 12.264 ;
     RECT  30.805 13.632 31.813 34.488 ;
     RECT  31.589 35.472 31.813 79.224 ;
     RECT  31.637 0.72 31.961 0.744 ;
     RECT  31.637 1.872 32.108 12.264 ;
     RECT  31.813 13.632 32.108 79.224 ;
     RECT  32.108 1.872 32.212 79.932 ;
     RECT  32.212 1.872 32.404 79.662 ;
     RECT  32.404 13.632 32.465 29.592 ;
     RECT  32.404 30.576 32.465 43.896 ;
     RECT  32.404 44.928 32.537 58.248 ;
     RECT  32.404 64.128 32.573 79.224 ;
     RECT  32.573 64.128 32.645 78.984 ;
     RECT  32.537 44.928 32.681 57.912 ;
     RECT  32.681 44.976 33.005 57.912 ;
     RECT  32.465 14.448 33.113 29.592 ;
     RECT  33.005 44.976 33.113 57.72 ;
     RECT  32.645 65.664 33.113 78.984 ;
     RECT  33.113 44.976 33.329 52.536 ;
     RECT  32.404 1.872 33.365 12.312 ;
     RECT  32.404 59.472 33.409 59.88 ;
     RECT  32.465 30.576 33.469 34.2 ;
     RECT  32.465 35.424 33.469 43.896 ;
     RECT  33.113 14.448 33.541 21.816 ;
     RECT  33.409 59.472 33.577 59.592 ;
     RECT  33.113 65.664 33.689 66.6 ;
     RECT  32.645 64.128 33.793 64.68 ;
     RECT  33.541 14.256 34.117 21.816 ;
     RECT  33.113 22.8 34.117 29.592 ;
     RECT  34.117 14.256 34.405 29.592 ;
     RECT  33.365 1.872 34.517 12.264 ;
     RECT  33.469 30.576 34.556 43.896 ;
     RECT  33.329 45.12 34.556 52.536 ;
     RECT  33.113 53.856 34.693 57.72 ;
     RECT  33.689 65.76 34.693 66.6 ;
     RECT  33.113 67.584 34.693 78.984 ;
     RECT  34.517 2.148 34.808 12.264 ;
     RECT  34.405 13.632 34.808 29.592 ;
     RECT  34.556 30.576 34.808 52.536 ;
     RECT  34.693 53.808 34.808 57.72 ;
     RECT  33.577 59.184 34.808 59.592 ;
     RECT  32.404 61.152 34.808 62.52 ;
     RECT  33.793 63.552 34.808 64.68 ;
     RECT  34.693 65.76 34.808 78.984 ;
     RECT  34.808 2.148 34.912 79.932 ;
     RECT  34.912 2.352 35.104 79.662 ;
     RECT  35.104 13.056 35.165 59.832 ;
     RECT  35.104 64.176 35.315 78.936 ;
     RECT  35.165 35.28 35.525 59.832 ;
     RECT  35.315 69.792 35.603 78.936 ;
     RECT  35.525 35.28 35.705 59.592 ;
     RECT  35.165 13.056 36.133 34.2 ;
     RECT  35.705 35.28 36.133 52.488 ;
     RECT  35.104 61.584 36.169 62.52 ;
     RECT  35.315 64.176 36.169 68.712 ;
     RECT  35.603 72.288 36.181 78.936 ;
     RECT  35.104 2.352 36.245 10.68 ;
     RECT  36.169 61.584 36.349 68.712 ;
     RECT  35.603 69.792 36.349 71.256 ;
     RECT  36.181 72.288 36.353 79.224 ;
     RECT  36.245 8.208 36.565 10.68 ;
     RECT  35.104 11.76 36.565 11.784 ;
     RECT  35.705 53.472 36.673 59.592 ;
     RECT  36.673 53.472 36.817 59.784 ;
     RECT  36.565 8.208 36.853 11.784 ;
     RECT  36.133 13.056 36.853 52.488 ;
     RECT  36.245 2.352 37.465 7.176 ;
     RECT  36.853 8.208 37.465 52.488 ;
     RECT  37.465 2.352 37.508 52.488 ;
     RECT  36.817 53.472 37.508 60.408 ;
     RECT  36.349 61.584 37.508 71.256 ;
     RECT  36.353 72.384 37.508 79.224 ;
     RECT  37.508 2.148 37.612 79.932 ;
     RECT  37.612 2.418 37.804 79.662 ;
     RECT  37.804 14.736 38.081 52.536 ;
     RECT  38.081 14.736 38.243 35.544 ;
     RECT  38.243 14.736 38.261 18.216 ;
     RECT  37.804 72.288 38.405 79.272 ;
     RECT  38.243 19.248 38.729 35.544 ;
     RECT  37.804 61.68 38.765 68.712 ;
     RECT  38.405 75.216 38.801 79.272 ;
     RECT  37.804 12.912 38.821 13.512 ;
     RECT  38.261 14.736 38.821 18.024 ;
     RECT  38.821 12.912 38.867 18.024 ;
     RECT  37.804 2.544 38.977 7.176 ;
     RECT  37.804 8.544 38.977 11.784 ;
     RECT  38.729 19.248 38.981 24.936 ;
     RECT  38.801 75.744 39.053 79.272 ;
     RECT  37.804 53.616 39.089 60.696 ;
     RECT  38.867 13.44 39.197 18.024 ;
     RECT  38.729 25.968 39.265 35.544 ;
     RECT  38.081 36.528 39.265 52.536 ;
     RECT  38.981 19.248 39.301 19.992 ;
     RECT  39.197 13.584 39.553 18.024 ;
     RECT  39.301 19.104 39.553 19.992 ;
     RECT  38.765 65.712 39.589 68.712 ;
     RECT  39.265 25.968 39.733 52.536 ;
     RECT  39.089 53.616 39.733 57.864 ;
     RECT  38.977 2.544 39.913 11.784 ;
     RECT  39.089 58.944 39.973 60.696 ;
     RECT  38.765 61.68 39.973 64.68 ;
     RECT  38.981 20.976 39.985 24.936 ;
     RECT  39.733 25.968 39.985 57.864 ;
     RECT  37.804 69.792 39.985 71.16 ;
     RECT  38.405 72.288 40.028 74.184 ;
     RECT  39.985 69.792 40.201 71.208 ;
     RECT  40.028 72.288 40.201 74.616 ;
     RECT  39.913 2.496 40.208 11.784 ;
     RECT  39.553 13.584 40.208 19.992 ;
     RECT  39.985 20.976 40.208 57.864 ;
     RECT  39.973 58.944 40.208 64.68 ;
     RECT  39.589 65.712 40.208 68.76 ;
     RECT  40.201 69.792 40.208 74.616 ;
     RECT  39.053 75.744 40.208 78.936 ;
     RECT  40.208 2.148 40.312 79.932 ;
     RECT  40.312 2.352 40.504 79.662 ;
     RECT  40.504 21.12 40.565 45.576 ;
     RECT  40.504 14.208 40.691 19.944 ;
     RECT  40.565 38.4 40.925 45.576 ;
     RECT  40.504 69.792 40.925 78.744 ;
     RECT  40.504 46.848 40.997 59.544 ;
     RECT  40.504 2.352 41.033 11.976 ;
     RECT  40.925 73.776 41.069 78.744 ;
     RECT  41.033 8.496 41.075 11.976 ;
     RECT  40.997 51.408 41.249 59.544 ;
     RECT  40.565 21.12 41.285 37.416 ;
     RECT  41.249 51.408 41.321 58.392 ;
     RECT  40.504 60.816 41.357 62.76 ;
     RECT  40.925 38.4 41.429 45.192 ;
     RECT  41.429 38.448 41.501 45.192 ;
     RECT  40.691 14.736 41.569 19.944 ;
     RECT  41.285 21.12 41.569 35.016 ;
     RECT  40.504 65.712 41.645 68.76 ;
     RECT  41.645 65.808 41.708 68.76 ;
     RECT  40.925 69.792 41.708 72.792 ;
     RECT  41.357 61.632 41.749 62.76 ;
     RECT  40.504 63.792 41.749 64.44 ;
     RECT  41.749 61.632 41.785 64.44 ;
     RECT  41.708 65.808 41.795 72.792 ;
     RECT  41.795 69.792 41.893 72.792 ;
     RECT  41.069 73.776 41.893 73.8 ;
     RECT  41.249 59.472 42.145 59.544 ;
     RECT  41.501 44.976 42.188 45.192 ;
     RECT  40.997 46.848 42.229 50.28 ;
     RECT  41.321 51.408 42.325 52.824 ;
     RECT  41.321 53.856 42.325 58.392 ;
     RECT  42.325 51.408 42.397 58.392 ;
     RECT  42.145 59.472 42.397 59.88 ;
     RECT  41.569 14.736 42.505 35.016 ;
     RECT  41.285 36.528 42.505 37.416 ;
     RECT  42.229 46.752 42.541 50.28 ;
     RECT  41.069 75.168 42.541 78.744 ;
     RECT  42.397 51.408 42.565 59.88 ;
     RECT  41.785 61.632 42.565 64.776 ;
     RECT  41.075 8.496 42.572 10.296 ;
     RECT  41.075 11.472 42.572 11.976 ;
     RECT  42.572 8.496 42.613 11.976 ;
     RECT  42.541 46.752 42.709 50.424 ;
     RECT  42.565 51.408 42.709 64.776 ;
     RECT  41.893 69.792 42.757 73.8 ;
     RECT  42.541 75.168 42.757 79.272 ;
     RECT  42.188 44.976 42.865 45.576 ;
     RECT  41.033 2.352 42.908 7.368 ;
     RECT  42.613 8.496 42.908 12.024 ;
     RECT  42.373 13.008 42.908 13.032 ;
     RECT  42.505 14.736 42.908 37.416 ;
     RECT  41.501 38.448 42.908 43.896 ;
     RECT  42.865 44.976 42.908 45.72 ;
     RECT  42.709 46.752 42.908 64.776 ;
     RECT  41.795 65.808 42.908 68.712 ;
     RECT  42.757 69.792 42.908 79.272 ;
     RECT  42.908 2.148 43.012 79.932 ;
     RECT  43.012 2.352 43.204 79.662 ;
     RECT  43.204 19.584 43.301 19.8 ;
     RECT  43.204 2.352 43.337 9.912 ;
     RECT  43.204 61.392 43.373 64.632 ;
     RECT  43.373 63.216 43.445 64.632 ;
     RECT  43.204 42.528 43.475 44.088 ;
     RECT  43.204 11.76 43.481 12.024 ;
     RECT  43.337 2.352 43.553 3.672 ;
     RECT  43.481 11.76 43.625 11.784 ;
     RECT  43.204 36.048 43.625 41.448 ;
     RECT  43.204 45.696 43.625 45.72 ;
     RECT  43.204 46.848 43.625 50.136 ;
     RECT  43.204 77.04 43.661 78.504 ;
     RECT  43.373 61.392 43.697 62.136 ;
     RECT  43.204 72.144 43.708 72.792 ;
     RECT  43.204 22.704 43.733 34.2 ;
     RECT  43.301 19.776 43.769 19.8 ;
     RECT  43.337 5.28 43.805 9.912 ;
     RECT  43.733 22.704 43.805 25.752 ;
     RECT  43.204 74.592 43.805 75.768 ;
     RECT  43.625 46.848 43.841 50.04 ;
     RECT  43.805 74.592 43.841 75.144 ;
     RECT  43.805 22.704 43.877 23.688 ;
     RECT  43.841 75.072 43.948 75.144 ;
     RECT  43.204 14.736 43.949 18.216 ;
     RECT  43.697 61.68 43.949 62.136 ;
     RECT  43.625 36.384 43.955 41.448 ;
     RECT  43.841 46.848 43.955 49.608 ;
     RECT  43.733 26.832 44.003 34.2 ;
     RECT  43.949 14.736 44.021 15.288 ;
     RECT  43.204 21.12 44.021 21.528 ;
     RECT  43.877 23.328 44.021 23.688 ;
     RECT  44.003 26.832 44.021 28.248 ;
     RECT  43.475 42.528 44.021 43.896 ;
     RECT  43.204 51.408 44.021 57.624 ;
     RECT  43.204 69.792 44.021 71.16 ;
     RECT  43.805 5.712 44.051 9.912 ;
     RECT  43.805 25.008 44.051 25.752 ;
     RECT  44.003 29.232 44.051 29.592 ;
     RECT  44.003 30.576 44.093 34.2 ;
     RECT  43.204 59.04 44.093 59.88 ;
     RECT  43.949 16.56 44.129 18.216 ;
     RECT  44.093 30.576 44.129 33.672 ;
     RECT  44.021 42.768 44.129 43.896 ;
     RECT  43.949 62.112 44.129 62.136 ;
     RECT  44.051 5.712 44.165 6.648 ;
     RECT  43.955 36.576 44.165 41.448 ;
     RECT  43.204 65.952 44.197 68.712 ;
     RECT  44.021 69.792 44.197 70.92 ;
     RECT  43.661 77.568 44.201 78.504 ;
     RECT  43.955 48.672 44.237 49.608 ;
     RECT  44.021 51.408 44.237 54.168 ;
     RECT  44.021 55.536 44.237 57.624 ;
     RECT  43.445 63.264 44.237 64.632 ;
     RECT  44.165 5.712 44.273 6.408 ;
     RECT  44.051 7.968 44.345 9.912 ;
     RECT  44.237 53.856 44.345 54.072 ;
     RECT  44.345 7.968 44.381 9.576 ;
     RECT  44.237 51.408 44.387 52.44 ;
     RECT  44.165 36.624 44.449 41.448 ;
     RECT  44.021 26.832 44.453 27.912 ;
     RECT  44.051 29.568 44.453 29.592 ;
     RECT  44.129 42.816 44.485 43.896 ;
     RECT  44.381 9.504 44.489 9.576 ;
     RECT  44.449 36.624 44.489 41.688 ;
     RECT  44.387 51.408 44.521 52.248 ;
     RECT  44.201 77.952 44.525 78.504 ;
     RECT  44.237 55.536 44.531 56.472 ;
     RECT  44.489 36.624 44.561 39.528 ;
     RECT  43.553 2.496 44.701 3.672 ;
     RECT  44.809 12.48 44.881 12.504 ;
     RECT  44.021 21.12 44.917 21.192 ;
     RECT  44.093 59.04 44.917 59.544 ;
     RECT  44.917 76.368 45.097 76.392 ;
     RECT  44.917 20.4 45.133 21.192 ;
     RECT  44.525 78.048 45.205 78.504 ;
     RECT  44.953 80.064 45.205 80.088 ;
     RECT  44.021 23.664 45.385 23.688 ;
     RECT  44.051 25.008 45.385 25.032 ;
     RECT  44.237 63.264 45.385 64.44 ;
     RECT  44.345 53.904 45.421 54.072 ;
     RECT  45.097 76.368 45.493 76.776 ;
     RECT  45.205 78.048 45.493 80.088 ;
     RECT  44.129 16.656 45.565 18.216 ;
     RECT  45.385 23.664 45.601 25.032 ;
     RECT  44.701 2.496 45.608 4.152 ;
     RECT  44.273 5.712 45.608 6.312 ;
     RECT  44.381 7.968 45.608 8.04 ;
     RECT  44.489 9.504 45.608 9.528 ;
     RECT  45.277 11.136 45.608 11.16 ;
     RECT  44.881 12.48 45.608 13.32 ;
     RECT  44.021 15.024 45.608 15.048 ;
     RECT  45.565 16.272 45.608 18.216 ;
     RECT  45.133 20.4 45.608 21.72 ;
     RECT  45.601 23.616 45.608 25.032 ;
     RECT  44.453 26.832 45.608 27.144 ;
     RECT  45.601 29.568 45.608 29.592 ;
     RECT  44.129 30.768 45.608 33.672 ;
     RECT  45.565 34.896 45.608 34.92 ;
     RECT  44.561 36.624 45.608 38.232 ;
     RECT  44.561 39.504 45.608 39.528 ;
     RECT  44.489 40.608 45.608 41.688 ;
     RECT  44.485 42.816 45.608 44.52 ;
     RECT  43.955 46.848 45.608 47.592 ;
     RECT  44.237 48.672 45.608 49.56 ;
     RECT  44.521 51.36 45.608 52.248 ;
     RECT  45.421 53.568 45.608 54.072 ;
     RECT  44.531 55.536 45.608 56.232 ;
     RECT  44.237 57.6 45.608 57.624 ;
     RECT  44.917 58.704 45.608 59.544 ;
     RECT  45.493 60.72 45.608 60.744 ;
     RECT  45.385 63.072 45.608 64.44 ;
     RECT  44.197 65.952 45.608 70.92 ;
     RECT  43.708 72.48 45.608 72.792 ;
     RECT  43.948 75.12 45.608 75.144 ;
     RECT  45.493 76.368 45.608 80.088 ;
     RECT  45.608 2.148 45.904 80.088 ;
     RECT  45.904 43.008 45.965 44.04 ;
     RECT  45.904 63.072 46.001 63.24 ;
     RECT  45.904 74.832 46.001 80.088 ;
     RECT  45.904 34.896 46.019 34.92 ;
     RECT  45.904 48.672 46.019 51.384 ;
     RECT  46.019 48.672 46.073 50.424 ;
     RECT  45.904 31.488 46.145 33.864 ;
     RECT  45.904 53.28 46.217 53.592 ;
     RECT  45.904 66.24 46.253 73.272 ;
     RECT  45.904 10.944 46.259 11.4 ;
     RECT  45.904 2.148 46.289 9.72 ;
     RECT  45.904 36.432 46.361 37.128 ;
     RECT  46.361 36.816 46.397 37.128 ;
     RECT  45.904 38.208 46.397 38.232 ;
     RECT  46.253 67.68 46.397 73.272 ;
     RECT  46.397 67.68 46.433 70.68 ;
     RECT  45.904 39.504 46.469 41.976 ;
     RECT  46.289 5.088 46.499 9.72 ;
     RECT  46.469 39.504 46.499 40.872 ;
     RECT  46.499 5.088 46.505 6.024 ;
     RECT  46.073 48.672 46.541 49.272 ;
     RECT  46.499 7.392 46.547 9.72 ;
     RECT  46.505 5.088 46.549 5.208 ;
     RECT  45.904 20.592 46.577 25.032 ;
     RECT  45.745 1.152 46.609 1.176 ;
     RECT  46.289 2.148 46.609 3.432 ;
     RECT  46.145 31.488 46.613 33.192 ;
     RECT  46.397 36.816 46.613 37.08 ;
     RECT  46.547 8.496 46.649 9.72 ;
     RECT  45.904 26.352 46.649 26.856 ;
     RECT  46.499 39.504 46.649 39.912 ;
     RECT  45.904 29.472 46.685 29.592 ;
     RECT  46.433 67.776 46.691 70.68 ;
     RECT  46.469 41.952 46.721 41.976 ;
     RECT  46.649 8.496 46.739 8.712 ;
     RECT  46.577 22.752 46.739 25.032 ;
     RECT  46.685 29.472 46.739 29.496 ;
     RECT  46.001 74.832 46.739 78.648 ;
     RECT  45.904 16.176 46.757 18.072 ;
     RECT  45.965 43.872 46.757 44.04 ;
     RECT  45.904 46.8 46.757 47.688 ;
     RECT  46.757 16.272 46.829 18.072 ;
     RECT  46.577 20.592 46.829 21.72 ;
     RECT  45.904 28.464 46.829 28.488 ;
     RECT  45.904 58.368 46.835 58.92 ;
     RECT  46.739 23.952 46.865 25.032 ;
     RECT  45.904 55.536 46.865 55.56 ;
     RECT  46.397 72 46.865 73.272 ;
     RECT  46.073 50.4 46.901 50.424 ;
     RECT  46.691 69.984 46.937 70.68 ;
     RECT  46.739 76.752 46.969 78.648 ;
     RECT  46.609 1.152 47.045 3.432 ;
     RECT  45.904 56.688 47.045 56.76 ;
     RECT  46.865 72 47.045 72.792 ;
     RECT  46.691 67.776 47.117 68.52 ;
     RECT  46.829 20.592 47.125 20.904 ;
     RECT  46.739 8.496 47.153 8.52 ;
     RECT  46.757 46.8 47.153 47.544 ;
     RECT  45.904 12.528 47.18 12.552 ;
     RECT  47.125 20.16 47.212 20.904 ;
     RECT  46.613 31.488 47.261 33 ;
     RECT  47.18 12.528 47.267 13.272 ;
     RECT  47.077 45.6 47.293 45.624 ;
     RECT  47.153 46.8 47.293 47.112 ;
     RECT  46.217 53.28 47.297 53.304 ;
     RECT  46.937 69.984 47.297 70.008 ;
     RECT  47.045 72 47.297 72.024 ;
     RECT  45.904 65.136 47.333 65.16 ;
     RECT  47.293 45.6 47.437 47.112 ;
     RECT  47.257 35.232 47.581 35.256 ;
     RECT  46.829 16.272 47.804 16.536 ;
     RECT  46.829 17.856 47.804 18.072 ;
     RECT  47.804 16.272 47.845 18.072 ;
     RECT  47.045 1.152 48.308 3.384 ;
     RECT  46.549 5.184 48.308 5.208 ;
     RECT  46.547 7.392 48.308 7.416 ;
     RECT  46.649 9.696 48.308 9.72 ;
     RECT  46.259 11.376 48.308 11.4 ;
     RECT  47.267 12.528 48.308 12.552 ;
     RECT  47.845 16.272 48.308 18.264 ;
     RECT  47.212 20.88 48.308 20.904 ;
     RECT  46.739 22.752 48.308 22.776 ;
     RECT  46.649 26.352 48.308 26.376 ;
     RECT  47.261 31.488 48.308 31.704 ;
     RECT  47.261 32.976 48.308 33 ;
     RECT  47.581 34.176 48.308 35.256 ;
     RECT  46.613 36.864 48.308 37.08 ;
     RECT  46.649 39.888 48.308 39.912 ;
     RECT  46.757 43.872 48.308 43.896 ;
     RECT  47.437 45.024 48.308 47.112 ;
     RECT  46.541 49.248 48.308 49.272 ;
     RECT  47.045 56.688 48.308 56.712 ;
     RECT  46.835 58.896 48.308 58.92 ;
     RECT  46.001 63.216 48.308 63.24 ;
     RECT  46.253 66.24 48.308 66.504 ;
     RECT  47.117 68.496 48.308 68.52 ;
     RECT  46.739 74.832 48.308 74.856 ;
     RECT  46.969 76.752 48.308 78.696 ;
     RECT  46.001 80.064 48.308 80.088 ;
     RECT  48.308 1.152 48.604 80.088 ;
     RECT  48.604 1.152 48.989 3.336 ;
     RECT  48.989 1.152 49.201 3.144 ;
     RECT  49.201 0.864 49.205 3.144 ;
     RECT  48.604 79.2 49.237 80.088 ;
     RECT  45.313 81.216 49.237 81.24 ;
     RECT  48.604 8.928 49.597 8.952 ;
     RECT  48.604 18.288 49.597 19.464 ;
     RECT  48.604 27.504 49.597 27.528 ;
     RECT  48.604 37.728 49.597 37.752 ;
     RECT  48.604 52.416 49.597 52.44 ;
     RECT  48.604 57.024 49.597 57.048 ;
     RECT  48.604 64.944 49.597 65.256 ;
     RECT  48.604 66.24 49.597 66.264 ;
     RECT  48.604 67.824 49.597 68.568 ;
     RECT  48.604 70.704 49.597 70.728 ;
     RECT  48.604 72.432 49.597 72.456 ;
     RECT  48.604 74.592 49.597 74.616 ;
     RECT  48.604 76.608 49.597 77.64 ;
     RECT  49.237 79.2 49.597 81.24 ;
     RECT  48.604 13.68 49.633 13.704 ;
     RECT  48.604 55.152 49.633 55.176 ;
     RECT  49.597 56.448 49.633 57.048 ;
     RECT  49.633 13.68 49.669 13.848 ;
     RECT  49.597 32.256 49.669 32.424 ;
     RECT  49.597 24.048 49.705 24.072 ;
     RECT  49.669 42.336 49.705 42.36 ;
     RECT  49.597 76.608 49.705 77.784 ;
     RECT  49.597 78.768 49.705 81.24 ;
     RECT  49.669 13.68 49.741 14.568 ;
     RECT  49.597 18.288 49.741 20.616 ;
     RECT  48.604 34.416 49.741 34.44 ;
     RECT  49.597 39.168 49.741 39.192 ;
     RECT  49.597 40.32 49.741 40.344 ;
     RECT  49.741 13.68 49.777 15.288 ;
     RECT  49.597 16.416 49.777 16.44 ;
     RECT  49.705 23.328 49.777 24.072 ;
     RECT  49.597 25.344 49.777 25.368 ;
     RECT  49.669 32.112 49.777 32.424 ;
     RECT  49.597 37.44 49.777 37.752 ;
     RECT  49.741 39.168 49.777 40.344 ;
     RECT  48.604 47.088 49.777 49.416 ;
     RECT  49.597 64.368 49.777 68.568 ;
     RECT  49.777 23.328 49.813 25.368 ;
     RECT  49.597 26.496 49.813 27.528 ;
     RECT  49.777 39.168 49.813 40.776 ;
     RECT  49.597 52.272 49.813 52.44 ;
     RECT  49.741 6.768 49.849 6.792 ;
     RECT  49.705 76.608 49.849 81.24 ;
     RECT  49.741 17.568 50.101 20.616 ;
     RECT  48.604 21.744 50.101 21.768 ;
     RECT  49.777 47.088 50.101 49.992 ;
     RECT  49.813 51.408 50.101 53.88 ;
     RECT  49.597 70.56 50.101 70.728 ;
     RECT  49.597 72.432 50.101 72.744 ;
     RECT  49.597 73.728 50.101 74.616 ;
     RECT  49.205 0.864 50.137 2.184 ;
     RECT  50.101 4.464 50.137 4.488 ;
     RECT  49.597 8.64 50.137 8.952 ;
     RECT  49.813 10.08 50.137 10.104 ;
     RECT  49.597 11.52 50.137 11.544 ;
     RECT  49.777 13.104 50.137 16.44 ;
     RECT  50.101 17.568 50.137 21.768 ;
     RECT  49.813 23.328 50.137 27.528 ;
     RECT  49.777 29.52 50.137 30.12 ;
     RECT  49.777 32.112 50.137 33.288 ;
     RECT  49.741 34.416 50.137 35.016 ;
     RECT  49.777 36.72 50.137 37.752 ;
     RECT  49.813 39.168 50.137 41.352 ;
     RECT  49.705 42.336 50.137 42.936 ;
     RECT  49.777 44.496 50.137 44.52 ;
     RECT  50.101 47.088 50.137 53.88 ;
     RECT  49.633 55.152 50.137 57.048 ;
     RECT  48.604 58.464 50.137 59.64 ;
     RECT  49.777 64.368 50.137 68.712 ;
     RECT  50.101 70.56 50.137 71.448 ;
     RECT  50.101 72.432 50.137 74.616 ;
     RECT  49.849 76.464 50.137 81.24 ;
     RECT  50.137 4.032 50.173 4.92 ;
     RECT  49.849 5.904 50.173 6.792 ;
     RECT  50.137 8.208 50.173 11.832 ;
     RECT  50.137 12.96 50.173 27.96 ;
     RECT  50.137 29.52 50.173 30.84 ;
     RECT  50.137 32.112 50.173 37.896 ;
     RECT  50.137 39.168 50.173 42.936 ;
     RECT  50.137 44.208 50.173 44.52 ;
     RECT  49.777 45.792 50.173 45.816 ;
     RECT  50.137 46.944 50.173 53.88 ;
     RECT  50.137 54.864 50.173 57.048 ;
     RECT  50.137 0.72 50.641 2.184 ;
     RECT  50.641 0.72 50.677 2.616 ;
     RECT  50.173 3.744 50.677 28.104 ;
     RECT  50.173 29.52 50.677 42.936 ;
     RECT  50.173 44.064 50.677 57.048 ;
     RECT  50.137 58.32 50.677 60.072 ;
     RECT  50.137 63.072 50.677 81.24 ;
     RECT  50.677 58.32 51.685 60.36 ;
     RECT  50.677 0.72 51.721 28.104 ;
     RECT  51.721 0.72 51.756 0.744 ;
     RECT  51.721 0.744 51.804 0.864 ;
     RECT  51.721 0.864 51.756 0.888 ;
     RECT  51.721 0.888 51.804 1.008 ;
     RECT  51.721 1.008 51.756 1.032 ;
     RECT  51.721 1.032 51.804 1.152 ;
     RECT  51.721 1.152 51.756 1.176 ;
     RECT  51.721 1.176 51.804 1.296 ;
     RECT  51.721 1.296 51.756 1.32 ;
     RECT  51.721 1.32 51.804 1.44 ;
     RECT  51.721 1.44 51.756 1.464 ;
     RECT  51.721 1.464 51.804 1.584 ;
     RECT  51.721 1.584 51.756 1.608 ;
     RECT  51.721 1.608 51.804 1.728 ;
     RECT  51.721 1.728 51.756 1.752 ;
     RECT  51.721 1.752 51.804 1.872 ;
     RECT  51.721 1.872 51.756 1.896 ;
     RECT  51.721 1.896 51.804 2.016 ;
     RECT  51.721 2.016 51.756 2.04 ;
     RECT  51.721 2.04 51.804 2.16 ;
     RECT  51.721 2.16 51.756 2.184 ;
     RECT  51.721 2.184 51.804 2.304 ;
     RECT  51.721 2.304 51.756 2.328 ;
     RECT  51.721 2.328 51.804 2.448 ;
     RECT  51.721 2.448 51.756 2.472 ;
     RECT  51.721 2.472 51.804 2.592 ;
     RECT  51.721 2.592 51.756 2.616 ;
     RECT  51.721 2.616 51.804 2.736 ;
     RECT  51.721 2.736 51.756 2.76 ;
     RECT  51.721 2.76 51.804 2.88 ;
     RECT  51.721 2.88 51.756 2.904 ;
     RECT  51.721 2.904 51.804 3.024 ;
     RECT  51.721 3.024 51.756 3.048 ;
     RECT  51.721 3.048 51.804 3.168 ;
     RECT  51.721 3.168 51.756 3.192 ;
     RECT  51.721 3.192 51.804 3.312 ;
     RECT  51.721 3.312 51.756 3.336 ;
     RECT  51.721 3.336 51.804 3.456 ;
     RECT  51.721 3.456 51.756 3.48 ;
     RECT  51.721 3.48 51.804 3.6 ;
     RECT  51.721 3.6 51.756 3.624 ;
     RECT  51.721 3.624 51.804 3.744 ;
     RECT  51.721 3.744 51.756 3.768 ;
     RECT  51.721 3.768 51.804 3.888 ;
     RECT  51.721 3.888 51.756 3.912 ;
     RECT  51.721 3.912 51.804 4.032 ;
     RECT  51.721 4.032 51.756 4.056 ;
     RECT  51.721 4.056 51.804 4.176 ;
     RECT  51.721 4.176 51.756 4.2 ;
     RECT  51.721 4.2 51.804 4.32 ;
     RECT  51.721 4.32 51.756 4.344 ;
     RECT  51.721 4.344 51.804 4.464 ;
     RECT  51.721 4.464 51.756 4.488 ;
     RECT  51.721 4.488 51.804 4.608 ;
     RECT  51.721 4.608 51.756 4.632 ;
     RECT  51.721 4.632 51.804 4.752 ;
     RECT  51.721 4.752 51.756 4.776 ;
     RECT  51.721 4.776 51.804 4.896 ;
     RECT  51.721 4.896 51.756 4.92 ;
     RECT  51.721 4.92 51.804 5.04 ;
     RECT  51.721 5.04 51.756 5.064 ;
     RECT  51.721 5.064 51.804 5.184 ;
     RECT  51.721 5.184 51.756 5.208 ;
     RECT  51.721 5.208 51.804 5.328 ;
     RECT  51.721 5.328 51.756 5.352 ;
     RECT  51.721 5.352 51.804 5.472 ;
     RECT  51.721 5.472 51.756 5.496 ;
     RECT  51.721 5.496 51.804 5.616 ;
     RECT  51.721 5.616 51.756 5.64 ;
     RECT  51.721 5.64 51.804 5.76 ;
     RECT  51.721 5.76 51.756 5.784 ;
     RECT  51.721 5.784 51.804 5.904 ;
     RECT  51.721 5.904 51.756 5.928 ;
     RECT  51.721 5.928 51.804 6.048 ;
     RECT  51.721 6.048 51.756 6.072 ;
     RECT  51.721 6.072 51.804 6.192 ;
     RECT  51.721 6.192 51.756 6.216 ;
     RECT  51.721 6.216 51.804 6.336 ;
     RECT  51.721 6.336 51.756 6.36 ;
     RECT  51.721 6.36 51.804 6.48 ;
     RECT  51.721 6.48 51.756 6.504 ;
     RECT  51.721 6.504 51.804 6.624 ;
     RECT  51.721 6.624 51.756 6.648 ;
     RECT  51.721 6.648 51.804 6.768 ;
     RECT  51.721 6.768 51.756 6.792 ;
     RECT  51.721 6.792 51.804 6.912 ;
     RECT  51.721 6.912 51.756 6.936 ;
     RECT  51.721 6.936 51.804 7.056 ;
     RECT  51.721 7.056 51.756 7.08 ;
     RECT  51.721 7.08 51.804 7.2 ;
     RECT  51.721 7.2 51.756 7.224 ;
     RECT  51.721 7.224 51.804 7.344 ;
     RECT  51.721 7.344 51.756 7.368 ;
     RECT  51.721 7.368 51.804 7.488 ;
     RECT  51.721 7.488 51.756 7.512 ;
     RECT  51.721 7.512 51.804 7.632 ;
     RECT  51.721 7.632 51.756 7.656 ;
     RECT  51.721 7.656 51.804 7.776 ;
     RECT  51.721 7.776 51.756 7.8 ;
     RECT  51.721 7.8 51.804 7.92 ;
     RECT  51.721 7.92 51.756 7.944 ;
     RECT  51.721 7.944 51.804 8.064 ;
     RECT  51.721 8.064 51.756 8.088 ;
     RECT  51.721 8.088 51.804 8.208 ;
     RECT  51.721 8.208 51.756 8.232 ;
     RECT  51.721 8.232 51.804 8.352 ;
     RECT  51.721 8.352 51.756 8.376 ;
     RECT  51.721 8.376 51.804 8.496 ;
     RECT  51.721 8.496 51.756 8.52 ;
     RECT  51.721 8.52 51.804 8.64 ;
     RECT  51.721 8.64 51.756 8.664 ;
     RECT  51.721 8.664 51.804 8.784 ;
     RECT  51.721 8.784 51.756 8.808 ;
     RECT  51.721 8.808 51.804 8.928 ;
     RECT  51.721 8.928 51.756 8.952 ;
     RECT  51.721 8.952 51.804 9.072 ;
     RECT  51.721 9.072 51.756 9.096 ;
     RECT  51.721 9.096 51.804 9.216 ;
     RECT  51.721 9.216 51.756 9.24 ;
     RECT  51.721 9.24 51.804 9.36 ;
     RECT  51.721 9.36 51.756 9.384 ;
     RECT  51.721 9.384 51.804 9.504 ;
     RECT  51.721 9.504 51.756 9.528 ;
     RECT  51.721 9.528 51.804 9.648 ;
     RECT  51.721 9.648 51.756 9.672 ;
     RECT  51.721 9.672 51.804 9.792 ;
     RECT  51.721 9.792 51.756 9.816 ;
     RECT  51.721 9.816 51.804 9.936 ;
     RECT  51.721 9.936 51.756 9.96 ;
     RECT  51.721 9.96 51.804 10.08 ;
     RECT  51.721 10.08 51.756 10.104 ;
     RECT  51.721 10.104 51.804 10.224 ;
     RECT  51.721 10.224 51.756 10.248 ;
     RECT  51.721 10.248 51.804 10.368 ;
     RECT  51.721 10.368 51.756 10.392 ;
     RECT  51.721 10.392 51.804 10.512 ;
     RECT  51.721 10.512 51.756 10.536 ;
     RECT  51.721 10.536 51.804 10.656 ;
     RECT  51.721 10.656 51.756 10.68 ;
     RECT  51.721 10.68 51.804 10.8 ;
     RECT  51.721 10.8 51.756 10.824 ;
     RECT  51.721 10.824 51.804 10.944 ;
     RECT  51.721 10.944 51.756 10.968 ;
     RECT  51.721 10.968 51.804 11.088 ;
     RECT  51.721 11.088 51.756 11.112 ;
     RECT  51.721 11.112 51.804 11.232 ;
     RECT  51.721 11.232 51.756 11.256 ;
     RECT  51.721 11.256 51.804 11.376 ;
     RECT  51.721 11.376 51.756 11.4 ;
     RECT  51.721 11.4 51.804 11.52 ;
     RECT  51.721 11.52 51.756 11.544 ;
     RECT  51.721 11.544 51.804 11.664 ;
     RECT  51.721 11.664 51.756 11.688 ;
     RECT  51.721 11.688 51.804 11.808 ;
     RECT  51.721 11.808 51.756 11.832 ;
     RECT  51.721 11.832 51.804 11.952 ;
     RECT  51.721 11.952 51.756 11.976 ;
     RECT  51.721 11.976 51.804 12.096 ;
     RECT  51.721 12.096 51.756 12.12 ;
     RECT  51.721 12.12 51.804 12.24 ;
     RECT  51.721 12.24 51.756 12.264 ;
     RECT  51.721 12.264 51.804 12.384 ;
     RECT  51.721 12.384 51.756 12.408 ;
     RECT  51.721 12.408 51.804 12.528 ;
     RECT  51.721 12.528 51.756 12.552 ;
     RECT  51.721 12.552 51.804 12.672 ;
     RECT  51.721 12.672 51.756 12.696 ;
     RECT  51.721 12.696 51.804 12.816 ;
     RECT  51.721 12.816 51.756 12.84 ;
     RECT  51.721 12.84 51.804 12.96 ;
     RECT  51.721 12.96 51.756 12.984 ;
     RECT  51.721 12.984 51.804 13.104 ;
     RECT  51.721 13.104 51.756 13.128 ;
     RECT  51.721 13.128 51.804 13.248 ;
     RECT  51.721 13.248 51.756 13.272 ;
     RECT  51.721 13.272 51.804 13.392 ;
     RECT  51.721 13.392 51.756 13.416 ;
     RECT  51.721 13.416 51.804 13.536 ;
     RECT  51.721 13.536 51.756 13.56 ;
     RECT  51.721 13.56 51.804 13.68 ;
     RECT  51.721 13.68 51.756 13.704 ;
     RECT  51.721 13.704 51.804 13.824 ;
     RECT  51.721 13.824 51.756 13.848 ;
     RECT  51.721 13.848 51.804 13.968 ;
     RECT  51.721 13.968 51.756 13.992 ;
     RECT  51.721 13.992 51.804 14.112 ;
     RECT  51.721 14.112 51.756 14.136 ;
     RECT  51.721 14.136 51.804 14.256 ;
     RECT  51.721 14.256 51.756 14.28 ;
     RECT  51.721 14.28 51.804 14.4 ;
     RECT  51.721 14.4 51.756 14.424 ;
     RECT  51.721 14.424 51.804 14.544 ;
     RECT  51.721 14.544 51.756 14.568 ;
     RECT  51.721 14.568 51.804 14.688 ;
     RECT  51.721 14.688 51.756 14.712 ;
     RECT  51.721 14.712 51.804 14.832 ;
     RECT  51.721 14.832 51.756 14.856 ;
     RECT  51.721 14.856 51.804 14.976 ;
     RECT  51.721 14.976 51.756 15 ;
     RECT  51.721 15 51.804 15.12 ;
     RECT  51.721 15.12 51.756 15.144 ;
     RECT  51.721 15.144 51.804 15.264 ;
     RECT  51.721 15.264 51.756 15.288 ;
     RECT  51.721 15.288 51.804 15.408 ;
     RECT  51.721 15.408 51.756 15.432 ;
     RECT  51.721 15.432 51.804 15.552 ;
     RECT  51.721 15.552 51.756 15.576 ;
     RECT  51.721 15.576 51.804 15.696 ;
     RECT  51.721 15.696 51.756 15.72 ;
     RECT  51.721 15.72 51.804 15.84 ;
     RECT  51.721 15.84 51.756 15.864 ;
     RECT  51.721 15.864 51.804 15.984 ;
     RECT  51.721 15.984 51.756 16.008 ;
     RECT  51.721 16.008 51.804 16.128 ;
     RECT  51.721 16.128 51.756 16.152 ;
     RECT  51.721 16.152 51.804 16.272 ;
     RECT  51.721 16.272 51.756 16.296 ;
     RECT  51.721 16.296 51.804 16.416 ;
     RECT  51.721 16.416 51.756 16.44 ;
     RECT  51.721 16.44 51.804 16.56 ;
     RECT  51.721 16.56 51.756 16.584 ;
     RECT  51.721 16.584 51.804 16.704 ;
     RECT  51.721 16.704 51.756 16.728 ;
     RECT  51.721 16.728 51.804 16.848 ;
     RECT  51.721 16.848 51.756 16.872 ;
     RECT  51.721 16.872 51.804 16.992 ;
     RECT  51.721 16.992 51.756 17.016 ;
     RECT  51.721 17.016 51.804 17.136 ;
     RECT  51.721 17.136 51.756 17.16 ;
     RECT  51.721 17.16 51.804 17.28 ;
     RECT  51.721 17.28 51.756 17.304 ;
     RECT  51.721 17.304 51.804 17.424 ;
     RECT  51.721 17.424 51.756 17.448 ;
     RECT  51.721 17.448 51.804 17.568 ;
     RECT  51.721 17.568 51.756 17.592 ;
     RECT  51.721 17.592 51.804 17.712 ;
     RECT  51.721 17.712 51.756 17.736 ;
     RECT  51.721 17.736 51.804 17.856 ;
     RECT  51.721 17.856 51.756 17.88 ;
     RECT  51.721 17.88 51.804 18 ;
     RECT  51.721 18 51.756 18.024 ;
     RECT  51.721 18.024 51.804 18.144 ;
     RECT  51.721 18.144 51.756 18.168 ;
     RECT  51.721 18.168 51.804 18.288 ;
     RECT  51.721 18.288 51.756 18.312 ;
     RECT  51.721 18.312 51.804 18.432 ;
     RECT  51.721 18.432 51.756 18.456 ;
     RECT  51.721 18.456 51.804 18.576 ;
     RECT  51.721 18.576 51.756 18.6 ;
     RECT  51.721 18.6 51.804 18.72 ;
     RECT  51.721 18.72 51.756 18.744 ;
     RECT  51.721 18.744 51.804 18.864 ;
     RECT  51.721 18.864 51.756 18.888 ;
     RECT  51.721 18.888 51.804 19.008 ;
     RECT  51.721 19.008 51.756 19.032 ;
     RECT  51.721 19.032 51.804 19.152 ;
     RECT  51.721 19.152 51.756 19.176 ;
     RECT  51.721 19.176 51.804 19.296 ;
     RECT  51.721 19.296 51.756 19.32 ;
     RECT  51.721 19.32 51.804 19.44 ;
     RECT  51.721 19.44 51.756 19.464 ;
     RECT  51.721 19.464 51.804 19.584 ;
     RECT  51.721 19.584 51.756 19.608 ;
     RECT  51.721 19.608 51.804 19.728 ;
     RECT  51.721 19.728 51.756 19.752 ;
     RECT  51.721 19.752 51.804 19.872 ;
     RECT  51.721 19.872 51.756 19.896 ;
     RECT  51.721 19.896 51.804 20.016 ;
     RECT  51.721 20.016 51.756 20.04 ;
     RECT  51.721 20.04 51.804 20.16 ;
     RECT  51.721 20.16 51.756 20.184 ;
     RECT  51.721 20.184 51.804 20.304 ;
     RECT  51.721 20.304 51.756 20.328 ;
     RECT  51.721 20.328 51.804 20.448 ;
     RECT  51.721 20.448 51.756 20.472 ;
     RECT  51.721 20.472 51.804 20.592 ;
     RECT  51.721 20.592 51.756 20.616 ;
     RECT  51.721 20.616 51.804 20.736 ;
     RECT  51.721 20.736 51.756 20.76 ;
     RECT  51.721 20.76 51.804 20.88 ;
     RECT  51.721 20.88 51.756 20.904 ;
     RECT  51.721 20.904 51.804 21.024 ;
     RECT  51.721 21.024 51.756 21.048 ;
     RECT  51.721 21.048 51.804 21.168 ;
     RECT  51.721 21.168 51.756 21.192 ;
     RECT  51.721 21.192 51.804 21.312 ;
     RECT  51.721 21.312 51.756 21.336 ;
     RECT  51.721 21.336 51.804 21.456 ;
     RECT  51.721 21.456 51.756 21.48 ;
     RECT  51.721 21.48 51.804 21.6 ;
     RECT  51.721 21.6 51.756 21.624 ;
     RECT  51.721 21.624 51.804 21.744 ;
     RECT  51.721 21.744 51.756 21.768 ;
     RECT  51.721 21.768 51.804 21.888 ;
     RECT  51.721 21.888 51.756 21.912 ;
     RECT  51.721 21.912 51.804 22.032 ;
     RECT  51.721 22.032 51.756 22.056 ;
     RECT  51.721 22.056 51.804 22.176 ;
     RECT  51.721 22.176 51.756 22.2 ;
     RECT  51.721 22.2 51.804 22.32 ;
     RECT  51.721 22.32 51.756 22.344 ;
     RECT  51.721 22.344 51.804 22.464 ;
     RECT  51.721 22.464 51.756 22.488 ;
     RECT  51.721 22.488 51.804 22.608 ;
     RECT  51.721 22.608 51.756 22.632 ;
     RECT  51.721 22.632 51.804 22.752 ;
     RECT  51.721 22.752 51.756 22.776 ;
     RECT  51.721 22.776 51.804 22.896 ;
     RECT  51.721 22.896 51.756 22.92 ;
     RECT  51.721 22.92 51.804 23.04 ;
     RECT  51.721 23.04 51.756 23.064 ;
     RECT  51.721 23.064 51.804 23.184 ;
     RECT  51.721 23.184 51.756 23.208 ;
     RECT  51.721 23.208 51.804 23.328 ;
     RECT  51.721 23.328 51.756 23.352 ;
     RECT  51.721 23.352 51.804 23.472 ;
     RECT  51.721 23.472 51.756 23.496 ;
     RECT  51.721 23.496 51.804 23.616 ;
     RECT  51.721 23.616 51.756 23.64 ;
     RECT  51.721 23.64 51.804 23.76 ;
     RECT  51.721 23.76 51.756 23.784 ;
     RECT  51.721 23.784 51.804 23.904 ;
     RECT  51.721 23.904 51.756 23.928 ;
     RECT  51.721 23.928 51.804 24.048 ;
     RECT  51.721 24.048 51.756 24.072 ;
     RECT  51.721 24.072 51.804 24.192 ;
     RECT  51.721 24.192 51.756 24.216 ;
     RECT  51.721 24.216 51.804 24.336 ;
     RECT  51.721 24.336 51.756 24.36 ;
     RECT  51.721 24.36 51.804 24.48 ;
     RECT  51.721 24.48 51.756 24.504 ;
     RECT  51.721 24.504 51.804 24.624 ;
     RECT  51.721 24.624 51.756 24.648 ;
     RECT  51.721 24.648 51.804 24.768 ;
     RECT  51.721 24.768 51.756 24.792 ;
     RECT  51.721 24.792 51.804 24.912 ;
     RECT  51.721 24.912 51.756 24.936 ;
     RECT  51.721 24.936 51.804 25.056 ;
     RECT  51.721 25.056 51.756 25.08 ;
     RECT  51.721 25.08 51.804 25.2 ;
     RECT  51.721 25.2 51.756 25.224 ;
     RECT  51.721 25.224 51.804 25.344 ;
     RECT  51.721 25.344 51.756 25.368 ;
     RECT  51.721 25.368 51.804 25.488 ;
     RECT  51.721 25.488 51.756 25.512 ;
     RECT  51.721 25.512 51.804 25.632 ;
     RECT  51.721 25.632 51.756 25.656 ;
     RECT  51.721 25.656 51.804 25.776 ;
     RECT  51.721 25.776 51.756 25.8 ;
     RECT  51.721 25.8 51.804 25.92 ;
     RECT  51.721 25.92 51.756 25.944 ;
     RECT  51.721 25.944 51.804 26.064 ;
     RECT  51.721 26.064 51.756 26.088 ;
     RECT  51.721 26.088 51.804 26.208 ;
     RECT  51.721 26.208 51.756 26.232 ;
     RECT  51.721 26.232 51.804 26.352 ;
     RECT  51.721 26.352 51.756 26.376 ;
     RECT  51.721 26.376 51.804 26.496 ;
     RECT  51.721 26.496 51.756 26.52 ;
     RECT  51.721 26.52 51.804 26.64 ;
     RECT  51.721 26.64 51.756 26.664 ;
     RECT  51.721 26.664 51.804 26.784 ;
     RECT  51.721 26.784 51.756 26.808 ;
     RECT  51.721 26.808 51.804 26.928 ;
     RECT  51.721 26.928 51.756 26.952 ;
     RECT  51.721 26.952 51.804 27.072 ;
     RECT  51.721 27.072 51.756 27.096 ;
     RECT  51.721 27.096 51.804 27.216 ;
     RECT  51.721 27.216 51.756 27.24 ;
     RECT  51.721 27.24 51.804 27.36 ;
     RECT  51.721 27.36 51.756 27.384 ;
     RECT  51.721 27.384 51.804 27.504 ;
     RECT  51.721 27.504 51.756 27.528 ;
     RECT  51.721 27.528 51.804 27.648 ;
     RECT  51.721 27.648 51.756 27.672 ;
     RECT  51.721 27.672 51.804 27.792 ;
     RECT  51.721 27.792 51.756 27.816 ;
     RECT  51.721 27.816 51.804 27.936 ;
     RECT  51.721 27.936 51.756 27.96 ;
     RECT  51.721 27.96 51.804 28.08 ;
     RECT  51.721 28.08 51.756 28.104 ;
     RECT  51.721 28.104 51.804 28.224 ;
     RECT  51.721 28.224 51.756 28.248 ;
     RECT  50.677 29.52 51.756 29.544 ;
     RECT  50.677 29.544 51.804 29.664 ;
     RECT  50.677 29.664 51.756 29.688 ;
     RECT  50.677 29.688 51.804 29.808 ;
     RECT  50.677 29.808 51.756 29.832 ;
     RECT  50.677 29.832 51.804 29.952 ;
     RECT  50.677 29.952 51.756 29.976 ;
     RECT  50.677 29.976 51.804 30.096 ;
     RECT  50.677 30.096 51.756 30.12 ;
     RECT  50.677 30.12 51.804 30.24 ;
     RECT  50.677 30.24 51.756 30.264 ;
     RECT  50.677 30.264 51.804 30.384 ;
     RECT  50.677 30.384 51.756 30.408 ;
     RECT  50.677 30.408 51.804 30.528 ;
     RECT  50.677 30.528 51.756 30.552 ;
     RECT  50.677 30.552 51.804 30.672 ;
     RECT  50.677 30.672 51.756 30.696 ;
     RECT  50.677 30.696 51.804 30.816 ;
     RECT  50.677 30.816 51.756 30.84 ;
     RECT  50.677 30.84 51.804 30.96 ;
     RECT  50.677 30.96 51.756 30.984 ;
     RECT  50.677 30.984 51.804 31.104 ;
     RECT  50.677 31.104 51.756 31.128 ;
     RECT  50.677 31.128 51.804 31.248 ;
     RECT  50.677 31.248 51.756 31.272 ;
     RECT  50.677 31.272 51.804 31.392 ;
     RECT  50.677 31.392 51.756 31.416 ;
     RECT  50.677 31.416 51.804 31.536 ;
     RECT  50.677 31.536 51.756 31.56 ;
     RECT  50.677 31.56 51.804 31.68 ;
     RECT  50.677 31.68 51.756 31.704 ;
     RECT  50.677 31.704 51.804 31.824 ;
     RECT  50.677 31.824 51.756 31.848 ;
     RECT  50.677 31.848 51.804 31.968 ;
     RECT  50.677 31.968 51.756 31.992 ;
     RECT  50.677 31.992 51.804 32.112 ;
     RECT  50.677 32.112 51.756 32.136 ;
     RECT  50.677 32.136 51.804 32.256 ;
     RECT  50.677 32.256 51.756 32.28 ;
     RECT  50.677 32.28 51.804 32.4 ;
     RECT  50.677 32.4 51.756 32.424 ;
     RECT  50.677 32.424 51.804 32.544 ;
     RECT  50.677 32.544 51.756 32.568 ;
     RECT  50.677 32.568 51.804 32.688 ;
     RECT  50.677 32.688 51.756 32.712 ;
     RECT  50.677 32.712 51.804 32.832 ;
     RECT  50.677 32.832 51.756 32.856 ;
     RECT  50.677 32.856 51.804 32.976 ;
     RECT  50.677 32.976 51.756 33 ;
     RECT  50.677 33 51.804 33.12 ;
     RECT  50.677 33.12 51.756 33.144 ;
     RECT  50.677 33.144 51.804 33.264 ;
     RECT  50.677 33.264 51.756 33.288 ;
     RECT  50.677 33.288 51.804 33.408 ;
     RECT  50.677 33.408 51.756 33.432 ;
     RECT  50.677 33.432 51.804 33.552 ;
     RECT  50.677 33.552 51.756 33.576 ;
     RECT  50.677 33.576 51.804 33.696 ;
     RECT  50.677 33.696 51.756 33.72 ;
     RECT  50.677 33.72 51.804 33.84 ;
     RECT  50.677 33.84 51.756 33.864 ;
     RECT  50.677 33.864 51.804 33.984 ;
     RECT  50.677 33.984 51.756 34.008 ;
     RECT  50.677 34.008 51.804 34.128 ;
     RECT  50.677 34.128 51.756 34.152 ;
     RECT  50.677 34.152 51.804 34.272 ;
     RECT  50.677 34.272 51.756 34.296 ;
     RECT  50.677 34.296 51.804 34.416 ;
     RECT  50.677 34.416 51.756 34.44 ;
     RECT  50.677 34.44 51.804 34.56 ;
     RECT  50.677 34.56 51.756 34.584 ;
     RECT  50.677 34.584 51.804 34.704 ;
     RECT  50.677 34.704 51.756 34.728 ;
     RECT  50.677 34.728 51.804 34.848 ;
     RECT  50.677 34.848 51.756 34.872 ;
     RECT  50.677 34.872 51.804 34.992 ;
     RECT  50.677 34.992 51.756 35.016 ;
     RECT  50.677 35.016 51.804 35.136 ;
     RECT  50.677 35.136 51.756 35.16 ;
     RECT  50.677 35.16 51.804 35.28 ;
     RECT  50.677 35.28 51.756 35.304 ;
     RECT  50.677 35.304 51.804 35.424 ;
     RECT  50.677 35.424 51.756 35.448 ;
     RECT  50.677 35.448 51.804 35.568 ;
     RECT  50.677 35.568 51.756 35.592 ;
     RECT  50.677 35.592 51.804 35.712 ;
     RECT  50.677 35.712 51.756 35.736 ;
     RECT  50.677 35.736 51.804 35.856 ;
     RECT  50.677 35.856 51.756 35.88 ;
     RECT  50.677 35.88 51.804 36 ;
     RECT  50.677 36 51.756 36.024 ;
     RECT  50.677 36.024 51.804 36.144 ;
     RECT  50.677 36.144 51.756 36.168 ;
     RECT  50.677 36.168 51.804 36.288 ;
     RECT  50.677 36.288 51.756 36.312 ;
     RECT  50.677 36.312 51.804 36.432 ;
     RECT  50.677 36.432 51.756 36.456 ;
     RECT  50.677 36.456 51.804 36.576 ;
     RECT  50.677 36.576 51.756 36.6 ;
     RECT  50.677 36.6 51.804 36.72 ;
     RECT  50.677 36.72 51.756 36.744 ;
     RECT  50.677 36.744 51.804 36.864 ;
     RECT  50.677 36.864 51.756 36.888 ;
     RECT  50.677 36.888 51.804 37.008 ;
     RECT  50.677 37.008 51.756 37.032 ;
     RECT  50.677 37.032 51.804 37.152 ;
     RECT  50.677 37.152 51.756 37.176 ;
     RECT  50.677 37.176 51.804 37.296 ;
     RECT  50.677 37.296 51.756 37.32 ;
     RECT  50.677 37.32 51.804 37.44 ;
     RECT  50.677 37.44 51.756 37.464 ;
     RECT  50.677 37.464 51.804 37.584 ;
     RECT  50.677 37.584 51.756 37.608 ;
     RECT  50.677 37.608 51.804 37.728 ;
     RECT  50.677 37.728 51.756 37.752 ;
     RECT  50.677 37.752 51.804 37.872 ;
     RECT  50.677 37.872 51.756 37.896 ;
     RECT  50.677 37.896 51.804 38.016 ;
     RECT  50.677 38.016 51.756 38.04 ;
     RECT  50.677 38.04 51.804 38.16 ;
     RECT  50.677 38.16 51.756 38.184 ;
     RECT  50.677 38.184 51.804 38.304 ;
     RECT  50.677 38.304 51.756 38.328 ;
     RECT  50.677 38.328 51.804 38.448 ;
     RECT  50.677 38.448 51.756 38.472 ;
     RECT  50.677 38.472 51.804 38.592 ;
     RECT  50.677 38.592 51.756 38.616 ;
     RECT  50.677 38.616 51.804 38.736 ;
     RECT  50.677 38.736 51.756 38.76 ;
     RECT  50.677 38.76 51.804 38.88 ;
     RECT  50.677 38.88 51.756 38.904 ;
     RECT  50.677 38.904 51.804 39.024 ;
     RECT  50.677 39.024 51.756 39.048 ;
     RECT  50.677 39.048 51.804 39.168 ;
     RECT  50.677 39.168 51.756 39.192 ;
     RECT  50.677 39.192 51.804 39.312 ;
     RECT  50.677 39.312 51.756 39.336 ;
     RECT  50.677 39.336 51.804 39.456 ;
     RECT  50.677 39.456 51.756 39.48 ;
     RECT  50.677 39.48 51.804 39.6 ;
     RECT  50.677 39.6 51.756 39.624 ;
     RECT  50.677 39.624 51.804 39.744 ;
     RECT  50.677 39.744 51.756 39.768 ;
     RECT  50.677 39.768 51.804 39.888 ;
     RECT  50.677 39.888 51.756 39.912 ;
     RECT  50.677 39.912 51.804 40.032 ;
     RECT  50.677 40.032 51.756 40.056 ;
     RECT  50.677 40.056 51.804 40.176 ;
     RECT  50.677 40.176 51.756 40.2 ;
     RECT  50.677 40.2 51.804 40.32 ;
     RECT  50.677 40.32 51.756 40.344 ;
     RECT  50.677 40.344 51.804 40.464 ;
     RECT  50.677 40.464 51.756 40.488 ;
     RECT  50.677 40.488 51.804 40.608 ;
     RECT  50.677 40.608 51.756 40.632 ;
     RECT  50.677 40.632 51.804 40.752 ;
     RECT  50.677 40.752 51.756 40.776 ;
     RECT  50.677 40.776 51.804 40.896 ;
     RECT  50.677 40.896 51.756 40.92 ;
     RECT  50.677 40.92 51.804 41.04 ;
     RECT  50.677 41.04 51.756 41.064 ;
     RECT  50.677 41.064 51.804 41.184 ;
     RECT  50.677 41.184 51.756 41.208 ;
     RECT  50.677 41.208 51.804 41.328 ;
     RECT  50.677 41.328 51.756 41.352 ;
     RECT  50.677 41.352 51.804 41.472 ;
     RECT  50.677 41.472 51.756 41.496 ;
     RECT  50.677 41.496 51.804 41.616 ;
     RECT  50.677 41.616 51.756 41.64 ;
     RECT  50.677 41.64 51.804 41.76 ;
     RECT  50.677 41.76 51.756 41.784 ;
     RECT  50.677 41.784 51.804 41.904 ;
     RECT  50.677 41.904 51.756 41.928 ;
     RECT  50.677 41.928 51.804 42.048 ;
     RECT  50.677 42.048 51.756 42.072 ;
     RECT  50.677 42.072 51.804 42.192 ;
     RECT  50.677 42.192 51.756 42.216 ;
     RECT  50.677 42.216 51.804 42.336 ;
     RECT  50.677 42.336 51.756 42.36 ;
     RECT  50.677 42.36 51.804 42.48 ;
     RECT  50.677 42.48 51.756 42.504 ;
     RECT  50.677 42.504 51.804 42.624 ;
     RECT  50.677 42.624 51.756 42.648 ;
     RECT  50.677 42.648 51.804 42.768 ;
     RECT  50.677 42.768 51.756 42.792 ;
     RECT  50.677 42.792 51.804 42.912 ;
     RECT  50.677 42.912 51.756 42.936 ;
     RECT  50.677 42.936 51.804 43.056 ;
     RECT  50.677 43.056 51.756 43.08 ;
     RECT  50.677 43.08 51.804 43.2 ;
     RECT  50.677 43.2 51.756 43.224 ;
     RECT  50.677 43.224 51.804 43.344 ;
     RECT  50.677 43.344 51.756 43.368 ;
     RECT  50.677 43.368 51.804 43.488 ;
     RECT  50.677 43.488 51.756 43.512 ;
     RECT  50.677 43.512 51.804 43.632 ;
     RECT  50.677 43.632 51.756 43.656 ;
     RECT  50.677 43.656 51.804 43.776 ;
     RECT  50.677 43.776 51.756 43.8 ;
     RECT  50.677 43.8 51.804 43.92 ;
     RECT  50.677 43.92 51.756 43.944 ;
     RECT  50.677 43.944 51.804 44.064 ;
     RECT  50.677 44.064 51.756 44.088 ;
     RECT  50.677 44.088 51.804 44.208 ;
     RECT  50.677 44.208 51.756 44.232 ;
     RECT  50.677 44.232 51.804 44.352 ;
     RECT  50.677 44.352 51.756 44.376 ;
     RECT  50.677 44.376 51.804 44.496 ;
     RECT  50.677 44.496 51.756 44.52 ;
     RECT  50.677 44.52 51.804 44.64 ;
     RECT  50.677 44.64 51.756 44.664 ;
     RECT  50.677 44.664 51.804 44.784 ;
     RECT  50.677 44.784 51.756 44.808 ;
     RECT  50.677 44.808 51.804 44.928 ;
     RECT  50.677 44.928 51.756 44.952 ;
     RECT  50.677 44.952 51.804 45.072 ;
     RECT  50.677 45.072 51.756 45.096 ;
     RECT  50.677 45.096 51.804 45.216 ;
     RECT  50.677 45.216 51.756 45.24 ;
     RECT  50.677 45.24 51.804 45.36 ;
     RECT  50.677 45.36 51.756 45.384 ;
     RECT  50.677 45.384 51.804 45.504 ;
     RECT  50.677 45.504 51.756 45.528 ;
     RECT  50.677 45.528 51.804 45.648 ;
     RECT  50.677 45.648 51.756 45.672 ;
     RECT  50.677 45.672 51.804 45.792 ;
     RECT  50.677 45.792 51.756 45.816 ;
     RECT  50.677 45.816 51.804 45.936 ;
     RECT  50.677 45.936 51.756 45.96 ;
     RECT  50.677 45.96 51.804 46.08 ;
     RECT  50.677 46.08 51.756 46.104 ;
     RECT  50.677 46.104 51.804 46.224 ;
     RECT  50.677 46.224 51.756 46.248 ;
     RECT  50.677 46.248 51.804 46.368 ;
     RECT  50.677 46.368 51.756 46.392 ;
     RECT  50.677 46.392 51.804 46.512 ;
     RECT  50.677 46.512 51.756 46.536 ;
     RECT  50.677 46.536 51.804 46.656 ;
     RECT  50.677 46.656 51.756 46.68 ;
     RECT  50.677 46.68 51.804 46.8 ;
     RECT  50.677 46.8 51.756 46.824 ;
     RECT  50.677 46.824 51.804 46.944 ;
     RECT  50.677 46.944 51.756 46.968 ;
     RECT  50.677 46.968 51.804 47.088 ;
     RECT  50.677 47.088 51.756 47.112 ;
     RECT  50.677 47.112 51.804 47.232 ;
     RECT  50.677 47.232 51.756 47.256 ;
     RECT  50.677 47.256 51.804 47.376 ;
     RECT  50.677 47.376 51.756 47.4 ;
     RECT  50.677 47.4 51.804 47.52 ;
     RECT  50.677 47.52 51.756 47.544 ;
     RECT  50.677 47.544 51.804 47.664 ;
     RECT  50.677 47.664 51.756 47.688 ;
     RECT  50.677 47.688 51.804 47.808 ;
     RECT  50.677 47.808 51.756 47.832 ;
     RECT  50.677 47.832 51.804 47.952 ;
     RECT  50.677 47.952 51.756 47.976 ;
     RECT  50.677 47.976 51.804 48.096 ;
     RECT  50.677 48.096 51.756 48.12 ;
     RECT  50.677 48.12 51.804 48.24 ;
     RECT  50.677 48.24 51.756 48.264 ;
     RECT  50.677 48.264 51.804 48.384 ;
     RECT  50.677 48.384 51.756 48.408 ;
     RECT  50.677 48.408 51.804 48.528 ;
     RECT  50.677 48.528 51.756 48.552 ;
     RECT  50.677 48.552 51.804 48.672 ;
     RECT  50.677 48.672 51.756 48.696 ;
     RECT  50.677 48.696 51.804 48.816 ;
     RECT  50.677 48.816 51.756 48.84 ;
     RECT  50.677 48.84 51.804 48.96 ;
     RECT  50.677 48.96 51.756 48.984 ;
     RECT  50.677 48.984 51.804 49.104 ;
     RECT  50.677 49.104 51.756 49.128 ;
     RECT  50.677 49.128 51.804 49.248 ;
     RECT  50.677 49.248 51.756 49.272 ;
     RECT  50.677 49.272 51.804 49.392 ;
     RECT  50.677 49.392 51.756 49.416 ;
     RECT  50.677 49.416 51.804 49.536 ;
     RECT  50.677 49.536 51.756 49.56 ;
     RECT  50.677 49.56 51.804 49.68 ;
     RECT  50.677 49.68 51.756 49.704 ;
     RECT  50.677 49.704 51.804 49.824 ;
     RECT  50.677 49.824 51.756 49.848 ;
     RECT  50.677 49.848 51.804 49.968 ;
     RECT  50.677 49.968 51.756 49.992 ;
     RECT  50.677 49.992 51.804 50.112 ;
     RECT  50.677 50.112 51.756 50.136 ;
     RECT  50.677 50.136 51.804 50.256 ;
     RECT  50.677 50.256 51.756 50.28 ;
     RECT  50.677 50.28 51.804 50.4 ;
     RECT  50.677 50.4 51.756 50.424 ;
     RECT  50.677 50.424 51.804 50.544 ;
     RECT  50.677 50.544 51.756 50.568 ;
     RECT  50.677 50.568 51.804 50.688 ;
     RECT  50.677 50.688 51.756 50.712 ;
     RECT  50.677 50.712 51.804 50.832 ;
     RECT  50.677 50.832 51.756 50.856 ;
     RECT  50.677 50.856 51.804 50.976 ;
     RECT  50.677 50.976 51.756 51 ;
     RECT  50.677 51 51.804 51.12 ;
     RECT  50.677 51.12 51.756 51.144 ;
     RECT  50.677 51.144 51.804 51.264 ;
     RECT  50.677 51.264 51.756 51.288 ;
     RECT  50.677 51.288 51.804 51.408 ;
     RECT  50.677 51.408 51.756 51.432 ;
     RECT  50.677 51.432 51.804 51.552 ;
     RECT  50.677 51.552 51.756 51.576 ;
     RECT  50.677 51.576 51.804 51.696 ;
     RECT  50.677 51.696 51.756 51.72 ;
     RECT  50.677 51.72 51.804 51.84 ;
     RECT  50.677 51.84 51.756 51.864 ;
     RECT  50.677 51.864 51.804 51.984 ;
     RECT  50.677 51.984 51.756 52.008 ;
     RECT  50.677 52.008 51.804 52.128 ;
     RECT  50.677 52.128 51.756 52.152 ;
     RECT  50.677 52.152 51.804 52.272 ;
     RECT  50.677 52.272 51.756 52.296 ;
     RECT  50.677 52.296 51.804 52.416 ;
     RECT  50.677 52.416 51.756 52.44 ;
     RECT  50.677 52.44 51.804 52.56 ;
     RECT  50.677 52.56 51.756 52.584 ;
     RECT  50.677 52.584 51.804 52.704 ;
     RECT  50.677 52.704 51.756 52.728 ;
     RECT  50.677 52.728 51.804 52.848 ;
     RECT  50.677 52.848 51.756 52.872 ;
     RECT  50.677 52.872 51.804 52.992 ;
     RECT  50.677 52.992 51.756 53.016 ;
     RECT  50.677 53.016 51.804 53.136 ;
     RECT  50.677 53.136 51.756 53.16 ;
     RECT  50.677 53.16 51.804 53.28 ;
     RECT  50.677 53.28 51.756 53.304 ;
     RECT  50.677 53.304 51.804 53.424 ;
     RECT  50.677 53.424 51.756 53.448 ;
     RECT  50.677 53.448 51.804 53.568 ;
     RECT  50.677 53.568 51.756 53.592 ;
     RECT  50.677 53.592 51.804 53.712 ;
     RECT  50.677 53.712 51.756 53.736 ;
     RECT  50.677 53.736 51.804 53.856 ;
     RECT  50.677 53.856 51.756 53.88 ;
     RECT  50.677 53.88 51.804 54 ;
     RECT  50.677 54 51.756 54.024 ;
     RECT  50.677 54.024 51.804 54.144 ;
     RECT  50.677 54.144 51.756 54.168 ;
     RECT  50.677 54.168 51.804 54.288 ;
     RECT  50.677 54.288 51.756 54.312 ;
     RECT  50.677 54.312 51.804 54.432 ;
     RECT  50.677 54.432 51.756 54.456 ;
     RECT  50.677 54.456 51.804 54.576 ;
     RECT  50.677 54.576 51.756 54.6 ;
     RECT  50.677 54.6 51.804 54.72 ;
     RECT  50.677 54.72 51.756 54.744 ;
     RECT  50.677 54.744 51.804 54.864 ;
     RECT  50.677 54.864 51.756 54.888 ;
     RECT  50.677 54.888 51.804 55.008 ;
     RECT  50.677 55.008 51.756 55.032 ;
     RECT  50.677 55.032 51.804 55.152 ;
     RECT  50.677 55.152 51.756 55.176 ;
     RECT  50.677 55.176 51.804 55.296 ;
     RECT  50.677 55.296 51.756 55.32 ;
     RECT  50.677 55.32 51.804 55.44 ;
     RECT  50.677 55.44 51.756 55.464 ;
     RECT  50.677 55.464 51.804 55.584 ;
     RECT  50.677 55.584 51.756 55.608 ;
     RECT  50.677 55.608 51.804 55.728 ;
     RECT  50.677 55.728 51.756 55.752 ;
     RECT  50.677 55.752 51.804 55.872 ;
     RECT  50.677 55.872 51.756 55.896 ;
     RECT  50.677 55.896 51.804 56.016 ;
     RECT  50.677 56.016 51.756 56.04 ;
     RECT  50.677 56.04 51.804 56.16 ;
     RECT  50.677 56.16 51.756 56.184 ;
     RECT  50.677 56.184 51.804 56.304 ;
     RECT  50.677 56.304 51.756 56.328 ;
     RECT  50.677 56.328 51.804 56.448 ;
     RECT  50.677 56.448 51.756 56.472 ;
     RECT  50.677 56.472 51.804 56.592 ;
     RECT  50.677 56.592 51.756 56.616 ;
     RECT  50.677 56.616 51.804 56.736 ;
     RECT  50.677 56.736 51.756 56.76 ;
     RECT  50.677 56.76 51.804 56.88 ;
     RECT  50.677 56.88 51.756 56.904 ;
     RECT  50.677 56.904 51.804 57.024 ;
     RECT  50.677 57.024 51.756 57.048 ;
     RECT  51.685 58.32 51.756 58.344 ;
     RECT  51.685 58.344 51.804 58.464 ;
     RECT  51.685 58.464 51.756 58.488 ;
     RECT  51.685 58.488 51.804 58.608 ;
     RECT  51.685 58.608 51.756 58.632 ;
     RECT  51.685 58.632 51.804 58.752 ;
     RECT  51.685 58.752 51.756 58.776 ;
     RECT  51.685 58.776 51.804 58.896 ;
     RECT  51.685 58.896 51.756 58.92 ;
     RECT  51.685 58.92 51.804 59.04 ;
     RECT  51.685 59.04 51.756 59.064 ;
     RECT  51.685 59.064 51.804 59.184 ;
     RECT  51.685 59.184 51.756 59.208 ;
     RECT  51.685 59.208 51.804 59.328 ;
     RECT  51.685 59.328 51.756 59.352 ;
     RECT  51.685 59.352 51.804 59.472 ;
     RECT  51.685 59.472 51.756 59.496 ;
     RECT  51.685 59.496 51.804 59.616 ;
     RECT  51.685 59.616 51.756 59.64 ;
     RECT  51.685 59.64 51.804 59.76 ;
     RECT  51.685 59.76 51.756 59.784 ;
     RECT  51.685 59.784 51.804 59.904 ;
     RECT  51.685 59.904 51.756 59.928 ;
     RECT  51.685 59.928 51.804 60.048 ;
     RECT  51.685 60.048 51.756 60.072 ;
     RECT  51.685 60.072 51.804 60.192 ;
     RECT  51.685 60.192 51.756 60.216 ;
     RECT  51.685 60.216 51.804 60.336 ;
     RECT  51.685 60.336 51.756 60.36 ;
     RECT  51.685 60.36 51.804 60.48 ;
     RECT  51.685 60.48 51.756 60.504 ;
     RECT  50.677 62.928 51.756 62.952 ;
     RECT  50.677 62.952 51.804 63.072 ;
     RECT  50.677 63.072 51.756 63.096 ;
     RECT  50.677 63.096 51.804 63.216 ;
     RECT  50.677 63.216 51.756 63.24 ;
     RECT  50.677 63.24 51.804 63.36 ;
     RECT  50.677 63.36 51.756 63.384 ;
     RECT  50.677 63.384 51.804 63.504 ;
     RECT  50.677 63.504 51.756 63.528 ;
     RECT  50.677 63.528 51.804 63.648 ;
     RECT  50.677 63.648 51.756 63.672 ;
     RECT  50.677 63.672 51.804 63.792 ;
     RECT  50.677 63.792 51.756 63.816 ;
     RECT  50.677 63.816 51.804 63.936 ;
     RECT  50.677 63.936 51.756 63.96 ;
     RECT  50.677 63.96 51.804 64.08 ;
     RECT  50.677 64.08 51.756 64.104 ;
     RECT  50.677 64.104 51.804 64.224 ;
     RECT  50.677 64.224 51.756 64.248 ;
     RECT  50.677 64.248 51.804 64.368 ;
     RECT  50.677 64.368 51.756 64.392 ;
     RECT  50.677 64.392 51.804 64.512 ;
     RECT  50.677 64.512 51.756 64.536 ;
     RECT  50.677 64.536 51.804 64.656 ;
     RECT  50.677 64.656 51.756 64.68 ;
     RECT  50.677 64.68 51.804 64.8 ;
     RECT  50.677 64.8 51.756 64.824 ;
     RECT  50.677 64.824 51.804 64.944 ;
     RECT  50.677 64.944 51.756 64.968 ;
     RECT  50.677 64.968 51.804 65.088 ;
     RECT  50.677 65.088 51.756 65.112 ;
     RECT  50.677 65.112 51.804 65.232 ;
     RECT  50.677 65.232 51.756 65.256 ;
     RECT  50.677 65.256 51.804 65.376 ;
     RECT  50.677 65.376 51.756 65.4 ;
     RECT  50.677 65.4 51.804 65.52 ;
     RECT  50.677 65.52 51.756 65.544 ;
     RECT  50.677 65.544 51.804 65.664 ;
     RECT  50.677 65.664 51.756 65.688 ;
     RECT  50.677 65.688 51.804 65.808 ;
     RECT  50.677 65.808 51.756 65.832 ;
     RECT  50.677 65.832 51.804 65.952 ;
     RECT  50.677 65.952 51.756 65.976 ;
     RECT  50.677 65.976 51.804 66.096 ;
     RECT  50.677 66.096 51.756 66.12 ;
     RECT  50.677 66.12 51.804 66.24 ;
     RECT  50.677 66.24 51.756 66.264 ;
     RECT  50.677 66.264 51.804 66.384 ;
     RECT  50.677 66.384 51.756 66.408 ;
     RECT  50.677 66.408 51.804 66.528 ;
     RECT  50.677 66.528 51.756 66.552 ;
     RECT  50.677 66.552 51.804 66.672 ;
     RECT  50.677 66.672 51.756 66.696 ;
     RECT  50.677 66.696 51.804 66.816 ;
     RECT  50.677 66.816 51.756 66.84 ;
     RECT  50.677 66.84 51.804 66.96 ;
     RECT  50.677 66.96 51.756 66.984 ;
     RECT  50.677 66.984 51.804 67.104 ;
     RECT  50.677 67.104 51.756 67.128 ;
     RECT  50.677 67.128 51.804 67.248 ;
     RECT  50.677 67.248 51.756 67.272 ;
     RECT  50.677 67.272 51.804 67.392 ;
     RECT  50.677 67.392 51.756 67.416 ;
     RECT  50.677 67.416 51.804 67.536 ;
     RECT  50.677 67.536 51.756 67.56 ;
     RECT  50.677 67.56 51.804 67.68 ;
     RECT  50.677 67.68 51.756 67.704 ;
     RECT  50.677 67.704 51.804 67.824 ;
     RECT  50.677 67.824 51.756 67.848 ;
     RECT  50.677 67.848 51.804 67.968 ;
     RECT  50.677 67.968 51.756 67.992 ;
     RECT  50.677 67.992 51.804 68.112 ;
     RECT  50.677 68.112 51.756 68.136 ;
     RECT  50.677 68.136 51.804 68.256 ;
     RECT  50.677 68.256 51.756 68.28 ;
     RECT  50.677 68.28 51.804 68.4 ;
     RECT  50.677 68.4 51.756 68.424 ;
     RECT  50.677 68.424 51.804 68.544 ;
     RECT  50.677 68.544 51.756 68.568 ;
     RECT  50.677 68.568 51.804 68.688 ;
     RECT  50.677 68.688 51.756 68.712 ;
     RECT  50.677 68.712 51.804 68.832 ;
     RECT  50.677 68.832 51.756 68.856 ;
     RECT  50.677 68.856 51.804 68.976 ;
     RECT  50.677 68.976 51.756 69 ;
     RECT  50.677 69 51.804 69.12 ;
     RECT  50.677 69.12 51.756 69.144 ;
     RECT  50.677 69.144 51.804 69.264 ;
     RECT  50.677 69.264 51.756 69.288 ;
     RECT  50.677 69.288 51.804 69.408 ;
     RECT  50.677 69.408 51.756 69.432 ;
     RECT  50.677 69.432 51.804 69.552 ;
     RECT  50.677 69.552 51.756 69.576 ;
     RECT  50.677 69.576 51.804 69.696 ;
     RECT  50.677 69.696 51.756 69.72 ;
     RECT  50.677 69.72 51.804 69.84 ;
     RECT  50.677 69.84 51.756 69.864 ;
     RECT  50.677 69.864 51.804 69.984 ;
     RECT  50.677 69.984 51.756 70.008 ;
     RECT  50.677 70.008 51.804 70.128 ;
     RECT  50.677 70.128 51.756 70.152 ;
     RECT  50.677 70.152 51.804 70.272 ;
     RECT  50.677 70.272 51.756 70.296 ;
     RECT  50.677 70.296 51.804 70.416 ;
     RECT  50.677 70.416 51.756 70.44 ;
     RECT  50.677 70.44 51.804 70.56 ;
     RECT  50.677 70.56 51.756 70.584 ;
     RECT  50.677 70.584 51.804 70.704 ;
     RECT  50.677 70.704 51.756 70.728 ;
     RECT  50.677 70.728 51.804 70.848 ;
     RECT  50.677 70.848 51.756 70.872 ;
     RECT  50.677 70.872 51.804 70.992 ;
     RECT  50.677 70.992 51.756 71.016 ;
     RECT  50.677 71.016 51.804 71.136 ;
     RECT  50.677 71.136 51.756 71.16 ;
     RECT  50.677 71.16 51.804 71.28 ;
     RECT  50.677 71.28 51.756 71.304 ;
     RECT  50.677 71.304 51.804 71.424 ;
     RECT  50.677 71.424 51.756 71.448 ;
     RECT  50.677 71.448 51.804 71.568 ;
     RECT  50.677 71.568 51.756 71.592 ;
     RECT  50.677 71.592 51.804 71.712 ;
     RECT  50.677 71.712 51.756 71.736 ;
     RECT  50.677 71.736 51.804 71.856 ;
     RECT  50.677 71.856 51.756 71.88 ;
     RECT  50.677 71.88 51.804 72 ;
     RECT  50.677 72 51.756 72.024 ;
     RECT  50.677 72.024 51.804 72.144 ;
     RECT  50.677 72.144 51.756 72.168 ;
     RECT  50.677 72.168 51.804 72.288 ;
     RECT  50.677 72.288 51.756 72.312 ;
     RECT  50.677 72.312 51.804 72.432 ;
     RECT  50.677 72.432 51.756 72.456 ;
     RECT  50.677 72.456 51.804 72.576 ;
     RECT  50.677 72.576 51.756 72.6 ;
     RECT  50.677 72.6 51.804 72.72 ;
     RECT  50.677 72.72 51.756 72.744 ;
     RECT  50.677 72.744 51.804 72.864 ;
     RECT  50.677 72.864 51.756 72.888 ;
     RECT  50.677 72.888 51.804 73.008 ;
     RECT  50.677 73.008 51.756 73.032 ;
     RECT  50.677 73.032 51.804 73.152 ;
     RECT  50.677 73.152 51.756 73.176 ;
     RECT  50.677 73.176 51.804 73.296 ;
     RECT  50.677 73.296 51.756 73.32 ;
     RECT  50.677 73.32 51.804 73.44 ;
     RECT  50.677 73.44 51.756 73.464 ;
     RECT  50.677 73.464 51.804 73.584 ;
     RECT  50.677 73.584 51.756 73.608 ;
     RECT  50.677 73.608 51.804 73.728 ;
     RECT  50.677 73.728 51.756 73.752 ;
     RECT  50.677 73.752 51.804 73.872 ;
     RECT  50.677 73.872 51.756 73.896 ;
     RECT  50.677 73.896 51.804 74.016 ;
     RECT  50.677 74.016 51.756 74.04 ;
     RECT  50.677 74.04 51.804 74.16 ;
     RECT  50.677 74.16 51.756 74.184 ;
     RECT  50.677 74.184 51.804 74.304 ;
     RECT  50.677 74.304 51.756 74.328 ;
     RECT  50.677 74.328 51.804 74.448 ;
     RECT  50.677 74.448 51.756 74.472 ;
     RECT  50.677 74.472 51.804 74.592 ;
     RECT  50.677 74.592 51.756 74.616 ;
     RECT  50.677 74.616 51.804 74.736 ;
     RECT  50.677 74.736 51.756 74.76 ;
     RECT  50.677 74.76 51.804 74.88 ;
     RECT  50.677 74.88 51.756 74.904 ;
     RECT  50.677 74.904 51.804 75.024 ;
     RECT  50.677 75.024 51.756 75.048 ;
     RECT  50.677 75.048 51.804 75.168 ;
     RECT  50.677 75.168 51.756 75.192 ;
     RECT  50.677 75.192 51.804 75.312 ;
     RECT  50.677 75.312 51.756 75.336 ;
     RECT  50.677 75.336 51.804 75.456 ;
     RECT  50.677 75.456 51.756 75.48 ;
     RECT  50.677 75.48 51.804 75.6 ;
     RECT  50.677 75.6 51.756 75.624 ;
     RECT  50.677 75.624 51.804 75.744 ;
     RECT  50.677 75.744 51.756 75.768 ;
     RECT  50.677 75.768 51.804 75.888 ;
     RECT  50.677 75.888 51.756 75.912 ;
     RECT  50.677 75.912 51.804 76.032 ;
     RECT  50.677 76.032 51.756 76.056 ;
     RECT  50.677 76.056 51.804 76.176 ;
     RECT  50.677 76.176 51.756 76.2 ;
     RECT  50.677 76.2 51.804 76.32 ;
     RECT  50.677 76.32 51.756 76.344 ;
     RECT  50.677 76.344 51.804 76.464 ;
     RECT  50.677 76.464 51.756 76.488 ;
     RECT  50.677 76.488 51.804 76.608 ;
     RECT  50.677 76.608 51.756 76.632 ;
     RECT  50.677 76.632 51.804 76.752 ;
     RECT  50.677 76.752 51.756 76.776 ;
     RECT  50.677 76.776 51.804 76.896 ;
     RECT  50.677 76.896 51.756 76.92 ;
     RECT  50.677 76.92 51.804 77.04 ;
     RECT  50.677 77.04 51.756 77.064 ;
     RECT  50.677 77.064 51.804 77.184 ;
     RECT  50.677 77.184 51.756 77.208 ;
     RECT  50.677 77.208 51.804 77.328 ;
     RECT  50.677 77.328 51.756 77.352 ;
     RECT  50.677 77.352 51.804 77.472 ;
     RECT  50.677 77.472 51.756 77.496 ;
     RECT  50.677 77.496 51.804 77.616 ;
     RECT  50.677 77.616 51.756 77.64 ;
     RECT  50.677 77.64 51.804 77.76 ;
     RECT  50.677 77.76 51.756 77.784 ;
     RECT  50.677 77.784 51.804 77.904 ;
     RECT  50.677 77.904 51.756 77.928 ;
     RECT  50.677 77.928 51.804 78.048 ;
     RECT  50.677 78.048 51.756 78.072 ;
     RECT  50.677 78.072 51.804 78.192 ;
     RECT  50.677 78.192 51.756 78.216 ;
     RECT  50.677 78.216 51.804 78.336 ;
     RECT  50.677 78.336 51.756 78.36 ;
     RECT  50.677 78.36 51.804 78.48 ;
     RECT  50.677 78.48 51.756 78.504 ;
     RECT  50.677 78.504 51.804 78.624 ;
     RECT  50.677 78.624 51.756 78.648 ;
     RECT  50.677 78.648 51.804 78.768 ;
     RECT  50.677 78.768 51.756 78.792 ;
     RECT  50.677 78.792 51.804 78.912 ;
     RECT  50.677 78.912 51.756 78.936 ;
     RECT  50.677 78.936 51.804 79.056 ;
     RECT  50.677 79.056 51.756 79.08 ;
     RECT  50.677 79.08 51.804 79.2 ;
     RECT  50.677 79.2 51.756 79.224 ;
     RECT  50.677 79.224 51.804 79.344 ;
     RECT  50.677 79.344 51.756 79.368 ;
     RECT  50.677 79.368 51.804 79.488 ;
     RECT  50.677 79.488 51.756 79.512 ;
     RECT  50.677 79.512 51.804 79.632 ;
     RECT  50.677 79.632 51.756 79.656 ;
     RECT  50.677 79.656 51.804 79.776 ;
     RECT  50.677 79.776 51.756 79.8 ;
     RECT  50.677 79.8 51.804 79.92 ;
     RECT  50.677 79.92 51.756 79.944 ;
     RECT  50.677 79.944 51.804 80.064 ;
     RECT  50.677 80.064 51.756 80.088 ;
     RECT  50.677 80.088 51.804 80.208 ;
     RECT  50.677 80.208 51.756 80.232 ;
     RECT  50.677 80.232 51.804 80.352 ;
     RECT  50.677 80.352 51.756 80.376 ;
     RECT  50.677 80.376 51.804 80.496 ;
     RECT  50.677 80.496 51.756 80.52 ;
     RECT  50.677 80.52 51.804 80.64 ;
     RECT  50.677 80.64 51.756 80.664 ;
     RECT  50.677 80.664 51.804 80.784 ;
     RECT  50.677 80.784 51.756 80.808 ;
     RECT  50.677 80.808 51.804 80.928 ;
     RECT  50.677 80.928 51.756 80.952 ;
     RECT  50.677 80.952 51.804 81.072 ;
     RECT  50.677 81.072 51.756 81.096 ;
     RECT  50.677 81.096 51.804 81.216 ;
     RECT  50.677 81.216 51.756 81.24 ;
    LAYER M5 ;
     RECT  20.904 0.016 21.024 0.037 ;
     RECT  21.048 0.016 21.168 0.037 ;
     RECT  21.192 0.016 21.312 0.037 ;
     RECT  21.336 0.016 21.456 0.037 ;
     RECT  21.48 0.016 21.6 0.037 ;
     RECT  21.624 0.016 21.744 0.037 ;
     RECT  20.784 0.037 20.88 0.084 ;
     RECT  20.904 0.037 21.024 0.084 ;
     RECT  21.048 0.037 21.168 0.084 ;
     RECT  21.192 0.037 21.312 0.084 ;
     RECT  21.336 0.037 21.456 0.084 ;
     RECT  21.48 0.037 21.6 0.084 ;
     RECT  21.624 0.037 21.744 0.084 ;
     RECT  20.784 0.084 21.768 0.133 ;
     RECT  20.784 0.133 22.008 0.179 ;
     RECT  21.168 0.179 22.008 1.187 ;
     RECT  25.008 0.037 25.032 2.137 ;
     RECT  2.4 2.137 2.52 2.151 ;
     RECT  5.1 2.137 5.22 2.151 ;
     RECT  7.8 2.137 7.92 2.151 ;
     RECT  10.5 2.137 10.62 2.151 ;
     RECT  13.2 2.137 13.32 2.151 ;
     RECT  15.9 2.137 16.02 2.151 ;
     RECT  18.6 2.137 18.72 2.151 ;
     RECT  26.7 2.137 26.82 2.151 ;
     RECT  29.4 2.137 29.52 2.151 ;
     RECT  32.1 2.137 32.22 2.151 ;
     RECT  34.8 2.137 34.92 2.151 ;
     RECT  37.5 2.137 37.62 2.151 ;
     RECT  40.2 2.137 40.32 2.151 ;
     RECT  42.9 2.137 43.02 2.151 ;
     RECT  45.6 2.137 45.72 2.151 ;
     RECT  48.3 2.137 48.42 2.151 ;
     RECT  21.3 1.187 22.008 2.341 ;
     RECT  21.3 2.341 22.824 2.579 ;
     RECT  42.9 2.151 43.212 2.773 ;
     RECT  18.6 2.151 18.912 2.821 ;
     RECT  24 2.137 25.032 2.821 ;
     RECT  26.7 2.151 27.012 2.821 ;
     RECT  18.6 2.821 19.032 2.869 ;
     RECT  42.624 2.773 43.212 2.965 ;
     RECT  10.5 2.151 10.812 3.013 ;
     RECT  18.6 2.869 19.656 3.059 ;
     RECT  37.5 2.151 37.812 3.109 ;
     RECT  13.2 2.151 13.512 3.205 ;
     RECT  39.072 2.821 39.096 3.205 ;
     RECT  40.2 2.151 40.512 3.205 ;
     RECT  37.056 3.109 37.812 3.251 ;
     RECT  39.072 3.205 40.512 3.251 ;
     RECT  5.1 2.151 5.412 3.397 ;
     RECT  2.4 2.151 2.712 3.973 ;
     RECT  41.904 2.965 43.212 4.019 ;
     RECT  15.9 2.151 16.212 4.021 ;
     RECT  23.472 2.821 25.032 4.115 ;
     RECT  13.2 3.205 13.608 4.117 ;
     RECT  15.9 4.021 17.16 4.163 ;
     RECT  2.4 3.973 2.808 4.259 ;
     RECT  5.1 3.397 6.072 4.355 ;
     RECT  26.112 2.821 27.012 4.355 ;
     RECT  33.6 2.821 33.624 4.355 ;
     RECT  13.104 4.117 13.608 4.451 ;
     RECT  18.6 3.059 19.032 4.453 ;
     RECT  42.9 4.019 43.212 4.453 ;
     RECT  13.2 4.451 13.608 4.499 ;
     RECT  9.408 3.397 9.432 4.643 ;
     RECT  41.904 4.019 41.928 4.643 ;
     RECT  32.1 2.151 32.412 4.645 ;
     RECT  45.6 2.151 45.912 5.077 ;
     RECT  39.648 3.251 40.512 5.123 ;
     RECT  21.3 2.579 22.008 5.173 ;
     RECT  37.5 3.251 37.812 5.173 ;
     RECT  5.1 4.355 6.024 5.459 ;
     RECT  15.9 4.163 16.212 5.461 ;
     RECT  40.2 5.123 40.512 5.461 ;
     RECT  18.6 4.453 19.08 5.507 ;
     RECT  18.6 5.507 18.912 5.701 ;
     RECT  26.7 4.355 27.012 6.229 ;
     RECT  37.008 5.173 37.812 6.229 ;
     RECT  0.24 4.981 0.264 6.373 ;
     RECT  34.8 2.151 35.112 6.469 ;
     RECT  36.336 6.229 37.812 6.469 ;
     RECT  0.144 6.373 0.264 6.659 ;
     RECT  7.8 2.151 8.112 6.661 ;
     RECT  9.12 5.701 9.144 6.661 ;
     RECT  18.336 5.701 18.912 6.709 ;
     RECT  21.072 5.173 22.008 6.709 ;
     RECT  34.8 6.469 37.812 6.803 ;
     RECT  7.8 6.661 9.144 6.805 ;
     RECT  7.632 6.805 9.144 6.899 ;
     RECT  34.8 6.803 36.36 6.947 ;
     RECT  13.2 4.499 13.512 6.949 ;
     RECT  3.984 5.077 4.008 6.995 ;
     RECT  18.336 6.709 19.608 7.043 ;
     RECT  42.9 4.453 43.32 7.045 ;
     RECT  13.104 6.949 13.512 7.283 ;
     RECT  24 4.115 25.032 7.333 ;
     RECT  26.208 6.229 27.012 7.333 ;
     RECT  24 7.333 27.012 7.379 ;
     RECT  10.5 3.013 10.92 7.381 ;
     RECT  40.2 5.461 40.632 7.381 ;
     RECT  45.6 5.077 46.536 7.381 ;
     RECT  0.24 6.659 0.264 7.717 ;
     RECT  2.4 4.259 2.712 7.765 ;
     RECT  13.2 7.283 13.512 7.765 ;
     RECT  20.928 6.709 22.008 7.861 ;
     RECT  7.632 6.899 8.856 7.909 ;
     RECT  0.24 7.717 0.408 7.957 ;
     RECT  40.2 7.381 40.872 7.957 ;
     RECT  42.9 7.045 44.04 8.003 ;
     RECT  42.9 8.003 43.32 8.147 ;
     RECT  39.6 7.957 40.872 8.339 ;
     RECT  13.2 7.765 13.848 8.387 ;
     RECT  15.36 5.461 16.212 8.435 ;
     RECT  24 7.379 25.704 8.437 ;
     RECT  26.7 7.379 27.012 8.437 ;
     RECT  15.9 8.435 16.212 8.485 ;
     RECT  18.6 7.043 19.608 8.485 ;
     RECT  20.928 7.861 22.248 8.485 ;
     RECT  18.6 8.485 22.248 8.627 ;
     RECT  18.6 8.627 22.008 8.675 ;
     RECT  5.1 5.459 5.928 8.677 ;
     RECT  45.6 7.381 46.728 8.723 ;
     RECT  42.9 8.147 43.212 8.821 ;
     RECT  10.5 7.381 11.448 8.869 ;
     RECT  0.192 7.957 0.408 8.965 ;
     RECT  20.496 8.675 22.008 9.059 ;
     RECT  24 8.437 27.012 9.109 ;
     RECT  0.192 8.965 0.648 9.155 ;
     RECT  5.1 8.677 6.312 9.155 ;
     RECT  34.8 6.947 36.216 9.155 ;
     RECT  23.232 9.109 27.012 9.203 ;
     RECT  7.632 7.909 9.288 9.397 ;
     RECT  10.5 8.869 11.832 9.397 ;
     RECT  7.632 9.397 11.832 9.589 ;
     RECT  37.5 6.803 37.812 9.637 ;
     RECT  15.9 8.485 16.488 9.683 ;
     RECT  39.6 8.339 40.632 9.731 ;
     RECT  31.536 4.645 32.412 9.779 ;
     RECT  6.672 9.589 11.832 9.827 ;
     RECT  42.768 8.821 43.212 9.925 ;
     RECT  31.968 9.779 32.412 10.213 ;
     RECT  40.2 9.731 40.632 10.261 ;
     RECT  20.976 9.059 22.008 10.307 ;
     RECT  26.064 9.203 27.012 10.355 ;
     RECT  6.672 9.827 10.812 10.835 ;
     RECT  13.2 8.387 13.704 10.837 ;
     RECT  7.632 10.835 10.812 10.883 ;
     RECT  40.2 10.261 41.064 10.883 ;
     RECT  31.968 10.213 33.24 10.931 ;
     RECT  0.192 9.155 0.552 11.123 ;
     RECT  11.808 9.827 11.832 11.411 ;
     RECT  5.1 9.155 5.592 11.459 ;
     RECT  32.1 10.931 33.24 11.459 ;
     RECT  37.5 9.637 38.232 11.459 ;
     RECT  13.2 10.837 13.848 11.651 ;
     RECT  2.4 7.765 3.096 11.941 ;
     RECT  15.9 9.683 16.392 11.941 ;
     RECT  34.8 9.155 35.112 11.941 ;
     RECT  42.624 9.925 43.212 11.941 ;
     RECT  23.232 9.203 25.032 11.987 ;
     RECT  10.5 10.883 10.812 12.517 ;
     RECT  24 11.987 25.032 12.517 ;
     RECT  29.4 2.151 29.712 12.517 ;
     RECT  0.192 11.123 0.456 12.901 ;
     RECT  0.144 12.901 0.456 13.043 ;
     RECT  42.384 11.941 43.212 13.043 ;
     RECT  34.608 11.941 35.112 13.045 ;
     RECT  36.192 9.155 36.216 13.045 ;
     RECT  34.608 13.045 36.216 13.091 ;
     RECT  15.9 11.941 16.584 13.139 ;
     RECT  24 12.517 25.608 13.139 ;
     RECT  47.232 12.517 47.256 13.283 ;
     RECT  18.6 8.675 18.912 13.333 ;
     RECT  13.2 11.651 13.512 13.381 ;
     RECT  0.144 13.043 0.408 13.427 ;
     RECT  2.4 11.941 3.624 13.523 ;
     RECT  37.5 11.459 37.812 13.573 ;
     RECT  38.832 12.901 38.856 13.573 ;
     RECT  40.2 10.883 40.512 13.573 ;
     RECT  24 13.139 25.512 13.621 ;
     RECT  34.608 13.091 36.072 13.667 ;
     RECT  38.832 13.573 40.512 13.859 ;
     RECT  7.632 10.883 8.856 13.907 ;
     RECT  10.5 12.517 11.16 13.907 ;
     RECT  0.192 13.427 0.408 14.003 ;
     RECT  13.008 13.381 13.512 14.099 ;
     RECT  15.9 13.139 16.212 14.101 ;
     RECT  23.328 13.621 25.512 14.197 ;
     RECT  29.4 12.517 30.12 14.197 ;
     RECT  39.312 13.859 40.512 14.197 ;
     RECT  6.48 11.941 6.504 14.339 ;
     RECT  29.4 14.197 30.792 14.339 ;
     RECT  17.664 13.333 18.912 14.341 ;
     RECT  30.768 14.339 30.792 14.533 ;
     RECT  32.1 11.459 32.412 14.533 ;
     RECT  0.192 14.003 0.264 14.579 ;
     RECT  26.7 10.355 27.012 14.629 ;
     RECT  39.312 14.197 40.68 14.675 ;
     RECT  17.664 14.341 19.224 14.677 ;
     RECT  2.4 13.523 2.712 14.725 ;
     RECT  29.4 14.339 29.712 14.773 ;
     RECT  42.9 13.043 43.212 14.821 ;
     RECT  37.152 13.573 37.812 14.867 ;
     RECT  5.1 11.459 5.412 14.917 ;
     RECT  10.5 13.907 10.812 14.917 ;
     RECT  40.2 14.675 40.68 15.013 ;
     RECT  13.2 14.099 13.512 15.061 ;
     RECT  17.664 14.677 20.136 15.061 ;
     RECT  21.3 10.307 22.008 15.061 ;
     RECT  30.768 14.533 32.412 15.107 ;
     RECT  0.24 14.579 0.264 15.155 ;
     RECT  5.1 14.917 5.64 15.203 ;
     RECT  15.696 14.101 16.212 15.301 ;
     RECT  17.664 15.061 22.008 15.347 ;
     RECT  23.328 14.197 25.704 15.443 ;
     RECT  26.7 14.629 27.144 15.443 ;
     RECT  24 15.443 25.704 15.445 ;
     RECT  26.7 15.443 27.012 15.445 ;
     RECT  29.04 14.773 29.712 15.587 ;
     RECT  2.4 14.725 2.856 15.731 ;
     RECT  10.368 14.917 10.812 16.019 ;
     RECT  13.2 15.061 13.848 16.115 ;
     RECT  15.072 15.301 16.212 16.165 ;
     RECT  7.8 13.907 8.856 16.261 ;
     RECT  30.768 15.107 30.792 16.357 ;
     RECT  2.4 15.731 2.712 16.405 ;
     RECT  30.768 16.357 30.84 16.499 ;
     RECT  29.4 15.587 29.712 16.501 ;
     RECT  34.8 13.667 36.072 16.549 ;
     RECT  37.5 14.867 37.812 16.549 ;
     RECT  18.6 15.347 22.008 16.595 ;
     RECT  42.192 14.821 43.212 16.595 ;
     RECT  1.968 16.405 2.712 16.691 ;
     RECT  3.936 16.357 3.96 16.691 ;
     RECT  34.8 16.549 37.812 16.979 ;
     RECT  14.784 16.165 16.212 16.981 ;
     RECT  45.6 8.723 46.248 16.981 ;
     RECT  10.5 16.019 10.812 17.029 ;
     RECT  32.1 15.107 32.412 17.029 ;
     RECT  7.8 16.261 9.144 17.077 ;
     RECT  48.3 2.151 48.612 17.077 ;
     RECT  14.784 16.981 17.112 17.123 ;
     RECT  45.6 16.981 46.344 17.123 ;
     RECT  30.816 16.499 30.84 17.267 ;
     RECT  32.1 17.029 32.952 17.413 ;
     RECT  14.784 17.123 16.212 17.699 ;
     RECT  24 15.445 27.012 18.083 ;
     RECT  6.576 17.605 6.6 18.133 ;
     RECT  7.8 17.077 9.384 18.133 ;
     RECT  6.576 18.133 9.384 18.179 ;
     RECT  31.152 17.413 32.952 18.179 ;
     RECT  37.5 16.979 37.812 18.181 ;
     RECT  6.576 18.179 8.856 18.275 ;
     RECT  47.856 17.077 48.612 18.275 ;
     RECT  3.792 16.789 3.816 18.517 ;
     RECT  34.8 16.979 35.496 18.563 ;
     RECT  2.4 16.691 2.712 18.565 ;
     RECT  40.2 15.013 40.728 18.755 ;
     RECT  29.4 16.501 29.832 18.757 ;
     RECT  34.8 18.563 35.112 18.757 ;
     RECT  1.968 18.565 2.712 18.803 ;
     RECT  3.792 18.517 3.96 18.803 ;
     RECT  10.5 17.029 10.92 18.851 ;
     RECT  20.16 16.595 22.008 18.851 ;
     RECT  40.2 18.755 40.632 18.851 ;
     RECT  37.5 18.181 38.232 18.995 ;
     RECT  40.2 18.851 40.512 19.093 ;
     RECT  3.792 18.803 3.816 19.235 ;
     RECT  20.832 18.851 22.008 19.283 ;
     RECT  7.488 18.275 8.856 19.333 ;
     RECT  18.6 16.595 18.912 19.333 ;
     RECT  26.208 18.083 27.012 19.427 ;
     RECT  28.944 18.757 29.832 19.427 ;
     RECT  0.144 19.765 0.168 19.907 ;
     RECT  7.488 19.333 9.48 19.955 ;
     RECT  39.312 19.093 40.512 20.003 ;
     RECT  7.488 19.955 8.616 20.099 ;
     RECT  31.152 18.179 32.412 20.149 ;
     RECT  45.6 17.123 46.2 20.149 ;
     RECT  26.7 19.427 27.012 20.197 ;
     RECT  34.272 18.757 35.112 20.245 ;
     RECT  33.648 20.245 35.112 20.291 ;
     RECT  42.9 16.595 43.212 20.389 ;
     RECT  36.336 18.757 36.36 20.579 ;
     RECT  21.072 19.283 22.008 20.725 ;
     RECT  45.6 20.149 47.16 20.915 ;
     RECT  7.488 20.099 8.52 20.963 ;
     RECT  30.816 20.149 32.412 21.107 ;
     RECT  17.616 19.333 18.912 21.155 ;
     RECT  21.072 20.725 22.2 21.155 ;
     RECT  33.648 20.291 33.672 21.203 ;
     RECT  38.832 20.965 38.856 21.203 ;
     RECT  37.5 18.995 37.812 21.205 ;
     RECT  28.944 19.427 29.712 21.251 ;
     RECT  42.288 20.389 43.212 21.251 ;
     RECT  15.408 17.699 16.212 21.347 ;
     RECT  37.5 21.205 38.088 21.445 ;
     RECT  37.056 21.445 38.088 21.539 ;
     RECT  31.152 21.107 32.412 21.635 ;
     RECT  10.5 18.851 10.812 21.637 ;
     RECT  21.3 21.155 22.2 21.683 ;
     RECT  26.7 20.197 27.576 21.683 ;
     RECT  7.8 20.963 8.52 22.021 ;
     RECT  18.6 21.155 18.912 22.165 ;
     RECT  37.056 21.539 37.812 22.165 ;
     RECT  34.8 20.291 35.112 22.213 ;
     RECT  36.24 22.165 37.812 22.213 ;
     RECT  2.4 18.803 2.712 22.645 ;
     RECT  29.4 21.251 29.712 23.029 ;
     RECT  29.4 23.029 29.976 23.077 ;
     RECT  15.648 21.347 16.212 23.317 ;
     RECT  24 18.083 25.032 23.317 ;
     RECT  2.4 22.645 3.096 23.411 ;
     RECT  34.8 22.213 37.812 23.411 ;
     RECT  13.2 16.115 13.512 23.605 ;
     RECT  18.6 22.165 19.032 23.653 ;
     RECT  40.2 20.003 40.512 23.701 ;
     RECT  45.6 20.915 46.2 23.701 ;
     RECT  21.3 21.683 22.008 23.797 ;
     RECT  5.1 15.203 5.412 23.893 ;
     RECT  13.2 23.605 13.656 23.893 ;
     RECT  15.648 23.317 16.344 23.939 ;
     RECT  37.5 23.411 37.812 23.941 ;
     RECT  10.5 21.637 11.112 23.987 ;
     RECT  18.336 23.653 19.032 23.987 ;
     RECT  45.6 23.701 46.728 23.987 ;
     RECT  23.904 23.317 25.032 24.227 ;
     RECT  26.7 21.683 27.012 24.373 ;
     RECT  29.4 23.077 30.696 24.469 ;
     RECT  18.336 23.987 18.912 24.563 ;
     RECT  34.8 23.411 36.264 24.563 ;
     RECT  5.1 23.893 5.976 24.611 ;
     RECT  26.256 24.373 27.012 24.613 ;
     RECT  13.2 23.893 14.52 24.659 ;
     RECT  34.8 24.563 35.976 24.659 ;
     RECT  42.9 21.251 43.212 24.997 ;
     RECT  45.6 23.987 46.2 25.043 ;
     RECT  15.9 23.939 16.344 25.139 ;
     RECT  40.032 23.701 40.512 25.139 ;
     RECT  29.4 24.469 30.84 25.333 ;
     RECT  31.92 21.635 32.412 25.333 ;
     RECT  10.5 23.987 10.812 25.621 ;
     RECT  7.8 22.021 8.952 25.667 ;
     RECT  18.432 24.563 18.912 25.669 ;
     RECT  5.1 24.611 5.784 26.197 ;
     RECT  26.256 24.613 27.144 26.483 ;
     RECT  20.496 23.797 22.008 26.485 ;
     RECT  20.304 26.485 22.008 26.675 ;
     RECT  2.4 23.411 2.712 26.725 ;
     RECT  18.432 25.669 19.032 26.819 ;
     RECT  2.4 26.725 3.528 26.963 ;
     RECT  34.8 24.659 35.112 27.301 ;
     RECT  18.432 26.819 18.912 27.781 ;
     RECT  20.304 26.675 20.328 27.781 ;
     RECT  34.8 27.301 35.88 27.971 ;
     RECT  40.2 25.139 40.512 27.973 ;
     RECT  5.1 26.197 5.928 28.115 ;
     RECT  34.8 27.971 35.112 28.309 ;
     RECT  18.432 27.781 20.328 28.405 ;
     RECT  18 28.405 20.328 28.451 ;
     RECT  10.272 25.621 10.812 28.453 ;
     RECT  15.9 25.139 16.212 28.453 ;
     RECT  45.6 25.043 45.912 28.453 ;
     RECT  7.8 25.667 8.28 28.597 ;
     RECT  6.912 28.597 8.28 28.739 ;
     RECT  15.9 28.453 16.44 28.739 ;
     RECT  29.4 25.333 32.412 28.837 ;
     RECT  26.592 26.483 27.144 28.931 ;
     RECT  29.28 28.837 32.412 29.123 ;
     RECT  10.224 28.453 10.812 29.171 ;
     RECT  40.2 27.973 41.064 29.219 ;
     RECT  13.2 24.659 14.424 29.221 ;
     RECT  33.84 28.309 35.112 29.267 ;
     RECT  5.1 28.115 5.412 29.365 ;
     RECT  13.104 29.221 14.424 29.507 ;
     RECT  45.6 28.453 46.728 29.507 ;
     RECT  15.9 28.739 16.212 29.509 ;
     RECT  36.384 28.453 36.408 29.509 ;
     RECT  40.2 29.219 40.512 29.509 ;
     RECT  13.2 29.507 14.424 29.555 ;
     RECT  10.272 29.171 10.812 29.699 ;
     RECT  37.5 23.941 38.76 29.891 ;
     RECT  15.648 29.509 16.212 29.941 ;
     RECT  5.1 29.365 6.072 29.989 ;
     RECT  20.112 28.451 20.328 30.181 ;
     RECT  29.28 29.123 30.6 30.227 ;
     RECT  4.368 29.989 6.072 30.275 ;
     RECT  18 28.451 18.912 30.611 ;
     RECT  42.9 24.997 44.04 30.757 ;
     RECT  13.2 29.555 13.656 30.803 ;
     RECT  19.968 30.181 20.328 30.803 ;
     RECT  36.384 29.509 36.456 30.803 ;
     RECT  36.384 30.803 36.408 30.899 ;
     RECT  13.2 30.803 13.512 31.141 ;
     RECT  13.104 31.141 13.512 31.283 ;
     RECT  4.368 30.275 5.412 31.331 ;
     RECT  29.4 30.227 30.6 31.379 ;
     RECT  31.92 29.123 32.412 31.379 ;
     RECT  40.08 29.509 40.512 31.379 ;
     RECT  2.4 26.963 2.712 31.621 ;
     RECT  45.6 29.507 45.912 31.669 ;
     RECT  2.4 31.621 2.808 31.763 ;
     RECT  40.2 31.379 40.512 31.765 ;
     RECT  10.5 29.699 10.812 31.813 ;
     RECT  15.6 29.941 16.212 31.955 ;
     RECT  42.9 30.757 44.472 32.195 ;
     RECT  45.6 31.669 46.68 32.243 ;
     RECT  5.1 31.331 5.412 32.341 ;
     RECT  26.7 28.931 27.012 32.341 ;
     RECT  21.3 26.675 22.008 32.437 ;
     RECT  32.1 31.379 32.412 32.437 ;
     RECT  34.8 29.267 35.112 32.437 ;
     RECT  9.888 31.813 10.812 32.485 ;
     RECT  15.648 31.955 16.212 32.485 ;
     RECT  13.2 31.283 13.512 32.773 ;
     RECT  13.104 32.773 13.512 32.915 ;
     RECT  5.1 32.341 5.544 33.013 ;
     RECT  37.5 29.891 38.664 33.013 ;
     RECT  4.368 33.013 5.544 33.059 ;
     RECT  9.6 32.485 10.812 33.059 ;
     RECT  40.2 31.765 41.016 33.059 ;
     RECT  21.3 32.437 22.2 33.299 ;
     RECT  34.272 32.437 35.112 33.299 ;
     RECT  7.8 28.739 8.28 33.445 ;
     RECT  18.432 30.611 18.912 33.445 ;
     RECT  29.4 31.379 29.712 33.445 ;
     RECT  40.2 33.059 40.512 33.493 ;
     RECT  2.4 31.763 2.712 33.541 ;
     RECT  1.968 33.541 2.712 33.731 ;
     RECT  4.368 33.059 5.412 33.731 ;
     RECT  45.6 32.243 45.912 33.829 ;
     RECT  20.16 30.803 20.328 34.117 ;
     RECT  21.3 33.299 22.008 34.117 ;
     RECT  29.4 33.445 30.552 34.117 ;
     RECT  40.032 33.493 40.512 34.117 ;
     RECT  32.1 32.437 32.52 34.163 ;
     RECT  48.3 18.275 48.612 34.165 ;
     RECT  28.512 34.117 30.552 34.259 ;
     RECT  7.8 33.445 9.144 34.355 ;
     RECT  26.7 32.341 27.336 34.403 ;
     RECT  36.528 33.013 38.664 34.499 ;
     RECT  15.648 32.485 16.968 34.789 ;
     RECT  28.512 34.259 29.712 34.835 ;
     RECT  47.616 34.165 48.612 34.835 ;
     RECT  7.8 34.355 8.952 34.883 ;
     RECT  10.5 33.059 10.812 34.885 ;
     RECT  45.6 33.829 46.008 34.931 ;
     RECT  5.1 33.731 5.412 34.933 ;
     RECT  32.1 34.163 32.412 35.173 ;
     RECT  18.432 33.445 19.032 35.315 ;
     RECT  14.784 34.789 16.968 35.411 ;
     RECT  39.84 34.117 40.512 35.411 ;
     RECT  40.2 35.411 40.512 35.749 ;
     RECT  42.9 32.195 43.944 35.797 ;
     RECT  13.2 32.915 13.512 35.845 ;
     RECT  40.2 35.749 41.016 35.891 ;
     RECT  14.784 35.411 16.212 35.939 ;
     RECT  10.5 34.885 11.4 35.987 ;
     RECT  26.7 34.403 27.192 36.035 ;
     RECT  4.512 34.933 5.412 36.227 ;
     RECT  31.824 35.173 32.412 36.277 ;
     RECT  31.824 36.277 32.52 36.419 ;
     RECT  28.896 34.835 29.712 36.515 ;
     RECT  40.2 35.891 40.68 36.515 ;
     RECT  42.768 35.797 43.944 36.517 ;
     RECT  13.104 35.845 13.512 36.563 ;
     RECT  37.5 34.499 38.664 36.709 ;
     RECT  42.576 36.517 43.944 36.803 ;
     RECT  29.184 36.515 29.712 37.235 ;
     RECT  30.816 36.421 30.84 37.235 ;
     RECT  37.056 36.709 38.664 37.235 ;
     RECT  2.4 33.731 2.712 37.429 ;
     RECT  34.8 33.299 35.112 37.429 ;
     RECT  15.504 35.939 16.212 37.477 ;
     RECT  26.7 36.035 27.144 37.477 ;
     RECT  20.16 34.117 22.008 37.573 ;
     RECT  31.824 36.419 32.412 37.573 ;
     RECT  2.112 37.429 2.712 37.619 ;
     RECT  18.432 35.315 18.912 37.667 ;
     RECT  24 24.227 25.032 37.765 ;
     RECT  5.1 36.227 5.412 37.861 ;
     RECT  18.6 37.667 18.912 37.861 ;
     RECT  20.16 37.573 22.632 37.861 ;
     RECT  15.408 37.477 16.212 38.053 ;
     RECT  10.5 35.987 10.812 38.101 ;
     RECT  29.4 37.235 29.712 38.101 ;
     RECT  15.36 38.053 16.212 38.195 ;
     RECT  42.9 36.803 43.944 38.243 ;
     RECT  26.7 37.477 27.336 38.533 ;
     RECT  18.6 37.861 22.632 38.675 ;
     RECT  34.8 37.429 35.88 38.677 ;
     RECT  37.5 37.235 38.664 38.677 ;
     RECT  18.6 38.675 22.152 38.723 ;
     RECT  26.208 38.533 27.336 38.723 ;
     RECT  5.1 37.861 6.312 38.819 ;
     RECT  23.616 37.765 25.032 38.819 ;
     RECT  11.952 38.389 11.976 38.915 ;
     RECT  33.792 36.949 33.816 38.915 ;
     RECT  0.144 38.917 0.168 39.013 ;
     RECT  0.144 39.013 0.36 39.155 ;
     RECT  7.8 34.883 8.28 39.203 ;
     RECT  15.408 38.195 16.212 39.203 ;
     RECT  29.4 38.101 29.832 39.491 ;
     RECT  31.68 37.573 32.412 39.637 ;
     RECT  45.6 34.931 45.912 39.781 ;
     RECT  30.912 39.637 32.412 39.923 ;
     RECT  34.8 38.677 36.072 39.923 ;
     RECT  42.9 38.243 43.212 40.021 ;
     RECT  15.744 39.203 16.212 40.069 ;
     RECT  5.1 38.819 5.544 40.115 ;
     RECT  7.8 39.203 8.232 40.115 ;
     RECT  0.144 39.155 0.216 40.163 ;
     RECT  24 38.819 25.032 40.165 ;
     RECT  9.696 38.101 10.812 40.259 ;
     RECT  23.328 40.165 25.032 40.355 ;
     RECT  26.208 38.723 27.012 40.405 ;
     RECT  45.6 39.781 46.488 40.883 ;
     RECT  13.2 36.563 13.512 41.029 ;
     RECT  20.16 38.723 22.152 41.075 ;
     RECT  30.912 39.923 30.936 41.077 ;
     RECT  2.4 37.619 2.712 41.269 ;
     RECT  13.2 41.029 13.752 41.365 ;
     RECT  30.72 41.077 30.936 41.411 ;
     RECT  28.032 41.173 28.056 41.507 ;
     RECT  13.104 41.365 13.752 41.651 ;
     RECT  23.328 40.355 24.648 41.651 ;
     RECT  25.824 40.405 27.012 41.651 ;
     RECT  30.912 41.411 30.936 41.651 ;
     RECT  34.8 39.923 35.208 41.651 ;
     RECT  37.5 38.677 39.192 41.651 ;
     RECT  37.5 41.651 38.808 41.989 ;
     RECT  10.5 40.259 10.812 42.085 ;
     RECT  7.8 40.115 8.112 42.133 ;
     RECT  0.192 40.163 0.216 42.229 ;
     RECT  0.144 42.229 0.216 42.565 ;
     RECT  13.104 41.651 13.512 42.613 ;
     RECT  18.6 38.723 18.912 42.613 ;
     RECT  29.4 39.491 29.712 42.709 ;
     RECT  34.8 41.651 35.112 42.709 ;
     RECT  2.4 41.269 3.192 42.755 ;
     RECT  0.144 42.565 0.312 42.757 ;
     RECT  13.104 42.613 13.656 42.947 ;
     RECT  6.864 42.133 8.112 42.995 ;
     RECT  42.768 40.021 43.212 42.995 ;
     RECT  42.9 42.995 43.212 42.997 ;
     RECT  40.2 36.515 40.512 43.093 ;
     RECT  20.16 41.075 20.328 43.189 ;
     RECT  21.3 41.075 22.152 43.189 ;
     RECT  13.104 42.947 13.512 43.283 ;
     RECT  32.1 39.923 32.412 43.333 ;
     RECT  0.144 42.757 0.552 43.379 ;
     RECT  10.5 42.085 11.448 43.379 ;
     RECT  26.7 41.651 27.012 43.717 ;
     RECT  36.624 41.989 38.808 43.763 ;
     RECT  7.8 42.995 8.112 43.813 ;
     RECT  48.3 34.835 48.612 43.861 ;
     RECT  15.744 40.069 16.488 44.053 ;
     RECT  10.5 43.379 10.812 44.245 ;
     RECT  40.08 43.093 40.512 44.389 ;
     RECT  7.8 43.813 8.904 44.435 ;
     RECT  29.184 42.709 29.712 44.483 ;
     RECT  36.624 43.763 38.712 44.483 ;
     RECT  0.192 43.379 0.552 44.531 ;
     RECT  5.1 40.115 5.412 44.629 ;
     RECT  37.5 44.483 38.712 44.725 ;
     RECT  5.1 44.629 5.688 44.773 ;
     RECT  31.968 43.333 32.412 44.965 ;
     RECT  37.5 44.725 38.856 44.965 ;
     RECT  39.936 44.389 40.512 44.965 ;
     RECT  31.344 44.965 32.412 45.107 ;
     RECT  10.368 44.245 10.812 45.157 ;
     RECT  9.936 45.157 10.812 45.205 ;
     RECT  42.9 42.997 44.184 45.541 ;
     RECT  47.616 43.861 48.612 45.589 ;
     RECT  2.4 42.755 2.904 45.635 ;
     RECT  0.192 44.531 0.312 45.973 ;
     RECT  5.1 44.773 6.312 46.211 ;
     RECT  17.808 42.613 18.912 46.211 ;
     RECT  36.432 44.965 36.456 46.211 ;
     RECT  37.5 44.965 40.512 46.211 ;
     RECT  34.608 42.709 35.112 46.259 ;
     RECT  47.424 45.589 48.612 46.259 ;
     RECT  13.2 43.283 13.512 46.261 ;
     RECT  24 41.651 24.648 46.501 ;
     RECT  13.104 46.261 13.512 46.547 ;
     RECT  23.136 46.501 24.648 46.645 ;
     RECT  26.208 43.717 27.012 46.645 ;
     RECT  31.392 45.107 32.412 46.645 ;
     RECT  7.8 44.435 8.112 46.693 ;
     RECT  42.24 45.541 44.184 46.787 ;
     RECT  0.144 45.973 0.312 46.835 ;
     RECT  9.6 45.205 10.812 47.075 ;
     RECT  18.6 46.211 18.912 47.125 ;
     RECT  23.136 46.645 27.012 47.173 ;
     RECT  5.1 46.211 5.688 47.269 ;
     RECT  15.408 44.053 16.488 47.315 ;
     RECT  7.8 46.693 8.232 47.459 ;
     RECT  23.136 47.173 27.336 47.747 ;
     RECT  34.8 46.259 35.112 47.749 ;
     RECT  13.2 46.547 13.512 47.893 ;
     RECT  20.16 43.189 22.152 47.987 ;
     RECT  26.208 47.747 27.336 48.035 ;
     RECT  23.136 47.747 25.08 48.037 ;
     RECT  22.8 48.037 25.08 48.083 ;
     RECT  9.936 47.075 10.812 48.085 ;
     RECT  0.144 46.835 0.216 48.133 ;
     RECT  13.104 47.893 13.512 48.373 ;
     RECT  18.6 47.125 19.032 48.419 ;
     RECT  26.208 48.035 27.012 48.419 ;
     RECT  34.176 47.749 35.112 48.421 ;
     RECT  40.2 46.211 40.512 48.421 ;
     RECT  34.176 48.421 35.352 48.467 ;
     RECT  31.344 46.645 32.412 48.469 ;
     RECT  40.2 48.421 40.68 48.469 ;
     RECT  0.144 48.133 0.264 48.565 ;
     RECT  24 48.083 25.08 48.757 ;
     RECT  29.4 44.483 29.712 48.757 ;
     RECT  31.344 48.469 33.096 48.757 ;
     RECT  37.5 46.211 38.952 48.757 ;
     RECT  40.2 48.469 41.016 48.803 ;
     RECT  7.8 47.459 8.112 48.805 ;
     RECT  22.8 48.083 22.824 48.947 ;
     RECT  29.088 48.757 29.712 48.995 ;
     RECT  2.4 45.635 2.712 48.997 ;
     RECT  3.936 47.221 3.96 48.997 ;
     RECT  13.104 48.373 13.8 48.997 ;
     RECT  2.4 48.997 3.96 49.043 ;
     RECT  13.008 48.997 13.8 49.043 ;
     RECT  24 48.757 25.272 49.043 ;
     RECT  29.232 48.995 29.712 49.043 ;
     RECT  31.344 48.757 33.24 49.043 ;
     RECT  36.864 48.757 38.952 49.043 ;
     RECT  40.2 48.803 40.92 49.043 ;
     RECT  2.4 49.043 3.432 49.093 ;
     RECT  9.696 48.085 10.812 49.139 ;
     RECT  1.968 49.093 3.432 49.235 ;
     RECT  18.6 48.419 18.912 49.333 ;
     RECT  13.008 49.043 13.512 49.381 ;
     RECT  20.16 47.987 21.612 49.475 ;
     RECT  9.12 49.237 9.144 49.523 ;
     RECT  0.144 48.565 0.312 49.525 ;
     RECT  31.344 49.043 32.412 49.619 ;
     RECT  21.3 49.475 21.612 49.909 ;
     RECT  29.4 49.043 29.712 50.005 ;
     RECT  31.728 49.619 32.412 50.051 ;
     RECT  7.68 48.805 8.112 50.099 ;
     RECT  0.144 49.525 0.408 50.101 ;
     RECT  42.9 46.787 44.184 50.101 ;
     RECT  18.192 49.333 18.912 50.195 ;
     RECT  10.5 49.139 10.812 50.245 ;
     RECT  2.4 49.235 3.432 50.339 ;
     RECT  15.504 47.315 16.488 50.339 ;
     RECT  24 49.043 24.984 50.435 ;
     RECT  29.28 50.005 29.712 50.579 ;
     RECT  40.2 49.043 40.68 50.627 ;
     RECT  45.6 40.883 45.912 50.629 ;
     RECT  5.1 47.269 6.312 50.723 ;
     RECT  31.92 50.051 32.412 50.771 ;
     RECT  10.5 50.245 11.16 50.819 ;
     RECT  21.3 49.909 21.96 50.963 ;
     RECT  26.7 48.419 27.012 51.109 ;
     RECT  12.528 49.381 13.512 51.347 ;
     RECT  34.8 48.467 35.352 51.395 ;
     RECT  45.6 50.629 46.008 51.395 ;
     RECT  29.4 50.579 29.712 51.781 ;
     RECT  13.2 51.347 13.512 51.829 ;
     RECT  20.16 49.475 20.328 51.829 ;
     RECT  21.3 50.963 21.612 51.829 ;
     RECT  18.6 50.195 18.912 51.877 ;
     RECT  26.592 51.109 27.012 51.923 ;
     RECT  37.5 49.043 38.952 51.923 ;
     RECT  15.648 50.339 16.488 52.069 ;
     RECT  10.5 50.819 10.812 52.165 ;
     RECT  32.1 50.771 32.412 52.261 ;
     RECT  42.72 50.101 44.184 52.405 ;
     RECT  3.936 51.541 3.96 52.451 ;
     RECT  42.72 52.405 44.376 52.451 ;
     RECT  18.6 51.877 19.032 52.547 ;
     RECT  9.216 51.829 9.24 52.693 ;
     RECT  9.12 52.693 9.24 52.739 ;
     RECT  15.024 52.069 16.488 52.739 ;
     RECT  20.16 51.829 21.612 52.739 ;
     RECT  42.72 52.451 43.212 52.789 ;
     RECT  28.512 51.781 29.712 52.835 ;
     RECT  5.1 50.723 5.592 52.981 ;
     RECT  24 50.435 24.648 52.981 ;
     RECT  26.7 51.923 27.012 52.981 ;
     RECT  32.1 52.261 32.904 53.075 ;
     RECT  24 52.981 24.888 53.317 ;
     RECT  32.1 53.075 32.412 53.509 ;
     RECT  26.7 52.981 27.336 53.603 ;
     RECT  24 53.317 25.08 53.843 ;
     RECT  26.7 53.603 27.012 53.941 ;
     RECT  13.2 51.829 13.704 54.037 ;
     RECT  15.024 52.739 16.44 54.037 ;
     RECT  29.4 52.835 29.712 54.181 ;
     RECT  7.8 50.099 8.112 54.277 ;
     RECT  9.12 52.739 9.144 54.277 ;
     RECT  7.8 54.277 9.144 54.323 ;
     RECT  13.2 54.037 16.44 54.323 ;
     RECT  24 53.843 24.936 54.467 ;
     RECT  20.16 52.739 20.328 54.469 ;
     RECT  21.3 52.739 21.612 54.469 ;
     RECT  42.192 52.789 43.212 54.613 ;
     RECT  18.6 52.547 18.912 54.661 ;
     RECT  0.144 50.101 0.456 54.707 ;
     RECT  5.1 52.981 5.736 54.707 ;
     RECT  41.808 54.613 43.212 54.851 ;
     RECT  3.84 54.085 3.864 54.899 ;
     RECT  10.272 52.165 10.812 54.899 ;
     RECT  29.088 54.181 29.712 54.995 ;
     RECT  37.5 51.923 37.812 54.997 ;
     RECT  26.544 53.941 27.012 55.141 ;
     RECT  34.8 51.395 35.112 55.141 ;
     RECT  14.544 54.323 16.44 55.331 ;
     RECT  7.8 54.323 8.232 55.477 ;
     RECT  28.176 55.669 28.2 55.811 ;
     RECT  9.312 55.621 9.336 55.859 ;
     RECT  6.864 55.477 8.232 55.907 ;
     RECT  14.784 55.331 16.44 55.907 ;
     RECT  25.632 55.141 27.012 55.907 ;
     RECT  34.8 55.141 35.352 55.907 ;
     RECT  6.864 55.907 8.112 55.955 ;
     RECT  18.24 54.661 18.912 56.003 ;
     RECT  31.968 53.509 32.412 56.293 ;
     RECT  10.368 54.899 10.812 56.341 ;
     RECT  13.2 54.323 13.512 56.389 ;
     RECT  36.528 54.997 37.812 56.435 ;
     RECT  31.68 56.293 33.096 56.437 ;
     RECT  44.352 52.451 44.376 56.437 ;
     RECT  5.1 54.707 5.688 56.483 ;
     RECT  14.784 55.907 16.212 56.483 ;
     RECT  44.352 56.437 44.52 56.483 ;
     RECT  45.6 51.395 45.912 56.677 ;
     RECT  31.488 56.437 33.096 56.725 ;
     RECT  38.928 51.923 38.952 56.965 ;
     RECT  40.2 50.627 40.512 56.965 ;
     RECT  38.928 56.965 40.512 57.011 ;
     RECT  7.8 55.955 8.112 57.157 ;
     RECT  34.8 55.907 35.112 57.445 ;
     RECT  37.392 56.435 37.812 57.445 ;
     RECT  2.4 50.339 2.712 57.589 ;
     RECT  39.312 57.011 40.512 57.731 ;
     RECT  41.808 54.851 41.832 57.875 ;
     RECT  15.168 56.483 16.212 58.021 ;
     RECT  18.6 56.003 18.912 58.117 ;
     RECT  20.16 54.469 21.612 58.117 ;
     RECT  26.544 55.907 27.012 58.643 ;
     RECT  5.1 56.483 5.544 58.645 ;
     RECT  18.6 58.117 21.612 58.645 ;
     RECT  7.8 57.157 8.28 58.691 ;
     RECT  2.4 57.589 3.624 58.739 ;
     RECT  0.144 54.707 0.408 58.931 ;
     RECT  45.6 56.677 46.824 58.931 ;
     RECT  42.9 54.851 43.212 59.029 ;
     RECT  31.488 56.725 33.384 59.219 ;
     RECT  15.168 58.021 16.344 59.315 ;
     RECT  18.6 58.645 22.584 59.315 ;
     RECT  10.32 56.341 10.812 59.555 ;
     RECT  13.104 56.389 13.512 59.749 ;
     RECT  29.4 54.995 29.712 59.749 ;
     RECT  34.8 57.445 35.208 59.843 ;
     RECT  42.768 59.029 43.212 59.845 ;
     RECT  24 54.467 24.648 59.891 ;
     RECT  32.1 59.219 33.384 59.891 ;
     RECT  32.1 59.891 32.412 60.373 ;
     RECT  37.056 57.445 37.812 60.419 ;
     RECT  15.216 59.315 16.344 60.611 ;
     RECT  18.6 59.315 20.328 60.611 ;
     RECT  0.144 58.931 0.36 60.659 ;
     RECT  13.104 59.749 13.896 60.707 ;
     RECT  45.6 58.931 45.912 60.709 ;
     RECT  24 59.891 24.552 60.851 ;
     RECT  39.984 57.731 40.512 60.851 ;
     RECT  42.576 59.845 43.212 60.851 ;
     RECT  5.1 58.645 5.64 61.091 ;
     RECT  20.16 60.611 20.328 61.189 ;
     RECT  21.3 59.315 21.612 61.189 ;
     RECT  29.088 59.749 29.712 61.379 ;
     RECT  2.4 58.739 2.712 61.525 ;
     RECT  0.144 60.659 0.264 61.811 ;
     RECT  42.9 60.851 43.212 62.101 ;
     RECT  2.4 61.525 3.624 62.195 ;
     RECT  24 60.851 24.408 62.291 ;
     RECT  0.24 61.811 0.264 62.387 ;
     RECT  13.104 60.707 13.512 62.581 ;
     RECT  15.216 60.611 16.212 62.581 ;
     RECT  10.5 59.555 10.812 62.629 ;
     RECT  20.16 61.189 21.612 62.675 ;
     RECT  13.104 62.581 16.212 62.723 ;
     RECT  42.48 62.101 43.212 62.725 ;
     RECT  9.12 62.629 9.144 62.771 ;
     RECT  41.76 62.725 43.212 62.867 ;
     RECT  26.7 58.643 27.012 63.157 ;
     RECT  44.496 56.483 44.52 63.253 ;
     RECT  45.504 60.709 45.912 63.253 ;
     RECT  42.768 62.867 43.212 63.347 ;
     RECT  34.8 59.843 35.112 63.685 ;
     RECT  20.16 62.675 20.328 63.781 ;
     RECT  21.3 62.675 21.612 63.781 ;
     RECT  25.872 63.157 27.012 63.781 ;
     RECT  13.104 62.723 14.232 63.827 ;
     RECT  7.8 58.691 8.112 63.829 ;
     RECT  44.496 63.253 45.912 64.019 ;
     RECT  5.1 61.091 5.412 64.165 ;
     RECT  29.4 61.379 29.712 64.357 ;
     RECT  33.888 63.685 35.112 64.403 ;
     RECT  4.752 64.165 5.412 64.405 ;
     RECT  25.872 63.781 27.144 64.451 ;
     RECT  34.8 64.403 35.112 64.597 ;
     RECT  13.104 63.827 13.8 64.885 ;
     RECT  15.216 62.723 16.212 64.885 ;
     RECT  7.44 63.829 8.112 64.933 ;
     RECT  36.432 64.021 36.456 64.981 ;
     RECT  37.5 60.419 37.812 64.981 ;
     RECT  7.44 64.933 8.232 65.027 ;
     RECT  22.896 62.053 22.92 65.075 ;
     RECT  20.16 63.781 21.612 65.125 ;
     RECT  25.872 64.451 27.012 65.125 ;
     RECT  20.016 65.125 21.612 65.171 ;
     RECT  25.68 65.125 27.012 65.171 ;
     RECT  34.8 64.597 35.304 65.365 ;
     RECT  36.432 64.981 37.812 65.365 ;
     RECT  31.632 60.373 32.412 65.555 ;
     RECT  4.752 64.405 5.688 65.651 ;
     RECT  34.8 65.365 37.812 65.651 ;
     RECT  25.68 65.171 25.704 66.181 ;
     RECT  26.7 65.171 27.012 66.181 ;
     RECT  25.68 66.181 27.012 66.419 ;
     RECT  41.76 62.867 41.784 66.613 ;
     RECT  42.9 63.347 43.212 66.613 ;
     RECT  10.368 62.629 10.812 66.661 ;
     RECT  44.496 64.019 44.52 66.661 ;
     RECT  45.6 64.019 45.912 66.661 ;
     RECT  4.752 65.651 5.412 66.709 ;
     RECT  10.224 66.661 10.812 66.805 ;
     RECT  13.104 64.885 16.212 66.851 ;
     RECT  44.496 66.661 45.912 67.139 ;
     RECT  40.2 60.851 40.512 67.141 ;
     RECT  7.8 65.027 8.232 67.187 ;
     RECT  32.1 65.555 32.412 67.237 ;
     RECT  13.104 66.851 14.76 67.283 ;
     RECT  41.76 66.613 43.212 67.427 ;
     RECT  13.104 67.283 13.8 67.523 ;
     RECT  20.016 65.171 20.328 67.523 ;
     RECT  25.68 66.419 25.704 67.523 ;
     RECT  24 62.291 24.312 67.525 ;
     RECT  28.032 66.085 28.056 67.571 ;
     RECT  4.56 66.709 5.412 67.619 ;
     RECT  45.6 67.139 45.912 67.669 ;
     RECT  44.496 67.139 44.52 67.715 ;
     RECT  4.752 67.619 5.412 67.955 ;
     RECT  34.8 65.651 36.456 68.099 ;
     RECT  40.08 67.141 40.512 68.243 ;
     RECT  13.104 67.523 13.704 68.293 ;
     RECT  15.744 66.851 16.212 68.341 ;
     RECT  31.632 67.237 32.412 68.387 ;
     RECT  13.056 68.293 13.704 68.627 ;
     RECT  29.4 64.357 30.264 68.627 ;
     RECT  13.056 68.627 13.512 68.821 ;
     RECT  9.696 66.805 10.812 68.869 ;
     RECT  41.76 67.427 41.784 68.915 ;
     RECT  26.7 66.419 27.012 68.917 ;
     RECT  12.96 68.821 13.512 68.963 ;
     RECT  9.696 68.869 11.4 69.011 ;
     RECT  34.8 68.099 36.264 69.203 ;
     RECT  45.6 67.669 46.152 69.349 ;
     RECT  5.1 67.955 5.412 69.445 ;
     RECT  34.8 69.203 35.112 69.493 ;
     RECT  13.056 68.963 13.512 69.587 ;
     RECT  24 67.525 24.504 69.587 ;
     RECT  31.872 68.387 32.412 69.587 ;
     RECT  45.6 69.349 46.68 70.019 ;
     RECT  25.776 68.917 27.012 70.067 ;
     RECT  5.1 69.445 5.928 70.211 ;
     RECT  15.408 68.341 16.212 70.259 ;
     RECT  34.56 69.493 35.112 70.259 ;
     RECT  13.104 69.587 13.512 70.307 ;
     RECT  42.768 67.427 43.212 70.549 ;
     RECT  42.432 70.549 43.212 70.693 ;
     RECT  18.6 60.611 18.912 70.933 ;
     RECT  20.16 67.523 20.328 70.933 ;
     RECT  37.5 65.651 37.812 70.981 ;
     RECT  18.6 70.933 20.328 71.077 ;
     RECT  7.8 67.187 8.112 71.221 ;
     RECT  15.744 70.259 16.212 71.221 ;
     RECT  34.8 70.259 35.112 71.221 ;
     RECT  36.24 69.203 36.264 71.221 ;
     RECT  45.6 70.019 46.152 71.267 ;
     RECT  13.2 70.307 13.512 71.509 ;
     RECT  24 69.587 24.312 71.557 ;
     RECT  2.4 62.195 2.712 71.653 ;
     RECT  24 71.557 24.456 71.699 ;
     RECT  26.7 70.067 27.012 71.701 ;
     RECT  0.24 71.749 0.264 71.939 ;
     RECT  18 71.077 20.328 71.939 ;
     RECT  42.432 70.693 43.656 72.179 ;
     RECT  2.4 71.653 2.808 72.325 ;
     RECT  37.5 70.981 38.232 72.371 ;
     RECT  15.744 71.221 16.344 72.419 ;
     RECT  2.4 72.325 3.672 72.515 ;
     RECT  26.7 71.701 27.336 72.707 ;
     RECT  42.432 72.179 43.212 72.707 ;
     RECT  40.2 68.243 40.512 72.709 ;
     RECT  18.6 71.939 20.328 72.901 ;
     RECT  21.3 65.171 21.612 72.901 ;
     RECT  24 71.699 24.312 72.901 ;
     RECT  26.7 72.707 27.144 72.949 ;
     RECT  25.92 72.949 27.144 73.091 ;
     RECT  7.8 71.221 8.568 73.141 ;
     RECT  15.744 72.419 16.212 73.237 ;
     RECT  6.864 73.141 8.568 73.283 ;
     RECT  18.6 72.901 21.612 73.427 ;
     RECT  7.8 73.283 8.568 73.477 ;
     RECT  9.696 69.011 10.812 73.477 ;
     RECT  40.2 72.709 40.872 73.763 ;
     RECT  3.792 73.525 3.816 73.765 ;
     RECT  5.1 70.211 5.412 73.765 ;
     RECT  25.92 73.091 27.012 74.003 ;
     RECT  7.8 73.477 10.812 74.387 ;
     RECT  3.792 73.765 5.412 74.579 ;
     RECT  40.2 73.763 40.824 74.581 ;
     RECT  34.8 71.221 36.264 74.629 ;
     RECT  37.5 72.371 37.812 74.629 ;
     RECT  13.2 71.509 14.232 75.157 ;
     RECT  6.384 75.061 6.408 75.251 ;
     RECT  4.512 74.579 5.412 75.299 ;
     RECT  13.104 75.157 14.232 75.299 ;
     RECT  15.408 73.237 16.212 75.349 ;
     RECT  34.8 74.629 37.812 75.443 ;
     RECT  14.976 75.349 16.212 75.539 ;
     RECT  4.752 75.299 5.412 75.637 ;
     RECT  2.4 72.515 2.712 75.685 ;
     RECT  24 72.901 24.408 75.685 ;
     RECT  7.8 74.387 8.856 75.733 ;
     RECT  29.4 68.627 29.712 75.781 ;
     RECT  31.104 72.565 31.128 75.781 ;
     RECT  45.6 71.267 46.008 75.781 ;
     RECT  4.752 75.637 6.216 75.827 ;
     RECT  10.032 74.387 10.812 75.923 ;
     RECT  36.432 75.443 37.812 75.923 ;
     RECT  40.08 74.581 40.824 76.259 ;
     RECT  45.6 75.781 46.728 76.357 ;
     RECT  25.632 74.821 25.656 76.403 ;
     RECT  7.296 75.733 8.856 76.451 ;
     RECT  20.16 73.427 21.612 76.499 ;
     RECT  29.4 75.781 31.128 76.739 ;
     RECT  36.624 75.923 37.812 76.739 ;
     RECT  15.408 75.539 16.212 76.741 ;
     RECT  18.6 73.427 18.912 76.741 ;
     RECT  23.328 75.685 24.408 76.979 ;
     RECT  34.8 75.443 35.448 76.979 ;
     RECT  40.2 76.259 40.824 76.979 ;
     RECT  45.504 76.357 46.728 76.979 ;
     RECT  29.4 76.739 30.216 77.029 ;
     RECT  18.6 76.741 19.032 77.075 ;
     RECT  29.28 77.029 30.216 77.075 ;
     RECT  4.752 75.827 5.412 77.219 ;
     RECT  33.648 75.493 33.672 77.267 ;
     RECT  13.104 75.299 13.608 77.269 ;
     RECT  13.104 77.269 13.704 77.315 ;
     RECT  45.504 76.979 45.912 77.315 ;
     RECT  4.08 77.221 4.104 77.411 ;
     RECT  7.296 76.451 8.112 77.507 ;
     RECT  23.328 76.979 24.312 77.507 ;
     RECT  2.4 75.685 2.808 77.555 ;
     RECT  15.408 76.741 16.344 77.795 ;
     RECT  10.5 75.923 10.812 77.989 ;
     RECT  32.1 69.587 32.412 77.989 ;
     RECT  5.1 77.219 5.412 78.037 ;
     RECT  29.28 77.075 29.712 78.037 ;
     RECT  18.6 77.075 18.912 78.085 ;
     RECT  20.16 76.499 20.328 78.131 ;
     RECT  20.16 78.131 20.232 78.179 ;
     RECT  38.784 75.781 38.808 78.275 ;
     RECT  15.744 77.795 16.344 78.467 ;
     RECT  15.9 78.467 16.344 78.517 ;
     RECT  10.5 77.989 10.92 78.611 ;
     RECT  25.68 77.461 25.704 78.803 ;
     RECT  5.1 78.037 5.736 78.899 ;
     RECT  1.152 78.661 1.176 78.947 ;
     RECT  18.6 78.085 19.08 79.187 ;
     RECT  29.088 78.037 29.712 79.235 ;
     RECT  31.584 77.989 32.412 79.235 ;
     RECT  36.192 77.317 36.216 79.235 ;
     RECT  20.208 78.179 20.232 79.283 ;
     RECT  13.2 77.315 13.704 79.475 ;
     RECT  15.9 78.517 16.392 79.475 ;
     RECT  2.4 77.555 2.712 79.929 ;
     RECT  5.1 78.899 5.412 79.929 ;
     RECT  7.8 77.507 8.112 79.929 ;
     RECT  10.5 78.611 10.812 79.929 ;
     RECT  13.2 79.475 13.512 79.929 ;
     RECT  15.9 79.475 16.212 79.929 ;
     RECT  18.6 79.187 18.912 79.929 ;
     RECT  21.3 76.499 21.612 79.929 ;
     RECT  24 77.507 24.312 79.929 ;
     RECT  26.7 74.003 27.012 79.929 ;
     RECT  29.4 79.235 29.712 79.929 ;
     RECT  32.1 79.235 32.412 79.929 ;
     RECT  34.8 76.979 35.112 79.929 ;
     RECT  37.5 76.739 37.812 79.929 ;
     RECT  40.2 76.979 40.512 79.929 ;
     RECT  42.9 72.707 43.212 79.929 ;
     RECT  45.6 77.315 45.912 79.929 ;
     RECT  48.3 46.259 48.612 79.929 ;
     RECT  2.4 79.929 2.52 79.943 ;
     RECT  5.1 79.929 5.22 79.943 ;
     RECT  7.8 79.929 7.92 79.943 ;
     RECT  10.5 79.929 10.62 79.943 ;
     RECT  13.2 79.929 13.32 79.943 ;
     RECT  15.9 79.929 16.02 79.943 ;
     RECT  18.6 79.929 18.72 79.943 ;
     RECT  21.3 79.929 21.42 79.943 ;
     RECT  24 79.929 24.12 79.943 ;
     RECT  26.7 79.929 26.82 79.943 ;
     RECT  29.4 79.929 29.52 79.943 ;
     RECT  32.1 79.929 32.22 79.943 ;
     RECT  34.8 79.929 34.92 79.943 ;
     RECT  37.5 79.929 37.62 79.943 ;
     RECT  40.2 79.929 40.32 79.943 ;
     RECT  42.9 79.929 43.02 79.943 ;
     RECT  45.6 79.929 45.72 79.943 ;
     RECT  48.3 79.929 48.42 79.943 ;
     RECT  22.824 2.341 24 2.579 ;
     RECT  22.008 2.579 24 2.821 ;
     RECT  22.008 2.821 23.472 4.115 ;
     RECT  25.032 2.821 26.112 4.355 ;
     RECT  32.412 2.821 33.6 4.355 ;
     RECT  33.624 2.821 34.8 4.355 ;
     RECT  37.812 2.821 39.072 3.251 ;
     RECT  39.096 2.821 40.2 3.205 ;
     RECT  40.512 2.965 41.904 4.643 ;
     RECT  19.032 3.059 19.08 4.453 ;
     RECT  8.112 3.397 9.408 4.643 ;
     RECT  9.432 3.397 10.5 4.643 ;
     RECT  41.928 4.019 42.9 4.643 ;
     RECT  17.16 4.021 18.6 4.163 ;
     RECT  2.712 4.259 2.808 5.077 ;
     RECT  8.112 4.643 10.5 5.701 ;
     RECT  40.512 4.643 40.632 5.461 ;
     RECT  2.712 5.077 3.984 6.995 ;
     RECT  4.008 5.077 5.1 6.995 ;
     RECT  18.912 5.507 19.08 6.709 ;
     RECT  8.112 5.701 9.12 6.661 ;
     RECT  9.144 5.701 10.5 6.899 ;
     RECT  25.032 6.229 26.208 7.333 ;
     RECT  35.112 6.229 36.336 6.469 ;
     RECT  0.192 6.659 0.24 7.957 ;
     RECT  19.608 6.709 20.928 8.485 ;
     RECT  36.36 6.803 37.5 6.947 ;
     RECT  8.856 6.899 10.5 7.909 ;
     RECT  36.216 6.947 37.5 13.091 ;
     RECT  2.712 6.995 3.096 7.765 ;
     RECT  25.704 7.379 26.7 8.437 ;
     RECT  13.848 7.765 15.36 8.387 ;
     RECT  9.288 7.909 10.5 9.397 ;
     RECT  22.008 8.627 22.248 9.109 ;
     RECT  6.312 8.677 7.632 9.155 ;
     RECT  11.832 8.869 13.2 11.411 ;
     RECT  22.008 9.109 23.232 11.987 ;
     RECT  5.592 9.155 7.632 9.589 ;
     RECT  35.112 9.155 36.192 13.045 ;
     RECT  25.032 9.203 26.064 10.355 ;
     RECT  5.592 9.589 6.672 10.835 ;
     RECT  38.232 9.637 39.6 9.731 ;
     RECT  10.812 9.827 11.808 11.411 ;
     RECT  5.592 10.835 7.632 11.459 ;
     RECT  10.812 11.411 11.16 12.517 ;
     RECT  5.412 11.459 7.632 11.941 ;
     RECT  37.812 11.459 38.232 12.901 ;
     RECT  3.624 11.941 5.1 13.523 ;
     RECT  5.412 11.941 6.48 14.339 ;
     RECT  6.504 11.941 7.632 13.907 ;
     RECT  25.608 12.517 26.7 13.139 ;
     RECT  46.248 12.517 47.232 13.283 ;
     RECT  47.256 12.517 48.3 13.283 ;
     RECT  37.812 12.901 38.832 13.859 ;
     RECT  38.856 12.901 40.2 13.573 ;
     RECT  36.072 13.091 37.5 13.573 ;
     RECT  16.212 13.139 16.584 13.333 ;
     RECT  25.512 13.139 26.7 14.197 ;
     RECT  16.212 13.333 17.664 15.347 ;
     RECT  2.712 13.523 2.856 14.725 ;
     RECT  36.072 13.573 37.152 14.867 ;
     RECT  22.008 13.621 23.328 15.443 ;
     RECT  37.812 13.859 39.312 14.675 ;
     RECT  6.504 13.907 7.8 14.339 ;
     RECT  25.704 14.197 26.7 15.445 ;
     RECT  30.792 14.197 32.1 14.533 ;
     RECT  5.412 14.339 5.64 14.917 ;
     RECT  29.712 14.339 30.768 16.499 ;
     RECT  20.136 14.677 21.3 15.061 ;
     RECT  40.68 14.821 42.192 15.013 ;
     RECT  36.072 14.867 37.5 16.549 ;
     RECT  8.856 14.917 10.368 16.019 ;
     RECT  40.728 15.013 42.192 16.595 ;
     RECT  30.792 15.107 32.1 16.357 ;
     RECT  13.848 15.301 15.072 16.115 ;
     RECT  2.712 15.731 2.856 16.357 ;
     RECT  8.856 16.019 10.5 16.261 ;
     RECT  13.512 16.115 15.072 16.165 ;
     RECT  13.512 16.165 14.784 17.699 ;
     RECT  9.144 16.261 10.5 17.077 ;
     RECT  2.712 16.357 3.936 16.691 ;
     RECT  3.96 16.357 5.1 16.691 ;
     RECT  30.84 16.357 32.1 17.267 ;
     RECT  29.712 16.499 30.816 16.501 ;
     RECT  29.832 16.501 30.816 17.267 ;
     RECT  18.912 16.595 20.16 18.851 ;
     RECT  2.712 16.691 5.1 16.789 ;
     RECT  2.712 16.789 3.792 19.235 ;
     RECT  3.816 16.789 5.1 18.517 ;
     RECT  17.112 16.981 18.6 17.123 ;
     RECT  9.384 17.077 10.5 18.179 ;
     RECT  46.344 17.077 47.856 17.123 ;
     RECT  29.832 17.267 32.1 17.413 ;
     RECT  29.832 17.413 31.152 19.427 ;
     RECT  5.412 17.605 6.576 18.275 ;
     RECT  6.6 17.605 7.8 18.133 ;
     RECT  25.032 18.083 26.208 19.427 ;
     RECT  8.856 18.179 10.5 19.333 ;
     RECT  3.96 18.517 5.1 18.803 ;
     RECT  35.112 18.563 35.496 18.757 ;
     RECT  35.112 18.757 36.336 20.579 ;
     RECT  36.36 18.757 37.5 20.579 ;
     RECT  3.816 18.803 5.1 19.235 ;
     RECT  37.812 18.995 38.232 19.093 ;
     RECT  37.812 19.093 39.312 20.003 ;
     RECT  9.48 19.333 10.5 19.955 ;
     RECT  16.212 19.333 17.616 21.155 ;
     RECT  29.712 19.427 31.152 20.149 ;
     RECT  37.812 20.003 40.2 20.965 ;
     RECT  29.712 20.149 30.816 21.107 ;
     RECT  47.16 20.149 48.3 20.915 ;
     RECT  27.576 20.197 28.944 21.251 ;
     RECT  32.412 20.245 33.648 21.203 ;
     RECT  33.672 20.291 34.8 21.203 ;
     RECT  37.056 20.579 37.5 21.445 ;
     RECT  37.812 20.965 38.832 21.203 ;
     RECT  38.856 20.965 40.2 21.203 ;
     RECT  29.712 21.107 31.152 21.635 ;
     RECT  37.812 21.203 38.088 21.205 ;
     RECT  29.712 21.635 31.92 23.029 ;
     RECT  35.112 22.165 36.24 22.213 ;
     RECT  29.976 23.029 31.92 23.077 ;
     RECT  30.696 23.077 31.92 24.469 ;
     RECT  36.264 23.411 37.5 24.563 ;
     RECT  19.032 23.797 20.496 23.987 ;
     RECT  14.52 23.893 15.648 23.939 ;
     RECT  14.52 23.939 15.9 24.659 ;
     RECT  38.76 23.941 40.032 25.139 ;
     RECT  25.032 24.373 26.256 26.483 ;
     RECT  30.84 24.469 31.92 25.333 ;
     RECT  35.976 24.563 37.5 24.659 ;
     RECT  14.424 24.659 15.9 29.509 ;
     RECT  38.76 25.139 40.2 29.509 ;
     RECT  8.952 25.621 10.272 25.667 ;
     RECT  19.032 25.669 20.496 26.485 ;
     RECT  19.032 26.485 20.304 26.819 ;
     RECT  20.328 26.675 21.3 34.117 ;
     RECT  18.912 26.819 20.304 27.781 ;
     RECT  35.112 27.971 35.88 28.453 ;
     RECT  5.412 28.115 5.928 28.597 ;
     RECT  32.412 28.309 33.84 29.267 ;
     RECT  18.912 28.451 20.112 30.181 ;
     RECT  35.112 28.453 36.384 30.899 ;
     RECT  36.408 28.453 37.5 29.509 ;
     RECT  5.412 28.597 6.912 28.739 ;
     RECT  5.412 28.739 6.072 29.365 ;
     RECT  30.6 29.123 31.92 31.379 ;
     RECT  14.424 29.509 15.648 29.555 ;
     RECT  36.456 29.509 37.5 30.803 ;
     RECT  38.76 29.509 40.08 29.891 ;
     RECT  15.6 29.555 15.648 29.941 ;
     RECT  38.664 29.891 40.08 31.379 ;
     RECT  18.912 30.181 19.968 30.803 ;
     RECT  44.472 30.757 45.6 32.195 ;
     RECT  18.912 30.803 20.16 33.445 ;
     RECT  36.408 30.803 37.5 30.899 ;
     RECT  13.104 31.283 13.2 32.773 ;
     RECT  8.28 32.485 9.6 33.059 ;
     RECT  16.968 32.485 18.432 35.411 ;
     RECT  35.112 33.013 36.528 34.499 ;
     RECT  8.28 33.059 10.5 33.445 ;
     RECT  9.144 33.445 10.5 34.355 ;
     RECT  19.032 33.445 20.16 35.315 ;
     RECT  38.664 33.493 40.032 34.117 ;
     RECT  4.512 33.731 5.1 34.933 ;
     RECT  27.336 34.117 28.512 34.403 ;
     RECT  38.664 34.117 39.84 35.411 ;
     RECT  27.192 34.403 28.512 34.835 ;
     RECT  13.512 34.789 14.784 35.939 ;
     RECT  18.912 35.315 20.16 37.861 ;
     RECT  27.144 36.035 27.192 37.477 ;
     RECT  32.412 36.419 32.52 36.949 ;
     RECT  29.712 36.421 30.816 37.235 ;
     RECT  30.84 36.421 31.824 37.235 ;
     RECT  32.412 36.949 33.792 38.915 ;
     RECT  33.816 36.949 34.8 38.915 ;
     RECT  29.712 37.235 29.832 38.101 ;
     RECT  31.68 37.235 31.824 37.573 ;
     RECT  37.056 37.235 37.5 37.429 ;
     RECT  35.88 37.429 37.5 38.677 ;
     RECT  22.632 37.573 24 37.765 ;
     RECT  22.632 37.765 23.616 38.675 ;
     RECT  6.312 37.861 7.8 38.819 ;
     RECT  8.28 38.101 9.696 39.203 ;
     RECT  10.812 38.389 11.952 38.915 ;
     RECT  11.976 38.389 13.2 38.915 ;
     RECT  25.032 38.533 26.208 40.355 ;
     RECT  22.152 38.675 23.616 38.819 ;
     RECT  36.072 38.677 37.5 39.923 ;
     RECT  39.192 38.677 40.2 41.651 ;
     RECT  18.912 38.723 20.16 47.125 ;
     RECT  22.152 38.819 24 40.165 ;
     RECT  8.232 39.203 9.696 40.115 ;
     RECT  29.712 39.491 29.832 39.637 ;
     RECT  29.712 39.637 30.912 41.077 ;
     RECT  30.936 39.923 32.1 41.651 ;
     RECT  22.152 40.165 23.328 41.651 ;
     RECT  24.648 40.355 26.208 40.405 ;
     RECT  24.648 40.405 25.824 41.651 ;
     RECT  20.328 41.075 21.3 43.189 ;
     RECT  29.712 41.077 30.72 41.411 ;
     RECT  27.012 41.173 28.032 41.507 ;
     RECT  28.056 41.173 29.4 41.507 ;
     RECT  29.712 41.411 30.912 41.651 ;
     RECT  29.184 41.507 29.4 42.709 ;
     RECT  13.512 41.651 13.656 42.613 ;
     RECT  35.112 41.651 35.208 41.989 ;
     RECT  38.808 41.651 40.2 43.093 ;
     RECT  35.112 41.989 36.624 44.483 ;
     RECT  5.412 42.133 6.864 42.995 ;
     RECT  16.488 42.613 17.808 46.211 ;
     RECT  44.184 42.997 45.6 52.405 ;
     RECT  38.808 43.093 40.08 43.763 ;
     RECT  38.712 43.763 40.08 44.389 ;
     RECT  8.904 44.245 10.368 44.435 ;
     RECT  38.712 44.389 39.936 44.725 ;
     RECT  8.112 44.435 10.368 45.157 ;
     RECT  35.112 44.483 37.5 44.965 ;
     RECT  38.856 44.725 39.936 44.965 ;
     RECT  6.312 44.773 7.8 46.211 ;
     RECT  35.112 44.965 36.432 46.211 ;
     RECT  36.456 44.965 37.5 46.211 ;
     RECT  8.112 45.157 9.936 45.205 ;
     RECT  8.112 45.205 9.6 46.693 ;
     RECT  45.912 45.589 47.424 46.259 ;
     RECT  5.688 46.211 7.8 47.269 ;
     RECT  38.952 46.211 40.2 56.965 ;
     RECT  34.608 46.259 34.8 47.749 ;
     RECT  22.152 46.501 23.136 47.987 ;
     RECT  13.104 46.547 13.2 47.893 ;
     RECT  8.232 46.693 9.6 47.075 ;
     RECT  0.216 46.835 0.264 48.133 ;
     RECT  8.232 47.075 9.936 47.459 ;
     RECT  19.032 47.125 20.16 48.419 ;
     RECT  2.712 47.221 3.936 48.997 ;
     RECT  3.96 47.221 5.1 49.043 ;
     RECT  6.312 47.269 7.8 48.805 ;
     RECT  9.696 47.459 9.936 48.085 ;
     RECT  25.08 47.747 26.208 48.419 ;
     RECT  21.612 47.987 23.136 48.037 ;
     RECT  21.612 48.037 22.8 48.947 ;
     RECT  22.824 48.083 24 48.947 ;
     RECT  18.912 48.419 20.16 51.877 ;
     RECT  25.08 48.419 26.7 48.757 ;
     RECT  25.272 48.757 26.7 49.043 ;
     RECT  35.352 48.757 36.864 49.043 ;
     RECT  6.312 48.805 7.68 50.099 ;
     RECT  21.612 48.947 21.96 49.909 ;
     RECT  29.28 49.043 29.4 50.005 ;
     RECT  9.696 49.139 10.5 49.237 ;
     RECT  8.112 49.237 9.12 49.523 ;
     RECT  9.144 49.237 10.5 49.523 ;
     RECT  20.328 49.475 21.3 51.829 ;
     RECT  6.312 50.099 7.8 50.723 ;
     RECT  11.16 50.245 12.528 50.819 ;
     RECT  2.712 50.339 3.432 51.541 ;
     RECT  29.28 50.579 29.4 51.781 ;
     RECT  2.712 51.541 3.936 52.451 ;
     RECT  3.96 51.541 5.1 52.451 ;
     RECT  27.012 51.781 28.512 52.835 ;
     RECT  8.112 51.829 9.216 52.693 ;
     RECT  9.24 51.829 10.5 52.165 ;
     RECT  19.032 51.877 20.16 52.547 ;
     RECT  37.812 51.923 38.928 57.011 ;
     RECT  13.704 52.069 15.024 54.037 ;
     RECT  9.24 52.165 10.272 52.739 ;
     RECT  44.376 52.405 45.6 56.437 ;
     RECT  43.212 52.451 44.352 56.483 ;
     RECT  18.912 52.547 20.16 58.117 ;
     RECT  8.112 52.693 9.12 54.277 ;
     RECT  9.144 52.739 10.272 54.323 ;
     RECT  20.328 52.739 21.3 54.469 ;
     RECT  27.012 52.835 27.336 52.981 ;
     RECT  29.088 52.835 29.4 54.181 ;
     RECT  24.936 53.843 25.08 53.941 ;
     RECT  24.936 53.941 26.544 54.467 ;
     RECT  2.712 54.085 3.84 54.899 ;
     RECT  3.864 54.085 5.1 54.899 ;
     RECT  8.232 54.323 10.272 54.899 ;
     RECT  13.512 54.323 14.544 55.331 ;
     RECT  24.648 54.467 26.544 55.141 ;
     RECT  40.512 54.613 41.808 57.875 ;
     RECT  5.688 54.707 5.736 55.477 ;
     RECT  41.832 54.851 42.9 57.875 ;
     RECT  8.232 54.899 10.368 55.621 ;
     RECT  29.088 54.995 29.4 55.669 ;
     RECT  35.112 54.997 36.528 55.141 ;
     RECT  24.648 55.141 25.632 55.907 ;
     RECT  35.352 55.141 36.528 55.907 ;
     RECT  13.512 55.331 14.784 56.483 ;
     RECT  5.688 55.477 6.864 55.955 ;
     RECT  8.232 55.621 9.312 55.859 ;
     RECT  9.336 55.621 10.368 55.859 ;
     RECT  27.012 55.669 28.176 55.811 ;
     RECT  28.2 55.669 29.4 55.811 ;
     RECT  8.232 55.859 8.28 55.907 ;
     RECT  10.32 55.859 10.368 56.341 ;
     RECT  8.112 55.907 8.28 57.157 ;
     RECT  35.112 55.907 36.528 56.435 ;
     RECT  35.112 56.435 35.208 57.445 ;
     RECT  37.056 56.435 37.392 57.445 ;
     RECT  44.52 56.437 45.6 60.709 ;
     RECT  43.212 56.483 44.496 67.715 ;
     RECT  46.824 56.677 48.3 58.931 ;
     RECT  33.384 56.725 34.8 59.891 ;
     RECT  37.812 57.011 39.312 57.731 ;
     RECT  3.624 57.589 5.1 58.739 ;
     RECT  42.768 57.875 42.9 59.029 ;
     RECT  22.584 58.645 24 59.315 ;
     RECT  31.632 59.219 32.1 60.373 ;
     RECT  15.168 59.315 15.216 59.749 ;
     RECT  20.328 59.315 21.3 61.189 ;
     RECT  13.896 59.749 15.216 60.707 ;
     RECT  18.912 60.611 20.16 65.125 ;
     RECT  44.52 60.709 45.504 63.253 ;
     RECT  42.576 60.851 42.9 62.101 ;
     RECT  3.624 61.525 5.1 62.195 ;
     RECT  21.612 62.053 22.896 65.075 ;
     RECT  22.92 62.053 24 65.075 ;
     RECT  8.112 62.629 9.12 62.771 ;
     RECT  9.144 62.629 10.368 62.771 ;
     RECT  20.328 62.675 21.3 63.781 ;
     RECT  14.232 62.723 15.216 63.827 ;
     RECT  40.512 62.725 41.76 68.915 ;
     RECT  41.784 62.867 42.768 63.347 ;
     RECT  41.784 63.347 42.9 66.613 ;
     RECT  32.412 63.685 33.888 64.403 ;
     RECT  13.8 63.827 15.216 64.885 ;
     RECT  44.52 64.019 45.6 66.661 ;
     RECT  35.112 64.021 36.432 64.597 ;
     RECT  36.456 64.021 37.5 64.981 ;
     RECT  30.264 64.357 31.632 65.555 ;
     RECT  35.304 64.597 36.432 65.365 ;
     RECT  18.912 65.125 20.016 67.523 ;
     RECT  24.312 65.125 25.68 67.523 ;
     RECT  20.328 65.171 21.3 72.901 ;
     RECT  25.704 65.171 26.7 66.181 ;
     RECT  36.456 65.651 37.5 68.099 ;
     RECT  27.012 66.085 28.032 67.571 ;
     RECT  28.056 66.085 29.4 67.571 ;
     RECT  25.704 66.419 26.7 67.523 ;
     RECT  8.232 66.805 9.696 67.187 ;
     RECT  14.76 66.851 15.744 67.283 ;
     RECT  44.52 67.139 45.6 67.715 ;
     RECT  30.264 67.237 31.632 68.387 ;
     RECT  15.408 67.283 15.744 68.341 ;
     RECT  41.784 67.427 42.768 68.915 ;
     RECT  18.912 67.523 20.16 70.933 ;
     RECT  24.312 67.523 26.7 67.525 ;
     RECT  24.504 67.525 26.7 68.917 ;
     RECT  36.264 68.099 37.5 74.629 ;
     RECT  24.504 68.917 25.776 69.587 ;
     RECT  35.112 69.203 36.24 71.221 ;
     RECT  24.312 69.587 25.776 70.067 ;
     RECT  24.312 70.067 24.456 71.557 ;
     RECT  15.408 70.259 15.744 71.509 ;
     RECT  8.568 71.221 9.696 73.477 ;
     RECT  14.232 71.509 15.744 73.237 ;
     RECT  24.312 71.699 24.456 72.901 ;
     RECT  3.672 72.325 5.1 72.515 ;
     RECT  2.712 72.515 5.1 73.525 ;
     RECT  29.712 72.565 31.104 75.781 ;
     RECT  31.128 72.565 32.1 76.739 ;
     RECT  24.408 72.901 24.456 72.949 ;
     RECT  24.408 72.949 25.92 74.003 ;
     RECT  5.412 73.141 6.864 73.283 ;
     RECT  14.232 73.237 15.408 75.299 ;
     RECT  18.912 73.427 20.16 76.741 ;
     RECT  2.712 73.525 3.792 74.579 ;
     RECT  3.816 73.525 5.1 73.765 ;
     RECT  24.408 74.003 26.7 74.821 ;
     RECT  8.856 74.387 10.032 75.923 ;
     RECT  2.712 74.579 2.808 75.685 ;
     RECT  24.408 74.821 25.632 76.403 ;
     RECT  25.656 74.821 26.7 76.403 ;
     RECT  5.412 75.061 6.384 75.251 ;
     RECT  6.408 75.061 7.8 75.251 ;
     RECT  5.412 75.251 7.8 75.637 ;
     RECT  13.608 75.299 15.408 75.349 ;
     RECT  13.608 75.349 14.976 75.539 ;
     RECT  35.448 75.443 36.432 75.923 ;
     RECT  32.412 75.493 33.648 77.267 ;
     RECT  33.672 75.493 34.8 77.267 ;
     RECT  6.216 75.637 7.8 75.733 ;
     RECT  6.216 75.733 7.296 75.827 ;
     RECT  37.812 75.781 38.784 78.275 ;
     RECT  38.808 75.781 40.08 76.259 ;
     RECT  35.448 75.923 36.624 76.739 ;
     RECT  38.808 76.259 40.2 78.275 ;
     RECT  24.408 76.403 26.7 76.979 ;
     RECT  20.328 76.499 21.3 78.131 ;
     RECT  30.216 76.739 32.1 77.075 ;
     RECT  35.448 76.739 37.5 76.979 ;
     RECT  19.032 76.741 20.16 77.075 ;
     RECT  24.312 76.979 26.7 77.461 ;
     RECT  35.112 76.979 37.5 77.317 ;
     RECT  18.912 77.075 20.16 78.085 ;
     RECT  31.584 77.075 32.1 77.989 ;
     RECT  4.752 77.219 5.1 77.221 ;
     RECT  2.808 77.221 4.08 77.411 ;
     RECT  4.104 77.221 5.1 77.411 ;
     RECT  35.112 77.317 36.192 79.235 ;
     RECT  36.216 77.317 37.5 79.235 ;
     RECT  24.312 77.461 25.68 78.803 ;
     RECT  25.704 77.461 26.7 78.803 ;
     RECT  19.08 78.085 20.16 78.179 ;
     RECT  20.232 78.131 21.3 79.283 ;
     RECT  19.08 78.179 20.208 79.187 ;
     RECT  1.176 78.661 2.4 78.947 ;
     RECT  18.912 79.187 20.208 79.283 ;
  END
END qkd_landsh0_528
END LIBRARY
